VERSION 5.8 ;
BUSBITCHARS "[]" ;
DIVIDERCHAR "/" ;
UNITS
    DATABASE MICRONS 1000 ;
END UNITS

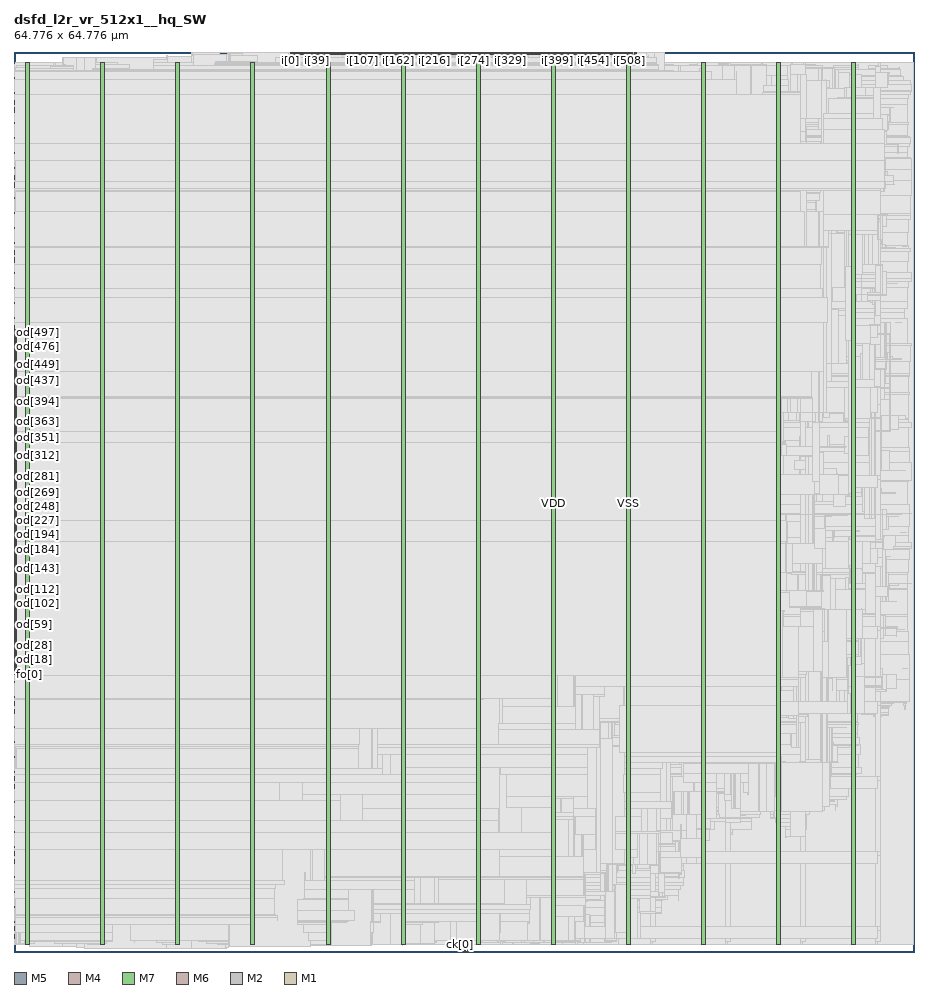
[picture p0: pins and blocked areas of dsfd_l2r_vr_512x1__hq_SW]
MACRO dsfd_l2r_vr_512x1__hq_SW
  FOREIGN dsfd_l2r_vr_512x1__hq_SW 0 0 ;
  CLASS BLOCK ;
  SIZE 64.776 BY 64.776 ;
  PIN ck[0]
    DIRECTION INPUT ;
    USE SIGNAL ;
    PORT
      LAYER M5 ;
        RECT  32.064 0 32.088 0.192 ;
    END
  END ck[0]
  PIN cks[0]
    DIRECTION INPUT ;
    USE SIGNAL ;
    PORT
      LAYER M5 ;
        RECT  32.256 0 32.28 0.192 ;
    END
  END cks[0]
  PIN fo[0]
    DIRECTION OUTPUT ;
    USE SIGNAL ;
    PORT
      LAYER M4 ;
        RECT  0 19.968 0.192 19.992 ;
    END
  END fo[0]
  PIN i[0]
    DIRECTION INPUT ;
    USE SIGNAL ;
    PORT
      LAYER M5 ;
        RECT  19.92 64.584 19.944 64.776 ;
    END
  END i[0]
  PIN i[100]
    DIRECTION INPUT ;
    USE SIGNAL ;
    PORT
      LAYER M5 ;
        RECT  24.72 64.584 24.744 64.776 ;
    END
  END i[100]
  PIN i[101]
    DIRECTION INPUT ;
    USE SIGNAL ;
    PORT
      LAYER M5 ;
        RECT  24.768 64.584 24.792 64.776 ;
    END
  END i[101]
  PIN i[102]
    DIRECTION INPUT ;
    USE SIGNAL ;
    PORT
      LAYER M5 ;
        RECT  24.816 64.584 24.84 64.776 ;
    END
  END i[102]
  PIN i[103]
    DIRECTION INPUT ;
    USE SIGNAL ;
    PORT
      LAYER M5 ;
        RECT  24.864 64.584 24.888 64.776 ;
    END
  END i[103]
  PIN i[104]
    DIRECTION INPUT ;
    USE SIGNAL ;
    PORT
      LAYER M5 ;
        RECT  24.912 64.584 24.936 64.776 ;
    END
  END i[104]
  PIN i[105]
    DIRECTION INPUT ;
    USE SIGNAL ;
    PORT
      LAYER M5 ;
        RECT  24.96 64.584 24.984 64.776 ;
    END
  END i[105]
  PIN i[106]
    DIRECTION INPUT ;
    USE SIGNAL ;
    PORT
      LAYER M5 ;
        RECT  25.008 64.584 25.032 64.776 ;
    END
  END i[106]
  PIN i[107]
    DIRECTION INPUT ;
    USE SIGNAL ;
    PORT
      LAYER M5 ;
        RECT  25.056 64.584 25.08 64.776 ;
    END
  END i[107]
  PIN i[108]
    DIRECTION INPUT ;
    USE SIGNAL ;
    PORT
      LAYER M5 ;
        RECT  25.104 64.584 25.128 64.776 ;
    END
  END i[108]
  PIN i[109]
    DIRECTION INPUT ;
    USE SIGNAL ;
    PORT
      LAYER M5 ;
        RECT  25.152 64.584 25.176 64.776 ;
    END
  END i[109]
  PIN i[10]
    DIRECTION INPUT ;
    USE SIGNAL ;
    PORT
      LAYER M5 ;
        RECT  20.4 64.584 20.424 64.776 ;
    END
  END i[10]
  PIN i[110]
    DIRECTION INPUT ;
    USE SIGNAL ;
    PORT
      LAYER M5 ;
        RECT  25.2 64.584 25.224 64.776 ;
    END
  END i[110]
  PIN i[111]
    DIRECTION INPUT ;
    USE SIGNAL ;
    PORT
      LAYER M5 ;
        RECT  25.248 64.584 25.272 64.776 ;
    END
  END i[111]
  PIN i[112]
    DIRECTION INPUT ;
    USE SIGNAL ;
    PORT
      LAYER M5 ;
        RECT  25.296 64.584 25.32 64.776 ;
    END
  END i[112]
  PIN i[113]
    DIRECTION INPUT ;
    USE SIGNAL ;
    PORT
      LAYER M5 ;
        RECT  25.344 64.584 25.368 64.776 ;
    END
  END i[113]
  PIN i[114]
    DIRECTION INPUT ;
    USE SIGNAL ;
    PORT
      LAYER M5 ;
        RECT  25.392 64.584 25.416 64.776 ;
    END
  END i[114]
  PIN i[115]
    DIRECTION INPUT ;
    USE SIGNAL ;
    PORT
      LAYER M5 ;
        RECT  25.44 64.584 25.464 64.776 ;
    END
  END i[115]
  PIN i[116]
    DIRECTION INPUT ;
    USE SIGNAL ;
    PORT
      LAYER M5 ;
        RECT  25.488 64.584 25.512 64.776 ;
    END
  END i[116]
  PIN i[117]
    DIRECTION INPUT ;
    USE SIGNAL ;
    PORT
      LAYER M5 ;
        RECT  25.536 64.584 25.56 64.776 ;
    END
  END i[117]
  PIN i[118]
    DIRECTION INPUT ;
    USE SIGNAL ;
    PORT
      LAYER M5 ;
        RECT  25.584 64.584 25.608 64.776 ;
    END
  END i[118]
  PIN i[119]
    DIRECTION INPUT ;
    USE SIGNAL ;
    PORT
      LAYER M5 ;
        RECT  25.632 64.584 25.656 64.776 ;
    END
  END i[119]
  PIN i[11]
    DIRECTION INPUT ;
    USE SIGNAL ;
    PORT
      LAYER M5 ;
        RECT  20.448 64.584 20.472 64.776 ;
    END
  END i[11]
  PIN i[120]
    DIRECTION INPUT ;
    USE SIGNAL ;
    PORT
      LAYER M5 ;
        RECT  25.68 64.584 25.704 64.776 ;
    END
  END i[120]
  PIN i[121]
    DIRECTION INPUT ;
    USE SIGNAL ;
    PORT
      LAYER M5 ;
        RECT  25.728 64.584 25.752 64.776 ;
    END
  END i[121]
  PIN i[122]
    DIRECTION INPUT ;
    USE SIGNAL ;
    PORT
      LAYER M5 ;
        RECT  25.776 64.584 25.8 64.776 ;
    END
  END i[122]
  PIN i[123]
    DIRECTION INPUT ;
    USE SIGNAL ;
    PORT
      LAYER M5 ;
        RECT  25.824 64.584 25.848 64.776 ;
    END
  END i[123]
  PIN i[124]
    DIRECTION INPUT ;
    USE SIGNAL ;
    PORT
      LAYER M5 ;
        RECT  25.872 64.584 25.896 64.776 ;
    END
  END i[124]
  PIN i[125]
    DIRECTION INPUT ;
    USE SIGNAL ;
    PORT
      LAYER M5 ;
        RECT  25.92 64.584 25.944 64.776 ;
    END
  END i[125]
  PIN i[126]
    DIRECTION INPUT ;
    USE SIGNAL ;
    PORT
      LAYER M5 ;
        RECT  25.968 64.584 25.992 64.776 ;
    END
  END i[126]
  PIN i[127]
    DIRECTION INPUT ;
    USE SIGNAL ;
    PORT
      LAYER M5 ;
        RECT  26.016 64.584 26.04 64.776 ;
    END
  END i[127]
  PIN i[128]
    DIRECTION INPUT ;
    USE SIGNAL ;
    PORT
      LAYER M5 ;
        RECT  26.064 64.584 26.088 64.776 ;
    END
  END i[128]
  PIN i[129]
    DIRECTION INPUT ;
    USE SIGNAL ;
    PORT
      LAYER M5 ;
        RECT  26.112 64.584 26.136 64.776 ;
    END
  END i[129]
  PIN i[12]
    DIRECTION INPUT ;
    USE SIGNAL ;
    PORT
      LAYER M5 ;
        RECT  20.496 64.584 20.52 64.776 ;
    END
  END i[12]
  PIN i[130]
    DIRECTION INPUT ;
    USE SIGNAL ;
    PORT
      LAYER M5 ;
        RECT  26.16 64.584 26.184 64.776 ;
    END
  END i[130]
  PIN i[131]
    DIRECTION INPUT ;
    USE SIGNAL ;
    PORT
      LAYER M5 ;
        RECT  26.208 64.584 26.232 64.776 ;
    END
  END i[131]
  PIN i[132]
    DIRECTION INPUT ;
    USE SIGNAL ;
    PORT
      LAYER M5 ;
        RECT  26.256 64.584 26.28 64.776 ;
    END
  END i[132]
  PIN i[133]
    DIRECTION INPUT ;
    USE SIGNAL ;
    PORT
      LAYER M5 ;
        RECT  26.304 64.584 26.328 64.776 ;
    END
  END i[133]
  PIN i[134]
    DIRECTION INPUT ;
    USE SIGNAL ;
    PORT
      LAYER M5 ;
        RECT  26.352 64.584 26.376 64.776 ;
    END
  END i[134]
  PIN i[135]
    DIRECTION INPUT ;
    USE SIGNAL ;
    PORT
      LAYER M5 ;
        RECT  26.4 64.584 26.424 64.776 ;
    END
  END i[135]
  PIN i[136]
    DIRECTION INPUT ;
    USE SIGNAL ;
    PORT
      LAYER M5 ;
        RECT  26.448 64.584 26.472 64.776 ;
    END
  END i[136]
  PIN i[137]
    DIRECTION INPUT ;
    USE SIGNAL ;
    PORT
      LAYER M5 ;
        RECT  26.496 64.584 26.52 64.776 ;
    END
  END i[137]
  PIN i[138]
    DIRECTION INPUT ;
    USE SIGNAL ;
    PORT
      LAYER M5 ;
        RECT  26.544 64.584 26.568 64.776 ;
    END
  END i[138]
  PIN i[139]
    DIRECTION INPUT ;
    USE SIGNAL ;
    PORT
      LAYER M5 ;
        RECT  26.592 64.584 26.616 64.776 ;
    END
  END i[139]
  PIN i[13]
    DIRECTION INPUT ;
    USE SIGNAL ;
    PORT
      LAYER M5 ;
        RECT  20.544 64.584 20.568 64.776 ;
    END
  END i[13]
  PIN i[140]
    DIRECTION INPUT ;
    USE SIGNAL ;
    PORT
      LAYER M5 ;
        RECT  26.64 64.584 26.664 64.776 ;
    END
  END i[140]
  PIN i[141]
    DIRECTION INPUT ;
    USE SIGNAL ;
    PORT
      LAYER M5 ;
        RECT  26.688 64.584 26.712 64.776 ;
    END
  END i[141]
  PIN i[142]
    DIRECTION INPUT ;
    USE SIGNAL ;
    PORT
      LAYER M5 ;
        RECT  26.736 64.584 26.76 64.776 ;
    END
  END i[142]
  PIN i[143]
    DIRECTION INPUT ;
    USE SIGNAL ;
    PORT
      LAYER M5 ;
        RECT  26.784 64.584 26.808 64.776 ;
    END
  END i[143]
  PIN i[144]
    DIRECTION INPUT ;
    USE SIGNAL ;
    PORT
      LAYER M5 ;
        RECT  26.832 64.584 26.856 64.776 ;
    END
  END i[144]
  PIN i[145]
    DIRECTION INPUT ;
    USE SIGNAL ;
    PORT
      LAYER M5 ;
        RECT  26.88 64.584 26.904 64.776 ;
    END
  END i[145]
  PIN i[146]
    DIRECTION INPUT ;
    USE SIGNAL ;
    PORT
      LAYER M5 ;
        RECT  26.928 64.584 26.952 64.776 ;
    END
  END i[146]
  PIN i[147]
    DIRECTION INPUT ;
    USE SIGNAL ;
    PORT
      LAYER M5 ;
        RECT  26.976 64.584 27 64.776 ;
    END
  END i[147]
  PIN i[148]
    DIRECTION INPUT ;
    USE SIGNAL ;
    PORT
      LAYER M5 ;
        RECT  27.024 64.584 27.048 64.776 ;
    END
  END i[148]
  PIN i[149]
    DIRECTION INPUT ;
    USE SIGNAL ;
    PORT
      LAYER M5 ;
        RECT  27.072 64.584 27.096 64.776 ;
    END
  END i[149]
  PIN i[14]
    DIRECTION INPUT ;
    USE SIGNAL ;
    PORT
      LAYER M5 ;
        RECT  20.592 64.584 20.616 64.776 ;
    END
  END i[14]
  PIN i[150]
    DIRECTION INPUT ;
    USE SIGNAL ;
    PORT
      LAYER M5 ;
        RECT  27.12 64.584 27.144 64.776 ;
    END
  END i[150]
  PIN i[151]
    DIRECTION INPUT ;
    USE SIGNAL ;
    PORT
      LAYER M5 ;
        RECT  27.168 64.584 27.192 64.776 ;
    END
  END i[151]
  PIN i[152]
    DIRECTION INPUT ;
    USE SIGNAL ;
    PORT
      LAYER M5 ;
        RECT  27.216 64.584 27.24 64.776 ;
    END
  END i[152]
  PIN i[153]
    DIRECTION INPUT ;
    USE SIGNAL ;
    PORT
      LAYER M5 ;
        RECT  27.264 64.584 27.288 64.776 ;
    END
  END i[153]
  PIN i[154]
    DIRECTION INPUT ;
    USE SIGNAL ;
    PORT
      LAYER M5 ;
        RECT  27.312 64.584 27.336 64.776 ;
    END
  END i[154]
  PIN i[155]
    DIRECTION INPUT ;
    USE SIGNAL ;
    PORT
      LAYER M5 ;
        RECT  27.36 64.584 27.384 64.776 ;
    END
  END i[155]
  PIN i[156]
    DIRECTION INPUT ;
    USE SIGNAL ;
    PORT
      LAYER M5 ;
        RECT  27.408 64.584 27.432 64.776 ;
    END
  END i[156]
  PIN i[157]
    DIRECTION INPUT ;
    USE SIGNAL ;
    PORT
      LAYER M5 ;
        RECT  27.456 64.584 27.48 64.776 ;
    END
  END i[157]
  PIN i[158]
    DIRECTION INPUT ;
    USE SIGNAL ;
    PORT
      LAYER M5 ;
        RECT  27.504 64.584 27.528 64.776 ;
    END
  END i[158]
  PIN i[159]
    DIRECTION INPUT ;
    USE SIGNAL ;
    PORT
      LAYER M5 ;
        RECT  27.552 64.584 27.576 64.776 ;
    END
  END i[159]
  PIN i[15]
    DIRECTION INPUT ;
    USE SIGNAL ;
    PORT
      LAYER M5 ;
        RECT  20.64 64.584 20.664 64.776 ;
    END
  END i[15]
  PIN i[160]
    DIRECTION INPUT ;
    USE SIGNAL ;
    PORT
      LAYER M5 ;
        RECT  27.6 64.584 27.624 64.776 ;
    END
  END i[160]
  PIN i[161]
    DIRECTION INPUT ;
    USE SIGNAL ;
    PORT
      LAYER M5 ;
        RECT  27.648 64.584 27.672 64.776 ;
    END
  END i[161]
  PIN i[162]
    DIRECTION INPUT ;
    USE SIGNAL ;
    PORT
      LAYER M5 ;
        RECT  27.696 64.584 27.72 64.776 ;
    END
  END i[162]
  PIN i[163]
    DIRECTION INPUT ;
    USE SIGNAL ;
    PORT
      LAYER M5 ;
        RECT  27.744 64.584 27.768 64.776 ;
    END
  END i[163]
  PIN i[164]
    DIRECTION INPUT ;
    USE SIGNAL ;
    PORT
      LAYER M5 ;
        RECT  27.792 64.584 27.816 64.776 ;
    END
  END i[164]
  PIN i[165]
    DIRECTION INPUT ;
    USE SIGNAL ;
    PORT
      LAYER M5 ;
        RECT  27.84 64.584 27.864 64.776 ;
    END
  END i[165]
  PIN i[166]
    DIRECTION INPUT ;
    USE SIGNAL ;
    PORT
      LAYER M5 ;
        RECT  27.888 64.584 27.912 64.776 ;
    END
  END i[166]
  PIN i[167]
    DIRECTION INPUT ;
    USE SIGNAL ;
    PORT
      LAYER M5 ;
        RECT  27.936 64.584 27.96 64.776 ;
    END
  END i[167]
  PIN i[168]
    DIRECTION INPUT ;
    USE SIGNAL ;
    PORT
      LAYER M5 ;
        RECT  27.984 64.584 28.008 64.776 ;
    END
  END i[168]
  PIN i[169]
    DIRECTION INPUT ;
    USE SIGNAL ;
    PORT
      LAYER M5 ;
        RECT  28.032 64.584 28.056 64.776 ;
    END
  END i[169]
  PIN i[16]
    DIRECTION INPUT ;
    USE SIGNAL ;
    PORT
      LAYER M5 ;
        RECT  20.688 64.584 20.712 64.776 ;
    END
  END i[16]
  PIN i[170]
    DIRECTION INPUT ;
    USE SIGNAL ;
    PORT
      LAYER M5 ;
        RECT  28.08 64.584 28.104 64.776 ;
    END
  END i[170]
  PIN i[171]
    DIRECTION INPUT ;
    USE SIGNAL ;
    PORT
      LAYER M5 ;
        RECT  28.128 64.584 28.152 64.776 ;
    END
  END i[171]
  PIN i[172]
    DIRECTION INPUT ;
    USE SIGNAL ;
    PORT
      LAYER M5 ;
        RECT  28.176 64.584 28.2 64.776 ;
    END
  END i[172]
  PIN i[173]
    DIRECTION INPUT ;
    USE SIGNAL ;
    PORT
      LAYER M5 ;
        RECT  28.224 64.584 28.248 64.776 ;
    END
  END i[173]
  PIN i[174]
    DIRECTION INPUT ;
    USE SIGNAL ;
    PORT
      LAYER M5 ;
        RECT  28.272 64.584 28.296 64.776 ;
    END
  END i[174]
  PIN i[175]
    DIRECTION INPUT ;
    USE SIGNAL ;
    PORT
      LAYER M5 ;
        RECT  28.32 64.584 28.344 64.776 ;
    END
  END i[175]
  PIN i[176]
    DIRECTION INPUT ;
    USE SIGNAL ;
    PORT
      LAYER M5 ;
        RECT  28.368 64.584 28.392 64.776 ;
    END
  END i[176]
  PIN i[177]
    DIRECTION INPUT ;
    USE SIGNAL ;
    PORT
      LAYER M5 ;
        RECT  28.416 64.584 28.44 64.776 ;
    END
  END i[177]
  PIN i[178]
    DIRECTION INPUT ;
    USE SIGNAL ;
    PORT
      LAYER M5 ;
        RECT  28.464 64.584 28.488 64.776 ;
    END
  END i[178]
  PIN i[179]
    DIRECTION INPUT ;
    USE SIGNAL ;
    PORT
      LAYER M5 ;
        RECT  28.512 64.584 28.536 64.776 ;
    END
  END i[179]
  PIN i[17]
    DIRECTION INPUT ;
    USE SIGNAL ;
    PORT
      LAYER M5 ;
        RECT  20.736 64.584 20.76 64.776 ;
    END
  END i[17]
  PIN i[180]
    DIRECTION INPUT ;
    USE SIGNAL ;
    PORT
      LAYER M5 ;
        RECT  28.56 64.584 28.584 64.776 ;
    END
  END i[180]
  PIN i[181]
    DIRECTION INPUT ;
    USE SIGNAL ;
    PORT
      LAYER M5 ;
        RECT  28.608 64.584 28.632 64.776 ;
    END
  END i[181]
  PIN i[182]
    DIRECTION INPUT ;
    USE SIGNAL ;
    PORT
      LAYER M5 ;
        RECT  28.656 64.584 28.68 64.776 ;
    END
  END i[182]
  PIN i[183]
    DIRECTION INPUT ;
    USE SIGNAL ;
    PORT
      LAYER M5 ;
        RECT  28.704 64.584 28.728 64.776 ;
    END
  END i[183]
  PIN i[184]
    DIRECTION INPUT ;
    USE SIGNAL ;
    PORT
      LAYER M5 ;
        RECT  28.752 64.584 28.776 64.776 ;
    END
  END i[184]
  PIN i[185]
    DIRECTION INPUT ;
    USE SIGNAL ;
    PORT
      LAYER M5 ;
        RECT  28.8 64.584 28.824 64.776 ;
    END
  END i[185]
  PIN i[186]
    DIRECTION INPUT ;
    USE SIGNAL ;
    PORT
      LAYER M5 ;
        RECT  28.848 64.584 28.872 64.776 ;
    END
  END i[186]
  PIN i[187]
    DIRECTION INPUT ;
    USE SIGNAL ;
    PORT
      LAYER M5 ;
        RECT  28.896 64.584 28.92 64.776 ;
    END
  END i[187]
  PIN i[188]
    DIRECTION INPUT ;
    USE SIGNAL ;
    PORT
      LAYER M5 ;
        RECT  28.944 64.584 28.968 64.776 ;
    END
  END i[188]
  PIN i[189]
    DIRECTION INPUT ;
    USE SIGNAL ;
    PORT
      LAYER M5 ;
        RECT  28.992 64.584 29.016 64.776 ;
    END
  END i[189]
  PIN i[18]
    DIRECTION INPUT ;
    USE SIGNAL ;
    PORT
      LAYER M5 ;
        RECT  20.784 64.584 20.808 64.776 ;
    END
  END i[18]
  PIN i[190]
    DIRECTION INPUT ;
    USE SIGNAL ;
    PORT
      LAYER M5 ;
        RECT  29.04 64.584 29.064 64.776 ;
    END
  END i[190]
  PIN i[191]
    DIRECTION INPUT ;
    USE SIGNAL ;
    PORT
      LAYER M5 ;
        RECT  29.088 64.584 29.112 64.776 ;
    END
  END i[191]
  PIN i[192]
    DIRECTION INPUT ;
    USE SIGNAL ;
    PORT
      LAYER M5 ;
        RECT  29.136 64.584 29.16 64.776 ;
    END
  END i[192]
  PIN i[193]
    DIRECTION INPUT ;
    USE SIGNAL ;
    PORT
      LAYER M5 ;
        RECT  29.184 64.584 29.208 64.776 ;
    END
  END i[193]
  PIN i[194]
    DIRECTION INPUT ;
    USE SIGNAL ;
    PORT
      LAYER M5 ;
        RECT  29.232 64.584 29.256 64.776 ;
    END
  END i[194]
  PIN i[195]
    DIRECTION INPUT ;
    USE SIGNAL ;
    PORT
      LAYER M5 ;
        RECT  29.28 64.584 29.304 64.776 ;
    END
  END i[195]
  PIN i[196]
    DIRECTION INPUT ;
    USE SIGNAL ;
    PORT
      LAYER M5 ;
        RECT  29.328 64.584 29.352 64.776 ;
    END
  END i[196]
  PIN i[197]
    DIRECTION INPUT ;
    USE SIGNAL ;
    PORT
      LAYER M5 ;
        RECT  29.376 64.584 29.4 64.776 ;
    END
  END i[197]
  PIN i[198]
    DIRECTION INPUT ;
    USE SIGNAL ;
    PORT
      LAYER M5 ;
        RECT  29.424 64.584 29.448 64.776 ;
    END
  END i[198]
  PIN i[199]
    DIRECTION INPUT ;
    USE SIGNAL ;
    PORT
      LAYER M5 ;
        RECT  29.472 64.584 29.496 64.776 ;
    END
  END i[199]
  PIN i[19]
    DIRECTION INPUT ;
    USE SIGNAL ;
    PORT
      LAYER M5 ;
        RECT  20.832 64.584 20.856 64.776 ;
    END
  END i[19]
  PIN i[1]
    DIRECTION INPUT ;
    USE SIGNAL ;
    PORT
      LAYER M5 ;
        RECT  19.968 64.584 19.992 64.776 ;
    END
  END i[1]
  PIN i[200]
    DIRECTION INPUT ;
    USE SIGNAL ;
    PORT
      LAYER M5 ;
        RECT  29.52 64.584 29.544 64.776 ;
    END
  END i[200]
  PIN i[201]
    DIRECTION INPUT ;
    USE SIGNAL ;
    PORT
      LAYER M5 ;
        RECT  29.568 64.584 29.592 64.776 ;
    END
  END i[201]
  PIN i[202]
    DIRECTION INPUT ;
    USE SIGNAL ;
    PORT
      LAYER M5 ;
        RECT  29.616 64.584 29.64 64.776 ;
    END
  END i[202]
  PIN i[203]
    DIRECTION INPUT ;
    USE SIGNAL ;
    PORT
      LAYER M5 ;
        RECT  29.664 64.584 29.688 64.776 ;
    END
  END i[203]
  PIN i[204]
    DIRECTION INPUT ;
    USE SIGNAL ;
    PORT
      LAYER M5 ;
        RECT  29.712 64.584 29.736 64.776 ;
    END
  END i[204]
  PIN i[205]
    DIRECTION INPUT ;
    USE SIGNAL ;
    PORT
      LAYER M5 ;
        RECT  29.76 64.584 29.784 64.776 ;
    END
  END i[205]
  PIN i[206]
    DIRECTION INPUT ;
    USE SIGNAL ;
    PORT
      LAYER M5 ;
        RECT  29.808 64.584 29.832 64.776 ;
    END
  END i[206]
  PIN i[207]
    DIRECTION INPUT ;
    USE SIGNAL ;
    PORT
      LAYER M5 ;
        RECT  29.856 64.584 29.88 64.776 ;
    END
  END i[207]
  PIN i[208]
    DIRECTION INPUT ;
    USE SIGNAL ;
    PORT
      LAYER M5 ;
        RECT  29.904 64.584 29.928 64.776 ;
    END
  END i[208]
  PIN i[209]
    DIRECTION INPUT ;
    USE SIGNAL ;
    PORT
      LAYER M5 ;
        RECT  29.952 64.584 29.976 64.776 ;
    END
  END i[209]
  PIN i[20]
    DIRECTION INPUT ;
    USE SIGNAL ;
    PORT
      LAYER M5 ;
        RECT  20.88 64.584 20.904 64.776 ;
    END
  END i[20]
  PIN i[210]
    DIRECTION INPUT ;
    USE SIGNAL ;
    PORT
      LAYER M5 ;
        RECT  30 64.584 30.024 64.776 ;
    END
  END i[210]
  PIN i[211]
    DIRECTION INPUT ;
    USE SIGNAL ;
    PORT
      LAYER M5 ;
        RECT  30.048 64.584 30.072 64.776 ;
    END
  END i[211]
  PIN i[212]
    DIRECTION INPUT ;
    USE SIGNAL ;
    PORT
      LAYER M5 ;
        RECT  30.096 64.584 30.12 64.776 ;
    END
  END i[212]
  PIN i[213]
    DIRECTION INPUT ;
    USE SIGNAL ;
    PORT
      LAYER M5 ;
        RECT  30.144 64.584 30.168 64.776 ;
    END
  END i[213]
  PIN i[214]
    DIRECTION INPUT ;
    USE SIGNAL ;
    PORT
      LAYER M5 ;
        RECT  30.192 64.584 30.216 64.776 ;
    END
  END i[214]
  PIN i[215]
    DIRECTION INPUT ;
    USE SIGNAL ;
    PORT
      LAYER M5 ;
        RECT  30.24 64.584 30.264 64.776 ;
    END
  END i[215]
  PIN i[216]
    DIRECTION INPUT ;
    USE SIGNAL ;
    PORT
      LAYER M5 ;
        RECT  30.288 64.584 30.312 64.776 ;
    END
  END i[216]
  PIN i[217]
    DIRECTION INPUT ;
    USE SIGNAL ;
    PORT
      LAYER M5 ;
        RECT  30.336 64.584 30.36 64.776 ;
    END
  END i[217]
  PIN i[218]
    DIRECTION INPUT ;
    USE SIGNAL ;
    PORT
      LAYER M5 ;
        RECT  30.384 64.584 30.408 64.776 ;
    END
  END i[218]
  PIN i[219]
    DIRECTION INPUT ;
    USE SIGNAL ;
    PORT
      LAYER M5 ;
        RECT  30.432 64.584 30.456 64.776 ;
    END
  END i[219]
  PIN i[21]
    DIRECTION INPUT ;
    USE SIGNAL ;
    PORT
      LAYER M5 ;
        RECT  20.928 64.584 20.952 64.776 ;
    END
  END i[21]
  PIN i[220]
    DIRECTION INPUT ;
    USE SIGNAL ;
    PORT
      LAYER M5 ;
        RECT  30.48 64.584 30.504 64.776 ;
    END
  END i[220]
  PIN i[221]
    DIRECTION INPUT ;
    USE SIGNAL ;
    PORT
      LAYER M5 ;
        RECT  30.528 64.584 30.552 64.776 ;
    END
  END i[221]
  PIN i[222]
    DIRECTION INPUT ;
    USE SIGNAL ;
    PORT
      LAYER M5 ;
        RECT  30.576 64.584 30.6 64.776 ;
    END
  END i[222]
  PIN i[223]
    DIRECTION INPUT ;
    USE SIGNAL ;
    PORT
      LAYER M5 ;
        RECT  30.624 64.584 30.648 64.776 ;
    END
  END i[223]
  PIN i[224]
    DIRECTION INPUT ;
    USE SIGNAL ;
    PORT
      LAYER M5 ;
        RECT  30.672 64.584 30.696 64.776 ;
    END
  END i[224]
  PIN i[225]
    DIRECTION INPUT ;
    USE SIGNAL ;
    PORT
      LAYER M5 ;
        RECT  30.72 64.584 30.744 64.776 ;
    END
  END i[225]
  PIN i[226]
    DIRECTION INPUT ;
    USE SIGNAL ;
    PORT
      LAYER M5 ;
        RECT  30.768 64.584 30.792 64.776 ;
    END
  END i[226]
  PIN i[227]
    DIRECTION INPUT ;
    USE SIGNAL ;
    PORT
      LAYER M5 ;
        RECT  30.816 64.584 30.84 64.776 ;
    END
  END i[227]
  PIN i[228]
    DIRECTION INPUT ;
    USE SIGNAL ;
    PORT
      LAYER M5 ;
        RECT  30.864 64.584 30.888 64.776 ;
    END
  END i[228]
  PIN i[229]
    DIRECTION INPUT ;
    USE SIGNAL ;
    PORT
      LAYER M5 ;
        RECT  30.912 64.584 30.936 64.776 ;
    END
  END i[229]
  PIN i[22]
    DIRECTION INPUT ;
    USE SIGNAL ;
    PORT
      LAYER M5 ;
        RECT  20.976 64.584 21 64.776 ;
    END
  END i[22]
  PIN i[230]
    DIRECTION INPUT ;
    USE SIGNAL ;
    PORT
      LAYER M5 ;
        RECT  30.96 64.584 30.984 64.776 ;
    END
  END i[230]
  PIN i[231]
    DIRECTION INPUT ;
    USE SIGNAL ;
    PORT
      LAYER M5 ;
        RECT  31.008 64.584 31.032 64.776 ;
    END
  END i[231]
  PIN i[232]
    DIRECTION INPUT ;
    USE SIGNAL ;
    PORT
      LAYER M5 ;
        RECT  31.056 64.584 31.08 64.776 ;
    END
  END i[232]
  PIN i[233]
    DIRECTION INPUT ;
    USE SIGNAL ;
    PORT
      LAYER M5 ;
        RECT  31.104 64.584 31.128 64.776 ;
    END
  END i[233]
  PIN i[234]
    DIRECTION INPUT ;
    USE SIGNAL ;
    PORT
      LAYER M5 ;
        RECT  31.152 64.584 31.176 64.776 ;
    END
  END i[234]
  PIN i[235]
    DIRECTION INPUT ;
    USE SIGNAL ;
    PORT
      LAYER M5 ;
        RECT  31.2 64.584 31.224 64.776 ;
    END
  END i[235]
  PIN i[236]
    DIRECTION INPUT ;
    USE SIGNAL ;
    PORT
      LAYER M5 ;
        RECT  31.248 64.584 31.272 64.776 ;
    END
  END i[236]
  PIN i[237]
    DIRECTION INPUT ;
    USE SIGNAL ;
    PORT
      LAYER M5 ;
        RECT  31.296 64.584 31.32 64.776 ;
    END
  END i[237]
  PIN i[238]
    DIRECTION INPUT ;
    USE SIGNAL ;
    PORT
      LAYER M5 ;
        RECT  31.344 64.584 31.368 64.776 ;
    END
  END i[238]
  PIN i[239]
    DIRECTION INPUT ;
    USE SIGNAL ;
    PORT
      LAYER M5 ;
        RECT  31.392 64.584 31.416 64.776 ;
    END
  END i[239]
  PIN i[23]
    DIRECTION INPUT ;
    USE SIGNAL ;
    PORT
      LAYER M5 ;
        RECT  21.024 64.584 21.048 64.776 ;
    END
  END i[23]
  PIN i[240]
    DIRECTION INPUT ;
    USE SIGNAL ;
    PORT
      LAYER M5 ;
        RECT  31.44 64.584 31.464 64.776 ;
    END
  END i[240]
  PIN i[241]
    DIRECTION INPUT ;
    USE SIGNAL ;
    PORT
      LAYER M5 ;
        RECT  31.488 64.584 31.512 64.776 ;
    END
  END i[241]
  PIN i[242]
    DIRECTION INPUT ;
    USE SIGNAL ;
    PORT
      LAYER M5 ;
        RECT  31.536 64.584 31.56 64.776 ;
    END
  END i[242]
  PIN i[243]
    DIRECTION INPUT ;
    USE SIGNAL ;
    PORT
      LAYER M5 ;
        RECT  31.584 64.584 31.608 64.776 ;
    END
  END i[243]
  PIN i[244]
    DIRECTION INPUT ;
    USE SIGNAL ;
    PORT
      LAYER M5 ;
        RECT  31.632 64.584 31.656 64.776 ;
    END
  END i[244]
  PIN i[245]
    DIRECTION INPUT ;
    USE SIGNAL ;
    PORT
      LAYER M5 ;
        RECT  31.68 64.584 31.704 64.776 ;
    END
  END i[245]
  PIN i[246]
    DIRECTION INPUT ;
    USE SIGNAL ;
    PORT
      LAYER M5 ;
        RECT  31.728 64.584 31.752 64.776 ;
    END
  END i[246]
  PIN i[247]
    DIRECTION INPUT ;
    USE SIGNAL ;
    PORT
      LAYER M5 ;
        RECT  31.776 64.584 31.8 64.776 ;
    END
  END i[247]
  PIN i[248]
    DIRECTION INPUT ;
    USE SIGNAL ;
    PORT
      LAYER M5 ;
        RECT  31.824 64.584 31.848 64.776 ;
    END
  END i[248]
  PIN i[249]
    DIRECTION INPUT ;
    USE SIGNAL ;
    PORT
      LAYER M5 ;
        RECT  31.872 64.584 31.896 64.776 ;
    END
  END i[249]
  PIN i[24]
    DIRECTION INPUT ;
    USE SIGNAL ;
    PORT
      LAYER M5 ;
        RECT  21.072 64.584 21.096 64.776 ;
    END
  END i[24]
  PIN i[250]
    DIRECTION INPUT ;
    USE SIGNAL ;
    PORT
      LAYER M5 ;
        RECT  31.92 64.584 31.944 64.776 ;
    END
  END i[250]
  PIN i[251]
    DIRECTION INPUT ;
    USE SIGNAL ;
    PORT
      LAYER M5 ;
        RECT  31.968 64.584 31.992 64.776 ;
    END
  END i[251]
  PIN i[252]
    DIRECTION INPUT ;
    USE SIGNAL ;
    PORT
      LAYER M5 ;
        RECT  32.016 64.584 32.04 64.776 ;
    END
  END i[252]
  PIN i[253]
    DIRECTION INPUT ;
    USE SIGNAL ;
    PORT
      LAYER M5 ;
        RECT  32.064 64.584 32.088 64.776 ;
    END
  END i[253]
  PIN i[254]
    DIRECTION INPUT ;
    USE SIGNAL ;
    PORT
      LAYER M5 ;
        RECT  32.112 64.584 32.136 64.776 ;
    END
  END i[254]
  PIN i[255]
    DIRECTION INPUT ;
    USE SIGNAL ;
    PORT
      LAYER M5 ;
        RECT  32.16 64.584 32.184 64.776 ;
    END
  END i[255]
  PIN i[256]
    DIRECTION INPUT ;
    USE SIGNAL ;
    PORT
      LAYER M5 ;
        RECT  32.208 64.584 32.232 64.776 ;
    END
  END i[256]
  PIN i[257]
    DIRECTION INPUT ;
    USE SIGNAL ;
    PORT
      LAYER M5 ;
        RECT  32.256 64.584 32.28 64.776 ;
    END
  END i[257]
  PIN i[258]
    DIRECTION INPUT ;
    USE SIGNAL ;
    PORT
      LAYER M5 ;
        RECT  32.304 64.584 32.328 64.776 ;
    END
  END i[258]
  PIN i[259]
    DIRECTION INPUT ;
    USE SIGNAL ;
    PORT
      LAYER M5 ;
        RECT  32.352 64.584 32.376 64.776 ;
    END
  END i[259]
  PIN i[25]
    DIRECTION INPUT ;
    USE SIGNAL ;
    PORT
      LAYER M5 ;
        RECT  21.12 64.584 21.144 64.776 ;
    END
  END i[25]
  PIN i[260]
    DIRECTION INPUT ;
    USE SIGNAL ;
    PORT
      LAYER M5 ;
        RECT  32.4 64.584 32.424 64.776 ;
    END
  END i[260]
  PIN i[261]
    DIRECTION INPUT ;
    USE SIGNAL ;
    PORT
      LAYER M5 ;
        RECT  32.448 64.584 32.472 64.776 ;
    END
  END i[261]
  PIN i[262]
    DIRECTION INPUT ;
    USE SIGNAL ;
    PORT
      LAYER M5 ;
        RECT  32.496 64.584 32.52 64.776 ;
    END
  END i[262]
  PIN i[263]
    DIRECTION INPUT ;
    USE SIGNAL ;
    PORT
      LAYER M5 ;
        RECT  32.544 64.584 32.568 64.776 ;
    END
  END i[263]
  PIN i[264]
    DIRECTION INPUT ;
    USE SIGNAL ;
    PORT
      LAYER M5 ;
        RECT  32.592 64.584 32.616 64.776 ;
    END
  END i[264]
  PIN i[265]
    DIRECTION INPUT ;
    USE SIGNAL ;
    PORT
      LAYER M5 ;
        RECT  32.64 64.584 32.664 64.776 ;
    END
  END i[265]
  PIN i[266]
    DIRECTION INPUT ;
    USE SIGNAL ;
    PORT
      LAYER M5 ;
        RECT  32.688 64.584 32.712 64.776 ;
    END
  END i[266]
  PIN i[267]
    DIRECTION INPUT ;
    USE SIGNAL ;
    PORT
      LAYER M5 ;
        RECT  32.736 64.584 32.76 64.776 ;
    END
  END i[267]
  PIN i[268]
    DIRECTION INPUT ;
    USE SIGNAL ;
    PORT
      LAYER M5 ;
        RECT  32.784 64.584 32.808 64.776 ;
    END
  END i[268]
  PIN i[269]
    DIRECTION INPUT ;
    USE SIGNAL ;
    PORT
      LAYER M5 ;
        RECT  32.832 64.584 32.856 64.776 ;
    END
  END i[269]
  PIN i[26]
    DIRECTION INPUT ;
    USE SIGNAL ;
    PORT
      LAYER M5 ;
        RECT  21.168 64.584 21.192 64.776 ;
    END
  END i[26]
  PIN i[270]
    DIRECTION INPUT ;
    USE SIGNAL ;
    PORT
      LAYER M5 ;
        RECT  32.88 64.584 32.904 64.776 ;
    END
  END i[270]
  PIN i[271]
    DIRECTION INPUT ;
    USE SIGNAL ;
    PORT
      LAYER M5 ;
        RECT  32.928 64.584 32.952 64.776 ;
    END
  END i[271]
  PIN i[272]
    DIRECTION INPUT ;
    USE SIGNAL ;
    PORT
      LAYER M5 ;
        RECT  32.976 64.584 33 64.776 ;
    END
  END i[272]
  PIN i[273]
    DIRECTION INPUT ;
    USE SIGNAL ;
    PORT
      LAYER M5 ;
        RECT  33.024 64.584 33.048 64.776 ;
    END
  END i[273]
  PIN i[274]
    DIRECTION INPUT ;
    USE SIGNAL ;
    PORT
      LAYER M5 ;
        RECT  33.072 64.584 33.096 64.776 ;
    END
  END i[274]
  PIN i[275]
    DIRECTION INPUT ;
    USE SIGNAL ;
    PORT
      LAYER M5 ;
        RECT  33.12 64.584 33.144 64.776 ;
    END
  END i[275]
  PIN i[276]
    DIRECTION INPUT ;
    USE SIGNAL ;
    PORT
      LAYER M5 ;
        RECT  33.168 64.584 33.192 64.776 ;
    END
  END i[276]
  PIN i[277]
    DIRECTION INPUT ;
    USE SIGNAL ;
    PORT
      LAYER M5 ;
        RECT  33.216 64.584 33.24 64.776 ;
    END
  END i[277]
  PIN i[278]
    DIRECTION INPUT ;
    USE SIGNAL ;
    PORT
      LAYER M5 ;
        RECT  33.264 64.584 33.288 64.776 ;
    END
  END i[278]
  PIN i[279]
    DIRECTION INPUT ;
    USE SIGNAL ;
    PORT
      LAYER M5 ;
        RECT  33.312 64.584 33.336 64.776 ;
    END
  END i[279]
  PIN i[27]
    DIRECTION INPUT ;
    USE SIGNAL ;
    PORT
      LAYER M5 ;
        RECT  21.216 64.584 21.24 64.776 ;
    END
  END i[27]
  PIN i[280]
    DIRECTION INPUT ;
    USE SIGNAL ;
    PORT
      LAYER M5 ;
        RECT  33.36 64.584 33.384 64.776 ;
    END
  END i[280]
  PIN i[281]
    DIRECTION INPUT ;
    USE SIGNAL ;
    PORT
      LAYER M5 ;
        RECT  33.408 64.584 33.432 64.776 ;
    END
  END i[281]
  PIN i[282]
    DIRECTION INPUT ;
    USE SIGNAL ;
    PORT
      LAYER M5 ;
        RECT  33.456 64.584 33.48 64.776 ;
    END
  END i[282]
  PIN i[283]
    DIRECTION INPUT ;
    USE SIGNAL ;
    PORT
      LAYER M5 ;
        RECT  33.504 64.584 33.528 64.776 ;
    END
  END i[283]
  PIN i[284]
    DIRECTION INPUT ;
    USE SIGNAL ;
    PORT
      LAYER M5 ;
        RECT  33.552 64.584 33.576 64.776 ;
    END
  END i[284]
  PIN i[285]
    DIRECTION INPUT ;
    USE SIGNAL ;
    PORT
      LAYER M5 ;
        RECT  33.6 64.584 33.624 64.776 ;
    END
  END i[285]
  PIN i[286]
    DIRECTION INPUT ;
    USE SIGNAL ;
    PORT
      LAYER M5 ;
        RECT  33.648 64.584 33.672 64.776 ;
    END
  END i[286]
  PIN i[287]
    DIRECTION INPUT ;
    USE SIGNAL ;
    PORT
      LAYER M5 ;
        RECT  33.696 64.584 33.72 64.776 ;
    END
  END i[287]
  PIN i[288]
    DIRECTION INPUT ;
    USE SIGNAL ;
    PORT
      LAYER M5 ;
        RECT  33.744 64.584 33.768 64.776 ;
    END
  END i[288]
  PIN i[289]
    DIRECTION INPUT ;
    USE SIGNAL ;
    PORT
      LAYER M5 ;
        RECT  33.792 64.584 33.816 64.776 ;
    END
  END i[289]
  PIN i[28]
    DIRECTION INPUT ;
    USE SIGNAL ;
    PORT
      LAYER M5 ;
        RECT  21.264 64.584 21.288 64.776 ;
    END
  END i[28]
  PIN i[290]
    DIRECTION INPUT ;
    USE SIGNAL ;
    PORT
      LAYER M5 ;
        RECT  33.84 64.584 33.864 64.776 ;
    END
  END i[290]
  PIN i[291]
    DIRECTION INPUT ;
    USE SIGNAL ;
    PORT
      LAYER M5 ;
        RECT  33.888 64.584 33.912 64.776 ;
    END
  END i[291]
  PIN i[292]
    DIRECTION INPUT ;
    USE SIGNAL ;
    PORT
      LAYER M5 ;
        RECT  33.936 64.584 33.96 64.776 ;
    END
  END i[292]
  PIN i[293]
    DIRECTION INPUT ;
    USE SIGNAL ;
    PORT
      LAYER M5 ;
        RECT  33.984 64.584 34.008 64.776 ;
    END
  END i[293]
  PIN i[294]
    DIRECTION INPUT ;
    USE SIGNAL ;
    PORT
      LAYER M5 ;
        RECT  34.032 64.584 34.056 64.776 ;
    END
  END i[294]
  PIN i[295]
    DIRECTION INPUT ;
    USE SIGNAL ;
    PORT
      LAYER M5 ;
        RECT  34.08 64.584 34.104 64.776 ;
    END
  END i[295]
  PIN i[296]
    DIRECTION INPUT ;
    USE SIGNAL ;
    PORT
      LAYER M5 ;
        RECT  34.128 64.584 34.152 64.776 ;
    END
  END i[296]
  PIN i[297]
    DIRECTION INPUT ;
    USE SIGNAL ;
    PORT
      LAYER M5 ;
        RECT  34.176 64.584 34.2 64.776 ;
    END
  END i[297]
  PIN i[298]
    DIRECTION INPUT ;
    USE SIGNAL ;
    PORT
      LAYER M5 ;
        RECT  34.224 64.584 34.248 64.776 ;
    END
  END i[298]
  PIN i[299]
    DIRECTION INPUT ;
    USE SIGNAL ;
    PORT
      LAYER M5 ;
        RECT  34.272 64.584 34.296 64.776 ;
    END
  END i[299]
  PIN i[29]
    DIRECTION INPUT ;
    USE SIGNAL ;
    PORT
      LAYER M5 ;
        RECT  21.312 64.584 21.336 64.776 ;
    END
  END i[29]
  PIN i[2]
    DIRECTION INPUT ;
    USE SIGNAL ;
    PORT
      LAYER M5 ;
        RECT  20.016 64.584 20.04 64.776 ;
    END
  END i[2]
  PIN i[300]
    DIRECTION INPUT ;
    USE SIGNAL ;
    PORT
      LAYER M5 ;
        RECT  34.32 64.584 34.344 64.776 ;
    END
  END i[300]
  PIN i[301]
    DIRECTION INPUT ;
    USE SIGNAL ;
    PORT
      LAYER M5 ;
        RECT  34.368 64.584 34.392 64.776 ;
    END
  END i[301]
  PIN i[302]
    DIRECTION INPUT ;
    USE SIGNAL ;
    PORT
      LAYER M5 ;
        RECT  34.416 64.584 34.44 64.776 ;
    END
  END i[302]
  PIN i[303]
    DIRECTION INPUT ;
    USE SIGNAL ;
    PORT
      LAYER M5 ;
        RECT  34.464 64.584 34.488 64.776 ;
    END
  END i[303]
  PIN i[304]
    DIRECTION INPUT ;
    USE SIGNAL ;
    PORT
      LAYER M5 ;
        RECT  34.512 64.584 34.536 64.776 ;
    END
  END i[304]
  PIN i[305]
    DIRECTION INPUT ;
    USE SIGNAL ;
    PORT
      LAYER M5 ;
        RECT  34.56 64.584 34.584 64.776 ;
    END
  END i[305]
  PIN i[306]
    DIRECTION INPUT ;
    USE SIGNAL ;
    PORT
      LAYER M5 ;
        RECT  34.608 64.584 34.632 64.776 ;
    END
  END i[306]
  PIN i[307]
    DIRECTION INPUT ;
    USE SIGNAL ;
    PORT
      LAYER M5 ;
        RECT  34.656 64.584 34.68 64.776 ;
    END
  END i[307]
  PIN i[308]
    DIRECTION INPUT ;
    USE SIGNAL ;
    PORT
      LAYER M5 ;
        RECT  34.704 64.584 34.728 64.776 ;
    END
  END i[308]
  PIN i[309]
    DIRECTION INPUT ;
    USE SIGNAL ;
    PORT
      LAYER M5 ;
        RECT  34.752 64.584 34.776 64.776 ;
    END
  END i[309]
  PIN i[30]
    DIRECTION INPUT ;
    USE SIGNAL ;
    PORT
      LAYER M5 ;
        RECT  21.36 64.584 21.384 64.776 ;
    END
  END i[30]
  PIN i[310]
    DIRECTION INPUT ;
    USE SIGNAL ;
    PORT
      LAYER M5 ;
        RECT  34.8 64.584 34.824 64.776 ;
    END
  END i[310]
  PIN i[311]
    DIRECTION INPUT ;
    USE SIGNAL ;
    PORT
      LAYER M5 ;
        RECT  34.848 64.584 34.872 64.776 ;
    END
  END i[311]
  PIN i[312]
    DIRECTION INPUT ;
    USE SIGNAL ;
    PORT
      LAYER M5 ;
        RECT  34.896 64.584 34.92 64.776 ;
    END
  END i[312]
  PIN i[313]
    DIRECTION INPUT ;
    USE SIGNAL ;
    PORT
      LAYER M5 ;
        RECT  34.944 64.584 34.968 64.776 ;
    END
  END i[313]
  PIN i[314]
    DIRECTION INPUT ;
    USE SIGNAL ;
    PORT
      LAYER M5 ;
        RECT  34.992 64.584 35.016 64.776 ;
    END
  END i[314]
  PIN i[315]
    DIRECTION INPUT ;
    USE SIGNAL ;
    PORT
      LAYER M5 ;
        RECT  35.04 64.584 35.064 64.776 ;
    END
  END i[315]
  PIN i[316]
    DIRECTION INPUT ;
    USE SIGNAL ;
    PORT
      LAYER M5 ;
        RECT  35.088 64.584 35.112 64.776 ;
    END
  END i[316]
  PIN i[317]
    DIRECTION INPUT ;
    USE SIGNAL ;
    PORT
      LAYER M5 ;
        RECT  35.136 64.584 35.16 64.776 ;
    END
  END i[317]
  PIN i[318]
    DIRECTION INPUT ;
    USE SIGNAL ;
    PORT
      LAYER M5 ;
        RECT  35.184 64.584 35.208 64.776 ;
    END
  END i[318]
  PIN i[319]
    DIRECTION INPUT ;
    USE SIGNAL ;
    PORT
      LAYER M5 ;
        RECT  35.232 64.584 35.256 64.776 ;
    END
  END i[319]
  PIN i[31]
    DIRECTION INPUT ;
    USE SIGNAL ;
    PORT
      LAYER M5 ;
        RECT  21.408 64.584 21.432 64.776 ;
    END
  END i[31]
  PIN i[320]
    DIRECTION INPUT ;
    USE SIGNAL ;
    PORT
      LAYER M5 ;
        RECT  35.28 64.584 35.304 64.776 ;
    END
  END i[320]
  PIN i[321]
    DIRECTION INPUT ;
    USE SIGNAL ;
    PORT
      LAYER M5 ;
        RECT  35.328 64.584 35.352 64.776 ;
    END
  END i[321]
  PIN i[322]
    DIRECTION INPUT ;
    USE SIGNAL ;
    PORT
      LAYER M5 ;
        RECT  35.376 64.584 35.4 64.776 ;
    END
  END i[322]
  PIN i[323]
    DIRECTION INPUT ;
    USE SIGNAL ;
    PORT
      LAYER M5 ;
        RECT  35.424 64.584 35.448 64.776 ;
    END
  END i[323]
  PIN i[324]
    DIRECTION INPUT ;
    USE SIGNAL ;
    PORT
      LAYER M5 ;
        RECT  35.472 64.584 35.496 64.776 ;
    END
  END i[324]
  PIN i[325]
    DIRECTION INPUT ;
    USE SIGNAL ;
    PORT
      LAYER M5 ;
        RECT  35.52 64.584 35.544 64.776 ;
    END
  END i[325]
  PIN i[326]
    DIRECTION INPUT ;
    USE SIGNAL ;
    PORT
      LAYER M5 ;
        RECT  35.568 64.584 35.592 64.776 ;
    END
  END i[326]
  PIN i[327]
    DIRECTION INPUT ;
    USE SIGNAL ;
    PORT
      LAYER M5 ;
        RECT  35.616 64.584 35.64 64.776 ;
    END
  END i[327]
  PIN i[328]
    DIRECTION INPUT ;
    USE SIGNAL ;
    PORT
      LAYER M5 ;
        RECT  35.664 64.584 35.688 64.776 ;
    END
  END i[328]
  PIN i[329]
    DIRECTION INPUT ;
    USE SIGNAL ;
    PORT
      LAYER M5 ;
        RECT  35.712 64.584 35.736 64.776 ;
    END
  END i[329]
  PIN i[32]
    DIRECTION INPUT ;
    USE SIGNAL ;
    PORT
      LAYER M5 ;
        RECT  21.456 64.584 21.48 64.776 ;
    END
  END i[32]
  PIN i[330]
    DIRECTION INPUT ;
    USE SIGNAL ;
    PORT
      LAYER M5 ;
        RECT  35.76 64.584 35.784 64.776 ;
    END
  END i[330]
  PIN i[331]
    DIRECTION INPUT ;
    USE SIGNAL ;
    PORT
      LAYER M5 ;
        RECT  35.808 64.584 35.832 64.776 ;
    END
  END i[331]
  PIN i[332]
    DIRECTION INPUT ;
    USE SIGNAL ;
    PORT
      LAYER M5 ;
        RECT  35.856 64.584 35.88 64.776 ;
    END
  END i[332]
  PIN i[333]
    DIRECTION INPUT ;
    USE SIGNAL ;
    PORT
      LAYER M5 ;
        RECT  35.904 64.584 35.928 64.776 ;
    END
  END i[333]
  PIN i[334]
    DIRECTION INPUT ;
    USE SIGNAL ;
    PORT
      LAYER M5 ;
        RECT  35.952 64.584 35.976 64.776 ;
    END
  END i[334]
  PIN i[335]
    DIRECTION INPUT ;
    USE SIGNAL ;
    PORT
      LAYER M5 ;
        RECT  36 64.584 36.024 64.776 ;
    END
  END i[335]
  PIN i[336]
    DIRECTION INPUT ;
    USE SIGNAL ;
    PORT
      LAYER M5 ;
        RECT  36.048 64.584 36.072 64.776 ;
    END
  END i[336]
  PIN i[337]
    DIRECTION INPUT ;
    USE SIGNAL ;
    PORT
      LAYER M5 ;
        RECT  36.096 64.584 36.12 64.776 ;
    END
  END i[337]
  PIN i[338]
    DIRECTION INPUT ;
    USE SIGNAL ;
    PORT
      LAYER M5 ;
        RECT  36.144 64.584 36.168 64.776 ;
    END
  END i[338]
  PIN i[339]
    DIRECTION INPUT ;
    USE SIGNAL ;
    PORT
      LAYER M5 ;
        RECT  36.192 64.584 36.216 64.776 ;
    END
  END i[339]
  PIN i[33]
    DIRECTION INPUT ;
    USE SIGNAL ;
    PORT
      LAYER M5 ;
        RECT  21.504 64.584 21.528 64.776 ;
    END
  END i[33]
  PIN i[340]
    DIRECTION INPUT ;
    USE SIGNAL ;
    PORT
      LAYER M5 ;
        RECT  36.24 64.584 36.264 64.776 ;
    END
  END i[340]
  PIN i[341]
    DIRECTION INPUT ;
    USE SIGNAL ;
    PORT
      LAYER M5 ;
        RECT  36.288 64.584 36.312 64.776 ;
    END
  END i[341]
  PIN i[342]
    DIRECTION INPUT ;
    USE SIGNAL ;
    PORT
      LAYER M5 ;
        RECT  36.336 64.584 36.36 64.776 ;
    END
  END i[342]
  PIN i[343]
    DIRECTION INPUT ;
    USE SIGNAL ;
    PORT
      LAYER M5 ;
        RECT  36.384 64.584 36.408 64.776 ;
    END
  END i[343]
  PIN i[344]
    DIRECTION INPUT ;
    USE SIGNAL ;
    PORT
      LAYER M5 ;
        RECT  36.432 64.584 36.456 64.776 ;
    END
  END i[344]
  PIN i[345]
    DIRECTION INPUT ;
    USE SIGNAL ;
    PORT
      LAYER M5 ;
        RECT  36.48 64.584 36.504 64.776 ;
    END
  END i[345]
  PIN i[346]
    DIRECTION INPUT ;
    USE SIGNAL ;
    PORT
      LAYER M5 ;
        RECT  36.528 64.584 36.552 64.776 ;
    END
  END i[346]
  PIN i[347]
    DIRECTION INPUT ;
    USE SIGNAL ;
    PORT
      LAYER M5 ;
        RECT  36.576 64.584 36.6 64.776 ;
    END
  END i[347]
  PIN i[348]
    DIRECTION INPUT ;
    USE SIGNAL ;
    PORT
      LAYER M5 ;
        RECT  36.624 64.584 36.648 64.776 ;
    END
  END i[348]
  PIN i[349]
    DIRECTION INPUT ;
    USE SIGNAL ;
    PORT
      LAYER M5 ;
        RECT  36.672 64.584 36.696 64.776 ;
    END
  END i[349]
  PIN i[34]
    DIRECTION INPUT ;
    USE SIGNAL ;
    PORT
      LAYER M5 ;
        RECT  21.552 64.584 21.576 64.776 ;
    END
  END i[34]
  PIN i[350]
    DIRECTION INPUT ;
    USE SIGNAL ;
    PORT
      LAYER M5 ;
        RECT  36.72 64.584 36.744 64.776 ;
    END
  END i[350]
  PIN i[351]
    DIRECTION INPUT ;
    USE SIGNAL ;
    PORT
      LAYER M5 ;
        RECT  36.768 64.584 36.792 64.776 ;
    END
  END i[351]
  PIN i[352]
    DIRECTION INPUT ;
    USE SIGNAL ;
    PORT
      LAYER M5 ;
        RECT  36.816 64.584 36.84 64.776 ;
    END
  END i[352]
  PIN i[353]
    DIRECTION INPUT ;
    USE SIGNAL ;
    PORT
      LAYER M5 ;
        RECT  36.864 64.584 36.888 64.776 ;
    END
  END i[353]
  PIN i[354]
    DIRECTION INPUT ;
    USE SIGNAL ;
    PORT
      LAYER M5 ;
        RECT  36.912 64.584 36.936 64.776 ;
    END
  END i[354]
  PIN i[355]
    DIRECTION INPUT ;
    USE SIGNAL ;
    PORT
      LAYER M5 ;
        RECT  36.96 64.584 36.984 64.776 ;
    END
  END i[355]
  PIN i[356]
    DIRECTION INPUT ;
    USE SIGNAL ;
    PORT
      LAYER M5 ;
        RECT  37.008 64.584 37.032 64.776 ;
    END
  END i[356]
  PIN i[357]
    DIRECTION INPUT ;
    USE SIGNAL ;
    PORT
      LAYER M5 ;
        RECT  37.056 64.584 37.08 64.776 ;
    END
  END i[357]
  PIN i[358]
    DIRECTION INPUT ;
    USE SIGNAL ;
    PORT
      LAYER M5 ;
        RECT  37.104 64.584 37.128 64.776 ;
    END
  END i[358]
  PIN i[359]
    DIRECTION INPUT ;
    USE SIGNAL ;
    PORT
      LAYER M5 ;
        RECT  37.152 64.584 37.176 64.776 ;
    END
  END i[359]
  PIN i[35]
    DIRECTION INPUT ;
    USE SIGNAL ;
    PORT
      LAYER M5 ;
        RECT  21.6 64.584 21.624 64.776 ;
    END
  END i[35]
  PIN i[360]
    DIRECTION INPUT ;
    USE SIGNAL ;
    PORT
      LAYER M5 ;
        RECT  37.2 64.584 37.224 64.776 ;
    END
  END i[360]
  PIN i[361]
    DIRECTION INPUT ;
    USE SIGNAL ;
    PORT
      LAYER M5 ;
        RECT  37.248 64.584 37.272 64.776 ;
    END
  END i[361]
  PIN i[362]
    DIRECTION INPUT ;
    USE SIGNAL ;
    PORT
      LAYER M5 ;
        RECT  37.296 64.584 37.32 64.776 ;
    END
  END i[362]
  PIN i[363]
    DIRECTION INPUT ;
    USE SIGNAL ;
    PORT
      LAYER M5 ;
        RECT  37.344 64.584 37.368 64.776 ;
    END
  END i[363]
  PIN i[364]
    DIRECTION INPUT ;
    USE SIGNAL ;
    PORT
      LAYER M5 ;
        RECT  37.392 64.584 37.416 64.776 ;
    END
  END i[364]
  PIN i[365]
    DIRECTION INPUT ;
    USE SIGNAL ;
    PORT
      LAYER M5 ;
        RECT  37.44 64.584 37.464 64.776 ;
    END
  END i[365]
  PIN i[366]
    DIRECTION INPUT ;
    USE SIGNAL ;
    PORT
      LAYER M5 ;
        RECT  37.488 64.584 37.512 64.776 ;
    END
  END i[366]
  PIN i[367]
    DIRECTION INPUT ;
    USE SIGNAL ;
    PORT
      LAYER M5 ;
        RECT  37.536 64.584 37.56 64.776 ;
    END
  END i[367]
  PIN i[368]
    DIRECTION INPUT ;
    USE SIGNAL ;
    PORT
      LAYER M5 ;
        RECT  37.584 64.584 37.608 64.776 ;
    END
  END i[368]
  PIN i[369]
    DIRECTION INPUT ;
    USE SIGNAL ;
    PORT
      LAYER M5 ;
        RECT  37.632 64.584 37.656 64.776 ;
    END
  END i[369]
  PIN i[36]
    DIRECTION INPUT ;
    USE SIGNAL ;
    PORT
      LAYER M5 ;
        RECT  21.648 64.584 21.672 64.776 ;
    END
  END i[36]
  PIN i[370]
    DIRECTION INPUT ;
    USE SIGNAL ;
    PORT
      LAYER M5 ;
        RECT  37.68 64.584 37.704 64.776 ;
    END
  END i[370]
  PIN i[371]
    DIRECTION INPUT ;
    USE SIGNAL ;
    PORT
      LAYER M5 ;
        RECT  37.728 64.584 37.752 64.776 ;
    END
  END i[371]
  PIN i[372]
    DIRECTION INPUT ;
    USE SIGNAL ;
    PORT
      LAYER M5 ;
        RECT  37.776 64.584 37.8 64.776 ;
    END
  END i[372]
  PIN i[373]
    DIRECTION INPUT ;
    USE SIGNAL ;
    PORT
      LAYER M5 ;
        RECT  37.824 64.584 37.848 64.776 ;
    END
  END i[373]
  PIN i[374]
    DIRECTION INPUT ;
    USE SIGNAL ;
    PORT
      LAYER M5 ;
        RECT  37.872 64.584 37.896 64.776 ;
    END
  END i[374]
  PIN i[375]
    DIRECTION INPUT ;
    USE SIGNAL ;
    PORT
      LAYER M5 ;
        RECT  37.92 64.584 37.944 64.776 ;
    END
  END i[375]
  PIN i[376]
    DIRECTION INPUT ;
    USE SIGNAL ;
    PORT
      LAYER M5 ;
        RECT  37.968 64.584 37.992 64.776 ;
    END
  END i[376]
  PIN i[377]
    DIRECTION INPUT ;
    USE SIGNAL ;
    PORT
      LAYER M5 ;
        RECT  38.016 64.584 38.04 64.776 ;
    END
  END i[377]
  PIN i[378]
    DIRECTION INPUT ;
    USE SIGNAL ;
    PORT
      LAYER M5 ;
        RECT  38.064 64.584 38.088 64.776 ;
    END
  END i[378]
  PIN i[379]
    DIRECTION INPUT ;
    USE SIGNAL ;
    PORT
      LAYER M5 ;
        RECT  38.112 64.584 38.136 64.776 ;
    END
  END i[379]
  PIN i[37]
    DIRECTION INPUT ;
    USE SIGNAL ;
    PORT
      LAYER M5 ;
        RECT  21.696 64.584 21.72 64.776 ;
    END
  END i[37]
  PIN i[380]
    DIRECTION INPUT ;
    USE SIGNAL ;
    PORT
      LAYER M5 ;
        RECT  38.16 64.584 38.184 64.776 ;
    END
  END i[380]
  PIN i[381]
    DIRECTION INPUT ;
    USE SIGNAL ;
    PORT
      LAYER M5 ;
        RECT  38.208 64.584 38.232 64.776 ;
    END
  END i[381]
  PIN i[382]
    DIRECTION INPUT ;
    USE SIGNAL ;
    PORT
      LAYER M5 ;
        RECT  38.256 64.584 38.28 64.776 ;
    END
  END i[382]
  PIN i[383]
    DIRECTION INPUT ;
    USE SIGNAL ;
    PORT
      LAYER M5 ;
        RECT  38.304 64.584 38.328 64.776 ;
    END
  END i[383]
  PIN i[384]
    DIRECTION INPUT ;
    USE SIGNAL ;
    PORT
      LAYER M5 ;
        RECT  38.352 64.584 38.376 64.776 ;
    END
  END i[384]
  PIN i[385]
    DIRECTION INPUT ;
    USE SIGNAL ;
    PORT
      LAYER M5 ;
        RECT  38.4 64.584 38.424 64.776 ;
    END
  END i[385]
  PIN i[386]
    DIRECTION INPUT ;
    USE SIGNAL ;
    PORT
      LAYER M5 ;
        RECT  38.448 64.584 38.472 64.776 ;
    END
  END i[386]
  PIN i[387]
    DIRECTION INPUT ;
    USE SIGNAL ;
    PORT
      LAYER M5 ;
        RECT  38.496 64.584 38.52 64.776 ;
    END
  END i[387]
  PIN i[388]
    DIRECTION INPUT ;
    USE SIGNAL ;
    PORT
      LAYER M5 ;
        RECT  38.544 64.584 38.568 64.776 ;
    END
  END i[388]
  PIN i[389]
    DIRECTION INPUT ;
    USE SIGNAL ;
    PORT
      LAYER M5 ;
        RECT  38.592 64.584 38.616 64.776 ;
    END
  END i[389]
  PIN i[38]
    DIRECTION INPUT ;
    USE SIGNAL ;
    PORT
      LAYER M5 ;
        RECT  21.744 64.584 21.768 64.776 ;
    END
  END i[38]
  PIN i[390]
    DIRECTION INPUT ;
    USE SIGNAL ;
    PORT
      LAYER M5 ;
        RECT  38.64 64.584 38.664 64.776 ;
    END
  END i[390]
  PIN i[391]
    DIRECTION INPUT ;
    USE SIGNAL ;
    PORT
      LAYER M5 ;
        RECT  38.688 64.584 38.712 64.776 ;
    END
  END i[391]
  PIN i[392]
    DIRECTION INPUT ;
    USE SIGNAL ;
    PORT
      LAYER M5 ;
        RECT  38.736 64.584 38.76 64.776 ;
    END
  END i[392]
  PIN i[393]
    DIRECTION INPUT ;
    USE SIGNAL ;
    PORT
      LAYER M5 ;
        RECT  38.784 64.584 38.808 64.776 ;
    END
  END i[393]
  PIN i[394]
    DIRECTION INPUT ;
    USE SIGNAL ;
    PORT
      LAYER M5 ;
        RECT  38.832 64.584 38.856 64.776 ;
    END
  END i[394]
  PIN i[395]
    DIRECTION INPUT ;
    USE SIGNAL ;
    PORT
      LAYER M5 ;
        RECT  38.88 64.584 38.904 64.776 ;
    END
  END i[395]
  PIN i[396]
    DIRECTION INPUT ;
    USE SIGNAL ;
    PORT
      LAYER M5 ;
        RECT  38.928 64.584 38.952 64.776 ;
    END
  END i[396]
  PIN i[397]
    DIRECTION INPUT ;
    USE SIGNAL ;
    PORT
      LAYER M5 ;
        RECT  38.976 64.584 39 64.776 ;
    END
  END i[397]
  PIN i[398]
    DIRECTION INPUT ;
    USE SIGNAL ;
    PORT
      LAYER M5 ;
        RECT  39.024 64.584 39.048 64.776 ;
    END
  END i[398]
  PIN i[399]
    DIRECTION INPUT ;
    USE SIGNAL ;
    PORT
      LAYER M5 ;
        RECT  39.072 64.584 39.096 64.776 ;
    END
  END i[399]
  PIN i[39]
    DIRECTION INPUT ;
    USE SIGNAL ;
    PORT
      LAYER M5 ;
        RECT  21.792 64.584 21.816 64.776 ;
    END
  END i[39]
  PIN i[3]
    DIRECTION INPUT ;
    USE SIGNAL ;
    PORT
      LAYER M5 ;
        RECT  20.064 64.584 20.088 64.776 ;
    END
  END i[3]
  PIN i[400]
    DIRECTION INPUT ;
    USE SIGNAL ;
    PORT
      LAYER M5 ;
        RECT  39.12 64.584 39.144 64.776 ;
    END
  END i[400]
  PIN i[401]
    DIRECTION INPUT ;
    USE SIGNAL ;
    PORT
      LAYER M5 ;
        RECT  39.168 64.584 39.192 64.776 ;
    END
  END i[401]
  PIN i[402]
    DIRECTION INPUT ;
    USE SIGNAL ;
    PORT
      LAYER M5 ;
        RECT  39.216 64.584 39.24 64.776 ;
    END
  END i[402]
  PIN i[403]
    DIRECTION INPUT ;
    USE SIGNAL ;
    PORT
      LAYER M5 ;
        RECT  39.264 64.584 39.288 64.776 ;
    END
  END i[403]
  PIN i[404]
    DIRECTION INPUT ;
    USE SIGNAL ;
    PORT
      LAYER M5 ;
        RECT  39.312 64.584 39.336 64.776 ;
    END
  END i[404]
  PIN i[405]
    DIRECTION INPUT ;
    USE SIGNAL ;
    PORT
      LAYER M5 ;
        RECT  39.36 64.584 39.384 64.776 ;
    END
  END i[405]
  PIN i[406]
    DIRECTION INPUT ;
    USE SIGNAL ;
    PORT
      LAYER M5 ;
        RECT  39.408 64.584 39.432 64.776 ;
    END
  END i[406]
  PIN i[407]
    DIRECTION INPUT ;
    USE SIGNAL ;
    PORT
      LAYER M5 ;
        RECT  39.456 64.584 39.48 64.776 ;
    END
  END i[407]
  PIN i[408]
    DIRECTION INPUT ;
    USE SIGNAL ;
    PORT
      LAYER M5 ;
        RECT  39.504 64.584 39.528 64.776 ;
    END
  END i[408]
  PIN i[409]
    DIRECTION INPUT ;
    USE SIGNAL ;
    PORT
      LAYER M5 ;
        RECT  39.552 64.584 39.576 64.776 ;
    END
  END i[409]
  PIN i[40]
    DIRECTION INPUT ;
    USE SIGNAL ;
    PORT
      LAYER M5 ;
        RECT  21.84 64.584 21.864 64.776 ;
    END
  END i[40]
  PIN i[410]
    DIRECTION INPUT ;
    USE SIGNAL ;
    PORT
      LAYER M5 ;
        RECT  39.6 64.584 39.624 64.776 ;
    END
  END i[410]
  PIN i[411]
    DIRECTION INPUT ;
    USE SIGNAL ;
    PORT
      LAYER M5 ;
        RECT  39.648 64.584 39.672 64.776 ;
    END
  END i[411]
  PIN i[412]
    DIRECTION INPUT ;
    USE SIGNAL ;
    PORT
      LAYER M5 ;
        RECT  39.696 64.584 39.72 64.776 ;
    END
  END i[412]
  PIN i[413]
    DIRECTION INPUT ;
    USE SIGNAL ;
    PORT
      LAYER M5 ;
        RECT  39.744 64.584 39.768 64.776 ;
    END
  END i[413]
  PIN i[414]
    DIRECTION INPUT ;
    USE SIGNAL ;
    PORT
      LAYER M5 ;
        RECT  39.792 64.584 39.816 64.776 ;
    END
  END i[414]
  PIN i[415]
    DIRECTION INPUT ;
    USE SIGNAL ;
    PORT
      LAYER M5 ;
        RECT  39.84 64.584 39.864 64.776 ;
    END
  END i[415]
  PIN i[416]
    DIRECTION INPUT ;
    USE SIGNAL ;
    PORT
      LAYER M5 ;
        RECT  39.888 64.584 39.912 64.776 ;
    END
  END i[416]
  PIN i[417]
    DIRECTION INPUT ;
    USE SIGNAL ;
    PORT
      LAYER M5 ;
        RECT  39.936 64.584 39.96 64.776 ;
    END
  END i[417]
  PIN i[418]
    DIRECTION INPUT ;
    USE SIGNAL ;
    PORT
      LAYER M5 ;
        RECT  39.984 64.584 40.008 64.776 ;
    END
  END i[418]
  PIN i[419]
    DIRECTION INPUT ;
    USE SIGNAL ;
    PORT
      LAYER M5 ;
        RECT  40.032 64.584 40.056 64.776 ;
    END
  END i[419]
  PIN i[41]
    DIRECTION INPUT ;
    USE SIGNAL ;
    PORT
      LAYER M5 ;
        RECT  21.888 64.584 21.912 64.776 ;
    END
  END i[41]
  PIN i[420]
    DIRECTION INPUT ;
    USE SIGNAL ;
    PORT
      LAYER M5 ;
        RECT  40.08 64.584 40.104 64.776 ;
    END
  END i[420]
  PIN i[421]
    DIRECTION INPUT ;
    USE SIGNAL ;
    PORT
      LAYER M5 ;
        RECT  40.128 64.584 40.152 64.776 ;
    END
  END i[421]
  PIN i[422]
    DIRECTION INPUT ;
    USE SIGNAL ;
    PORT
      LAYER M5 ;
        RECT  40.176 64.584 40.2 64.776 ;
    END
  END i[422]
  PIN i[423]
    DIRECTION INPUT ;
    USE SIGNAL ;
    PORT
      LAYER M5 ;
        RECT  40.224 64.584 40.248 64.776 ;
    END
  END i[423]
  PIN i[424]
    DIRECTION INPUT ;
    USE SIGNAL ;
    PORT
      LAYER M5 ;
        RECT  40.272 64.584 40.296 64.776 ;
    END
  END i[424]
  PIN i[425]
    DIRECTION INPUT ;
    USE SIGNAL ;
    PORT
      LAYER M5 ;
        RECT  40.32 64.584 40.344 64.776 ;
    END
  END i[425]
  PIN i[426]
    DIRECTION INPUT ;
    USE SIGNAL ;
    PORT
      LAYER M5 ;
        RECT  40.368 64.584 40.392 64.776 ;
    END
  END i[426]
  PIN i[427]
    DIRECTION INPUT ;
    USE SIGNAL ;
    PORT
      LAYER M5 ;
        RECT  40.416 64.584 40.44 64.776 ;
    END
  END i[427]
  PIN i[428]
    DIRECTION INPUT ;
    USE SIGNAL ;
    PORT
      LAYER M5 ;
        RECT  40.464 64.584 40.488 64.776 ;
    END
  END i[428]
  PIN i[429]
    DIRECTION INPUT ;
    USE SIGNAL ;
    PORT
      LAYER M5 ;
        RECT  40.512 64.584 40.536 64.776 ;
    END
  END i[429]
  PIN i[42]
    DIRECTION INPUT ;
    USE SIGNAL ;
    PORT
      LAYER M5 ;
        RECT  21.936 64.584 21.96 64.776 ;
    END
  END i[42]
  PIN i[430]
    DIRECTION INPUT ;
    USE SIGNAL ;
    PORT
      LAYER M5 ;
        RECT  40.56 64.584 40.584 64.776 ;
    END
  END i[430]
  PIN i[431]
    DIRECTION INPUT ;
    USE SIGNAL ;
    PORT
      LAYER M5 ;
        RECT  40.608 64.584 40.632 64.776 ;
    END
  END i[431]
  PIN i[432]
    DIRECTION INPUT ;
    USE SIGNAL ;
    PORT
      LAYER M5 ;
        RECT  40.656 64.584 40.68 64.776 ;
    END
  END i[432]
  PIN i[433]
    DIRECTION INPUT ;
    USE SIGNAL ;
    PORT
      LAYER M5 ;
        RECT  40.704 64.584 40.728 64.776 ;
    END
  END i[433]
  PIN i[434]
    DIRECTION INPUT ;
    USE SIGNAL ;
    PORT
      LAYER M5 ;
        RECT  40.752 64.584 40.776 64.776 ;
    END
  END i[434]
  PIN i[435]
    DIRECTION INPUT ;
    USE SIGNAL ;
    PORT
      LAYER M5 ;
        RECT  40.8 64.584 40.824 64.776 ;
    END
  END i[435]
  PIN i[436]
    DIRECTION INPUT ;
    USE SIGNAL ;
    PORT
      LAYER M5 ;
        RECT  40.848 64.584 40.872 64.776 ;
    END
  END i[436]
  PIN i[437]
    DIRECTION INPUT ;
    USE SIGNAL ;
    PORT
      LAYER M5 ;
        RECT  40.896 64.584 40.92 64.776 ;
    END
  END i[437]
  PIN i[438]
    DIRECTION INPUT ;
    USE SIGNAL ;
    PORT
      LAYER M5 ;
        RECT  40.944 64.584 40.968 64.776 ;
    END
  END i[438]
  PIN i[439]
    DIRECTION INPUT ;
    USE SIGNAL ;
    PORT
      LAYER M5 ;
        RECT  40.992 64.584 41.016 64.776 ;
    END
  END i[439]
  PIN i[43]
    DIRECTION INPUT ;
    USE SIGNAL ;
    PORT
      LAYER M5 ;
        RECT  21.984 64.584 22.008 64.776 ;
    END
  END i[43]
  PIN i[440]
    DIRECTION INPUT ;
    USE SIGNAL ;
    PORT
      LAYER M5 ;
        RECT  41.04 64.584 41.064 64.776 ;
    END
  END i[440]
  PIN i[441]
    DIRECTION INPUT ;
    USE SIGNAL ;
    PORT
      LAYER M5 ;
        RECT  41.088 64.584 41.112 64.776 ;
    END
  END i[441]
  PIN i[442]
    DIRECTION INPUT ;
    USE SIGNAL ;
    PORT
      LAYER M5 ;
        RECT  41.136 64.584 41.16 64.776 ;
    END
  END i[442]
  PIN i[443]
    DIRECTION INPUT ;
    USE SIGNAL ;
    PORT
      LAYER M5 ;
        RECT  41.184 64.584 41.208 64.776 ;
    END
  END i[443]
  PIN i[444]
    DIRECTION INPUT ;
    USE SIGNAL ;
    PORT
      LAYER M5 ;
        RECT  41.232 64.584 41.256 64.776 ;
    END
  END i[444]
  PIN i[445]
    DIRECTION INPUT ;
    USE SIGNAL ;
    PORT
      LAYER M5 ;
        RECT  41.28 64.584 41.304 64.776 ;
    END
  END i[445]
  PIN i[446]
    DIRECTION INPUT ;
    USE SIGNAL ;
    PORT
      LAYER M5 ;
        RECT  41.328 64.584 41.352 64.776 ;
    END
  END i[446]
  PIN i[447]
    DIRECTION INPUT ;
    USE SIGNAL ;
    PORT
      LAYER M5 ;
        RECT  41.376 64.584 41.4 64.776 ;
    END
  END i[447]
  PIN i[448]
    DIRECTION INPUT ;
    USE SIGNAL ;
    PORT
      LAYER M5 ;
        RECT  41.424 64.584 41.448 64.776 ;
    END
  END i[448]
  PIN i[449]
    DIRECTION INPUT ;
    USE SIGNAL ;
    PORT
      LAYER M5 ;
        RECT  41.472 64.584 41.496 64.776 ;
    END
  END i[449]
  PIN i[44]
    DIRECTION INPUT ;
    USE SIGNAL ;
    PORT
      LAYER M5 ;
        RECT  22.032 64.584 22.056 64.776 ;
    END
  END i[44]
  PIN i[450]
    DIRECTION INPUT ;
    USE SIGNAL ;
    PORT
      LAYER M5 ;
        RECT  41.52 64.584 41.544 64.776 ;
    END
  END i[450]
  PIN i[451]
    DIRECTION INPUT ;
    USE SIGNAL ;
    PORT
      LAYER M5 ;
        RECT  41.568 64.584 41.592 64.776 ;
    END
  END i[451]
  PIN i[452]
    DIRECTION INPUT ;
    USE SIGNAL ;
    PORT
      LAYER M5 ;
        RECT  41.616 64.584 41.64 64.776 ;
    END
  END i[452]
  PIN i[453]
    DIRECTION INPUT ;
    USE SIGNAL ;
    PORT
      LAYER M5 ;
        RECT  41.664 64.584 41.688 64.776 ;
    END
  END i[453]
  PIN i[454]
    DIRECTION INPUT ;
    USE SIGNAL ;
    PORT
      LAYER M5 ;
        RECT  41.712 64.584 41.736 64.776 ;
    END
  END i[454]
  PIN i[455]
    DIRECTION INPUT ;
    USE SIGNAL ;
    PORT
      LAYER M5 ;
        RECT  41.76 64.584 41.784 64.776 ;
    END
  END i[455]
  PIN i[456]
    DIRECTION INPUT ;
    USE SIGNAL ;
    PORT
      LAYER M5 ;
        RECT  41.808 64.584 41.832 64.776 ;
    END
  END i[456]
  PIN i[457]
    DIRECTION INPUT ;
    USE SIGNAL ;
    PORT
      LAYER M5 ;
        RECT  41.856 64.584 41.88 64.776 ;
    END
  END i[457]
  PIN i[458]
    DIRECTION INPUT ;
    USE SIGNAL ;
    PORT
      LAYER M5 ;
        RECT  41.904 64.584 41.928 64.776 ;
    END
  END i[458]
  PIN i[459]
    DIRECTION INPUT ;
    USE SIGNAL ;
    PORT
      LAYER M5 ;
        RECT  41.952 64.584 41.976 64.776 ;
    END
  END i[459]
  PIN i[45]
    DIRECTION INPUT ;
    USE SIGNAL ;
    PORT
      LAYER M5 ;
        RECT  22.08 64.584 22.104 64.776 ;
    END
  END i[45]
  PIN i[460]
    DIRECTION INPUT ;
    USE SIGNAL ;
    PORT
      LAYER M5 ;
        RECT  42 64.584 42.024 64.776 ;
    END
  END i[460]
  PIN i[461]
    DIRECTION INPUT ;
    USE SIGNAL ;
    PORT
      LAYER M5 ;
        RECT  42.048 64.584 42.072 64.776 ;
    END
  END i[461]
  PIN i[462]
    DIRECTION INPUT ;
    USE SIGNAL ;
    PORT
      LAYER M5 ;
        RECT  42.096 64.584 42.12 64.776 ;
    END
  END i[462]
  PIN i[463]
    DIRECTION INPUT ;
    USE SIGNAL ;
    PORT
      LAYER M5 ;
        RECT  42.144 64.584 42.168 64.776 ;
    END
  END i[463]
  PIN i[464]
    DIRECTION INPUT ;
    USE SIGNAL ;
    PORT
      LAYER M5 ;
        RECT  42.192 64.584 42.216 64.776 ;
    END
  END i[464]
  PIN i[465]
    DIRECTION INPUT ;
    USE SIGNAL ;
    PORT
      LAYER M5 ;
        RECT  42.24 64.584 42.264 64.776 ;
    END
  END i[465]
  PIN i[466]
    DIRECTION INPUT ;
    USE SIGNAL ;
    PORT
      LAYER M5 ;
        RECT  42.288 64.584 42.312 64.776 ;
    END
  END i[466]
  PIN i[467]
    DIRECTION INPUT ;
    USE SIGNAL ;
    PORT
      LAYER M5 ;
        RECT  42.336 64.584 42.36 64.776 ;
    END
  END i[467]
  PIN i[468]
    DIRECTION INPUT ;
    USE SIGNAL ;
    PORT
      LAYER M5 ;
        RECT  42.384 64.584 42.408 64.776 ;
    END
  END i[468]
  PIN i[469]
    DIRECTION INPUT ;
    USE SIGNAL ;
    PORT
      LAYER M5 ;
        RECT  42.432 64.584 42.456 64.776 ;
    END
  END i[469]
  PIN i[46]
    DIRECTION INPUT ;
    USE SIGNAL ;
    PORT
      LAYER M5 ;
        RECT  22.128 64.584 22.152 64.776 ;
    END
  END i[46]
  PIN i[470]
    DIRECTION INPUT ;
    USE SIGNAL ;
    PORT
      LAYER M5 ;
        RECT  42.48 64.584 42.504 64.776 ;
    END
  END i[470]
  PIN i[471]
    DIRECTION INPUT ;
    USE SIGNAL ;
    PORT
      LAYER M5 ;
        RECT  42.528 64.584 42.552 64.776 ;
    END
  END i[471]
  PIN i[472]
    DIRECTION INPUT ;
    USE SIGNAL ;
    PORT
      LAYER M5 ;
        RECT  42.576 64.584 42.6 64.776 ;
    END
  END i[472]
  PIN i[473]
    DIRECTION INPUT ;
    USE SIGNAL ;
    PORT
      LAYER M5 ;
        RECT  42.624 64.584 42.648 64.776 ;
    END
  END i[473]
  PIN i[474]
    DIRECTION INPUT ;
    USE SIGNAL ;
    PORT
      LAYER M5 ;
        RECT  42.672 64.584 42.696 64.776 ;
    END
  END i[474]
  PIN i[475]
    DIRECTION INPUT ;
    USE SIGNAL ;
    PORT
      LAYER M5 ;
        RECT  42.72 64.584 42.744 64.776 ;
    END
  END i[475]
  PIN i[476]
    DIRECTION INPUT ;
    USE SIGNAL ;
    PORT
      LAYER M5 ;
        RECT  42.768 64.584 42.792 64.776 ;
    END
  END i[476]
  PIN i[477]
    DIRECTION INPUT ;
    USE SIGNAL ;
    PORT
      LAYER M5 ;
        RECT  42.816 64.584 42.84 64.776 ;
    END
  END i[477]
  PIN i[478]
    DIRECTION INPUT ;
    USE SIGNAL ;
    PORT
      LAYER M5 ;
        RECT  42.864 64.584 42.888 64.776 ;
    END
  END i[478]
  PIN i[479]
    DIRECTION INPUT ;
    USE SIGNAL ;
    PORT
      LAYER M5 ;
        RECT  42.912 64.584 42.936 64.776 ;
    END
  END i[479]
  PIN i[47]
    DIRECTION INPUT ;
    USE SIGNAL ;
    PORT
      LAYER M5 ;
        RECT  22.176 64.584 22.2 64.776 ;
    END
  END i[47]
  PIN i[480]
    DIRECTION INPUT ;
    USE SIGNAL ;
    PORT
      LAYER M5 ;
        RECT  42.96 64.584 42.984 64.776 ;
    END
  END i[480]
  PIN i[481]
    DIRECTION INPUT ;
    USE SIGNAL ;
    PORT
      LAYER M5 ;
        RECT  43.008 64.584 43.032 64.776 ;
    END
  END i[481]
  PIN i[482]
    DIRECTION INPUT ;
    USE SIGNAL ;
    PORT
      LAYER M5 ;
        RECT  43.056 64.584 43.08 64.776 ;
    END
  END i[482]
  PIN i[483]
    DIRECTION INPUT ;
    USE SIGNAL ;
    PORT
      LAYER M5 ;
        RECT  43.104 64.584 43.128 64.776 ;
    END
  END i[483]
  PIN i[484]
    DIRECTION INPUT ;
    USE SIGNAL ;
    PORT
      LAYER M5 ;
        RECT  43.152 64.584 43.176 64.776 ;
    END
  END i[484]
  PIN i[485]
    DIRECTION INPUT ;
    USE SIGNAL ;
    PORT
      LAYER M5 ;
        RECT  43.2 64.584 43.224 64.776 ;
    END
  END i[485]
  PIN i[486]
    DIRECTION INPUT ;
    USE SIGNAL ;
    PORT
      LAYER M5 ;
        RECT  43.248 64.584 43.272 64.776 ;
    END
  END i[486]
  PIN i[487]
    DIRECTION INPUT ;
    USE SIGNAL ;
    PORT
      LAYER M5 ;
        RECT  43.296 64.584 43.32 64.776 ;
    END
  END i[487]
  PIN i[488]
    DIRECTION INPUT ;
    USE SIGNAL ;
    PORT
      LAYER M5 ;
        RECT  43.344 64.584 43.368 64.776 ;
    END
  END i[488]
  PIN i[489]
    DIRECTION INPUT ;
    USE SIGNAL ;
    PORT
      LAYER M5 ;
        RECT  43.392 64.584 43.416 64.776 ;
    END
  END i[489]
  PIN i[48]
    DIRECTION INPUT ;
    USE SIGNAL ;
    PORT
      LAYER M5 ;
        RECT  22.224 64.584 22.248 64.776 ;
    END
  END i[48]
  PIN i[490]
    DIRECTION INPUT ;
    USE SIGNAL ;
    PORT
      LAYER M5 ;
        RECT  43.44 64.584 43.464 64.776 ;
    END
  END i[490]
  PIN i[491]
    DIRECTION INPUT ;
    USE SIGNAL ;
    PORT
      LAYER M5 ;
        RECT  43.488 64.584 43.512 64.776 ;
    END
  END i[491]
  PIN i[492]
    DIRECTION INPUT ;
    USE SIGNAL ;
    PORT
      LAYER M5 ;
        RECT  43.536 64.584 43.56 64.776 ;
    END
  END i[492]
  PIN i[493]
    DIRECTION INPUT ;
    USE SIGNAL ;
    PORT
      LAYER M5 ;
        RECT  43.584 64.584 43.608 64.776 ;
    END
  END i[493]
  PIN i[494]
    DIRECTION INPUT ;
    USE SIGNAL ;
    PORT
      LAYER M5 ;
        RECT  43.632 64.584 43.656 64.776 ;
    END
  END i[494]
  PIN i[495]
    DIRECTION INPUT ;
    USE SIGNAL ;
    PORT
      LAYER M5 ;
        RECT  43.68 64.584 43.704 64.776 ;
    END
  END i[495]
  PIN i[496]
    DIRECTION INPUT ;
    USE SIGNAL ;
    PORT
      LAYER M5 ;
        RECT  43.728 64.584 43.752 64.776 ;
    END
  END i[496]
  PIN i[497]
    DIRECTION INPUT ;
    USE SIGNAL ;
    PORT
      LAYER M5 ;
        RECT  43.776 64.584 43.8 64.776 ;
    END
  END i[497]
  PIN i[498]
    DIRECTION INPUT ;
    USE SIGNAL ;
    PORT
      LAYER M5 ;
        RECT  43.824 64.584 43.848 64.776 ;
    END
  END i[498]
  PIN i[499]
    DIRECTION INPUT ;
    USE SIGNAL ;
    PORT
      LAYER M5 ;
        RECT  43.872 64.584 43.896 64.776 ;
    END
  END i[499]
  PIN i[49]
    DIRECTION INPUT ;
    USE SIGNAL ;
    PORT
      LAYER M5 ;
        RECT  22.272 64.584 22.296 64.776 ;
    END
  END i[49]
  PIN i[4]
    DIRECTION INPUT ;
    USE SIGNAL ;
    PORT
      LAYER M5 ;
        RECT  20.112 64.584 20.136 64.776 ;
    END
  END i[4]
  PIN i[500]
    DIRECTION INPUT ;
    USE SIGNAL ;
    PORT
      LAYER M5 ;
        RECT  43.92 64.584 43.944 64.776 ;
    END
  END i[500]
  PIN i[501]
    DIRECTION INPUT ;
    USE SIGNAL ;
    PORT
      LAYER M5 ;
        RECT  43.968 64.584 43.992 64.776 ;
    END
  END i[501]
  PIN i[502]
    DIRECTION INPUT ;
    USE SIGNAL ;
    PORT
      LAYER M5 ;
        RECT  44.016 64.584 44.04 64.776 ;
    END
  END i[502]
  PIN i[503]
    DIRECTION INPUT ;
    USE SIGNAL ;
    PORT
      LAYER M5 ;
        RECT  44.064 64.584 44.088 64.776 ;
    END
  END i[503]
  PIN i[504]
    DIRECTION INPUT ;
    USE SIGNAL ;
    PORT
      LAYER M5 ;
        RECT  44.112 64.584 44.136 64.776 ;
    END
  END i[504]
  PIN i[505]
    DIRECTION INPUT ;
    USE SIGNAL ;
    PORT
      LAYER M5 ;
        RECT  44.16 64.584 44.184 64.776 ;
    END
  END i[505]
  PIN i[506]
    DIRECTION INPUT ;
    USE SIGNAL ;
    PORT
      LAYER M5 ;
        RECT  44.208 64.584 44.232 64.776 ;
    END
  END i[506]
  PIN i[507]
    DIRECTION INPUT ;
    USE SIGNAL ;
    PORT
      LAYER M5 ;
        RECT  44.256 64.584 44.28 64.776 ;
    END
  END i[507]
  PIN i[508]
    DIRECTION INPUT ;
    USE SIGNAL ;
    PORT
      LAYER M5 ;
        RECT  44.304 64.584 44.328 64.776 ;
    END
  END i[508]
  PIN i[509]
    DIRECTION INPUT ;
    USE SIGNAL ;
    PORT
      LAYER M5 ;
        RECT  44.352 64.584 44.376 64.776 ;
    END
  END i[509]
  PIN i[50]
    DIRECTION INPUT ;
    USE SIGNAL ;
    PORT
      LAYER M5 ;
        RECT  22.32 64.584 22.344 64.776 ;
    END
  END i[50]
  PIN i[510]
    DIRECTION INPUT ;
    USE SIGNAL ;
    PORT
      LAYER M5 ;
        RECT  44.4 64.584 44.424 64.776 ;
    END
  END i[510]
  PIN i[511]
    DIRECTION INPUT ;
    USE SIGNAL ;
    PORT
      LAYER M5 ;
        RECT  44.448 64.584 44.472 64.776 ;
    END
  END i[511]
  PIN i[512]
    DIRECTION INPUT ;
    USE SIGNAL ;
    PORT
      LAYER M5 ;
        RECT  44.496 64.584 44.52 64.776 ;
    END
  END i[512]
  PIN i[51]
    DIRECTION INPUT ;
    USE SIGNAL ;
    PORT
      LAYER M5 ;
        RECT  22.368 64.584 22.392 64.776 ;
    END
  END i[51]
  PIN i[52]
    DIRECTION INPUT ;
    USE SIGNAL ;
    PORT
      LAYER M5 ;
        RECT  22.416 64.584 22.44 64.776 ;
    END
  END i[52]
  PIN i[53]
    DIRECTION INPUT ;
    USE SIGNAL ;
    PORT
      LAYER M5 ;
        RECT  22.464 64.584 22.488 64.776 ;
    END
  END i[53]
  PIN i[54]
    DIRECTION INPUT ;
    USE SIGNAL ;
    PORT
      LAYER M5 ;
        RECT  22.512 64.584 22.536 64.776 ;
    END
  END i[54]
  PIN i[55]
    DIRECTION INPUT ;
    USE SIGNAL ;
    PORT
      LAYER M5 ;
        RECT  22.56 64.584 22.584 64.776 ;
    END
  END i[55]
  PIN i[56]
    DIRECTION INPUT ;
    USE SIGNAL ;
    PORT
      LAYER M5 ;
        RECT  22.608 64.584 22.632 64.776 ;
    END
  END i[56]
  PIN i[57]
    DIRECTION INPUT ;
    USE SIGNAL ;
    PORT
      LAYER M5 ;
        RECT  22.656 64.584 22.68 64.776 ;
    END
  END i[57]
  PIN i[58]
    DIRECTION INPUT ;
    USE SIGNAL ;
    PORT
      LAYER M5 ;
        RECT  22.704 64.584 22.728 64.776 ;
    END
  END i[58]
  PIN i[59]
    DIRECTION INPUT ;
    USE SIGNAL ;
    PORT
      LAYER M5 ;
        RECT  22.752 64.584 22.776 64.776 ;
    END
  END i[59]
  PIN i[5]
    DIRECTION INPUT ;
    USE SIGNAL ;
    PORT
      LAYER M5 ;
        RECT  20.16 64.584 20.184 64.776 ;
    END
  END i[5]
  PIN i[60]
    DIRECTION INPUT ;
    USE SIGNAL ;
    PORT
      LAYER M5 ;
        RECT  22.8 64.584 22.824 64.776 ;
    END
  END i[60]
  PIN i[61]
    DIRECTION INPUT ;
    USE SIGNAL ;
    PORT
      LAYER M5 ;
        RECT  22.848 64.584 22.872 64.776 ;
    END
  END i[61]
  PIN i[62]
    DIRECTION INPUT ;
    USE SIGNAL ;
    PORT
      LAYER M5 ;
        RECT  22.896 64.584 22.92 64.776 ;
    END
  END i[62]
  PIN i[63]
    DIRECTION INPUT ;
    USE SIGNAL ;
    PORT
      LAYER M5 ;
        RECT  22.944 64.584 22.968 64.776 ;
    END
  END i[63]
  PIN i[64]
    DIRECTION INPUT ;
    USE SIGNAL ;
    PORT
      LAYER M5 ;
        RECT  22.992 64.584 23.016 64.776 ;
    END
  END i[64]
  PIN i[65]
    DIRECTION INPUT ;
    USE SIGNAL ;
    PORT
      LAYER M5 ;
        RECT  23.04 64.584 23.064 64.776 ;
    END
  END i[65]
  PIN i[66]
    DIRECTION INPUT ;
    USE SIGNAL ;
    PORT
      LAYER M5 ;
        RECT  23.088 64.584 23.112 64.776 ;
    END
  END i[66]
  PIN i[67]
    DIRECTION INPUT ;
    USE SIGNAL ;
    PORT
      LAYER M5 ;
        RECT  23.136 64.584 23.16 64.776 ;
    END
  END i[67]
  PIN i[68]
    DIRECTION INPUT ;
    USE SIGNAL ;
    PORT
      LAYER M5 ;
        RECT  23.184 64.584 23.208 64.776 ;
    END
  END i[68]
  PIN i[69]
    DIRECTION INPUT ;
    USE SIGNAL ;
    PORT
      LAYER M5 ;
        RECT  23.232 64.584 23.256 64.776 ;
    END
  END i[69]
  PIN i[6]
    DIRECTION INPUT ;
    USE SIGNAL ;
    PORT
      LAYER M5 ;
        RECT  20.208 64.584 20.232 64.776 ;
    END
  END i[6]
  PIN i[70]
    DIRECTION INPUT ;
    USE SIGNAL ;
    PORT
      LAYER M5 ;
        RECT  23.28 64.584 23.304 64.776 ;
    END
  END i[70]
  PIN i[71]
    DIRECTION INPUT ;
    USE SIGNAL ;
    PORT
      LAYER M5 ;
        RECT  23.328 64.584 23.352 64.776 ;
    END
  END i[71]
  PIN i[72]
    DIRECTION INPUT ;
    USE SIGNAL ;
    PORT
      LAYER M5 ;
        RECT  23.376 64.584 23.4 64.776 ;
    END
  END i[72]
  PIN i[73]
    DIRECTION INPUT ;
    USE SIGNAL ;
    PORT
      LAYER M5 ;
        RECT  23.424 64.584 23.448 64.776 ;
    END
  END i[73]
  PIN i[74]
    DIRECTION INPUT ;
    USE SIGNAL ;
    PORT
      LAYER M5 ;
        RECT  23.472 64.584 23.496 64.776 ;
    END
  END i[74]
  PIN i[75]
    DIRECTION INPUT ;
    USE SIGNAL ;
    PORT
      LAYER M5 ;
        RECT  23.52 64.584 23.544 64.776 ;
    END
  END i[75]
  PIN i[76]
    DIRECTION INPUT ;
    USE SIGNAL ;
    PORT
      LAYER M5 ;
        RECT  23.568 64.584 23.592 64.776 ;
    END
  END i[76]
  PIN i[77]
    DIRECTION INPUT ;
    USE SIGNAL ;
    PORT
      LAYER M5 ;
        RECT  23.616 64.584 23.64 64.776 ;
    END
  END i[77]
  PIN i[78]
    DIRECTION INPUT ;
    USE SIGNAL ;
    PORT
      LAYER M5 ;
        RECT  23.664 64.584 23.688 64.776 ;
    END
  END i[78]
  PIN i[79]
    DIRECTION INPUT ;
    USE SIGNAL ;
    PORT
      LAYER M5 ;
        RECT  23.712 64.584 23.736 64.776 ;
    END
  END i[79]
  PIN i[7]
    DIRECTION INPUT ;
    USE SIGNAL ;
    PORT
      LAYER M5 ;
        RECT  20.256 64.584 20.28 64.776 ;
    END
  END i[7]
  PIN i[80]
    DIRECTION INPUT ;
    USE SIGNAL ;
    PORT
      LAYER M5 ;
        RECT  23.76 64.584 23.784 64.776 ;
    END
  END i[80]
  PIN i[81]
    DIRECTION INPUT ;
    USE SIGNAL ;
    PORT
      LAYER M5 ;
        RECT  23.808 64.584 23.832 64.776 ;
    END
  END i[81]
  PIN i[82]
    DIRECTION INPUT ;
    USE SIGNAL ;
    PORT
      LAYER M5 ;
        RECT  23.856 64.584 23.88 64.776 ;
    END
  END i[82]
  PIN i[83]
    DIRECTION INPUT ;
    USE SIGNAL ;
    PORT
      LAYER M5 ;
        RECT  23.904 64.584 23.928 64.776 ;
    END
  END i[83]
  PIN i[84]
    DIRECTION INPUT ;
    USE SIGNAL ;
    PORT
      LAYER M5 ;
        RECT  23.952 64.584 23.976 64.776 ;
    END
  END i[84]
  PIN i[85]
    DIRECTION INPUT ;
    USE SIGNAL ;
    PORT
      LAYER M5 ;
        RECT  24 64.584 24.024 64.776 ;
    END
  END i[85]
  PIN i[86]
    DIRECTION INPUT ;
    USE SIGNAL ;
    PORT
      LAYER M5 ;
        RECT  24.048 64.584 24.072 64.776 ;
    END
  END i[86]
  PIN i[87]
    DIRECTION INPUT ;
    USE SIGNAL ;
    PORT
      LAYER M5 ;
        RECT  24.096 64.584 24.12 64.776 ;
    END
  END i[87]
  PIN i[88]
    DIRECTION INPUT ;
    USE SIGNAL ;
    PORT
      LAYER M5 ;
        RECT  24.144 64.584 24.168 64.776 ;
    END
  END i[88]
  PIN i[89]
    DIRECTION INPUT ;
    USE SIGNAL ;
    PORT
      LAYER M5 ;
        RECT  24.192 64.584 24.216 64.776 ;
    END
  END i[89]
  PIN i[8]
    DIRECTION INPUT ;
    USE SIGNAL ;
    PORT
      LAYER M5 ;
        RECT  20.304 64.584 20.328 64.776 ;
    END
  END i[8]
  PIN i[90]
    DIRECTION INPUT ;
    USE SIGNAL ;
    PORT
      LAYER M5 ;
        RECT  24.24 64.584 24.264 64.776 ;
    END
  END i[90]
  PIN i[91]
    DIRECTION INPUT ;
    USE SIGNAL ;
    PORT
      LAYER M5 ;
        RECT  24.288 64.584 24.312 64.776 ;
    END
  END i[91]
  PIN i[92]
    DIRECTION INPUT ;
    USE SIGNAL ;
    PORT
      LAYER M5 ;
        RECT  24.336 64.584 24.36 64.776 ;
    END
  END i[92]
  PIN i[93]
    DIRECTION INPUT ;
    USE SIGNAL ;
    PORT
      LAYER M5 ;
        RECT  24.384 64.584 24.408 64.776 ;
    END
  END i[93]
  PIN i[94]
    DIRECTION INPUT ;
    USE SIGNAL ;
    PORT
      LAYER M5 ;
        RECT  24.432 64.584 24.456 64.776 ;
    END
  END i[94]
  PIN i[95]
    DIRECTION INPUT ;
    USE SIGNAL ;
    PORT
      LAYER M5 ;
        RECT  24.48 64.584 24.504 64.776 ;
    END
  END i[95]
  PIN i[96]
    DIRECTION INPUT ;
    USE SIGNAL ;
    PORT
      LAYER M5 ;
        RECT  24.528 64.584 24.552 64.776 ;
    END
  END i[96]
  PIN i[97]
    DIRECTION INPUT ;
    USE SIGNAL ;
    PORT
      LAYER M5 ;
        RECT  24.576 64.584 24.6 64.776 ;
    END
  END i[97]
  PIN i[98]
    DIRECTION INPUT ;
    USE SIGNAL ;
    PORT
      LAYER M5 ;
        RECT  24.624 64.584 24.648 64.776 ;
    END
  END i[98]
  PIN i[99]
    DIRECTION INPUT ;
    USE SIGNAL ;
    PORT
      LAYER M5 ;
        RECT  24.672 64.584 24.696 64.776 ;
    END
  END i[99]
  PIN i[9]
    DIRECTION INPUT ;
    USE SIGNAL ;
    PORT
      LAYER M5 ;
        RECT  20.352 64.584 20.376 64.776 ;
    END
  END i[9]
  PIN od[0]
    DIRECTION OUTPUT ;
    USE SIGNAL ;
    PORT
      LAYER M4 ;
        RECT  0 20.16 0.192 20.184 ;
    END
  END od[0]
  PIN od[100]
    DIRECTION OUTPUT ;
    USE SIGNAL ;
    PORT
      LAYER M4 ;
        RECT  0 24.96 0.192 24.984 ;
    END
  END od[100]
  PIN od[101]
    DIRECTION OUTPUT ;
    USE SIGNAL ;
    PORT
      LAYER M4 ;
        RECT  0 25.008 0.192 25.032 ;
    END
  END od[101]
  PIN od[102]
    DIRECTION OUTPUT ;
    USE SIGNAL ;
    PORT
      LAYER M4 ;
        RECT  0 25.056 0.192 25.08 ;
    END
  END od[102]
  PIN od[103]
    DIRECTION OUTPUT ;
    USE SIGNAL ;
    PORT
      LAYER M4 ;
        RECT  0 25.104 0.192 25.128 ;
    END
  END od[103]
  PIN od[104]
    DIRECTION OUTPUT ;
    USE SIGNAL ;
    PORT
      LAYER M4 ;
        RECT  0 25.152 0.192 25.176 ;
    END
  END od[104]
  PIN od[105]
    DIRECTION OUTPUT ;
    USE SIGNAL ;
    PORT
      LAYER M4 ;
        RECT  0 25.2 0.192 25.224 ;
    END
  END od[105]
  PIN od[106]
    DIRECTION OUTPUT ;
    USE SIGNAL ;
    PORT
      LAYER M4 ;
        RECT  0 25.248 0.192 25.272 ;
    END
  END od[106]
  PIN od[107]
    DIRECTION OUTPUT ;
    USE SIGNAL ;
    PORT
      LAYER M4 ;
        RECT  0 25.296 0.192 25.32 ;
    END
  END od[107]
  PIN od[108]
    DIRECTION OUTPUT ;
    USE SIGNAL ;
    PORT
      LAYER M4 ;
        RECT  0 25.344 0.192 25.368 ;
    END
  END od[108]
  PIN od[109]
    DIRECTION OUTPUT ;
    USE SIGNAL ;
    PORT
      LAYER M4 ;
        RECT  0 25.392 0.192 25.416 ;
    END
  END od[109]
  PIN od[10]
    DIRECTION OUTPUT ;
    USE SIGNAL ;
    PORT
      LAYER M4 ;
        RECT  0 20.64 0.192 20.664 ;
    END
  END od[10]
  PIN od[110]
    DIRECTION OUTPUT ;
    USE SIGNAL ;
    PORT
      LAYER M4 ;
        RECT  0 25.44 0.192 25.464 ;
    END
  END od[110]
  PIN od[111]
    DIRECTION OUTPUT ;
    USE SIGNAL ;
    PORT
      LAYER M4 ;
        RECT  0 25.488 0.192 25.512 ;
    END
  END od[111]
  PIN od[112]
    DIRECTION OUTPUT ;
    USE SIGNAL ;
    PORT
      LAYER M4 ;
        RECT  0 25.536 0.192 25.56 ;
    END
  END od[112]
  PIN od[113]
    DIRECTION OUTPUT ;
    USE SIGNAL ;
    PORT
      LAYER M4 ;
        RECT  0 25.584 0.192 25.608 ;
    END
  END od[113]
  PIN od[114]
    DIRECTION OUTPUT ;
    USE SIGNAL ;
    PORT
      LAYER M4 ;
        RECT  0 25.632 0.192 25.656 ;
    END
  END od[114]
  PIN od[115]
    DIRECTION OUTPUT ;
    USE SIGNAL ;
    PORT
      LAYER M4 ;
        RECT  0 25.68 0.192 25.704 ;
    END
  END od[115]
  PIN od[116]
    DIRECTION OUTPUT ;
    USE SIGNAL ;
    PORT
      LAYER M4 ;
        RECT  0 25.728 0.192 25.752 ;
    END
  END od[116]
  PIN od[117]
    DIRECTION OUTPUT ;
    USE SIGNAL ;
    PORT
      LAYER M4 ;
        RECT  0 25.776 0.192 25.8 ;
    END
  END od[117]
  PIN od[118]
    DIRECTION OUTPUT ;
    USE SIGNAL ;
    PORT
      LAYER M4 ;
        RECT  0 25.824 0.192 25.848 ;
    END
  END od[118]
  PIN od[119]
    DIRECTION OUTPUT ;
    USE SIGNAL ;
    PORT
      LAYER M4 ;
        RECT  0 25.872 0.192 25.896 ;
    END
  END od[119]
  PIN od[11]
    DIRECTION OUTPUT ;
    USE SIGNAL ;
    PORT
      LAYER M4 ;
        RECT  0 20.688 0.192 20.712 ;
    END
  END od[11]
  PIN od[120]
    DIRECTION OUTPUT ;
    USE SIGNAL ;
    PORT
      LAYER M4 ;
        RECT  0 25.92 0.192 25.944 ;
    END
  END od[120]
  PIN od[121]
    DIRECTION OUTPUT ;
    USE SIGNAL ;
    PORT
      LAYER M4 ;
        RECT  0 25.968 0.192 25.992 ;
    END
  END od[121]
  PIN od[122]
    DIRECTION OUTPUT ;
    USE SIGNAL ;
    PORT
      LAYER M4 ;
        RECT  0 26.016 0.192 26.04 ;
    END
  END od[122]
  PIN od[123]
    DIRECTION OUTPUT ;
    USE SIGNAL ;
    PORT
      LAYER M4 ;
        RECT  0 26.064 0.192 26.088 ;
    END
  END od[123]
  PIN od[124]
    DIRECTION OUTPUT ;
    USE SIGNAL ;
    PORT
      LAYER M4 ;
        RECT  0 26.112 0.192 26.136 ;
    END
  END od[124]
  PIN od[125]
    DIRECTION OUTPUT ;
    USE SIGNAL ;
    PORT
      LAYER M4 ;
        RECT  0 26.16 0.192 26.184 ;
    END
  END od[125]
  PIN od[126]
    DIRECTION OUTPUT ;
    USE SIGNAL ;
    PORT
      LAYER M4 ;
        RECT  0 26.208 0.192 26.232 ;
    END
  END od[126]
  PIN od[127]
    DIRECTION OUTPUT ;
    USE SIGNAL ;
    PORT
      LAYER M4 ;
        RECT  0 26.256 0.192 26.28 ;
    END
  END od[127]
  PIN od[128]
    DIRECTION OUTPUT ;
    USE SIGNAL ;
    PORT
      LAYER M4 ;
        RECT  0 26.304 0.192 26.328 ;
    END
  END od[128]
  PIN od[129]
    DIRECTION OUTPUT ;
    USE SIGNAL ;
    PORT
      LAYER M4 ;
        RECT  0 26.352 0.192 26.376 ;
    END
  END od[129]
  PIN od[12]
    DIRECTION OUTPUT ;
    USE SIGNAL ;
    PORT
      LAYER M4 ;
        RECT  0 20.736 0.192 20.76 ;
    END
  END od[12]
  PIN od[130]
    DIRECTION OUTPUT ;
    USE SIGNAL ;
    PORT
      LAYER M4 ;
        RECT  0 26.4 0.192 26.424 ;
    END
  END od[130]
  PIN od[131]
    DIRECTION OUTPUT ;
    USE SIGNAL ;
    PORT
      LAYER M4 ;
        RECT  0 26.448 0.192 26.472 ;
    END
  END od[131]
  PIN od[132]
    DIRECTION OUTPUT ;
    USE SIGNAL ;
    PORT
      LAYER M4 ;
        RECT  0 26.496 0.192 26.52 ;
    END
  END od[132]
  PIN od[133]
    DIRECTION OUTPUT ;
    USE SIGNAL ;
    PORT
      LAYER M4 ;
        RECT  0 26.544 0.192 26.568 ;
    END
  END od[133]
  PIN od[134]
    DIRECTION OUTPUT ;
    USE SIGNAL ;
    PORT
      LAYER M4 ;
        RECT  0 26.592 0.192 26.616 ;
    END
  END od[134]
  PIN od[135]
    DIRECTION OUTPUT ;
    USE SIGNAL ;
    PORT
      LAYER M4 ;
        RECT  0 26.64 0.192 26.664 ;
    END
  END od[135]
  PIN od[136]
    DIRECTION OUTPUT ;
    USE SIGNAL ;
    PORT
      LAYER M4 ;
        RECT  0 26.688 0.192 26.712 ;
    END
  END od[136]
  PIN od[137]
    DIRECTION OUTPUT ;
    USE SIGNAL ;
    PORT
      LAYER M4 ;
        RECT  0 26.736 0.192 26.76 ;
    END
  END od[137]
  PIN od[138]
    DIRECTION OUTPUT ;
    USE SIGNAL ;
    PORT
      LAYER M4 ;
        RECT  0 26.784 0.192 26.808 ;
    END
  END od[138]
  PIN od[139]
    DIRECTION OUTPUT ;
    USE SIGNAL ;
    PORT
      LAYER M4 ;
        RECT  0 26.832 0.192 26.856 ;
    END
  END od[139]
  PIN od[13]
    DIRECTION OUTPUT ;
    USE SIGNAL ;
    PORT
      LAYER M4 ;
        RECT  0 20.784 0.192 20.808 ;
    END
  END od[13]
  PIN od[140]
    DIRECTION OUTPUT ;
    USE SIGNAL ;
    PORT
      LAYER M4 ;
        RECT  0 26.88 0.192 26.904 ;
    END
  END od[140]
  PIN od[141]
    DIRECTION OUTPUT ;
    USE SIGNAL ;
    PORT
      LAYER M4 ;
        RECT  0 26.928 0.192 26.952 ;
    END
  END od[141]
  PIN od[142]
    DIRECTION OUTPUT ;
    USE SIGNAL ;
    PORT
      LAYER M4 ;
        RECT  0 26.976 0.192 27 ;
    END
  END od[142]
  PIN od[143]
    DIRECTION OUTPUT ;
    USE SIGNAL ;
    PORT
      LAYER M4 ;
        RECT  0 27.024 0.192 27.048 ;
    END
  END od[143]
  PIN od[144]
    DIRECTION OUTPUT ;
    USE SIGNAL ;
    PORT
      LAYER M4 ;
        RECT  0 27.072 0.192 27.096 ;
    END
  END od[144]
  PIN od[145]
    DIRECTION OUTPUT ;
    USE SIGNAL ;
    PORT
      LAYER M4 ;
        RECT  0 27.12 0.192 27.144 ;
    END
  END od[145]
  PIN od[146]
    DIRECTION OUTPUT ;
    USE SIGNAL ;
    PORT
      LAYER M4 ;
        RECT  0 27.168 0.192 27.192 ;
    END
  END od[146]
  PIN od[147]
    DIRECTION OUTPUT ;
    USE SIGNAL ;
    PORT
      LAYER M4 ;
        RECT  0 27.216 0.192 27.24 ;
    END
  END od[147]
  PIN od[148]
    DIRECTION OUTPUT ;
    USE SIGNAL ;
    PORT
      LAYER M4 ;
        RECT  0 27.264 0.192 27.288 ;
    END
  END od[148]
  PIN od[149]
    DIRECTION OUTPUT ;
    USE SIGNAL ;
    PORT
      LAYER M4 ;
        RECT  0 27.312 0.192 27.336 ;
    END
  END od[149]
  PIN od[14]
    DIRECTION OUTPUT ;
    USE SIGNAL ;
    PORT
      LAYER M4 ;
        RECT  0 20.832 0.192 20.856 ;
    END
  END od[14]
  PIN od[150]
    DIRECTION OUTPUT ;
    USE SIGNAL ;
    PORT
      LAYER M4 ;
        RECT  0 27.36 0.192 27.384 ;
    END
  END od[150]
  PIN od[151]
    DIRECTION OUTPUT ;
    USE SIGNAL ;
    PORT
      LAYER M4 ;
        RECT  0 27.408 0.192 27.432 ;
    END
  END od[151]
  PIN od[152]
    DIRECTION OUTPUT ;
    USE SIGNAL ;
    PORT
      LAYER M4 ;
        RECT  0 27.456 0.192 27.48 ;
    END
  END od[152]
  PIN od[153]
    DIRECTION OUTPUT ;
    USE SIGNAL ;
    PORT
      LAYER M4 ;
        RECT  0 27.504 0.192 27.528 ;
    END
  END od[153]
  PIN od[154]
    DIRECTION OUTPUT ;
    USE SIGNAL ;
    PORT
      LAYER M4 ;
        RECT  0 27.552 0.192 27.576 ;
    END
  END od[154]
  PIN od[155]
    DIRECTION OUTPUT ;
    USE SIGNAL ;
    PORT
      LAYER M4 ;
        RECT  0 27.6 0.192 27.624 ;
    END
  END od[155]
  PIN od[156]
    DIRECTION OUTPUT ;
    USE SIGNAL ;
    PORT
      LAYER M4 ;
        RECT  0 27.648 0.192 27.672 ;
    END
  END od[156]
  PIN od[157]
    DIRECTION OUTPUT ;
    USE SIGNAL ;
    PORT
      LAYER M4 ;
        RECT  0 27.696 0.192 27.72 ;
    END
  END od[157]
  PIN od[158]
    DIRECTION OUTPUT ;
    USE SIGNAL ;
    PORT
      LAYER M4 ;
        RECT  0 27.744 0.192 27.768 ;
    END
  END od[158]
  PIN od[159]
    DIRECTION OUTPUT ;
    USE SIGNAL ;
    PORT
      LAYER M4 ;
        RECT  0 27.792 0.192 27.816 ;
    END
  END od[159]
  PIN od[15]
    DIRECTION OUTPUT ;
    USE SIGNAL ;
    PORT
      LAYER M4 ;
        RECT  0 20.88 0.192 20.904 ;
    END
  END od[15]
  PIN od[160]
    DIRECTION OUTPUT ;
    USE SIGNAL ;
    PORT
      LAYER M4 ;
        RECT  0 27.84 0.192 27.864 ;
    END
  END od[160]
  PIN od[161]
    DIRECTION OUTPUT ;
    USE SIGNAL ;
    PORT
      LAYER M4 ;
        RECT  0 27.888 0.192 27.912 ;
    END
  END od[161]
  PIN od[162]
    DIRECTION OUTPUT ;
    USE SIGNAL ;
    PORT
      LAYER M4 ;
        RECT  0 27.936 0.192 27.96 ;
    END
  END od[162]
  PIN od[163]
    DIRECTION OUTPUT ;
    USE SIGNAL ;
    PORT
      LAYER M4 ;
        RECT  0 27.984 0.192 28.008 ;
    END
  END od[163]
  PIN od[164]
    DIRECTION OUTPUT ;
    USE SIGNAL ;
    PORT
      LAYER M4 ;
        RECT  0 28.032 0.192 28.056 ;
    END
  END od[164]
  PIN od[165]
    DIRECTION OUTPUT ;
    USE SIGNAL ;
    PORT
      LAYER M4 ;
        RECT  0 28.08 0.192 28.104 ;
    END
  END od[165]
  PIN od[166]
    DIRECTION OUTPUT ;
    USE SIGNAL ;
    PORT
      LAYER M4 ;
        RECT  0 28.128 0.192 28.152 ;
    END
  END od[166]
  PIN od[167]
    DIRECTION OUTPUT ;
    USE SIGNAL ;
    PORT
      LAYER M4 ;
        RECT  0 28.176 0.192 28.2 ;
    END
  END od[167]
  PIN od[168]
    DIRECTION OUTPUT ;
    USE SIGNAL ;
    PORT
      LAYER M4 ;
        RECT  0 28.224 0.192 28.248 ;
    END
  END od[168]
  PIN od[169]
    DIRECTION OUTPUT ;
    USE SIGNAL ;
    PORT
      LAYER M4 ;
        RECT  0 28.272 0.192 28.296 ;
    END
  END od[169]
  PIN od[16]
    DIRECTION OUTPUT ;
    USE SIGNAL ;
    PORT
      LAYER M4 ;
        RECT  0 20.928 0.192 20.952 ;
    END
  END od[16]
  PIN od[170]
    DIRECTION OUTPUT ;
    USE SIGNAL ;
    PORT
      LAYER M4 ;
        RECT  0 28.32 0.192 28.344 ;
    END
  END od[170]
  PIN od[171]
    DIRECTION OUTPUT ;
    USE SIGNAL ;
    PORT
      LAYER M4 ;
        RECT  0 28.368 0.192 28.392 ;
    END
  END od[171]
  PIN od[172]
    DIRECTION OUTPUT ;
    USE SIGNAL ;
    PORT
      LAYER M4 ;
        RECT  0 28.416 0.192 28.44 ;
    END
  END od[172]
  PIN od[173]
    DIRECTION OUTPUT ;
    USE SIGNAL ;
    PORT
      LAYER M4 ;
        RECT  0 28.464 0.192 28.488 ;
    END
  END od[173]
  PIN od[174]
    DIRECTION OUTPUT ;
    USE SIGNAL ;
    PORT
      LAYER M4 ;
        RECT  0 28.512 0.192 28.536 ;
    END
  END od[174]
  PIN od[175]
    DIRECTION OUTPUT ;
    USE SIGNAL ;
    PORT
      LAYER M4 ;
        RECT  0 28.56 0.192 28.584 ;
    END
  END od[175]
  PIN od[176]
    DIRECTION OUTPUT ;
    USE SIGNAL ;
    PORT
      LAYER M4 ;
        RECT  0 28.608 0.192 28.632 ;
    END
  END od[176]
  PIN od[177]
    DIRECTION OUTPUT ;
    USE SIGNAL ;
    PORT
      LAYER M4 ;
        RECT  0 28.656 0.192 28.68 ;
    END
  END od[177]
  PIN od[178]
    DIRECTION OUTPUT ;
    USE SIGNAL ;
    PORT
      LAYER M4 ;
        RECT  0 28.704 0.192 28.728 ;
    END
  END od[178]
  PIN od[179]
    DIRECTION OUTPUT ;
    USE SIGNAL ;
    PORT
      LAYER M4 ;
        RECT  0 28.752 0.192 28.776 ;
    END
  END od[179]
  PIN od[17]
    DIRECTION OUTPUT ;
    USE SIGNAL ;
    PORT
      LAYER M4 ;
        RECT  0 20.976 0.192 21 ;
    END
  END od[17]
  PIN od[180]
    DIRECTION OUTPUT ;
    USE SIGNAL ;
    PORT
      LAYER M4 ;
        RECT  0 28.8 0.192 28.824 ;
    END
  END od[180]
  PIN od[181]
    DIRECTION OUTPUT ;
    USE SIGNAL ;
    PORT
      LAYER M4 ;
        RECT  0 28.848 0.192 28.872 ;
    END
  END od[181]
  PIN od[182]
    DIRECTION OUTPUT ;
    USE SIGNAL ;
    PORT
      LAYER M4 ;
        RECT  0 28.896 0.192 28.92 ;
    END
  END od[182]
  PIN od[183]
    DIRECTION OUTPUT ;
    USE SIGNAL ;
    PORT
      LAYER M4 ;
        RECT  0 28.944 0.192 28.968 ;
    END
  END od[183]
  PIN od[184]
    DIRECTION OUTPUT ;
    USE SIGNAL ;
    PORT
      LAYER M4 ;
        RECT  0 28.992 0.192 29.016 ;
    END
  END od[184]
  PIN od[185]
    DIRECTION OUTPUT ;
    USE SIGNAL ;
    PORT
      LAYER M4 ;
        RECT  0 29.04 0.192 29.064 ;
    END
  END od[185]
  PIN od[186]
    DIRECTION OUTPUT ;
    USE SIGNAL ;
    PORT
      LAYER M4 ;
        RECT  0 29.088 0.192 29.112 ;
    END
  END od[186]
  PIN od[187]
    DIRECTION OUTPUT ;
    USE SIGNAL ;
    PORT
      LAYER M4 ;
        RECT  0 29.136 0.192 29.16 ;
    END
  END od[187]
  PIN od[188]
    DIRECTION OUTPUT ;
    USE SIGNAL ;
    PORT
      LAYER M4 ;
        RECT  0 29.184 0.192 29.208 ;
    END
  END od[188]
  PIN od[189]
    DIRECTION OUTPUT ;
    USE SIGNAL ;
    PORT
      LAYER M4 ;
        RECT  0 29.232 0.192 29.256 ;
    END
  END od[189]
  PIN od[18]
    DIRECTION OUTPUT ;
    USE SIGNAL ;
    PORT
      LAYER M4 ;
        RECT  0 21.024 0.192 21.048 ;
    END
  END od[18]
  PIN od[190]
    DIRECTION OUTPUT ;
    USE SIGNAL ;
    PORT
      LAYER M4 ;
        RECT  0 29.28 0.192 29.304 ;
    END
  END od[190]
  PIN od[191]
    DIRECTION OUTPUT ;
    USE SIGNAL ;
    PORT
      LAYER M4 ;
        RECT  0 29.328 0.192 29.352 ;
    END
  END od[191]
  PIN od[192]
    DIRECTION OUTPUT ;
    USE SIGNAL ;
    PORT
      LAYER M4 ;
        RECT  0 29.376 0.192 29.4 ;
    END
  END od[192]
  PIN od[193]
    DIRECTION OUTPUT ;
    USE SIGNAL ;
    PORT
      LAYER M4 ;
        RECT  0 29.424 0.192 29.448 ;
    END
  END od[193]
  PIN od[194]
    DIRECTION OUTPUT ;
    USE SIGNAL ;
    PORT
      LAYER M4 ;
        RECT  0 29.472 0.192 29.496 ;
    END
  END od[194]
  PIN od[195]
    DIRECTION OUTPUT ;
    USE SIGNAL ;
    PORT
      LAYER M4 ;
        RECT  0 29.52 0.192 29.544 ;
    END
  END od[195]
  PIN od[196]
    DIRECTION OUTPUT ;
    USE SIGNAL ;
    PORT
      LAYER M4 ;
        RECT  0 29.568 0.192 29.592 ;
    END
  END od[196]
  PIN od[197]
    DIRECTION OUTPUT ;
    USE SIGNAL ;
    PORT
      LAYER M4 ;
        RECT  0 29.616 0.192 29.64 ;
    END
  END od[197]
  PIN od[198]
    DIRECTION OUTPUT ;
    USE SIGNAL ;
    PORT
      LAYER M4 ;
        RECT  0 29.664 0.192 29.688 ;
    END
  END od[198]
  PIN od[199]
    DIRECTION OUTPUT ;
    USE SIGNAL ;
    PORT
      LAYER M4 ;
        RECT  0 29.712 0.192 29.736 ;
    END
  END od[199]
  PIN od[19]
    DIRECTION OUTPUT ;
    USE SIGNAL ;
    PORT
      LAYER M4 ;
        RECT  0 21.072 0.192 21.096 ;
    END
  END od[19]
  PIN od[1]
    DIRECTION OUTPUT ;
    USE SIGNAL ;
    PORT
      LAYER M4 ;
        RECT  0 20.208 0.192 20.232 ;
    END
  END od[1]
  PIN od[200]
    DIRECTION OUTPUT ;
    USE SIGNAL ;
    PORT
      LAYER M4 ;
        RECT  0 29.76 0.192 29.784 ;
    END
  END od[200]
  PIN od[201]
    DIRECTION OUTPUT ;
    USE SIGNAL ;
    PORT
      LAYER M4 ;
        RECT  0 29.808 0.192 29.832 ;
    END
  END od[201]
  PIN od[202]
    DIRECTION OUTPUT ;
    USE SIGNAL ;
    PORT
      LAYER M4 ;
        RECT  0 29.856 0.192 29.88 ;
    END
  END od[202]
  PIN od[203]
    DIRECTION OUTPUT ;
    USE SIGNAL ;
    PORT
      LAYER M4 ;
        RECT  0 29.904 0.192 29.928 ;
    END
  END od[203]
  PIN od[204]
    DIRECTION OUTPUT ;
    USE SIGNAL ;
    PORT
      LAYER M4 ;
        RECT  0 29.952 0.192 29.976 ;
    END
  END od[204]
  PIN od[205]
    DIRECTION OUTPUT ;
    USE SIGNAL ;
    PORT
      LAYER M4 ;
        RECT  0 30 0.192 30.024 ;
    END
  END od[205]
  PIN od[206]
    DIRECTION OUTPUT ;
    USE SIGNAL ;
    PORT
      LAYER M4 ;
        RECT  0 30.048 0.192 30.072 ;
    END
  END od[206]
  PIN od[207]
    DIRECTION OUTPUT ;
    USE SIGNAL ;
    PORT
      LAYER M4 ;
        RECT  0 30.096 0.192 30.12 ;
    END
  END od[207]
  PIN od[208]
    DIRECTION OUTPUT ;
    USE SIGNAL ;
    PORT
      LAYER M4 ;
        RECT  0 30.144 0.192 30.168 ;
    END
  END od[208]
  PIN od[209]
    DIRECTION OUTPUT ;
    USE SIGNAL ;
    PORT
      LAYER M4 ;
        RECT  0 30.192 0.192 30.216 ;
    END
  END od[209]
  PIN od[20]
    DIRECTION OUTPUT ;
    USE SIGNAL ;
    PORT
      LAYER M4 ;
        RECT  0 21.12 0.192 21.144 ;
    END
  END od[20]
  PIN od[210]
    DIRECTION OUTPUT ;
    USE SIGNAL ;
    PORT
      LAYER M4 ;
        RECT  0 30.24 0.192 30.264 ;
    END
  END od[210]
  PIN od[211]
    DIRECTION OUTPUT ;
    USE SIGNAL ;
    PORT
      LAYER M4 ;
        RECT  0 30.288 0.192 30.312 ;
    END
  END od[211]
  PIN od[212]
    DIRECTION OUTPUT ;
    USE SIGNAL ;
    PORT
      LAYER M4 ;
        RECT  0 30.336 0.192 30.36 ;
    END
  END od[212]
  PIN od[213]
    DIRECTION OUTPUT ;
    USE SIGNAL ;
    PORT
      LAYER M4 ;
        RECT  0 30.384 0.192 30.408 ;
    END
  END od[213]
  PIN od[214]
    DIRECTION OUTPUT ;
    USE SIGNAL ;
    PORT
      LAYER M4 ;
        RECT  0 30.432 0.192 30.456 ;
    END
  END od[214]
  PIN od[215]
    DIRECTION OUTPUT ;
    USE SIGNAL ;
    PORT
      LAYER M4 ;
        RECT  0 30.48 0.192 30.504 ;
    END
  END od[215]
  PIN od[216]
    DIRECTION OUTPUT ;
    USE SIGNAL ;
    PORT
      LAYER M4 ;
        RECT  0 30.528 0.192 30.552 ;
    END
  END od[216]
  PIN od[217]
    DIRECTION OUTPUT ;
    USE SIGNAL ;
    PORT
      LAYER M4 ;
        RECT  0 30.576 0.192 30.6 ;
    END
  END od[217]
  PIN od[218]
    DIRECTION OUTPUT ;
    USE SIGNAL ;
    PORT
      LAYER M4 ;
        RECT  0 30.624 0.192 30.648 ;
    END
  END od[218]
  PIN od[219]
    DIRECTION OUTPUT ;
    USE SIGNAL ;
    PORT
      LAYER M4 ;
        RECT  0 30.672 0.192 30.696 ;
    END
  END od[219]
  PIN od[21]
    DIRECTION OUTPUT ;
    USE SIGNAL ;
    PORT
      LAYER M4 ;
        RECT  0 21.168 0.192 21.192 ;
    END
  END od[21]
  PIN od[220]
    DIRECTION OUTPUT ;
    USE SIGNAL ;
    PORT
      LAYER M4 ;
        RECT  0 30.72 0.192 30.744 ;
    END
  END od[220]
  PIN od[221]
    DIRECTION OUTPUT ;
    USE SIGNAL ;
    PORT
      LAYER M4 ;
        RECT  0 30.768 0.192 30.792 ;
    END
  END od[221]
  PIN od[222]
    DIRECTION OUTPUT ;
    USE SIGNAL ;
    PORT
      LAYER M4 ;
        RECT  0 30.816 0.192 30.84 ;
    END
  END od[222]
  PIN od[223]
    DIRECTION OUTPUT ;
    USE SIGNAL ;
    PORT
      LAYER M4 ;
        RECT  0 30.864 0.192 30.888 ;
    END
  END od[223]
  PIN od[224]
    DIRECTION OUTPUT ;
    USE SIGNAL ;
    PORT
      LAYER M4 ;
        RECT  0 30.912 0.192 30.936 ;
    END
  END od[224]
  PIN od[225]
    DIRECTION OUTPUT ;
    USE SIGNAL ;
    PORT
      LAYER M4 ;
        RECT  0 30.96 0.192 30.984 ;
    END
  END od[225]
  PIN od[226]
    DIRECTION OUTPUT ;
    USE SIGNAL ;
    PORT
      LAYER M4 ;
        RECT  0 31.008 0.192 31.032 ;
    END
  END od[226]
  PIN od[227]
    DIRECTION OUTPUT ;
    USE SIGNAL ;
    PORT
      LAYER M4 ;
        RECT  0 31.056 0.192 31.08 ;
    END
  END od[227]
  PIN od[228]
    DIRECTION OUTPUT ;
    USE SIGNAL ;
    PORT
      LAYER M4 ;
        RECT  0 31.104 0.192 31.128 ;
    END
  END od[228]
  PIN od[229]
    DIRECTION OUTPUT ;
    USE SIGNAL ;
    PORT
      LAYER M4 ;
        RECT  0 31.152 0.192 31.176 ;
    END
  END od[229]
  PIN od[22]
    DIRECTION OUTPUT ;
    USE SIGNAL ;
    PORT
      LAYER M4 ;
        RECT  0 21.216 0.192 21.24 ;
    END
  END od[22]
  PIN od[230]
    DIRECTION OUTPUT ;
    USE SIGNAL ;
    PORT
      LAYER M4 ;
        RECT  0 31.2 0.192 31.224 ;
    END
  END od[230]
  PIN od[231]
    DIRECTION OUTPUT ;
    USE SIGNAL ;
    PORT
      LAYER M4 ;
        RECT  0 31.248 0.192 31.272 ;
    END
  END od[231]
  PIN od[232]
    DIRECTION OUTPUT ;
    USE SIGNAL ;
    PORT
      LAYER M4 ;
        RECT  0 31.296 0.192 31.32 ;
    END
  END od[232]
  PIN od[233]
    DIRECTION OUTPUT ;
    USE SIGNAL ;
    PORT
      LAYER M4 ;
        RECT  0 31.344 0.192 31.368 ;
    END
  END od[233]
  PIN od[234]
    DIRECTION OUTPUT ;
    USE SIGNAL ;
    PORT
      LAYER M4 ;
        RECT  0 31.392 0.192 31.416 ;
    END
  END od[234]
  PIN od[235]
    DIRECTION OUTPUT ;
    USE SIGNAL ;
    PORT
      LAYER M4 ;
        RECT  0 31.44 0.192 31.464 ;
    END
  END od[235]
  PIN od[236]
    DIRECTION OUTPUT ;
    USE SIGNAL ;
    PORT
      LAYER M4 ;
        RECT  0 31.488 0.192 31.512 ;
    END
  END od[236]
  PIN od[237]
    DIRECTION OUTPUT ;
    USE SIGNAL ;
    PORT
      LAYER M4 ;
        RECT  0 31.536 0.192 31.56 ;
    END
  END od[237]
  PIN od[238]
    DIRECTION OUTPUT ;
    USE SIGNAL ;
    PORT
      LAYER M4 ;
        RECT  0 31.584 0.192 31.608 ;
    END
  END od[238]
  PIN od[239]
    DIRECTION OUTPUT ;
    USE SIGNAL ;
    PORT
      LAYER M4 ;
        RECT  0 31.632 0.192 31.656 ;
    END
  END od[239]
  PIN od[23]
    DIRECTION OUTPUT ;
    USE SIGNAL ;
    PORT
      LAYER M4 ;
        RECT  0 21.264 0.192 21.288 ;
    END
  END od[23]
  PIN od[240]
    DIRECTION OUTPUT ;
    USE SIGNAL ;
    PORT
      LAYER M4 ;
        RECT  0 31.68 0.192 31.704 ;
    END
  END od[240]
  PIN od[241]
    DIRECTION OUTPUT ;
    USE SIGNAL ;
    PORT
      LAYER M4 ;
        RECT  0 31.728 0.192 31.752 ;
    END
  END od[241]
  PIN od[242]
    DIRECTION OUTPUT ;
    USE SIGNAL ;
    PORT
      LAYER M4 ;
        RECT  0 31.776 0.192 31.8 ;
    END
  END od[242]
  PIN od[243]
    DIRECTION OUTPUT ;
    USE SIGNAL ;
    PORT
      LAYER M4 ;
        RECT  0 31.824 0.192 31.848 ;
    END
  END od[243]
  PIN od[244]
    DIRECTION OUTPUT ;
    USE SIGNAL ;
    PORT
      LAYER M4 ;
        RECT  0 31.872 0.192 31.896 ;
    END
  END od[244]
  PIN od[245]
    DIRECTION OUTPUT ;
    USE SIGNAL ;
    PORT
      LAYER M4 ;
        RECT  0 31.92 0.192 31.944 ;
    END
  END od[245]
  PIN od[246]
    DIRECTION OUTPUT ;
    USE SIGNAL ;
    PORT
      LAYER M4 ;
        RECT  0 31.968 0.192 31.992 ;
    END
  END od[246]
  PIN od[247]
    DIRECTION OUTPUT ;
    USE SIGNAL ;
    PORT
      LAYER M4 ;
        RECT  0 32.016 0.192 32.04 ;
    END
  END od[247]
  PIN od[248]
    DIRECTION OUTPUT ;
    USE SIGNAL ;
    PORT
      LAYER M4 ;
        RECT  0 32.064 0.192 32.088 ;
    END
  END od[248]
  PIN od[249]
    DIRECTION OUTPUT ;
    USE SIGNAL ;
    PORT
      LAYER M4 ;
        RECT  0 32.112 0.192 32.136 ;
    END
  END od[249]
  PIN od[24]
    DIRECTION OUTPUT ;
    USE SIGNAL ;
    PORT
      LAYER M4 ;
        RECT  0 21.312 0.192 21.336 ;
    END
  END od[24]
  PIN od[250]
    DIRECTION OUTPUT ;
    USE SIGNAL ;
    PORT
      LAYER M4 ;
        RECT  0 32.16 0.192 32.184 ;
    END
  END od[250]
  PIN od[251]
    DIRECTION OUTPUT ;
    USE SIGNAL ;
    PORT
      LAYER M4 ;
        RECT  0 32.208 0.192 32.232 ;
    END
  END od[251]
  PIN od[252]
    DIRECTION OUTPUT ;
    USE SIGNAL ;
    PORT
      LAYER M4 ;
        RECT  0 32.256 0.192 32.28 ;
    END
  END od[252]
  PIN od[253]
    DIRECTION OUTPUT ;
    USE SIGNAL ;
    PORT
      LAYER M4 ;
        RECT  0 32.304 0.192 32.328 ;
    END
  END od[253]
  PIN od[254]
    DIRECTION OUTPUT ;
    USE SIGNAL ;
    PORT
      LAYER M4 ;
        RECT  0 32.352 0.192 32.376 ;
    END
  END od[254]
  PIN od[255]
    DIRECTION OUTPUT ;
    USE SIGNAL ;
    PORT
      LAYER M4 ;
        RECT  0 32.4 0.192 32.424 ;
    END
  END od[255]
  PIN od[256]
    DIRECTION OUTPUT ;
    USE SIGNAL ;
    PORT
      LAYER M4 ;
        RECT  0 32.448 0.192 32.472 ;
    END
  END od[256]
  PIN od[257]
    DIRECTION OUTPUT ;
    USE SIGNAL ;
    PORT
      LAYER M4 ;
        RECT  0 32.496 0.192 32.52 ;
    END
  END od[257]
  PIN od[258]
    DIRECTION OUTPUT ;
    USE SIGNAL ;
    PORT
      LAYER M4 ;
        RECT  0 32.544 0.192 32.568 ;
    END
  END od[258]
  PIN od[259]
    DIRECTION OUTPUT ;
    USE SIGNAL ;
    PORT
      LAYER M4 ;
        RECT  0 32.592 0.192 32.616 ;
    END
  END od[259]
  PIN od[25]
    DIRECTION OUTPUT ;
    USE SIGNAL ;
    PORT
      LAYER M4 ;
        RECT  0 21.36 0.192 21.384 ;
    END
  END od[25]
  PIN od[260]
    DIRECTION OUTPUT ;
    USE SIGNAL ;
    PORT
      LAYER M4 ;
        RECT  0 32.64 0.192 32.664 ;
    END
  END od[260]
  PIN od[261]
    DIRECTION OUTPUT ;
    USE SIGNAL ;
    PORT
      LAYER M4 ;
        RECT  0 32.688 0.192 32.712 ;
    END
  END od[261]
  PIN od[262]
    DIRECTION OUTPUT ;
    USE SIGNAL ;
    PORT
      LAYER M4 ;
        RECT  0 32.736 0.192 32.76 ;
    END
  END od[262]
  PIN od[263]
    DIRECTION OUTPUT ;
    USE SIGNAL ;
    PORT
      LAYER M4 ;
        RECT  0 32.784 0.192 32.808 ;
    END
  END od[263]
  PIN od[264]
    DIRECTION OUTPUT ;
    USE SIGNAL ;
    PORT
      LAYER M4 ;
        RECT  0 32.832 0.192 32.856 ;
    END
  END od[264]
  PIN od[265]
    DIRECTION OUTPUT ;
    USE SIGNAL ;
    PORT
      LAYER M4 ;
        RECT  0 32.88 0.192 32.904 ;
    END
  END od[265]
  PIN od[266]
    DIRECTION OUTPUT ;
    USE SIGNAL ;
    PORT
      LAYER M4 ;
        RECT  0 32.928 0.192 32.952 ;
    END
  END od[266]
  PIN od[267]
    DIRECTION OUTPUT ;
    USE SIGNAL ;
    PORT
      LAYER M4 ;
        RECT  0 32.976 0.192 33 ;
    END
  END od[267]
  PIN od[268]
    DIRECTION OUTPUT ;
    USE SIGNAL ;
    PORT
      LAYER M4 ;
        RECT  0 33.024 0.192 33.048 ;
    END
  END od[268]
  PIN od[269]
    DIRECTION OUTPUT ;
    USE SIGNAL ;
    PORT
      LAYER M4 ;
        RECT  0 33.072 0.192 33.096 ;
    END
  END od[269]
  PIN od[26]
    DIRECTION OUTPUT ;
    USE SIGNAL ;
    PORT
      LAYER M4 ;
        RECT  0 21.408 0.192 21.432 ;
    END
  END od[26]
  PIN od[270]
    DIRECTION OUTPUT ;
    USE SIGNAL ;
    PORT
      LAYER M4 ;
        RECT  0 33.12 0.192 33.144 ;
    END
  END od[270]
  PIN od[271]
    DIRECTION OUTPUT ;
    USE SIGNAL ;
    PORT
      LAYER M4 ;
        RECT  0 33.168 0.192 33.192 ;
    END
  END od[271]
  PIN od[272]
    DIRECTION OUTPUT ;
    USE SIGNAL ;
    PORT
      LAYER M4 ;
        RECT  0 33.216 0.192 33.24 ;
    END
  END od[272]
  PIN od[273]
    DIRECTION OUTPUT ;
    USE SIGNAL ;
    PORT
      LAYER M4 ;
        RECT  0 33.264 0.192 33.288 ;
    END
  END od[273]
  PIN od[274]
    DIRECTION OUTPUT ;
    USE SIGNAL ;
    PORT
      LAYER M4 ;
        RECT  0 33.312 0.192 33.336 ;
    END
  END od[274]
  PIN od[275]
    DIRECTION OUTPUT ;
    USE SIGNAL ;
    PORT
      LAYER M4 ;
        RECT  0 33.36 0.192 33.384 ;
    END
  END od[275]
  PIN od[276]
    DIRECTION OUTPUT ;
    USE SIGNAL ;
    PORT
      LAYER M4 ;
        RECT  0 33.408 0.192 33.432 ;
    END
  END od[276]
  PIN od[277]
    DIRECTION OUTPUT ;
    USE SIGNAL ;
    PORT
      LAYER M4 ;
        RECT  0 33.456 0.192 33.48 ;
    END
  END od[277]
  PIN od[278]
    DIRECTION OUTPUT ;
    USE SIGNAL ;
    PORT
      LAYER M4 ;
        RECT  0 33.504 0.192 33.528 ;
    END
  END od[278]
  PIN od[279]
    DIRECTION OUTPUT ;
    USE SIGNAL ;
    PORT
      LAYER M4 ;
        RECT  0 33.552 0.192 33.576 ;
    END
  END od[279]
  PIN od[27]
    DIRECTION OUTPUT ;
    USE SIGNAL ;
    PORT
      LAYER M4 ;
        RECT  0 21.456 0.192 21.48 ;
    END
  END od[27]
  PIN od[280]
    DIRECTION OUTPUT ;
    USE SIGNAL ;
    PORT
      LAYER M4 ;
        RECT  0 33.6 0.192 33.624 ;
    END
  END od[280]
  PIN od[281]
    DIRECTION OUTPUT ;
    USE SIGNAL ;
    PORT
      LAYER M4 ;
        RECT  0 33.648 0.192 33.672 ;
    END
  END od[281]
  PIN od[282]
    DIRECTION OUTPUT ;
    USE SIGNAL ;
    PORT
      LAYER M4 ;
        RECT  0 33.696 0.192 33.72 ;
    END
  END od[282]
  PIN od[283]
    DIRECTION OUTPUT ;
    USE SIGNAL ;
    PORT
      LAYER M4 ;
        RECT  0 33.744 0.192 33.768 ;
    END
  END od[283]
  PIN od[284]
    DIRECTION OUTPUT ;
    USE SIGNAL ;
    PORT
      LAYER M4 ;
        RECT  0 33.792 0.192 33.816 ;
    END
  END od[284]
  PIN od[285]
    DIRECTION OUTPUT ;
    USE SIGNAL ;
    PORT
      LAYER M4 ;
        RECT  0 33.84 0.192 33.864 ;
    END
  END od[285]
  PIN od[286]
    DIRECTION OUTPUT ;
    USE SIGNAL ;
    PORT
      LAYER M4 ;
        RECT  0 33.888 0.192 33.912 ;
    END
  END od[286]
  PIN od[287]
    DIRECTION OUTPUT ;
    USE SIGNAL ;
    PORT
      LAYER M4 ;
        RECT  0 33.936 0.192 33.96 ;
    END
  END od[287]
  PIN od[288]
    DIRECTION OUTPUT ;
    USE SIGNAL ;
    PORT
      LAYER M4 ;
        RECT  0 33.984 0.192 34.008 ;
    END
  END od[288]
  PIN od[289]
    DIRECTION OUTPUT ;
    USE SIGNAL ;
    PORT
      LAYER M4 ;
        RECT  0 34.032 0.192 34.056 ;
    END
  END od[289]
  PIN od[28]
    DIRECTION OUTPUT ;
    USE SIGNAL ;
    PORT
      LAYER M4 ;
        RECT  0 21.504 0.192 21.528 ;
    END
  END od[28]
  PIN od[290]
    DIRECTION OUTPUT ;
    USE SIGNAL ;
    PORT
      LAYER M4 ;
        RECT  0 34.08 0.192 34.104 ;
    END
  END od[290]
  PIN od[291]
    DIRECTION OUTPUT ;
    USE SIGNAL ;
    PORT
      LAYER M4 ;
        RECT  0 34.128 0.192 34.152 ;
    END
  END od[291]
  PIN od[292]
    DIRECTION OUTPUT ;
    USE SIGNAL ;
    PORT
      LAYER M4 ;
        RECT  0 34.176 0.192 34.2 ;
    END
  END od[292]
  PIN od[293]
    DIRECTION OUTPUT ;
    USE SIGNAL ;
    PORT
      LAYER M4 ;
        RECT  0 34.224 0.192 34.248 ;
    END
  END od[293]
  PIN od[294]
    DIRECTION OUTPUT ;
    USE SIGNAL ;
    PORT
      LAYER M4 ;
        RECT  0 34.272 0.192 34.296 ;
    END
  END od[294]
  PIN od[295]
    DIRECTION OUTPUT ;
    USE SIGNAL ;
    PORT
      LAYER M4 ;
        RECT  0 34.32 0.192 34.344 ;
    END
  END od[295]
  PIN od[296]
    DIRECTION OUTPUT ;
    USE SIGNAL ;
    PORT
      LAYER M4 ;
        RECT  0 34.368 0.192 34.392 ;
    END
  END od[296]
  PIN od[297]
    DIRECTION OUTPUT ;
    USE SIGNAL ;
    PORT
      LAYER M4 ;
        RECT  0 34.416 0.192 34.44 ;
    END
  END od[297]
  PIN od[298]
    DIRECTION OUTPUT ;
    USE SIGNAL ;
    PORT
      LAYER M4 ;
        RECT  0 34.464 0.192 34.488 ;
    END
  END od[298]
  PIN od[299]
    DIRECTION OUTPUT ;
    USE SIGNAL ;
    PORT
      LAYER M4 ;
        RECT  0 34.512 0.192 34.536 ;
    END
  END od[299]
  PIN od[29]
    DIRECTION OUTPUT ;
    USE SIGNAL ;
    PORT
      LAYER M4 ;
        RECT  0 21.552 0.192 21.576 ;
    END
  END od[29]
  PIN od[2]
    DIRECTION OUTPUT ;
    USE SIGNAL ;
    PORT
      LAYER M4 ;
        RECT  0 20.256 0.192 20.28 ;
    END
  END od[2]
  PIN od[300]
    DIRECTION OUTPUT ;
    USE SIGNAL ;
    PORT
      LAYER M4 ;
        RECT  0 34.56 0.192 34.584 ;
    END
  END od[300]
  PIN od[301]
    DIRECTION OUTPUT ;
    USE SIGNAL ;
    PORT
      LAYER M4 ;
        RECT  0 34.608 0.192 34.632 ;
    END
  END od[301]
  PIN od[302]
    DIRECTION OUTPUT ;
    USE SIGNAL ;
    PORT
      LAYER M4 ;
        RECT  0 34.656 0.192 34.68 ;
    END
  END od[302]
  PIN od[303]
    DIRECTION OUTPUT ;
    USE SIGNAL ;
    PORT
      LAYER M4 ;
        RECT  0 34.704 0.192 34.728 ;
    END
  END od[303]
  PIN od[304]
    DIRECTION OUTPUT ;
    USE SIGNAL ;
    PORT
      LAYER M4 ;
        RECT  0 34.752 0.192 34.776 ;
    END
  END od[304]
  PIN od[305]
    DIRECTION OUTPUT ;
    USE SIGNAL ;
    PORT
      LAYER M4 ;
        RECT  0 34.8 0.192 34.824 ;
    END
  END od[305]
  PIN od[306]
    DIRECTION OUTPUT ;
    USE SIGNAL ;
    PORT
      LAYER M4 ;
        RECT  0 34.848 0.192 34.872 ;
    END
  END od[306]
  PIN od[307]
    DIRECTION OUTPUT ;
    USE SIGNAL ;
    PORT
      LAYER M4 ;
        RECT  0 34.896 0.192 34.92 ;
    END
  END od[307]
  PIN od[308]
    DIRECTION OUTPUT ;
    USE SIGNAL ;
    PORT
      LAYER M4 ;
        RECT  0 34.944 0.192 34.968 ;
    END
  END od[308]
  PIN od[309]
    DIRECTION OUTPUT ;
    USE SIGNAL ;
    PORT
      LAYER M4 ;
        RECT  0 34.992 0.192 35.016 ;
    END
  END od[309]
  PIN od[30]
    DIRECTION OUTPUT ;
    USE SIGNAL ;
    PORT
      LAYER M4 ;
        RECT  0 21.6 0.192 21.624 ;
    END
  END od[30]
  PIN od[310]
    DIRECTION OUTPUT ;
    USE SIGNAL ;
    PORT
      LAYER M4 ;
        RECT  0 35.04 0.192 35.064 ;
    END
  END od[310]
  PIN od[311]
    DIRECTION OUTPUT ;
    USE SIGNAL ;
    PORT
      LAYER M4 ;
        RECT  0 35.088 0.192 35.112 ;
    END
  END od[311]
  PIN od[312]
    DIRECTION OUTPUT ;
    USE SIGNAL ;
    PORT
      LAYER M4 ;
        RECT  0 35.136 0.192 35.16 ;
    END
  END od[312]
  PIN od[313]
    DIRECTION OUTPUT ;
    USE SIGNAL ;
    PORT
      LAYER M4 ;
        RECT  0 35.184 0.192 35.208 ;
    END
  END od[313]
  PIN od[314]
    DIRECTION OUTPUT ;
    USE SIGNAL ;
    PORT
      LAYER M4 ;
        RECT  0 35.232 0.192 35.256 ;
    END
  END od[314]
  PIN od[315]
    DIRECTION OUTPUT ;
    USE SIGNAL ;
    PORT
      LAYER M4 ;
        RECT  0 35.28 0.192 35.304 ;
    END
  END od[315]
  PIN od[316]
    DIRECTION OUTPUT ;
    USE SIGNAL ;
    PORT
      LAYER M4 ;
        RECT  0 35.328 0.192 35.352 ;
    END
  END od[316]
  PIN od[317]
    DIRECTION OUTPUT ;
    USE SIGNAL ;
    PORT
      LAYER M4 ;
        RECT  0 35.376 0.192 35.4 ;
    END
  END od[317]
  PIN od[318]
    DIRECTION OUTPUT ;
    USE SIGNAL ;
    PORT
      LAYER M4 ;
        RECT  0 35.424 0.192 35.448 ;
    END
  END od[318]
  PIN od[319]
    DIRECTION OUTPUT ;
    USE SIGNAL ;
    PORT
      LAYER M4 ;
        RECT  0 35.472 0.192 35.496 ;
    END
  END od[319]
  PIN od[31]
    DIRECTION OUTPUT ;
    USE SIGNAL ;
    PORT
      LAYER M4 ;
        RECT  0 21.648 0.192 21.672 ;
    END
  END od[31]
  PIN od[320]
    DIRECTION OUTPUT ;
    USE SIGNAL ;
    PORT
      LAYER M4 ;
        RECT  0 35.52 0.192 35.544 ;
    END
  END od[320]
  PIN od[321]
    DIRECTION OUTPUT ;
    USE SIGNAL ;
    PORT
      LAYER M4 ;
        RECT  0 35.568 0.192 35.592 ;
    END
  END od[321]
  PIN od[322]
    DIRECTION OUTPUT ;
    USE SIGNAL ;
    PORT
      LAYER M4 ;
        RECT  0 35.616 0.192 35.64 ;
    END
  END od[322]
  PIN od[323]
    DIRECTION OUTPUT ;
    USE SIGNAL ;
    PORT
      LAYER M4 ;
        RECT  0 35.664 0.192 35.688 ;
    END
  END od[323]
  PIN od[324]
    DIRECTION OUTPUT ;
    USE SIGNAL ;
    PORT
      LAYER M4 ;
        RECT  0 35.712 0.192 35.736 ;
    END
  END od[324]
  PIN od[325]
    DIRECTION OUTPUT ;
    USE SIGNAL ;
    PORT
      LAYER M4 ;
        RECT  0 35.76 0.192 35.784 ;
    END
  END od[325]
  PIN od[326]
    DIRECTION OUTPUT ;
    USE SIGNAL ;
    PORT
      LAYER M4 ;
        RECT  0 35.808 0.192 35.832 ;
    END
  END od[326]
  PIN od[327]
    DIRECTION OUTPUT ;
    USE SIGNAL ;
    PORT
      LAYER M4 ;
        RECT  0 35.856 0.192 35.88 ;
    END
  END od[327]
  PIN od[328]
    DIRECTION OUTPUT ;
    USE SIGNAL ;
    PORT
      LAYER M4 ;
        RECT  0 35.904 0.192 35.928 ;
    END
  END od[328]
  PIN od[329]
    DIRECTION OUTPUT ;
    USE SIGNAL ;
    PORT
      LAYER M4 ;
        RECT  0 35.952 0.192 35.976 ;
    END
  END od[329]
  PIN od[32]
    DIRECTION OUTPUT ;
    USE SIGNAL ;
    PORT
      LAYER M4 ;
        RECT  0 21.696 0.192 21.72 ;
    END
  END od[32]
  PIN od[330]
    DIRECTION OUTPUT ;
    USE SIGNAL ;
    PORT
      LAYER M4 ;
        RECT  0 36 0.192 36.024 ;
    END
  END od[330]
  PIN od[331]
    DIRECTION OUTPUT ;
    USE SIGNAL ;
    PORT
      LAYER M4 ;
        RECT  0 36.048 0.192 36.072 ;
    END
  END od[331]
  PIN od[332]
    DIRECTION OUTPUT ;
    USE SIGNAL ;
    PORT
      LAYER M4 ;
        RECT  0 36.096 0.192 36.12 ;
    END
  END od[332]
  PIN od[333]
    DIRECTION OUTPUT ;
    USE SIGNAL ;
    PORT
      LAYER M4 ;
        RECT  0 36.144 0.192 36.168 ;
    END
  END od[333]
  PIN od[334]
    DIRECTION OUTPUT ;
    USE SIGNAL ;
    PORT
      LAYER M4 ;
        RECT  0 36.192 0.192 36.216 ;
    END
  END od[334]
  PIN od[335]
    DIRECTION OUTPUT ;
    USE SIGNAL ;
    PORT
      LAYER M4 ;
        RECT  0 36.24 0.192 36.264 ;
    END
  END od[335]
  PIN od[336]
    DIRECTION OUTPUT ;
    USE SIGNAL ;
    PORT
      LAYER M4 ;
        RECT  0 36.288 0.192 36.312 ;
    END
  END od[336]
  PIN od[337]
    DIRECTION OUTPUT ;
    USE SIGNAL ;
    PORT
      LAYER M4 ;
        RECT  0 36.336 0.192 36.36 ;
    END
  END od[337]
  PIN od[338]
    DIRECTION OUTPUT ;
    USE SIGNAL ;
    PORT
      LAYER M4 ;
        RECT  0 36.384 0.192 36.408 ;
    END
  END od[338]
  PIN od[339]
    DIRECTION OUTPUT ;
    USE SIGNAL ;
    PORT
      LAYER M4 ;
        RECT  0 36.432 0.192 36.456 ;
    END
  END od[339]
  PIN od[33]
    DIRECTION OUTPUT ;
    USE SIGNAL ;
    PORT
      LAYER M4 ;
        RECT  0 21.744 0.192 21.768 ;
    END
  END od[33]
  PIN od[340]
    DIRECTION OUTPUT ;
    USE SIGNAL ;
    PORT
      LAYER M4 ;
        RECT  0 36.48 0.192 36.504 ;
    END
  END od[340]
  PIN od[341]
    DIRECTION OUTPUT ;
    USE SIGNAL ;
    PORT
      LAYER M4 ;
        RECT  0 36.528 0.192 36.552 ;
    END
  END od[341]
  PIN od[342]
    DIRECTION OUTPUT ;
    USE SIGNAL ;
    PORT
      LAYER M4 ;
        RECT  0 36.576 0.192 36.6 ;
    END
  END od[342]
  PIN od[343]
    DIRECTION OUTPUT ;
    USE SIGNAL ;
    PORT
      LAYER M4 ;
        RECT  0 36.624 0.192 36.648 ;
    END
  END od[343]
  PIN od[344]
    DIRECTION OUTPUT ;
    USE SIGNAL ;
    PORT
      LAYER M4 ;
        RECT  0 36.672 0.192 36.696 ;
    END
  END od[344]
  PIN od[345]
    DIRECTION OUTPUT ;
    USE SIGNAL ;
    PORT
      LAYER M4 ;
        RECT  0 36.72 0.192 36.744 ;
    END
  END od[345]
  PIN od[346]
    DIRECTION OUTPUT ;
    USE SIGNAL ;
    PORT
      LAYER M4 ;
        RECT  0 36.768 0.192 36.792 ;
    END
  END od[346]
  PIN od[347]
    DIRECTION OUTPUT ;
    USE SIGNAL ;
    PORT
      LAYER M4 ;
        RECT  0 36.816 0.192 36.84 ;
    END
  END od[347]
  PIN od[348]
    DIRECTION OUTPUT ;
    USE SIGNAL ;
    PORT
      LAYER M4 ;
        RECT  0 36.864 0.192 36.888 ;
    END
  END od[348]
  PIN od[349]
    DIRECTION OUTPUT ;
    USE SIGNAL ;
    PORT
      LAYER M4 ;
        RECT  0 36.912 0.192 36.936 ;
    END
  END od[349]
  PIN od[34]
    DIRECTION OUTPUT ;
    USE SIGNAL ;
    PORT
      LAYER M4 ;
        RECT  0 21.792 0.192 21.816 ;
    END
  END od[34]
  PIN od[350]
    DIRECTION OUTPUT ;
    USE SIGNAL ;
    PORT
      LAYER M4 ;
        RECT  0 36.96 0.192 36.984 ;
    END
  END od[350]
  PIN od[351]
    DIRECTION OUTPUT ;
    USE SIGNAL ;
    PORT
      LAYER M4 ;
        RECT  0 37.008 0.192 37.032 ;
    END
  END od[351]
  PIN od[352]
    DIRECTION OUTPUT ;
    USE SIGNAL ;
    PORT
      LAYER M4 ;
        RECT  0 37.056 0.192 37.08 ;
    END
  END od[352]
  PIN od[353]
    DIRECTION OUTPUT ;
    USE SIGNAL ;
    PORT
      LAYER M4 ;
        RECT  0 37.104 0.192 37.128 ;
    END
  END od[353]
  PIN od[354]
    DIRECTION OUTPUT ;
    USE SIGNAL ;
    PORT
      LAYER M4 ;
        RECT  0 37.152 0.192 37.176 ;
    END
  END od[354]
  PIN od[355]
    DIRECTION OUTPUT ;
    USE SIGNAL ;
    PORT
      LAYER M4 ;
        RECT  0 37.2 0.192 37.224 ;
    END
  END od[355]
  PIN od[356]
    DIRECTION OUTPUT ;
    USE SIGNAL ;
    PORT
      LAYER M4 ;
        RECT  0 37.248 0.192 37.272 ;
    END
  END od[356]
  PIN od[357]
    DIRECTION OUTPUT ;
    USE SIGNAL ;
    PORT
      LAYER M4 ;
        RECT  0 37.296 0.192 37.32 ;
    END
  END od[357]
  PIN od[358]
    DIRECTION OUTPUT ;
    USE SIGNAL ;
    PORT
      LAYER M4 ;
        RECT  0 37.344 0.192 37.368 ;
    END
  END od[358]
  PIN od[359]
    DIRECTION OUTPUT ;
    USE SIGNAL ;
    PORT
      LAYER M4 ;
        RECT  0 37.392 0.192 37.416 ;
    END
  END od[359]
  PIN od[35]
    DIRECTION OUTPUT ;
    USE SIGNAL ;
    PORT
      LAYER M4 ;
        RECT  0 21.84 0.192 21.864 ;
    END
  END od[35]
  PIN od[360]
    DIRECTION OUTPUT ;
    USE SIGNAL ;
    PORT
      LAYER M4 ;
        RECT  0 37.44 0.192 37.464 ;
    END
  END od[360]
  PIN od[361]
    DIRECTION OUTPUT ;
    USE SIGNAL ;
    PORT
      LAYER M4 ;
        RECT  0 37.488 0.192 37.512 ;
    END
  END od[361]
  PIN od[362]
    DIRECTION OUTPUT ;
    USE SIGNAL ;
    PORT
      LAYER M4 ;
        RECT  0 37.536 0.192 37.56 ;
    END
  END od[362]
  PIN od[363]
    DIRECTION OUTPUT ;
    USE SIGNAL ;
    PORT
      LAYER M4 ;
        RECT  0 37.584 0.192 37.608 ;
    END
  END od[363]
  PIN od[364]
    DIRECTION OUTPUT ;
    USE SIGNAL ;
    PORT
      LAYER M4 ;
        RECT  0 37.632 0.192 37.656 ;
    END
  END od[364]
  PIN od[365]
    DIRECTION OUTPUT ;
    USE SIGNAL ;
    PORT
      LAYER M4 ;
        RECT  0 37.68 0.192 37.704 ;
    END
  END od[365]
  PIN od[366]
    DIRECTION OUTPUT ;
    USE SIGNAL ;
    PORT
      LAYER M4 ;
        RECT  0 37.728 0.192 37.752 ;
    END
  END od[366]
  PIN od[367]
    DIRECTION OUTPUT ;
    USE SIGNAL ;
    PORT
      LAYER M4 ;
        RECT  0 37.776 0.192 37.8 ;
    END
  END od[367]
  PIN od[368]
    DIRECTION OUTPUT ;
    USE SIGNAL ;
    PORT
      LAYER M4 ;
        RECT  0 37.824 0.192 37.848 ;
    END
  END od[368]
  PIN od[369]
    DIRECTION OUTPUT ;
    USE SIGNAL ;
    PORT
      LAYER M4 ;
        RECT  0 37.872 0.192 37.896 ;
    END
  END od[369]
  PIN od[36]
    DIRECTION OUTPUT ;
    USE SIGNAL ;
    PORT
      LAYER M4 ;
        RECT  0 21.888 0.192 21.912 ;
    END
  END od[36]
  PIN od[370]
    DIRECTION OUTPUT ;
    USE SIGNAL ;
    PORT
      LAYER M4 ;
        RECT  0 37.92 0.192 37.944 ;
    END
  END od[370]
  PIN od[371]
    DIRECTION OUTPUT ;
    USE SIGNAL ;
    PORT
      LAYER M4 ;
        RECT  0 37.968 0.192 37.992 ;
    END
  END od[371]
  PIN od[372]
    DIRECTION OUTPUT ;
    USE SIGNAL ;
    PORT
      LAYER M4 ;
        RECT  0 38.016 0.192 38.04 ;
    END
  END od[372]
  PIN od[373]
    DIRECTION OUTPUT ;
    USE SIGNAL ;
    PORT
      LAYER M4 ;
        RECT  0 38.064 0.192 38.088 ;
    END
  END od[373]
  PIN od[374]
    DIRECTION OUTPUT ;
    USE SIGNAL ;
    PORT
      LAYER M4 ;
        RECT  0 38.112 0.192 38.136 ;
    END
  END od[374]
  PIN od[375]
    DIRECTION OUTPUT ;
    USE SIGNAL ;
    PORT
      LAYER M4 ;
        RECT  0 38.16 0.192 38.184 ;
    END
  END od[375]
  PIN od[376]
    DIRECTION OUTPUT ;
    USE SIGNAL ;
    PORT
      LAYER M4 ;
        RECT  0 38.208 0.192 38.232 ;
    END
  END od[376]
  PIN od[377]
    DIRECTION OUTPUT ;
    USE SIGNAL ;
    PORT
      LAYER M4 ;
        RECT  0 38.256 0.192 38.28 ;
    END
  END od[377]
  PIN od[378]
    DIRECTION OUTPUT ;
    USE SIGNAL ;
    PORT
      LAYER M4 ;
        RECT  0 38.304 0.192 38.328 ;
    END
  END od[378]
  PIN od[379]
    DIRECTION OUTPUT ;
    USE SIGNAL ;
    PORT
      LAYER M4 ;
        RECT  0 38.352 0.192 38.376 ;
    END
  END od[379]
  PIN od[37]
    DIRECTION OUTPUT ;
    USE SIGNAL ;
    PORT
      LAYER M4 ;
        RECT  0 21.936 0.192 21.96 ;
    END
  END od[37]
  PIN od[380]
    DIRECTION OUTPUT ;
    USE SIGNAL ;
    PORT
      LAYER M4 ;
        RECT  0 38.4 0.192 38.424 ;
    END
  END od[380]
  PIN od[381]
    DIRECTION OUTPUT ;
    USE SIGNAL ;
    PORT
      LAYER M4 ;
        RECT  0 38.448 0.192 38.472 ;
    END
  END od[381]
  PIN od[382]
    DIRECTION OUTPUT ;
    USE SIGNAL ;
    PORT
      LAYER M4 ;
        RECT  0 38.496 0.192 38.52 ;
    END
  END od[382]
  PIN od[383]
    DIRECTION OUTPUT ;
    USE SIGNAL ;
    PORT
      LAYER M4 ;
        RECT  0 38.544 0.192 38.568 ;
    END
  END od[383]
  PIN od[384]
    DIRECTION OUTPUT ;
    USE SIGNAL ;
    PORT
      LAYER M4 ;
        RECT  0 38.592 0.192 38.616 ;
    END
  END od[384]
  PIN od[385]
    DIRECTION OUTPUT ;
    USE SIGNAL ;
    PORT
      LAYER M4 ;
        RECT  0 38.64 0.192 38.664 ;
    END
  END od[385]
  PIN od[386]
    DIRECTION OUTPUT ;
    USE SIGNAL ;
    PORT
      LAYER M4 ;
        RECT  0 38.688 0.192 38.712 ;
    END
  END od[386]
  PIN od[387]
    DIRECTION OUTPUT ;
    USE SIGNAL ;
    PORT
      LAYER M4 ;
        RECT  0 38.736 0.192 38.76 ;
    END
  END od[387]
  PIN od[388]
    DIRECTION OUTPUT ;
    USE SIGNAL ;
    PORT
      LAYER M4 ;
        RECT  0 38.784 0.192 38.808 ;
    END
  END od[388]
  PIN od[389]
    DIRECTION OUTPUT ;
    USE SIGNAL ;
    PORT
      LAYER M4 ;
        RECT  0 38.832 0.192 38.856 ;
    END
  END od[389]
  PIN od[38]
    DIRECTION OUTPUT ;
    USE SIGNAL ;
    PORT
      LAYER M4 ;
        RECT  0 21.984 0.192 22.008 ;
    END
  END od[38]
  PIN od[390]
    DIRECTION OUTPUT ;
    USE SIGNAL ;
    PORT
      LAYER M4 ;
        RECT  0 38.88 0.192 38.904 ;
    END
  END od[390]
  PIN od[391]
    DIRECTION OUTPUT ;
    USE SIGNAL ;
    PORT
      LAYER M4 ;
        RECT  0 38.928 0.192 38.952 ;
    END
  END od[391]
  PIN od[392]
    DIRECTION OUTPUT ;
    USE SIGNAL ;
    PORT
      LAYER M4 ;
        RECT  0 38.976 0.192 39 ;
    END
  END od[392]
  PIN od[393]
    DIRECTION OUTPUT ;
    USE SIGNAL ;
    PORT
      LAYER M4 ;
        RECT  0 39.024 0.192 39.048 ;
    END
  END od[393]
  PIN od[394]
    DIRECTION OUTPUT ;
    USE SIGNAL ;
    PORT
      LAYER M4 ;
        RECT  0 39.072 0.192 39.096 ;
    END
  END od[394]
  PIN od[395]
    DIRECTION OUTPUT ;
    USE SIGNAL ;
    PORT
      LAYER M4 ;
        RECT  0 39.12 0.192 39.144 ;
    END
  END od[395]
  PIN od[396]
    DIRECTION OUTPUT ;
    USE SIGNAL ;
    PORT
      LAYER M4 ;
        RECT  0 39.168 0.192 39.192 ;
    END
  END od[396]
  PIN od[397]
    DIRECTION OUTPUT ;
    USE SIGNAL ;
    PORT
      LAYER M4 ;
        RECT  0 39.216 0.192 39.24 ;
    END
  END od[397]
  PIN od[398]
    DIRECTION OUTPUT ;
    USE SIGNAL ;
    PORT
      LAYER M4 ;
        RECT  0 39.264 0.192 39.288 ;
    END
  END od[398]
  PIN od[399]
    DIRECTION OUTPUT ;
    USE SIGNAL ;
    PORT
      LAYER M4 ;
        RECT  0 39.312 0.192 39.336 ;
    END
  END od[399]
  PIN od[39]
    DIRECTION OUTPUT ;
    USE SIGNAL ;
    PORT
      LAYER M4 ;
        RECT  0 22.032 0.192 22.056 ;
    END
  END od[39]
  PIN od[3]
    DIRECTION OUTPUT ;
    USE SIGNAL ;
    PORT
      LAYER M4 ;
        RECT  0 20.304 0.192 20.328 ;
    END
  END od[3]
  PIN od[400]
    DIRECTION OUTPUT ;
    USE SIGNAL ;
    PORT
      LAYER M4 ;
        RECT  0 39.36 0.192 39.384 ;
    END
  END od[400]
  PIN od[401]
    DIRECTION OUTPUT ;
    USE SIGNAL ;
    PORT
      LAYER M4 ;
        RECT  0 39.408 0.192 39.432 ;
    END
  END od[401]
  PIN od[402]
    DIRECTION OUTPUT ;
    USE SIGNAL ;
    PORT
      LAYER M4 ;
        RECT  0 39.456 0.192 39.48 ;
    END
  END od[402]
  PIN od[403]
    DIRECTION OUTPUT ;
    USE SIGNAL ;
    PORT
      LAYER M4 ;
        RECT  0 39.504 0.192 39.528 ;
    END
  END od[403]
  PIN od[404]
    DIRECTION OUTPUT ;
    USE SIGNAL ;
    PORT
      LAYER M4 ;
        RECT  0 39.552 0.192 39.576 ;
    END
  END od[404]
  PIN od[405]
    DIRECTION OUTPUT ;
    USE SIGNAL ;
    PORT
      LAYER M4 ;
        RECT  0 39.6 0.192 39.624 ;
    END
  END od[405]
  PIN od[406]
    DIRECTION OUTPUT ;
    USE SIGNAL ;
    PORT
      LAYER M4 ;
        RECT  0 39.648 0.192 39.672 ;
    END
  END od[406]
  PIN od[407]
    DIRECTION OUTPUT ;
    USE SIGNAL ;
    PORT
      LAYER M4 ;
        RECT  0 39.696 0.192 39.72 ;
    END
  END od[407]
  PIN od[408]
    DIRECTION OUTPUT ;
    USE SIGNAL ;
    PORT
      LAYER M4 ;
        RECT  0 39.744 0.192 39.768 ;
    END
  END od[408]
  PIN od[409]
    DIRECTION OUTPUT ;
    USE SIGNAL ;
    PORT
      LAYER M4 ;
        RECT  0 39.792 0.192 39.816 ;
    END
  END od[409]
  PIN od[40]
    DIRECTION OUTPUT ;
    USE SIGNAL ;
    PORT
      LAYER M4 ;
        RECT  0 22.08 0.192 22.104 ;
    END
  END od[40]
  PIN od[410]
    DIRECTION OUTPUT ;
    USE SIGNAL ;
    PORT
      LAYER M4 ;
        RECT  0 39.84 0.192 39.864 ;
    END
  END od[410]
  PIN od[411]
    DIRECTION OUTPUT ;
    USE SIGNAL ;
    PORT
      LAYER M4 ;
        RECT  0 39.888 0.192 39.912 ;
    END
  END od[411]
  PIN od[412]
    DIRECTION OUTPUT ;
    USE SIGNAL ;
    PORT
      LAYER M4 ;
        RECT  0 39.936 0.192 39.96 ;
    END
  END od[412]
  PIN od[413]
    DIRECTION OUTPUT ;
    USE SIGNAL ;
    PORT
      LAYER M4 ;
        RECT  0 39.984 0.192 40.008 ;
    END
  END od[413]
  PIN od[414]
    DIRECTION OUTPUT ;
    USE SIGNAL ;
    PORT
      LAYER M4 ;
        RECT  0 40.032 0.192 40.056 ;
    END
  END od[414]
  PIN od[415]
    DIRECTION OUTPUT ;
    USE SIGNAL ;
    PORT
      LAYER M4 ;
        RECT  0 40.08 0.192 40.104 ;
    END
  END od[415]
  PIN od[416]
    DIRECTION OUTPUT ;
    USE SIGNAL ;
    PORT
      LAYER M4 ;
        RECT  0 40.128 0.192 40.152 ;
    END
  END od[416]
  PIN od[417]
    DIRECTION OUTPUT ;
    USE SIGNAL ;
    PORT
      LAYER M4 ;
        RECT  0 40.176 0.192 40.2 ;
    END
  END od[417]
  PIN od[418]
    DIRECTION OUTPUT ;
    USE SIGNAL ;
    PORT
      LAYER M4 ;
        RECT  0 40.224 0.192 40.248 ;
    END
  END od[418]
  PIN od[419]
    DIRECTION OUTPUT ;
    USE SIGNAL ;
    PORT
      LAYER M4 ;
        RECT  0 40.272 0.192 40.296 ;
    END
  END od[419]
  PIN od[41]
    DIRECTION OUTPUT ;
    USE SIGNAL ;
    PORT
      LAYER M4 ;
        RECT  0 22.128 0.192 22.152 ;
    END
  END od[41]
  PIN od[420]
    DIRECTION OUTPUT ;
    USE SIGNAL ;
    PORT
      LAYER M4 ;
        RECT  0 40.32 0.192 40.344 ;
    END
  END od[420]
  PIN od[421]
    DIRECTION OUTPUT ;
    USE SIGNAL ;
    PORT
      LAYER M4 ;
        RECT  0 40.368 0.192 40.392 ;
    END
  END od[421]
  PIN od[422]
    DIRECTION OUTPUT ;
    USE SIGNAL ;
    PORT
      LAYER M4 ;
        RECT  0 40.416 0.192 40.44 ;
    END
  END od[422]
  PIN od[423]
    DIRECTION OUTPUT ;
    USE SIGNAL ;
    PORT
      LAYER M4 ;
        RECT  0 40.464 0.192 40.488 ;
    END
  END od[423]
  PIN od[424]
    DIRECTION OUTPUT ;
    USE SIGNAL ;
    PORT
      LAYER M4 ;
        RECT  0 40.512 0.192 40.536 ;
    END
  END od[424]
  PIN od[425]
    DIRECTION OUTPUT ;
    USE SIGNAL ;
    PORT
      LAYER M4 ;
        RECT  0 40.56 0.192 40.584 ;
    END
  END od[425]
  PIN od[426]
    DIRECTION OUTPUT ;
    USE SIGNAL ;
    PORT
      LAYER M4 ;
        RECT  0 40.608 0.192 40.632 ;
    END
  END od[426]
  PIN od[427]
    DIRECTION OUTPUT ;
    USE SIGNAL ;
    PORT
      LAYER M4 ;
        RECT  0 40.656 0.192 40.68 ;
    END
  END od[427]
  PIN od[428]
    DIRECTION OUTPUT ;
    USE SIGNAL ;
    PORT
      LAYER M4 ;
        RECT  0 40.704 0.192 40.728 ;
    END
  END od[428]
  PIN od[429]
    DIRECTION OUTPUT ;
    USE SIGNAL ;
    PORT
      LAYER M4 ;
        RECT  0 40.752 0.192 40.776 ;
    END
  END od[429]
  PIN od[42]
    DIRECTION OUTPUT ;
    USE SIGNAL ;
    PORT
      LAYER M4 ;
        RECT  0 22.176 0.192 22.2 ;
    END
  END od[42]
  PIN od[430]
    DIRECTION OUTPUT ;
    USE SIGNAL ;
    PORT
      LAYER M4 ;
        RECT  0 40.8 0.192 40.824 ;
    END
  END od[430]
  PIN od[431]
    DIRECTION OUTPUT ;
    USE SIGNAL ;
    PORT
      LAYER M4 ;
        RECT  0 40.848 0.192 40.872 ;
    END
  END od[431]
  PIN od[432]
    DIRECTION OUTPUT ;
    USE SIGNAL ;
    PORT
      LAYER M4 ;
        RECT  0 40.896 0.192 40.92 ;
    END
  END od[432]
  PIN od[433]
    DIRECTION OUTPUT ;
    USE SIGNAL ;
    PORT
      LAYER M4 ;
        RECT  0 40.944 0.192 40.968 ;
    END
  END od[433]
  PIN od[434]
    DIRECTION OUTPUT ;
    USE SIGNAL ;
    PORT
      LAYER M4 ;
        RECT  0 40.992 0.192 41.016 ;
    END
  END od[434]
  PIN od[435]
    DIRECTION OUTPUT ;
    USE SIGNAL ;
    PORT
      LAYER M4 ;
        RECT  0 41.04 0.192 41.064 ;
    END
  END od[435]
  PIN od[436]
    DIRECTION OUTPUT ;
    USE SIGNAL ;
    PORT
      LAYER M4 ;
        RECT  0 41.088 0.192 41.112 ;
    END
  END od[436]
  PIN od[437]
    DIRECTION OUTPUT ;
    USE SIGNAL ;
    PORT
      LAYER M4 ;
        RECT  0 41.136 0.192 41.16 ;
    END
  END od[437]
  PIN od[438]
    DIRECTION OUTPUT ;
    USE SIGNAL ;
    PORT
      LAYER M4 ;
        RECT  0 41.184 0.192 41.208 ;
    END
  END od[438]
  PIN od[439]
    DIRECTION OUTPUT ;
    USE SIGNAL ;
    PORT
      LAYER M4 ;
        RECT  0 41.232 0.192 41.256 ;
    END
  END od[439]
  PIN od[43]
    DIRECTION OUTPUT ;
    USE SIGNAL ;
    PORT
      LAYER M4 ;
        RECT  0 22.224 0.192 22.248 ;
    END
  END od[43]
  PIN od[440]
    DIRECTION OUTPUT ;
    USE SIGNAL ;
    PORT
      LAYER M4 ;
        RECT  0 41.28 0.192 41.304 ;
    END
  END od[440]
  PIN od[441]
    DIRECTION OUTPUT ;
    USE SIGNAL ;
    PORT
      LAYER M4 ;
        RECT  0 41.328 0.192 41.352 ;
    END
  END od[441]
  PIN od[442]
    DIRECTION OUTPUT ;
    USE SIGNAL ;
    PORT
      LAYER M4 ;
        RECT  0 41.376 0.192 41.4 ;
    END
  END od[442]
  PIN od[443]
    DIRECTION OUTPUT ;
    USE SIGNAL ;
    PORT
      LAYER M4 ;
        RECT  0 41.424 0.192 41.448 ;
    END
  END od[443]
  PIN od[444]
    DIRECTION OUTPUT ;
    USE SIGNAL ;
    PORT
      LAYER M4 ;
        RECT  0 41.472 0.192 41.496 ;
    END
  END od[444]
  PIN od[445]
    DIRECTION OUTPUT ;
    USE SIGNAL ;
    PORT
      LAYER M4 ;
        RECT  0 41.52 0.192 41.544 ;
    END
  END od[445]
  PIN od[446]
    DIRECTION OUTPUT ;
    USE SIGNAL ;
    PORT
      LAYER M4 ;
        RECT  0 41.568 0.192 41.592 ;
    END
  END od[446]
  PIN od[447]
    DIRECTION OUTPUT ;
    USE SIGNAL ;
    PORT
      LAYER M4 ;
        RECT  0 41.616 0.192 41.64 ;
    END
  END od[447]
  PIN od[448]
    DIRECTION OUTPUT ;
    USE SIGNAL ;
    PORT
      LAYER M4 ;
        RECT  0 41.664 0.192 41.688 ;
    END
  END od[448]
  PIN od[449]
    DIRECTION OUTPUT ;
    USE SIGNAL ;
    PORT
      LAYER M4 ;
        RECT  0 41.712 0.192 41.736 ;
    END
  END od[449]
  PIN od[44]
    DIRECTION OUTPUT ;
    USE SIGNAL ;
    PORT
      LAYER M4 ;
        RECT  0 22.272 0.192 22.296 ;
    END
  END od[44]
  PIN od[450]
    DIRECTION OUTPUT ;
    USE SIGNAL ;
    PORT
      LAYER M4 ;
        RECT  0 41.76 0.192 41.784 ;
    END
  END od[450]
  PIN od[451]
    DIRECTION OUTPUT ;
    USE SIGNAL ;
    PORT
      LAYER M4 ;
        RECT  0 41.808 0.192 41.832 ;
    END
  END od[451]
  PIN od[452]
    DIRECTION OUTPUT ;
    USE SIGNAL ;
    PORT
      LAYER M4 ;
        RECT  0 41.856 0.192 41.88 ;
    END
  END od[452]
  PIN od[453]
    DIRECTION OUTPUT ;
    USE SIGNAL ;
    PORT
      LAYER M4 ;
        RECT  0 41.904 0.192 41.928 ;
    END
  END od[453]
  PIN od[454]
    DIRECTION OUTPUT ;
    USE SIGNAL ;
    PORT
      LAYER M4 ;
        RECT  0 41.952 0.192 41.976 ;
    END
  END od[454]
  PIN od[455]
    DIRECTION OUTPUT ;
    USE SIGNAL ;
    PORT
      LAYER M4 ;
        RECT  0 42 0.192 42.024 ;
    END
  END od[455]
  PIN od[456]
    DIRECTION OUTPUT ;
    USE SIGNAL ;
    PORT
      LAYER M4 ;
        RECT  0 42.048 0.192 42.072 ;
    END
  END od[456]
  PIN od[457]
    DIRECTION OUTPUT ;
    USE SIGNAL ;
    PORT
      LAYER M4 ;
        RECT  0 42.096 0.192 42.12 ;
    END
  END od[457]
  PIN od[458]
    DIRECTION OUTPUT ;
    USE SIGNAL ;
    PORT
      LAYER M4 ;
        RECT  0 42.144 0.192 42.168 ;
    END
  END od[458]
  PIN od[459]
    DIRECTION OUTPUT ;
    USE SIGNAL ;
    PORT
      LAYER M4 ;
        RECT  0 42.192 0.192 42.216 ;
    END
  END od[459]
  PIN od[45]
    DIRECTION OUTPUT ;
    USE SIGNAL ;
    PORT
      LAYER M4 ;
        RECT  0 22.32 0.192 22.344 ;
    END
  END od[45]
  PIN od[460]
    DIRECTION OUTPUT ;
    USE SIGNAL ;
    PORT
      LAYER M4 ;
        RECT  0 42.24 0.192 42.264 ;
    END
  END od[460]
  PIN od[461]
    DIRECTION OUTPUT ;
    USE SIGNAL ;
    PORT
      LAYER M4 ;
        RECT  0 42.288 0.192 42.312 ;
    END
  END od[461]
  PIN od[462]
    DIRECTION OUTPUT ;
    USE SIGNAL ;
    PORT
      LAYER M4 ;
        RECT  0 42.336 0.192 42.36 ;
    END
  END od[462]
  PIN od[463]
    DIRECTION OUTPUT ;
    USE SIGNAL ;
    PORT
      LAYER M4 ;
        RECT  0 42.384 0.192 42.408 ;
    END
  END od[463]
  PIN od[464]
    DIRECTION OUTPUT ;
    USE SIGNAL ;
    PORT
      LAYER M4 ;
        RECT  0 42.432 0.192 42.456 ;
    END
  END od[464]
  PIN od[465]
    DIRECTION OUTPUT ;
    USE SIGNAL ;
    PORT
      LAYER M4 ;
        RECT  0 42.48 0.192 42.504 ;
    END
  END od[465]
  PIN od[466]
    DIRECTION OUTPUT ;
    USE SIGNAL ;
    PORT
      LAYER M4 ;
        RECT  0 42.528 0.192 42.552 ;
    END
  END od[466]
  PIN od[467]
    DIRECTION OUTPUT ;
    USE SIGNAL ;
    PORT
      LAYER M4 ;
        RECT  0 42.576 0.192 42.6 ;
    END
  END od[467]
  PIN od[468]
    DIRECTION OUTPUT ;
    USE SIGNAL ;
    PORT
      LAYER M4 ;
        RECT  0 42.624 0.192 42.648 ;
    END
  END od[468]
  PIN od[469]
    DIRECTION OUTPUT ;
    USE SIGNAL ;
    PORT
      LAYER M4 ;
        RECT  0 42.672 0.192 42.696 ;
    END
  END od[469]
  PIN od[46]
    DIRECTION OUTPUT ;
    USE SIGNAL ;
    PORT
      LAYER M4 ;
        RECT  0 22.368 0.192 22.392 ;
    END
  END od[46]
  PIN od[470]
    DIRECTION OUTPUT ;
    USE SIGNAL ;
    PORT
      LAYER M4 ;
        RECT  0 42.72 0.192 42.744 ;
    END
  END od[470]
  PIN od[471]
    DIRECTION OUTPUT ;
    USE SIGNAL ;
    PORT
      LAYER M4 ;
        RECT  0 42.768 0.192 42.792 ;
    END
  END od[471]
  PIN od[472]
    DIRECTION OUTPUT ;
    USE SIGNAL ;
    PORT
      LAYER M4 ;
        RECT  0 42.816 0.192 42.84 ;
    END
  END od[472]
  PIN od[473]
    DIRECTION OUTPUT ;
    USE SIGNAL ;
    PORT
      LAYER M4 ;
        RECT  0 42.864 0.192 42.888 ;
    END
  END od[473]
  PIN od[474]
    DIRECTION OUTPUT ;
    USE SIGNAL ;
    PORT
      LAYER M4 ;
        RECT  0 42.912 0.192 42.936 ;
    END
  END od[474]
  PIN od[475]
    DIRECTION OUTPUT ;
    USE SIGNAL ;
    PORT
      LAYER M4 ;
        RECT  0 42.96 0.192 42.984 ;
    END
  END od[475]
  PIN od[476]
    DIRECTION OUTPUT ;
    USE SIGNAL ;
    PORT
      LAYER M4 ;
        RECT  0 43.008 0.192 43.032 ;
    END
  END od[476]
  PIN od[477]
    DIRECTION OUTPUT ;
    USE SIGNAL ;
    PORT
      LAYER M4 ;
        RECT  0 43.056 0.192 43.08 ;
    END
  END od[477]
  PIN od[478]
    DIRECTION OUTPUT ;
    USE SIGNAL ;
    PORT
      LAYER M4 ;
        RECT  0 43.104 0.192 43.128 ;
    END
  END od[478]
  PIN od[479]
    DIRECTION OUTPUT ;
    USE SIGNAL ;
    PORT
      LAYER M4 ;
        RECT  0 43.152 0.192 43.176 ;
    END
  END od[479]
  PIN od[47]
    DIRECTION OUTPUT ;
    USE SIGNAL ;
    PORT
      LAYER M4 ;
        RECT  0 22.416 0.192 22.44 ;
    END
  END od[47]
  PIN od[480]
    DIRECTION OUTPUT ;
    USE SIGNAL ;
    PORT
      LAYER M4 ;
        RECT  0 43.2 0.192 43.224 ;
    END
  END od[480]
  PIN od[481]
    DIRECTION OUTPUT ;
    USE SIGNAL ;
    PORT
      LAYER M4 ;
        RECT  0 43.248 0.192 43.272 ;
    END
  END od[481]
  PIN od[482]
    DIRECTION OUTPUT ;
    USE SIGNAL ;
    PORT
      LAYER M4 ;
        RECT  0 43.296 0.192 43.32 ;
    END
  END od[482]
  PIN od[483]
    DIRECTION OUTPUT ;
    USE SIGNAL ;
    PORT
      LAYER M4 ;
        RECT  0 43.344 0.192 43.368 ;
    END
  END od[483]
  PIN od[484]
    DIRECTION OUTPUT ;
    USE SIGNAL ;
    PORT
      LAYER M4 ;
        RECT  0 43.392 0.192 43.416 ;
    END
  END od[484]
  PIN od[485]
    DIRECTION OUTPUT ;
    USE SIGNAL ;
    PORT
      LAYER M4 ;
        RECT  0 43.44 0.192 43.464 ;
    END
  END od[485]
  PIN od[486]
    DIRECTION OUTPUT ;
    USE SIGNAL ;
    PORT
      LAYER M4 ;
        RECT  0 43.488 0.192 43.512 ;
    END
  END od[486]
  PIN od[487]
    DIRECTION OUTPUT ;
    USE SIGNAL ;
    PORT
      LAYER M4 ;
        RECT  0 43.536 0.192 43.56 ;
    END
  END od[487]
  PIN od[488]
    DIRECTION OUTPUT ;
    USE SIGNAL ;
    PORT
      LAYER M4 ;
        RECT  0 43.584 0.192 43.608 ;
    END
  END od[488]
  PIN od[489]
    DIRECTION OUTPUT ;
    USE SIGNAL ;
    PORT
      LAYER M4 ;
        RECT  0 43.632 0.192 43.656 ;
    END
  END od[489]
  PIN od[48]
    DIRECTION OUTPUT ;
    USE SIGNAL ;
    PORT
      LAYER M4 ;
        RECT  0 22.464 0.192 22.488 ;
    END
  END od[48]
  PIN od[490]
    DIRECTION OUTPUT ;
    USE SIGNAL ;
    PORT
      LAYER M4 ;
        RECT  0 43.68 0.192 43.704 ;
    END
  END od[490]
  PIN od[491]
    DIRECTION OUTPUT ;
    USE SIGNAL ;
    PORT
      LAYER M4 ;
        RECT  0 43.728 0.192 43.752 ;
    END
  END od[491]
  PIN od[492]
    DIRECTION OUTPUT ;
    USE SIGNAL ;
    PORT
      LAYER M4 ;
        RECT  0 43.776 0.192 43.8 ;
    END
  END od[492]
  PIN od[493]
    DIRECTION OUTPUT ;
    USE SIGNAL ;
    PORT
      LAYER M4 ;
        RECT  0 43.824 0.192 43.848 ;
    END
  END od[493]
  PIN od[494]
    DIRECTION OUTPUT ;
    USE SIGNAL ;
    PORT
      LAYER M4 ;
        RECT  0 43.872 0.192 43.896 ;
    END
  END od[494]
  PIN od[495]
    DIRECTION OUTPUT ;
    USE SIGNAL ;
    PORT
      LAYER M4 ;
        RECT  0 43.92 0.192 43.944 ;
    END
  END od[495]
  PIN od[496]
    DIRECTION OUTPUT ;
    USE SIGNAL ;
    PORT
      LAYER M4 ;
        RECT  0 43.968 0.192 43.992 ;
    END
  END od[496]
  PIN od[497]
    DIRECTION OUTPUT ;
    USE SIGNAL ;
    PORT
      LAYER M4 ;
        RECT  0 44.016 0.192 44.04 ;
    END
  END od[497]
  PIN od[498]
    DIRECTION OUTPUT ;
    USE SIGNAL ;
    PORT
      LAYER M4 ;
        RECT  0 44.064 0.192 44.088 ;
    END
  END od[498]
  PIN od[499]
    DIRECTION OUTPUT ;
    USE SIGNAL ;
    PORT
      LAYER M4 ;
        RECT  0 44.112 0.192 44.136 ;
    END
  END od[499]
  PIN od[49]
    DIRECTION OUTPUT ;
    USE SIGNAL ;
    PORT
      LAYER M4 ;
        RECT  0 22.512 0.192 22.536 ;
    END
  END od[49]
  PIN od[4]
    DIRECTION OUTPUT ;
    USE SIGNAL ;
    PORT
      LAYER M4 ;
        RECT  0 20.352 0.192 20.376 ;
    END
  END od[4]
  PIN od[500]
    DIRECTION OUTPUT ;
    USE SIGNAL ;
    PORT
      LAYER M4 ;
        RECT  0 44.16 0.192 44.184 ;
    END
  END od[500]
  PIN od[501]
    DIRECTION OUTPUT ;
    USE SIGNAL ;
    PORT
      LAYER M4 ;
        RECT  0 44.208 0.192 44.232 ;
    END
  END od[501]
  PIN od[502]
    DIRECTION OUTPUT ;
    USE SIGNAL ;
    PORT
      LAYER M4 ;
        RECT  0 44.256 0.192 44.28 ;
    END
  END od[502]
  PIN od[503]
    DIRECTION OUTPUT ;
    USE SIGNAL ;
    PORT
      LAYER M4 ;
        RECT  0 44.304 0.192 44.328 ;
    END
  END od[503]
  PIN od[504]
    DIRECTION OUTPUT ;
    USE SIGNAL ;
    PORT
      LAYER M4 ;
        RECT  0 44.352 0.192 44.376 ;
    END
  END od[504]
  PIN od[505]
    DIRECTION OUTPUT ;
    USE SIGNAL ;
    PORT
      LAYER M4 ;
        RECT  0 44.4 0.192 44.424 ;
    END
  END od[505]
  PIN od[506]
    DIRECTION OUTPUT ;
    USE SIGNAL ;
    PORT
      LAYER M4 ;
        RECT  0 44.448 0.192 44.472 ;
    END
  END od[506]
  PIN od[507]
    DIRECTION OUTPUT ;
    USE SIGNAL ;
    PORT
      LAYER M4 ;
        RECT  0 44.496 0.192 44.52 ;
    END
  END od[507]
  PIN od[508]
    DIRECTION OUTPUT ;
    USE SIGNAL ;
    PORT
      LAYER M4 ;
        RECT  0 44.544 0.192 44.568 ;
    END
  END od[508]
  PIN od[509]
    DIRECTION OUTPUT ;
    USE SIGNAL ;
    PORT
      LAYER M4 ;
        RECT  0 44.592 0.192 44.616 ;
    END
  END od[509]
  PIN od[50]
    DIRECTION OUTPUT ;
    USE SIGNAL ;
    PORT
      LAYER M4 ;
        RECT  0 22.56 0.192 22.584 ;
    END
  END od[50]
  PIN od[510]
    DIRECTION OUTPUT ;
    USE SIGNAL ;
    PORT
      LAYER M4 ;
        RECT  0 44.64 0.192 44.664 ;
    END
  END od[510]
  PIN od[511]
    DIRECTION OUTPUT ;
    USE SIGNAL ;
    PORT
      LAYER M4 ;
        RECT  0 44.688 0.192 44.712 ;
    END
  END od[511]
  PIN od[512]
    DIRECTION OUTPUT ;
    USE SIGNAL ;
    PORT
      LAYER M4 ;
        RECT  0 44.736 0.192 44.76 ;
    END
  END od[512]
  PIN od[513]
    DIRECTION OUTPUT ;
    USE SIGNAL ;
    PORT
      LAYER M4 ;
        RECT  0 44.784 0.192 44.808 ;
    END
  END od[513]
  PIN od[51]
    DIRECTION OUTPUT ;
    USE SIGNAL ;
    PORT
      LAYER M4 ;
        RECT  0 22.608 0.192 22.632 ;
    END
  END od[51]
  PIN od[52]
    DIRECTION OUTPUT ;
    USE SIGNAL ;
    PORT
      LAYER M4 ;
        RECT  0 22.656 0.192 22.68 ;
    END
  END od[52]
  PIN od[53]
    DIRECTION OUTPUT ;
    USE SIGNAL ;
    PORT
      LAYER M4 ;
        RECT  0 22.704 0.192 22.728 ;
    END
  END od[53]
  PIN od[54]
    DIRECTION OUTPUT ;
    USE SIGNAL ;
    PORT
      LAYER M4 ;
        RECT  0 22.752 0.192 22.776 ;
    END
  END od[54]
  PIN od[55]
    DIRECTION OUTPUT ;
    USE SIGNAL ;
    PORT
      LAYER M4 ;
        RECT  0 22.8 0.192 22.824 ;
    END
  END od[55]
  PIN od[56]
    DIRECTION OUTPUT ;
    USE SIGNAL ;
    PORT
      LAYER M4 ;
        RECT  0 22.848 0.192 22.872 ;
    END
  END od[56]
  PIN od[57]
    DIRECTION OUTPUT ;
    USE SIGNAL ;
    PORT
      LAYER M4 ;
        RECT  0 22.896 0.192 22.92 ;
    END
  END od[57]
  PIN od[58]
    DIRECTION OUTPUT ;
    USE SIGNAL ;
    PORT
      LAYER M4 ;
        RECT  0 22.944 0.192 22.968 ;
    END
  END od[58]
  PIN od[59]
    DIRECTION OUTPUT ;
    USE SIGNAL ;
    PORT
      LAYER M4 ;
        RECT  0 22.992 0.192 23.016 ;
    END
  END od[59]
  PIN od[5]
    DIRECTION OUTPUT ;
    USE SIGNAL ;
    PORT
      LAYER M4 ;
        RECT  0 20.4 0.192 20.424 ;
    END
  END od[5]
  PIN od[60]
    DIRECTION OUTPUT ;
    USE SIGNAL ;
    PORT
      LAYER M4 ;
        RECT  0 23.04 0.192 23.064 ;
    END
  END od[60]
  PIN od[61]
    DIRECTION OUTPUT ;
    USE SIGNAL ;
    PORT
      LAYER M4 ;
        RECT  0 23.088 0.192 23.112 ;
    END
  END od[61]
  PIN od[62]
    DIRECTION OUTPUT ;
    USE SIGNAL ;
    PORT
      LAYER M4 ;
        RECT  0 23.136 0.192 23.16 ;
    END
  END od[62]
  PIN od[63]
    DIRECTION OUTPUT ;
    USE SIGNAL ;
    PORT
      LAYER M4 ;
        RECT  0 23.184 0.192 23.208 ;
    END
  END od[63]
  PIN od[64]
    DIRECTION OUTPUT ;
    USE SIGNAL ;
    PORT
      LAYER M4 ;
        RECT  0 23.232 0.192 23.256 ;
    END
  END od[64]
  PIN od[65]
    DIRECTION OUTPUT ;
    USE SIGNAL ;
    PORT
      LAYER M4 ;
        RECT  0 23.28 0.192 23.304 ;
    END
  END od[65]
  PIN od[66]
    DIRECTION OUTPUT ;
    USE SIGNAL ;
    PORT
      LAYER M4 ;
        RECT  0 23.328 0.192 23.352 ;
    END
  END od[66]
  PIN od[67]
    DIRECTION OUTPUT ;
    USE SIGNAL ;
    PORT
      LAYER M4 ;
        RECT  0 23.376 0.192 23.4 ;
    END
  END od[67]
  PIN od[68]
    DIRECTION OUTPUT ;
    USE SIGNAL ;
    PORT
      LAYER M4 ;
        RECT  0 23.424 0.192 23.448 ;
    END
  END od[68]
  PIN od[69]
    DIRECTION OUTPUT ;
    USE SIGNAL ;
    PORT
      LAYER M4 ;
        RECT  0 23.472 0.192 23.496 ;
    END
  END od[69]
  PIN od[6]
    DIRECTION OUTPUT ;
    USE SIGNAL ;
    PORT
      LAYER M4 ;
        RECT  0 20.448 0.192 20.472 ;
    END
  END od[6]
  PIN od[70]
    DIRECTION OUTPUT ;
    USE SIGNAL ;
    PORT
      LAYER M4 ;
        RECT  0 23.52 0.192 23.544 ;
    END
  END od[70]
  PIN od[71]
    DIRECTION OUTPUT ;
    USE SIGNAL ;
    PORT
      LAYER M4 ;
        RECT  0 23.568 0.192 23.592 ;
    END
  END od[71]
  PIN od[72]
    DIRECTION OUTPUT ;
    USE SIGNAL ;
    PORT
      LAYER M4 ;
        RECT  0 23.616 0.192 23.64 ;
    END
  END od[72]
  PIN od[73]
    DIRECTION OUTPUT ;
    USE SIGNAL ;
    PORT
      LAYER M4 ;
        RECT  0 23.664 0.192 23.688 ;
    END
  END od[73]
  PIN od[74]
    DIRECTION OUTPUT ;
    USE SIGNAL ;
    PORT
      LAYER M4 ;
        RECT  0 23.712 0.192 23.736 ;
    END
  END od[74]
  PIN od[75]
    DIRECTION OUTPUT ;
    USE SIGNAL ;
    PORT
      LAYER M4 ;
        RECT  0 23.76 0.192 23.784 ;
    END
  END od[75]
  PIN od[76]
    DIRECTION OUTPUT ;
    USE SIGNAL ;
    PORT
      LAYER M4 ;
        RECT  0 23.808 0.192 23.832 ;
    END
  END od[76]
  PIN od[77]
    DIRECTION OUTPUT ;
    USE SIGNAL ;
    PORT
      LAYER M4 ;
        RECT  0 23.856 0.192 23.88 ;
    END
  END od[77]
  PIN od[78]
    DIRECTION OUTPUT ;
    USE SIGNAL ;
    PORT
      LAYER M4 ;
        RECT  0 23.904 0.192 23.928 ;
    END
  END od[78]
  PIN od[79]
    DIRECTION OUTPUT ;
    USE SIGNAL ;
    PORT
      LAYER M4 ;
        RECT  0 23.952 0.192 23.976 ;
    END
  END od[79]
  PIN od[7]
    DIRECTION OUTPUT ;
    USE SIGNAL ;
    PORT
      LAYER M4 ;
        RECT  0 20.496 0.192 20.52 ;
    END
  END od[7]
  PIN od[80]
    DIRECTION OUTPUT ;
    USE SIGNAL ;
    PORT
      LAYER M4 ;
        RECT  0 24 0.192 24.024 ;
    END
  END od[80]
  PIN od[81]
    DIRECTION OUTPUT ;
    USE SIGNAL ;
    PORT
      LAYER M4 ;
        RECT  0 24.048 0.192 24.072 ;
    END
  END od[81]
  PIN od[82]
    DIRECTION OUTPUT ;
    USE SIGNAL ;
    PORT
      LAYER M4 ;
        RECT  0 24.096 0.192 24.12 ;
    END
  END od[82]
  PIN od[83]
    DIRECTION OUTPUT ;
    USE SIGNAL ;
    PORT
      LAYER M4 ;
        RECT  0 24.144 0.192 24.168 ;
    END
  END od[83]
  PIN od[84]
    DIRECTION OUTPUT ;
    USE SIGNAL ;
    PORT
      LAYER M4 ;
        RECT  0 24.192 0.192 24.216 ;
    END
  END od[84]
  PIN od[85]
    DIRECTION OUTPUT ;
    USE SIGNAL ;
    PORT
      LAYER M4 ;
        RECT  0 24.24 0.192 24.264 ;
    END
  END od[85]
  PIN od[86]
    DIRECTION OUTPUT ;
    USE SIGNAL ;
    PORT
      LAYER M4 ;
        RECT  0 24.288 0.192 24.312 ;
    END
  END od[86]
  PIN od[87]
    DIRECTION OUTPUT ;
    USE SIGNAL ;
    PORT
      LAYER M4 ;
        RECT  0 24.336 0.192 24.36 ;
    END
  END od[87]
  PIN od[88]
    DIRECTION OUTPUT ;
    USE SIGNAL ;
    PORT
      LAYER M4 ;
        RECT  0 24.384 0.192 24.408 ;
    END
  END od[88]
  PIN od[89]
    DIRECTION OUTPUT ;
    USE SIGNAL ;
    PORT
      LAYER M4 ;
        RECT  0 24.432 0.192 24.456 ;
    END
  END od[89]
  PIN od[8]
    DIRECTION OUTPUT ;
    USE SIGNAL ;
    PORT
      LAYER M4 ;
        RECT  0 20.544 0.192 20.568 ;
    END
  END od[8]
  PIN od[90]
    DIRECTION OUTPUT ;
    USE SIGNAL ;
    PORT
      LAYER M4 ;
        RECT  0 24.48 0.192 24.504 ;
    END
  END od[90]
  PIN od[91]
    DIRECTION OUTPUT ;
    USE SIGNAL ;
    PORT
      LAYER M4 ;
        RECT  0 24.528 0.192 24.552 ;
    END
  END od[91]
  PIN od[92]
    DIRECTION OUTPUT ;
    USE SIGNAL ;
    PORT
      LAYER M4 ;
        RECT  0 24.576 0.192 24.6 ;
    END
  END od[92]
  PIN od[93]
    DIRECTION OUTPUT ;
    USE SIGNAL ;
    PORT
      LAYER M4 ;
        RECT  0 24.624 0.192 24.648 ;
    END
  END od[93]
  PIN od[94]
    DIRECTION OUTPUT ;
    USE SIGNAL ;
    PORT
      LAYER M4 ;
        RECT  0 24.672 0.192 24.696 ;
    END
  END od[94]
  PIN od[95]
    DIRECTION OUTPUT ;
    USE SIGNAL ;
    PORT
      LAYER M4 ;
        RECT  0 24.72 0.192 24.744 ;
    END
  END od[95]
  PIN od[96]
    DIRECTION OUTPUT ;
    USE SIGNAL ;
    PORT
      LAYER M4 ;
        RECT  0 24.768 0.192 24.792 ;
    END
  END od[96]
  PIN od[97]
    DIRECTION OUTPUT ;
    USE SIGNAL ;
    PORT
      LAYER M4 ;
        RECT  0 24.816 0.192 24.84 ;
    END
  END od[97]
  PIN od[98]
    DIRECTION OUTPUT ;
    USE SIGNAL ;
    PORT
      LAYER M4 ;
        RECT  0 24.864 0.192 24.888 ;
    END
  END od[98]
  PIN od[99]
    DIRECTION OUTPUT ;
    USE SIGNAL ;
    PORT
      LAYER M4 ;
        RECT  0 24.912 0.192 24.936 ;
    END
  END od[99]
  PIN od[9]
    DIRECTION OUTPUT ;
    USE SIGNAL ;
    PORT
      LAYER M4 ;
        RECT  0 20.592 0.192 20.616 ;
    END
  END od[9]
  PIN rs[0]
    DIRECTION INPUT ;
    USE SIGNAL ;
    PORT
      LAYER M5 ;
        RECT  32.448 0 32.472 0.192 ;
    END
  END rs[0]
  PIN rss[0]
    DIRECTION INPUT ;
    USE SIGNAL ;
    PORT
      LAYER M5 ;
        RECT  32.64 0 32.664 0.192 ;
    END
  END rss[0]
  PIN st[0]
    DIRECTION OUTPUT ;
    USE SIGNAL ;
    PORT
      LAYER M5 ;
        RECT  44.688 64.584 44.712 64.776 ;
    END
  END st[0]
  PIN st[1]
    DIRECTION OUTPUT ;
    USE SIGNAL ;
    PORT
      LAYER M5 ;
        RECT  44.736 64.584 44.76 64.776 ;
    END
  END st[1]
  PIN st[2]
    DIRECTION OUTPUT ;
    USE SIGNAL ;
    PORT
      LAYER M5 ;
        RECT  44.784 64.584 44.808 64.776 ;
    END
  END st[2]
  PIN VDD
    DIRECTION INOUT ;
    USE POWER ;
    PORT
      LAYER M7 ;
        RECT  60.256 0.531 60.544 63.999 ;
        RECT  49.456 0.531 49.744 63.999 ;
        RECT  38.656 0.531 38.944 63.999 ;
        RECT  27.856 0.531 28.144 63.999 ;
        RECT  17.056 0.531 17.344 63.999 ;
        RECT  6.256 0.531 6.544 63.999 ;
      LAYER M6 ;
        RECT  0 60.972 0.032 61.26 ;
        RECT  0 55.572 0.032 55.86 ;
        RECT  0 50.172 0.032 50.46 ;
        RECT  0 44.772 0.032 45.06 ;
        RECT  0 39.372 0.032 39.66 ;
        RECT  0 33.972 0.032 34.26 ;
        RECT  0 28.572 0.032 28.86 ;
        RECT  0 23.172 0.032 23.46 ;
        RECT  0 17.772 0.032 18.06 ;
        RECT  0 12.372 0.032 12.66 ;
        RECT  0 6.972 0.032 7.26 ;
        RECT  0 1.572 0.032 1.86 ;
      LAYER M2 ;
        RECT  0 63.981 0.018 63.999 ;
        RECT  0 63.441 0.018 63.459 ;
        RECT  0 62.901 0.018 62.919 ;
        RECT  0 62.361 0.018 62.379 ;
        RECT  0 61.821 0.018 61.839 ;
        RECT  0 61.281 0.018 61.299 ;
        RECT  0 60.741 0.018 60.759 ;
        RECT  0 60.201 0.018 60.219 ;
        RECT  0 59.661 0.018 59.679 ;
        RECT  0 59.121 0.018 59.139 ;
        RECT  0 58.581 0.018 58.599 ;
        RECT  0 58.041 0.018 58.059 ;
        RECT  0 57.501 0.018 57.519 ;
        RECT  0 56.961 0.018 56.979 ;
        RECT  0 56.421 0.018 56.439 ;
        RECT  0 55.881 0.018 55.899 ;
        RECT  0 55.341 0.018 55.359 ;
        RECT  0 54.801 0.018 54.819 ;
        RECT  0 54.261 0.018 54.279 ;
        RECT  0 53.721 0.018 53.739 ;
        RECT  0 53.181 0.018 53.199 ;
        RECT  0 52.641 0.018 52.659 ;
        RECT  0 52.101 0.018 52.119 ;
        RECT  0 51.561 0.018 51.579 ;
        RECT  0 51.021 0.018 51.039 ;
        RECT  0 50.481 0.018 50.499 ;
        RECT  0 49.941 0.018 49.959 ;
        RECT  0 49.401 0.018 49.419 ;
        RECT  0 48.861 0.018 48.879 ;
        RECT  0 48.321 0.018 48.339 ;
        RECT  0 47.781 0.018 47.799 ;
        RECT  0 47.241 0.018 47.259 ;
        RECT  0 46.701 0.018 46.719 ;
        RECT  0 46.161 0.018 46.179 ;
        RECT  0 45.621 0.018 45.639 ;
        RECT  0 45.081 0.018 45.099 ;
        RECT  0 44.541 0.018 44.559 ;
        RECT  0 44.001 0.018 44.019 ;
        RECT  0 43.461 0.018 43.479 ;
        RECT  0 42.921 0.018 42.939 ;
        RECT  0 42.381 0.018 42.399 ;
        RECT  0 41.841 0.018 41.859 ;
        RECT  0 41.301 0.018 41.319 ;
        RECT  0 40.761 0.018 40.779 ;
        RECT  0 40.221 0.018 40.239 ;
        RECT  0 39.681 0.018 39.699 ;
        RECT  0 39.141 0.018 39.159 ;
        RECT  0 38.601 0.018 38.619 ;
        RECT  0 38.061 0.018 38.079 ;
        RECT  0 37.521 0.018 37.539 ;
        RECT  0 36.981 0.018 36.999 ;
        RECT  0 36.441 0.018 36.459 ;
        RECT  0 35.901 0.018 35.919 ;
        RECT  0 35.361 0.018 35.379 ;
        RECT  0 34.821 0.018 34.839 ;
        RECT  0 34.281 0.018 34.299 ;
        RECT  0 33.741 0.018 33.759 ;
        RECT  0 33.201 0.018 33.219 ;
        RECT  0 32.661 0.018 32.679 ;
        RECT  0 32.121 0.018 32.139 ;
        RECT  0 31.581 0.018 31.599 ;
        RECT  0 31.041 0.018 31.059 ;
        RECT  0 30.501 0.018 30.519 ;
        RECT  0 29.961 0.018 29.979 ;
        RECT  0 29.421 0.018 29.439 ;
        RECT  0 28.881 0.018 28.899 ;
        RECT  0 28.341 0.018 28.359 ;
        RECT  0 27.801 0.018 27.819 ;
        RECT  0 27.261 0.018 27.279 ;
        RECT  0 26.721 0.018 26.739 ;
        RECT  0 26.181 0.018 26.199 ;
        RECT  0 25.641 0.018 25.659 ;
        RECT  0 25.101 0.018 25.119 ;
        RECT  0 24.561 0.018 24.579 ;
        RECT  0 24.021 0.018 24.039 ;
        RECT  0 23.481 0.018 23.499 ;
        RECT  0 22.941 0.018 22.959 ;
        RECT  0 22.401 0.018 22.419 ;
        RECT  0 21.861 0.018 21.879 ;
        RECT  0 21.321 0.018 21.339 ;
        RECT  0 20.781 0.018 20.799 ;
        RECT  0 20.241 0.018 20.259 ;
        RECT  0 19.701 0.018 19.719 ;
        RECT  0 19.161 0.018 19.179 ;
        RECT  0 18.621 0.018 18.639 ;
        RECT  0 18.081 0.018 18.099 ;
        RECT  0 17.541 0.018 17.559 ;
        RECT  0 17.001 0.018 17.019 ;
        RECT  0 16.461 0.018 16.479 ;
        RECT  0 15.921 0.018 15.939 ;
        RECT  0 15.381 0.018 15.399 ;
        RECT  0 14.841 0.018 14.859 ;
        RECT  0 14.301 0.018 14.319 ;
        RECT  0 13.761 0.018 13.779 ;
        RECT  0 13.221 0.018 13.239 ;
        RECT  0 12.681 0.018 12.699 ;
        RECT  0 12.141 0.018 12.159 ;
        RECT  0 11.601 0.018 11.619 ;
        RECT  0 11.061 0.018 11.079 ;
        RECT  0 10.521 0.018 10.539 ;
        RECT  0 9.981 0.018 9.999 ;
        RECT  0 9.441 0.018 9.459 ;
        RECT  0 8.901 0.018 8.919 ;
        RECT  0 8.361 0.018 8.379 ;
        RECT  0 7.821 0.018 7.839 ;
        RECT  0 7.281 0.018 7.299 ;
        RECT  0 6.741 0.018 6.759 ;
        RECT  0 6.201 0.018 6.219 ;
        RECT  0 5.661 0.018 5.679 ;
        RECT  0 5.121 0.018 5.139 ;
        RECT  0 4.581 0.018 4.599 ;
        RECT  0 4.041 0.018 4.059 ;
        RECT  0 3.501 0.018 3.519 ;
        RECT  0 2.961 0.018 2.979 ;
        RECT  0 2.421 0.018 2.439 ;
        RECT  0 1.881 0.018 1.899 ;
        RECT  0 1.341 0.018 1.359 ;
        RECT  0 0.801 0.018 0.819 ;
      LAYER M1 ;
        RECT  0 63.981 0.018 63.999 ;
        RECT  0 63.441 0.018 63.459 ;
        RECT  0 62.901 0.018 62.919 ;
        RECT  0 62.361 0.018 62.379 ;
        RECT  0 61.821 0.018 61.839 ;
        RECT  0 61.281 0.018 61.299 ;
        RECT  0 60.741 0.018 60.759 ;
        RECT  0 60.201 0.018 60.219 ;
        RECT  0 59.661 0.018 59.679 ;
        RECT  0 59.121 0.018 59.139 ;
        RECT  0 58.581 0.018 58.599 ;
        RECT  0 58.041 0.018 58.059 ;
        RECT  0 57.501 0.018 57.519 ;
        RECT  0 56.961 0.018 56.979 ;
        RECT  0 56.421 0.018 56.439 ;
        RECT  0 55.881 0.018 55.899 ;
        RECT  0 55.341 0.018 55.359 ;
        RECT  0 54.801 0.018 54.819 ;
        RECT  0 54.261 0.018 54.279 ;
        RECT  0 53.721 0.018 53.739 ;
        RECT  0 53.181 0.018 53.199 ;
        RECT  0 52.641 0.018 52.659 ;
        RECT  0 52.101 0.018 52.119 ;
        RECT  0 51.561 0.018 51.579 ;
        RECT  0 51.021 0.018 51.039 ;
        RECT  0 50.481 0.018 50.499 ;
        RECT  0 49.941 0.018 49.959 ;
        RECT  0 49.401 0.018 49.419 ;
        RECT  0 48.861 0.018 48.879 ;
        RECT  0 48.321 0.018 48.339 ;
        RECT  0 47.781 0.018 47.799 ;
        RECT  0 47.241 0.018 47.259 ;
        RECT  0 46.701 0.018 46.719 ;
        RECT  0 46.161 0.018 46.179 ;
        RECT  0 45.621 0.018 45.639 ;
        RECT  0 45.081 0.018 45.099 ;
        RECT  0 44.541 0.018 44.559 ;
        RECT  0 44.001 0.018 44.019 ;
        RECT  0 43.461 0.018 43.479 ;
        RECT  0 42.921 0.018 42.939 ;
        RECT  0 42.381 0.018 42.399 ;
        RECT  0 41.841 0.018 41.859 ;
        RECT  0 41.301 0.018 41.319 ;
        RECT  0 40.761 0.018 40.779 ;
        RECT  0 40.221 0.018 40.239 ;
        RECT  0 39.681 0.018 39.699 ;
        RECT  0 39.141 0.018 39.159 ;
        RECT  0 38.601 0.018 38.619 ;
        RECT  0 38.061 0.018 38.079 ;
        RECT  0 37.521 0.018 37.539 ;
        RECT  0 36.981 0.018 36.999 ;
        RECT  0 36.441 0.018 36.459 ;
        RECT  0 35.901 0.018 35.919 ;
        RECT  0 35.361 0.018 35.379 ;
        RECT  0 34.821 0.018 34.839 ;
        RECT  0 34.281 0.018 34.299 ;
        RECT  0 33.741 0.018 33.759 ;
        RECT  0 33.201 0.018 33.219 ;
        RECT  0 32.661 0.018 32.679 ;
        RECT  0 32.121 0.018 32.139 ;
        RECT  0 31.581 0.018 31.599 ;
        RECT  0 31.041 0.018 31.059 ;
        RECT  0 30.501 0.018 30.519 ;
        RECT  0 29.961 0.018 29.979 ;
        RECT  0 29.421 0.018 29.439 ;
        RECT  0 28.881 0.018 28.899 ;
        RECT  0 28.341 0.018 28.359 ;
        RECT  0 27.801 0.018 27.819 ;
        RECT  0 27.261 0.018 27.279 ;
        RECT  0 26.721 0.018 26.739 ;
        RECT  0 26.181 0.018 26.199 ;
        RECT  0 25.641 0.018 25.659 ;
        RECT  0 25.101 0.018 25.119 ;
        RECT  0 24.561 0.018 24.579 ;
        RECT  0 24.021 0.018 24.039 ;
        RECT  0 23.481 0.018 23.499 ;
        RECT  0 22.941 0.018 22.959 ;
        RECT  0 22.401 0.018 22.419 ;
        RECT  0 21.861 0.018 21.879 ;
        RECT  0 21.321 0.018 21.339 ;
        RECT  0 20.781 0.018 20.799 ;
        RECT  0 20.241 0.018 20.259 ;
        RECT  0 19.701 0.018 19.719 ;
        RECT  0 19.161 0.018 19.179 ;
        RECT  0 18.621 0.018 18.639 ;
        RECT  0 18.081 0.018 18.099 ;
        RECT  0 17.541 0.018 17.559 ;
        RECT  0 17.001 0.018 17.019 ;
        RECT  0 16.461 0.018 16.479 ;
        RECT  0 15.921 0.018 15.939 ;
        RECT  0 15.381 0.018 15.399 ;
        RECT  0 14.841 0.018 14.859 ;
        RECT  0 14.301 0.018 14.319 ;
        RECT  0 13.761 0.018 13.779 ;
        RECT  0 13.221 0.018 13.239 ;
        RECT  0 12.681 0.018 12.699 ;
        RECT  0 12.141 0.018 12.159 ;
        RECT  0 11.601 0.018 11.619 ;
        RECT  0 11.061 0.018 11.079 ;
        RECT  0 10.521 0.018 10.539 ;
        RECT  0 9.981 0.018 9.999 ;
        RECT  0 9.441 0.018 9.459 ;
        RECT  0 8.901 0.018 8.919 ;
        RECT  0 8.361 0.018 8.379 ;
        RECT  0 7.821 0.018 7.839 ;
        RECT  0 7.281 0.018 7.299 ;
        RECT  0 6.741 0.018 6.759 ;
        RECT  0 6.201 0.018 6.219 ;
        RECT  0 5.661 0.018 5.679 ;
        RECT  0 5.121 0.018 5.139 ;
        RECT  0 4.581 0.018 4.599 ;
        RECT  0 4.041 0.018 4.059 ;
        RECT  0 3.501 0.018 3.519 ;
        RECT  0 2.961 0.018 2.979 ;
        RECT  0 2.421 0.018 2.439 ;
        RECT  0 1.881 0.018 1.899 ;
        RECT  0 1.341 0.018 1.359 ;
        RECT  0 0.801 0.018 0.819 ;
    END
  END VDD
  PIN VSS
    DIRECTION INOUT ;
    USE GROUND ;
    PORT
      LAYER M7 ;
        RECT  54.856 0.531 55.144 63.999 ;
        RECT  44.056 0.531 44.344 63.999 ;
        RECT  33.256 0.531 33.544 63.999 ;
        RECT  22.456 0.531 22.744 63.999 ;
        RECT  11.656 0.531 11.944 63.999 ;
        RECT  0.856 0.531 1.144 63.999 ;
      LAYER M6 ;
        RECT  0 60.396 0.032 60.684 ;
        RECT  0 54.996 0.032 55.284 ;
        RECT  0 49.596 0.032 49.884 ;
        RECT  0 44.196 0.032 44.484 ;
        RECT  0 38.796 0.032 39.084 ;
        RECT  0 33.396 0.032 33.684 ;
        RECT  0 27.996 0.032 28.284 ;
        RECT  0 22.596 0.032 22.884 ;
        RECT  0 17.196 0.032 17.484 ;
        RECT  0 11.796 0.032 12.084 ;
        RECT  0 6.396 0.032 6.684 ;
        RECT  0 0.996 0.032 1.284 ;
      LAYER M2 ;
        RECT  0 63.711 0.018 63.729 ;
        RECT  0 63.171 0.018 63.189 ;
        RECT  0 62.631 0.018 62.649 ;
        RECT  0 62.091 0.018 62.109 ;
        RECT  0 61.551 0.018 61.569 ;
        RECT  0 61.011 0.018 61.029 ;
        RECT  0 60.471 0.018 60.489 ;
        RECT  0 59.931 0.018 59.949 ;
        RECT  0 59.391 0.018 59.409 ;
        RECT  0 58.851 0.018 58.869 ;
        RECT  0 58.311 0.018 58.329 ;
        RECT  0 57.771 0.018 57.789 ;
        RECT  0 57.231 0.018 57.249 ;
        RECT  0 56.691 0.018 56.709 ;
        RECT  0 56.151 0.018 56.169 ;
        RECT  0 55.611 0.018 55.629 ;
        RECT  0 55.071 0.018 55.089 ;
        RECT  0 54.531 0.018 54.549 ;
        RECT  0 53.991 0.018 54.009 ;
        RECT  0 53.451 0.018 53.469 ;
        RECT  0 52.911 0.018 52.929 ;
        RECT  0 52.371 0.018 52.389 ;
        RECT  0 51.831 0.018 51.849 ;
        RECT  0 51.291 0.018 51.309 ;
        RECT  0 50.751 0.018 50.769 ;
        RECT  0 50.211 0.018 50.229 ;
        RECT  0 49.671 0.018 49.689 ;
        RECT  0 49.131 0.018 49.149 ;
        RECT  0 48.591 0.018 48.609 ;
        RECT  0 48.051 0.018 48.069 ;
        RECT  0 47.511 0.018 47.529 ;
        RECT  0 46.971 0.018 46.989 ;
        RECT  0 46.431 0.018 46.449 ;
        RECT  0 45.891 0.018 45.909 ;
        RECT  0 45.351 0.018 45.369 ;
        RECT  0 44.811 0.018 44.829 ;
        RECT  0 44.271 0.018 44.289 ;
        RECT  0 43.731 0.018 43.749 ;
        RECT  0 43.191 0.018 43.209 ;
        RECT  0 42.651 0.018 42.669 ;
        RECT  0 42.111 0.018 42.129 ;
        RECT  0 41.571 0.018 41.589 ;
        RECT  0 41.031 0.018 41.049 ;
        RECT  0 40.491 0.018 40.509 ;
        RECT  0 39.951 0.018 39.969 ;
        RECT  0 39.411 0.018 39.429 ;
        RECT  0 38.871 0.018 38.889 ;
        RECT  0 38.331 0.018 38.349 ;
        RECT  0 37.791 0.018 37.809 ;
        RECT  0 37.251 0.018 37.269 ;
        RECT  0 36.711 0.018 36.729 ;
        RECT  0 36.171 0.018 36.189 ;
        RECT  0 35.631 0.018 35.649 ;
        RECT  0 35.091 0.018 35.109 ;
        RECT  0 34.551 0.018 34.569 ;
        RECT  0 34.011 0.018 34.029 ;
        RECT  0 33.471 0.018 33.489 ;
        RECT  0 32.931 0.018 32.949 ;
        RECT  0 32.391 0.018 32.409 ;
        RECT  0 31.851 0.018 31.869 ;
        RECT  0 31.311 0.018 31.329 ;
        RECT  0 30.771 0.018 30.789 ;
        RECT  0 30.231 0.018 30.249 ;
        RECT  0 29.691 0.018 29.709 ;
        RECT  0 29.151 0.018 29.169 ;
        RECT  0 28.611 0.018 28.629 ;
        RECT  0 28.071 0.018 28.089 ;
        RECT  0 27.531 0.018 27.549 ;
        RECT  0 26.991 0.018 27.009 ;
        RECT  0 26.451 0.018 26.469 ;
        RECT  0 25.911 0.018 25.929 ;
        RECT  0 25.371 0.018 25.389 ;
        RECT  0 24.831 0.018 24.849 ;
        RECT  0 24.291 0.018 24.309 ;
        RECT  0 23.751 0.018 23.769 ;
        RECT  0 23.211 0.018 23.229 ;
        RECT  0 22.671 0.018 22.689 ;
        RECT  0 22.131 0.018 22.149 ;
        RECT  0 21.591 0.018 21.609 ;
        RECT  0 21.051 0.018 21.069 ;
        RECT  0 20.511 0.018 20.529 ;
        RECT  0 19.971 0.018 19.989 ;
        RECT  0 19.431 0.018 19.449 ;
        RECT  0 18.891 0.018 18.909 ;
        RECT  0 18.351 0.018 18.369 ;
        RECT  0 17.811 0.018 17.829 ;
        RECT  0 17.271 0.018 17.289 ;
        RECT  0 16.731 0.018 16.749 ;
        RECT  0 16.191 0.018 16.209 ;
        RECT  0 15.651 0.018 15.669 ;
        RECT  0 15.111 0.018 15.129 ;
        RECT  0 14.571 0.018 14.589 ;
        RECT  0 14.031 0.018 14.049 ;
        RECT  0 13.491 0.018 13.509 ;
        RECT  0 12.951 0.018 12.969 ;
        RECT  0 12.411 0.018 12.429 ;
        RECT  0 11.871 0.018 11.889 ;
        RECT  0 11.331 0.018 11.349 ;
        RECT  0 10.791 0.018 10.809 ;
        RECT  0 10.251 0.018 10.269 ;
        RECT  0 9.711 0.018 9.729 ;
        RECT  0 9.171 0.018 9.189 ;
        RECT  0 8.631 0.018 8.649 ;
        RECT  0 8.091 0.018 8.109 ;
        RECT  0 7.551 0.018 7.569 ;
        RECT  0 7.011 0.018 7.029 ;
        RECT  0 6.471 0.018 6.489 ;
        RECT  0 5.931 0.018 5.949 ;
        RECT  0 5.391 0.018 5.409 ;
        RECT  0 4.851 0.018 4.869 ;
        RECT  0 4.311 0.018 4.329 ;
        RECT  0 3.771 0.018 3.789 ;
        RECT  0 3.231 0.018 3.249 ;
        RECT  0 2.691 0.018 2.709 ;
        RECT  0 2.151 0.018 2.169 ;
        RECT  0 1.611 0.018 1.629 ;
        RECT  0 1.071 0.018 1.089 ;
        RECT  0 0.531 0.018 0.549 ;
      LAYER M1 ;
        RECT  0 63.711 0.018 63.729 ;
        RECT  0 63.171 0.018 63.189 ;
        RECT  0 62.631 0.018 62.649 ;
        RECT  0 62.091 0.018 62.109 ;
        RECT  0 61.551 0.018 61.569 ;
        RECT  0 61.011 0.018 61.029 ;
        RECT  0 60.471 0.018 60.489 ;
        RECT  0 59.931 0.018 59.949 ;
        RECT  0 59.391 0.018 59.409 ;
        RECT  0 58.851 0.018 58.869 ;
        RECT  0 58.311 0.018 58.329 ;
        RECT  0 57.771 0.018 57.789 ;
        RECT  0 57.231 0.018 57.249 ;
        RECT  0 56.691 0.018 56.709 ;
        RECT  0 56.151 0.018 56.169 ;
        RECT  0 55.611 0.018 55.629 ;
        RECT  0 55.071 0.018 55.089 ;
        RECT  0 54.531 0.018 54.549 ;
        RECT  0 53.991 0.018 54.009 ;
        RECT  0 53.451 0.018 53.469 ;
        RECT  0 52.911 0.018 52.929 ;
        RECT  0 52.371 0.018 52.389 ;
        RECT  0 51.831 0.018 51.849 ;
        RECT  0 51.291 0.018 51.309 ;
        RECT  0 50.751 0.018 50.769 ;
        RECT  0 50.211 0.018 50.229 ;
        RECT  0 49.671 0.018 49.689 ;
        RECT  0 49.131 0.018 49.149 ;
        RECT  0 48.591 0.018 48.609 ;
        RECT  0 48.051 0.018 48.069 ;
        RECT  0 47.511 0.018 47.529 ;
        RECT  0 46.971 0.018 46.989 ;
        RECT  0 46.431 0.018 46.449 ;
        RECT  0 45.891 0.018 45.909 ;
        RECT  0 45.351 0.018 45.369 ;
        RECT  0 44.811 0.018 44.829 ;
        RECT  0 44.271 0.018 44.289 ;
        RECT  0 43.731 0.018 43.749 ;
        RECT  0 43.191 0.018 43.209 ;
        RECT  0 42.651 0.018 42.669 ;
        RECT  0 42.111 0.018 42.129 ;
        RECT  0 41.571 0.018 41.589 ;
        RECT  0 41.031 0.018 41.049 ;
        RECT  0 40.491 0.018 40.509 ;
        RECT  0 39.951 0.018 39.969 ;
        RECT  0 39.411 0.018 39.429 ;
        RECT  0 38.871 0.018 38.889 ;
        RECT  0 38.331 0.018 38.349 ;
        RECT  0 37.791 0.018 37.809 ;
        RECT  0 37.251 0.018 37.269 ;
        RECT  0 36.711 0.018 36.729 ;
        RECT  0 36.171 0.018 36.189 ;
        RECT  0 35.631 0.018 35.649 ;
        RECT  0 35.091 0.018 35.109 ;
        RECT  0 34.551 0.018 34.569 ;
        RECT  0 34.011 0.018 34.029 ;
        RECT  0 33.471 0.018 33.489 ;
        RECT  0 32.931 0.018 32.949 ;
        RECT  0 32.391 0.018 32.409 ;
        RECT  0 31.851 0.018 31.869 ;
        RECT  0 31.311 0.018 31.329 ;
        RECT  0 30.771 0.018 30.789 ;
        RECT  0 30.231 0.018 30.249 ;
        RECT  0 29.691 0.018 29.709 ;
        RECT  0 29.151 0.018 29.169 ;
        RECT  0 28.611 0.018 28.629 ;
        RECT  0 28.071 0.018 28.089 ;
        RECT  0 27.531 0.018 27.549 ;
        RECT  0 26.991 0.018 27.009 ;
        RECT  0 26.451 0.018 26.469 ;
        RECT  0 25.911 0.018 25.929 ;
        RECT  0 25.371 0.018 25.389 ;
        RECT  0 24.831 0.018 24.849 ;
        RECT  0 24.291 0.018 24.309 ;
        RECT  0 23.751 0.018 23.769 ;
        RECT  0 23.211 0.018 23.229 ;
        RECT  0 22.671 0.018 22.689 ;
        RECT  0 22.131 0.018 22.149 ;
        RECT  0 21.591 0.018 21.609 ;
        RECT  0 21.051 0.018 21.069 ;
        RECT  0 20.511 0.018 20.529 ;
        RECT  0 19.971 0.018 19.989 ;
        RECT  0 19.431 0.018 19.449 ;
        RECT  0 18.891 0.018 18.909 ;
        RECT  0 18.351 0.018 18.369 ;
        RECT  0 17.811 0.018 17.829 ;
        RECT  0 17.271 0.018 17.289 ;
        RECT  0 16.731 0.018 16.749 ;
        RECT  0 16.191 0.018 16.209 ;
        RECT  0 15.651 0.018 15.669 ;
        RECT  0 15.111 0.018 15.129 ;
        RECT  0 14.571 0.018 14.589 ;
        RECT  0 14.031 0.018 14.049 ;
        RECT  0 13.491 0.018 13.509 ;
        RECT  0 12.951 0.018 12.969 ;
        RECT  0 12.411 0.018 12.429 ;
        RECT  0 11.871 0.018 11.889 ;
        RECT  0 11.331 0.018 11.349 ;
        RECT  0 10.791 0.018 10.809 ;
        RECT  0 10.251 0.018 10.269 ;
        RECT  0 9.711 0.018 9.729 ;
        RECT  0 9.171 0.018 9.189 ;
        RECT  0 8.631 0.018 8.649 ;
        RECT  0 8.091 0.018 8.109 ;
        RECT  0 7.551 0.018 7.569 ;
        RECT  0 7.011 0.018 7.029 ;
        RECT  0 6.471 0.018 6.489 ;
        RECT  0 5.931 0.018 5.949 ;
        RECT  0 5.391 0.018 5.409 ;
        RECT  0 4.851 0.018 4.869 ;
        RECT  0 4.311 0.018 4.329 ;
        RECT  0 3.771 0.018 3.789 ;
        RECT  0 3.231 0.018 3.249 ;
        RECT  0 2.691 0.018 2.709 ;
        RECT  0 2.151 0.018 2.169 ;
        RECT  0 1.611 0.018 1.629 ;
        RECT  0 1.071 0.018 1.089 ;
        RECT  0 0.531 0.018 0.549 ;
    END
  END VSS
  OBS
    LAYER RVTN ;
     RECT  0 0.54 64.746 0.675 ;
     RECT  0 0.945 64.746 1.215 ;
     RECT  0 1.485 64.746 1.755 ;
     RECT  0 2.025 64.746 2.295 ;
     RECT  0 2.565 64.746 2.835 ;
     RECT  0 3.105 64.746 3.375 ;
     RECT  0 3.645 64.746 3.915 ;
     RECT  0 4.185 64.746 4.455 ;
     RECT  0 4.725 64.746 4.995 ;
     RECT  0 5.265 64.746 5.535 ;
     RECT  0 5.805 64.746 6.075 ;
     RECT  0 6.345 64.746 6.615 ;
     RECT  0 6.885 64.746 7.155 ;
     RECT  0 7.425 64.746 7.695 ;
     RECT  0 7.965 64.746 8.235 ;
     RECT  0 8.505 64.746 8.775 ;
     RECT  0 9.045 64.746 9.315 ;
     RECT  0 9.585 64.746 9.855 ;
     RECT  0 10.125 64.746 10.395 ;
     RECT  0 10.665 64.746 10.935 ;
     RECT  0 11.205 64.746 11.475 ;
     RECT  0 11.745 64.746 12.015 ;
     RECT  0 12.285 64.746 12.555 ;
     RECT  0 12.825 64.746 13.095 ;
     RECT  0 13.365 64.746 13.635 ;
     RECT  0 13.905 64.746 14.175 ;
     RECT  0 14.445 64.746 14.715 ;
     RECT  0 14.985 64.746 15.255 ;
     RECT  0 15.525 64.746 15.795 ;
     RECT  0 16.065 64.746 16.335 ;
     RECT  0 16.605 64.746 16.875 ;
     RECT  0 17.145 64.746 17.415 ;
     RECT  0 17.685 64.746 17.955 ;
     RECT  0 18.225 64.746 18.495 ;
     RECT  0 18.765 64.746 19.035 ;
     RECT  0 19.305 64.746 19.575 ;
     RECT  0 19.845 64.746 20.115 ;
     RECT  0 20.385 64.746 20.655 ;
     RECT  0 20.925 64.746 21.195 ;
     RECT  0 21.465 64.746 21.735 ;
     RECT  0 22.005 64.746 22.275 ;
     RECT  0 22.545 64.746 22.815 ;
     RECT  0 23.085 64.746 23.355 ;
     RECT  0 23.625 64.746 23.895 ;
     RECT  0 24.165 64.746 24.435 ;
     RECT  0 24.705 64.746 24.975 ;
     RECT  0 25.245 64.746 25.515 ;
     RECT  0 25.785 64.746 26.055 ;
     RECT  0 26.325 64.746 26.595 ;
     RECT  0 26.865 64.746 27.135 ;
     RECT  0 27.405 64.746 27.675 ;
     RECT  0 27.945 64.746 28.215 ;
     RECT  0 28.485 64.746 28.755 ;
     RECT  0 29.025 64.746 29.295 ;
     RECT  0 29.565 64.746 29.835 ;
     RECT  0 30.105 64.746 30.375 ;
     RECT  0 30.645 64.746 30.915 ;
     RECT  0 31.185 64.746 31.455 ;
     RECT  0 31.725 64.746 31.995 ;
     RECT  0 32.265 64.746 32.535 ;
     RECT  0 32.805 64.746 33.075 ;
     RECT  0 33.345 64.746 33.615 ;
     RECT  0 33.885 64.746 34.155 ;
     RECT  0 34.425 64.746 34.695 ;
     RECT  0 34.965 64.746 35.235 ;
     RECT  0 35.505 64.746 35.775 ;
     RECT  0 36.045 64.746 36.315 ;
     RECT  0 36.585 64.746 36.855 ;
     RECT  0 37.125 64.746 37.395 ;
     RECT  0 37.665 64.746 37.935 ;
     RECT  0 38.205 64.746 38.475 ;
     RECT  0 38.745 64.746 39.015 ;
     RECT  0 39.285 64.746 39.555 ;
     RECT  0 39.825 64.746 40.095 ;
     RECT  0 40.365 64.746 40.635 ;
     RECT  0 40.905 64.746 41.175 ;
     RECT  0 41.445 64.746 41.715 ;
     RECT  0 41.985 64.746 42.255 ;
     RECT  0 42.525 64.746 42.795 ;
     RECT  0 43.065 64.746 43.335 ;
     RECT  0 43.605 64.746 43.875 ;
     RECT  0 44.145 64.746 44.415 ;
     RECT  0 44.685 64.746 44.955 ;
     RECT  0 45.225 64.746 45.495 ;
     RECT  0 45.765 64.746 46.035 ;
     RECT  0 46.305 64.746 46.575 ;
     RECT  0 46.845 64.746 47.115 ;
     RECT  0 47.385 64.746 47.655 ;
     RECT  0 47.925 64.746 48.195 ;
     RECT  0 48.465 64.746 48.735 ;
     RECT  0 49.005 64.746 49.275 ;
     RECT  0 49.545 64.746 49.815 ;
     RECT  0 50.085 64.746 50.355 ;
     RECT  0 50.625 64.746 50.895 ;
     RECT  0 51.165 64.746 51.435 ;
     RECT  0 51.705 64.746 51.975 ;
     RECT  0 52.245 64.746 52.515 ;
     RECT  0 52.785 64.746 53.055 ;
     RECT  0 53.325 64.746 53.595 ;
     RECT  0 53.865 64.746 54.135 ;
     RECT  0 54.405 64.746 54.675 ;
     RECT  0 54.945 64.746 55.215 ;
     RECT  0 55.485 64.746 55.755 ;
     RECT  0 56.025 64.746 56.295 ;
     RECT  0 56.565 64.746 56.835 ;
     RECT  0 57.105 64.746 57.375 ;
     RECT  0 57.645 64.746 57.915 ;
     RECT  0 58.185 64.746 58.455 ;
     RECT  0 58.725 64.746 58.995 ;
     RECT  0 59.265 64.746 59.535 ;
     RECT  0 59.805 64.746 60.075 ;
     RECT  0 60.345 64.746 60.615 ;
     RECT  0 60.885 64.746 61.155 ;
     RECT  0 61.425 64.746 61.695 ;
     RECT  0 61.965 64.746 62.235 ;
     RECT  0 62.505 64.746 62.775 ;
     RECT  0 63.045 64.746 63.315 ;
     RECT  0 63.585 64.746 63.855 ;
    LAYER RVTP ;
     RECT  0 0.675 64.746 0.945 ;
     RECT  0 1.215 64.746 1.485 ;
     RECT  0 1.755 64.746 2.025 ;
     RECT  0 2.295 64.746 2.565 ;
     RECT  0 2.835 64.746 3.105 ;
     RECT  0 3.375 64.746 3.645 ;
     RECT  0 3.915 64.746 4.185 ;
     RECT  0 4.455 64.746 4.725 ;
     RECT  0 4.995 64.746 5.265 ;
     RECT  0 5.535 64.746 5.805 ;
     RECT  0 6.075 64.746 6.345 ;
     RECT  0 6.615 64.746 6.885 ;
     RECT  0 7.155 64.746 7.425 ;
     RECT  0 7.695 64.746 7.965 ;
     RECT  0 8.235 64.746 8.505 ;
     RECT  0 8.775 64.746 9.045 ;
     RECT  0 9.315 64.746 9.585 ;
     RECT  0 9.855 64.746 10.125 ;
     RECT  0 10.395 64.746 10.665 ;
     RECT  0 10.935 64.746 11.205 ;
     RECT  0 11.475 64.746 11.745 ;
     RECT  0 12.015 64.746 12.285 ;
     RECT  0 12.555 64.746 12.825 ;
     RECT  0 13.095 64.746 13.365 ;
     RECT  0 13.635 64.746 13.905 ;
     RECT  0 14.175 64.746 14.445 ;
     RECT  0 14.715 64.746 14.985 ;
     RECT  0 15.255 64.746 15.525 ;
     RECT  0 15.795 64.746 16.065 ;
     RECT  0 16.335 64.746 16.605 ;
     RECT  0 16.875 64.746 17.145 ;
     RECT  0 17.415 64.746 17.685 ;
     RECT  0 17.955 64.746 18.225 ;
     RECT  0 18.495 64.746 18.765 ;
     RECT  0 19.035 64.746 19.305 ;
     RECT  0 19.575 64.746 19.845 ;
     RECT  0 20.115 64.746 20.385 ;
     RECT  0 20.655 64.746 20.925 ;
     RECT  0 21.195 64.746 21.465 ;
     RECT  0 21.735 64.746 22.005 ;
     RECT  0 22.275 64.746 22.545 ;
     RECT  0 22.815 64.746 23.085 ;
     RECT  0 23.355 64.746 23.625 ;
     RECT  0 23.895 64.746 24.165 ;
     RECT  0 24.435 64.746 24.705 ;
     RECT  0 24.975 64.746 25.245 ;
     RECT  0 25.515 64.746 25.785 ;
     RECT  0 26.055 64.746 26.325 ;
     RECT  0 26.595 64.746 26.865 ;
     RECT  0 27.135 64.746 27.405 ;
     RECT  0 27.675 64.746 27.945 ;
     RECT  0 28.215 64.746 28.485 ;
     RECT  0 28.755 64.746 29.025 ;
     RECT  0 29.295 64.746 29.565 ;
     RECT  0 29.835 64.746 30.105 ;
     RECT  0 30.375 64.746 30.645 ;
     RECT  0 30.915 64.746 31.185 ;
     RECT  0 31.455 64.746 31.725 ;
     RECT  0 31.995 64.746 32.265 ;
     RECT  0 32.535 64.746 32.805 ;
     RECT  0 33.075 64.746 33.345 ;
     RECT  0 33.615 64.746 33.885 ;
     RECT  0 34.155 64.746 34.425 ;
     RECT  0 34.695 64.746 34.965 ;
     RECT  0 35.235 64.746 35.505 ;
     RECT  0 35.775 64.746 36.045 ;
     RECT  0 36.315 64.746 36.585 ;
     RECT  0 36.855 64.746 37.125 ;
     RECT  0 37.395 64.746 37.665 ;
     RECT  0 37.935 64.746 38.205 ;
     RECT  0 38.475 64.746 38.745 ;
     RECT  0 39.015 64.746 39.285 ;
     RECT  0 39.555 64.746 39.825 ;
     RECT  0 40.095 64.746 40.365 ;
     RECT  0 40.635 64.746 40.905 ;
     RECT  0 41.175 64.746 41.445 ;
     RECT  0 41.715 64.746 41.985 ;
     RECT  0 42.255 64.746 42.525 ;
     RECT  0 42.795 64.746 43.065 ;
     RECT  0 43.335 64.746 43.605 ;
     RECT  0 43.875 64.746 44.145 ;
     RECT  0 44.415 64.746 44.685 ;
     RECT  0 44.955 64.746 45.225 ;
     RECT  0 45.495 64.746 45.765 ;
     RECT  0 46.035 64.746 46.305 ;
     RECT  0 46.575 64.746 46.845 ;
     RECT  0 47.115 64.746 47.385 ;
     RECT  0 47.655 64.746 47.925 ;
     RECT  0 48.195 64.746 48.465 ;
     RECT  0 48.735 64.746 49.005 ;
     RECT  0 49.275 64.746 49.545 ;
     RECT  0 49.815 64.746 50.085 ;
     RECT  0 50.355 64.746 50.625 ;
     RECT  0 50.895 64.746 51.165 ;
     RECT  0 51.435 64.746 51.705 ;
     RECT  0 51.975 64.746 52.245 ;
     RECT  0 52.515 64.746 52.785 ;
     RECT  0 53.055 64.746 53.325 ;
     RECT  0 53.595 64.746 53.865 ;
     RECT  0 54.135 64.746 54.405 ;
     RECT  0 54.675 64.746 54.945 ;
     RECT  0 55.215 64.746 55.485 ;
     RECT  0 55.755 64.746 56.025 ;
     RECT  0 56.295 64.746 56.565 ;
     RECT  0 56.835 64.746 57.105 ;
     RECT  0 57.375 64.746 57.645 ;
     RECT  0 57.915 64.746 58.185 ;
     RECT  0 58.455 64.746 58.725 ;
     RECT  0 58.995 64.746 59.265 ;
     RECT  0 59.535 64.746 59.805 ;
     RECT  0 60.075 64.746 60.345 ;
     RECT  0 60.615 64.746 60.885 ;
     RECT  0 61.155 64.746 61.425 ;
     RECT  0 61.695 64.746 61.965 ;
     RECT  0 62.235 64.746 62.505 ;
     RECT  0 62.775 64.746 63.045 ;
     RECT  0 63.315 64.746 63.585 ;
     RECT  0 63.855 64.746 63.99 ;
    LAYER M1 ;
     RECT  0 0.531 64.746 63.999 ;
    LAYER M2 ;
     RECT  0 0.531 7.807 63.999 ;
     RECT  7.807 0.531 12.811 64.044 ;
     RECT  12.811 0.531 14.783 64.764 ;
     RECT  14.783 0.531 17.131 63.999 ;
     RECT  14.783 64.746 17.131 64.764 ;
     RECT  17.131 0.531 21.371 64.764 ;
     RECT  21.371 0.531 22.379 64.458 ;
     RECT  22.379 0.531 25.079 64.188 ;
     RECT  25.079 0.531 26.771 64.044 ;
     RECT  26.771 0.531 40.999 63.999 ;
     RECT  40.999 0.531 43.511 64.422 ;
     RECT  43.511 0.531 64.746 63.999 ;
    LAYER M3 ;
     RECT  13.455 0.523 13.545 0.565 ;
     RECT  2.655 0.523 2.745 0.571 ;
     RECT  18.855 0.523 18.945 0.571 ;
     RECT  24.255 0.523 24.345 0.571 ;
     RECT  40.455 0.523 40.545 0.571 ;
     RECT  5.112 0.571 5.13 0.607 ;
     RECT  8.055 0.523 8.145 0.607 ;
     RECT  35.964 0.571 35.982 0.607 ;
     RECT  37.62 0.571 37.638 0.607 ;
     RECT  4.032 0.571 4.05 0.643 ;
     RECT  10.584 0.571 10.602 0.643 ;
     RECT  13.455 0.565 13.734 0.643 ;
     RECT  37.62 0.607 37.854 0.643 ;
     RECT  6.84 0.607 6.858 0.667 ;
     RECT  12.996 0.643 13.734 0.667 ;
     RECT  29.655 0.523 29.745 0.667 ;
     RECT  35.055 0.523 35.145 0.679 ;
     RECT  37.188 0.643 37.854 0.679 ;
     RECT  39.492 0.571 40.545 0.679 ;
     RECT  42.948 0.667 42.966 0.679 ;
     RECT  0.144 0.571 0.774 0.709 ;
     RECT  0.144 0.709 1.494 0.715 ;
     RECT  2.376 0.571 3.186 0.715 ;
     RECT  3.924 0.643 4.05 0.715 ;
     RECT  5.112 0.607 5.778 0.715 ;
     RECT  8.055 0.607 8.694 0.715 ;
     RECT  10.44 0.643 10.602 0.715 ;
     RECT  21.636 0.607 21.654 0.715 ;
     RECT  39.492 0.679 41.274 0.715 ;
     RECT  42.3 0.679 42.966 0.715 ;
     RECT  4.932 0.715 5.778 0.751 ;
     RECT  6.768 0.667 6.858 0.751 ;
     RECT  8.055 0.715 9.306 0.751 ;
     RECT  10.332 0.715 10.746 0.751 ;
     RECT  11.916 0.571 11.934 0.751 ;
     RECT  12.816 0.667 13.734 0.751 ;
     RECT  14.832 0.715 14.85 0.751 ;
     RECT  15.984 0.619 16.002 0.751 ;
     RECT  16.992 0.715 17.01 0.751 ;
     RECT  18.684 0.571 18.945 0.751 ;
     RECT  20.988 0.715 21.654 0.751 ;
     RECT  24.255 0.571 24.678 0.751 ;
     RECT  28.404 0.607 28.422 0.751 ;
     RECT  29.655 0.667 30.366 0.751 ;
     RECT  34.416 0.679 35.145 0.751 ;
     RECT  35.892 0.607 35.982 0.751 ;
     RECT  36.828 0.679 37.854 0.751 ;
     RECT  38.7 0.643 38.718 0.751 ;
     RECT  39.492 0.715 42.966 0.751 ;
     RECT  26.856 0.751 30.366 0.763 ;
     RECT  16.92 0.751 19.026 0.793 ;
     RECT  19.764 0.751 20.034 0.793 ;
     RECT  45.855 0.523 45.945 0.793 ;
     RECT  51.255 0.523 51.345 0.793 ;
     RECT  56.655 0.523 56.745 0.793 ;
     RECT  62.055 0.523 62.145 0.793 ;
     RECT  0.144 0.715 4.05 0.811 ;
     RECT  4.824 0.751 11.934 0.811 ;
     RECT  12.816 0.751 16.146 0.811 ;
     RECT  20.808 0.751 21.906 0.811 ;
     RECT  22.644 0.751 23.058 0.811 ;
     RECT  34.38 0.751 37.854 0.841 ;
     RECT  38.664 0.751 43.362 0.841 ;
     RECT  0.144 0.811 11.934 0.859 ;
     RECT  12.708 0.811 16.146 0.859 ;
     RECT  23.832 0.751 24.678 0.859 ;
     RECT  25.452 0.751 26.082 0.859 ;
     RECT  0.144 0.859 16.146 0.907 ;
     RECT  16.92 0.793 20.034 0.907 ;
     RECT  20.808 0.811 23.058 0.907 ;
     RECT  23.832 0.859 26.082 0.907 ;
     RECT  33.372 0.751 33.534 0.907 ;
     RECT  0.144 0.907 26.082 0.949 ;
     RECT  26.82 0.763 30.366 0.949 ;
     RECT  33.372 0.907 33.606 0.949 ;
     RECT  31.32 0.751 32.022 0.985 ;
     RECT  32.94 0.949 33.606 0.985 ;
     RECT  0.144 0.949 30.366 1.021 ;
     RECT  31.32 0.985 33.606 1.021 ;
     RECT  34.38 0.841 43.362 1.021 ;
     RECT  0.144 1.021 30.546 1.111 ;
     RECT  31.32 1.021 43.362 1.111 ;
     RECT  0.144 1.111 43.902 1.525 ;
     RECT  0.036 1.525 43.902 1.831 ;
     RECT  0.036 1.831 44.01 2.101 ;
     RECT  0.036 2.101 44.19 2.605 ;
     RECT  45.855 0.793 46.137 2.767 ;
     RECT  45.855 2.767 46.638 2.875 ;
     RECT  0.036 2.605 44.658 3.181 ;
     RECT  45.396 2.875 46.638 3.181 ;
     RECT  0.036 3.181 46.638 3.685 ;
     RECT  0.036 3.685 46.674 3.811 ;
     RECT  47.844 3.721 47.862 3.991 ;
     RECT  0.036 3.811 47.034 4.081 ;
     RECT  47.808 3.991 47.862 4.081 ;
     RECT  0.036 4.081 47.862 4.531 ;
     RECT  0.036 4.531 48.006 4.801 ;
     RECT  0.036 4.801 48.186 5.035 ;
     RECT  0.036 5.035 48.222 5.341 ;
     RECT  0.036 5.341 48.294 5.873 ;
     RECT  0.036 5.873 48.186 6.781 ;
     RECT  48.924 6.421 48.942 6.781 ;
     RECT  0.036 6.781 48.942 6.809 ;
     RECT  49.32 7.195 49.338 7.231 ;
     RECT  49.32 7.231 49.446 7.393 ;
     RECT  0.036 6.809 48.402 7.579 ;
     RECT  0.036 7.579 48.51 7.771 ;
     RECT  49.32 7.393 49.554 7.771 ;
     RECT  0.036 7.771 49.554 8.041 ;
     RECT  55.548 8.275 55.566 8.311 ;
     RECT  56.655 0.793 56.937 8.311 ;
     RECT  51.255 0.793 51.537 8.437 ;
     RECT  51.255 8.437 51.678 8.581 ;
     RECT  0.036 8.041 50.022 8.843 ;
     RECT  40.176 8.843 50.022 8.851 ;
     RECT  51.255 8.581 51.714 8.851 ;
     RECT  52.488 8.815 53.046 8.851 ;
     RECT  55.548 8.311 56.937 8.851 ;
     RECT  55.548 8.851 57.006 9.049 ;
     RECT  54.936 9.049 57.006 9.355 ;
     RECT  40.176 8.851 50.382 9.391 ;
     RECT  51.255 8.851 53.046 9.391 ;
     RECT  0.036 8.843 39.438 9.589 ;
     RECT  40.176 9.391 53.046 9.589 ;
     RECT  54.828 9.355 57.006 9.625 ;
     RECT  0.036 9.589 53.046 9.661 ;
     RECT  0.036 9.661 53.658 9.931 ;
     RECT  54.468 9.625 57.006 9.931 ;
     RECT  0.036 9.931 53.694 10.093 ;
     RECT  54.468 9.931 57.222 10.093 ;
     RECT  0.036 10.093 57.222 10.201 ;
     RECT  58.14 10.123 58.158 10.201 ;
     RECT  59.112 10.201 59.13 10.471 ;
     RECT  0.036 10.201 58.302 10.633 ;
     RECT  59.112 10.471 59.238 10.633 ;
     RECT  0.036 10.633 59.238 11.011 ;
     RECT  0.036 11.011 59.922 11.173 ;
     RECT  0.036 11.173 60.066 11.983 ;
     RECT  0.036 11.983 60.426 12.019 ;
     RECT  0.036 12.019 60.534 12.757 ;
     RECT  0.036 12.757 60.642 12.829 ;
     RECT  0.036 12.829 61.002 13.289 ;
     RECT  0.036 13.289 60.786 14.215 ;
     RECT  0.036 14.215 60.894 14.909 ;
     RECT  0.036 14.909 60.858 15.449 ;
     RECT  0.036 15.449 60.678 15.755 ;
     RECT  0.072 15.755 60.678 16.339 ;
     RECT  0.072 16.339 60.75 16.529 ;
     RECT  0.072 16.529 60.678 16.573 ;
     RECT  62.055 0.793 62.337 16.915 ;
     RECT  61.884 16.915 62.337 16.951 ;
     RECT  61.884 16.951 62.442 17.041 ;
     RECT  61.884 17.041 62.946 17.077 ;
     RECT  61.812 17.077 62.946 17.221 ;
     RECT  0.036 16.573 60.678 17.455 ;
     RECT  0.036 17.455 60.966 17.491 ;
     RECT  61.74 17.221 62.946 17.491 ;
     RECT  0.036 17.491 62.946 17.608 ;
     RECT  0.036 17.608 63.018 17.725 ;
     RECT  64.116 17.419 64.134 17.761 ;
     RECT  0.036 17.725 63.162 17.851 ;
     RECT  64.008 17.761 64.134 17.887 ;
     RECT  0.036 17.851 63.27 17.923 ;
     RECT  64.008 17.887 64.242 17.923 ;
     RECT  0.036 17.923 64.242 18.031 ;
     RECT  0.036 18.031 64.458 19.607 ;
     RECT  0.036 19.607 64.422 21.389 ;
     RECT  0.036 21.389 64.386 22.379 ;
     RECT  0.036 22.379 64.35 23.081 ;
     RECT  0.036 23.081 64.278 24.169 ;
     RECT  0.036 24.169 64.314 24.269 ;
     RECT  0.036 24.269 64.278 26.087 ;
     RECT  0.072 26.087 64.278 26.159 ;
     RECT  0.108 26.159 64.278 26.491 ;
     RECT  0.108 26.491 64.602 26.528 ;
     RECT  0.108 26.528 64.314 27.139 ;
     RECT  0.036 27.139 64.314 27.337 ;
     RECT  0.036 27.337 64.35 28.219 ;
     RECT  0.036 28.219 64.422 28.985 ;
     RECT  63.324 28.985 64.422 29.029 ;
     RECT  63.324 29.029 64.602 29.219 ;
     RECT  63.432 29.219 64.602 29.489 ;
     RECT  0.036 28.985 62.586 29.911 ;
     RECT  0.036 29.911 62.622 30.001 ;
     RECT  63.432 29.489 64.35 30.001 ;
     RECT  0.036 30.001 64.35 30.649 ;
     RECT  0.036 30.649 64.422 31.531 ;
     RECT  0.036 31.531 64.602 31.568 ;
     RECT  0.036 31.568 64.458 32.189 ;
     RECT  0.036 32.189 64.314 33.889 ;
     RECT  0.036 33.889 64.35 33.961 ;
     RECT  0.036 33.961 64.566 35.195 ;
     RECT  0.036 35.195 64.458 36.041 ;
     RECT  0.036 36.041 64.422 36.275 ;
     RECT  0.036 36.275 64.386 37.741 ;
     RECT  0.036 37.741 64.602 38.129 ;
     RECT  0.036 38.129 64.386 40.135 ;
     RECT  0.036 40.135 64.422 40.289 ;
     RECT  0.036 40.289 64.35 41.413 ;
     RECT  0.036 41.413 64.422 41.485 ;
     RECT  0.036 41.485 64.458 41.639 ;
     RECT  0.036 41.639 64.422 42.529 ;
     RECT  0.036 42.529 64.494 43.681 ;
     RECT  0.036 43.681 64.602 43.799 ;
     RECT  0.036 43.799 64.278 45.563 ;
     RECT  0.036 45.563 64.062 46.031 ;
     RECT  0.072 46.031 64.062 46.345 ;
     RECT  0.072 46.345 64.314 46.813 ;
     RECT  0.036 46.813 64.314 47.857 ;
     RECT  0.036 47.857 64.35 48.235 ;
     RECT  0.036 48.235 64.566 48.505 ;
     RECT  0.036 48.505 64.602 48.929 ;
     RECT  0.036 48.929 64.314 49.711 ;
     RECT  0.036 49.711 64.35 50.431 ;
     RECT  0.036 50.431 64.494 50.621 ;
     RECT  0.036 50.621 64.35 50.819 ;
     RECT  0.036 50.819 64.314 51.781 ;
     RECT  0.036 51.781 64.386 52.753 ;
     RECT  0.036 52.753 64.53 52.979 ;
     RECT  0.036 52.979 64.494 53.123 ;
     RECT  0.072 53.123 64.494 54.481 ;
     RECT  0.072 54.481 64.602 55.517 ;
     RECT  0.108 55.517 64.602 56.327 ;
     RECT  0.108 56.327 64.566 57.101 ;
     RECT  0.108 57.101 64.494 57.173 ;
     RECT  0.108 57.173 64.278 57.569 ;
     RECT  0.144 57.569 64.278 57.991 ;
     RECT  0.144 57.991 64.458 58.225 ;
     RECT  0.144 58.225 64.53 58.649 ;
     RECT  0.144 58.649 64.422 58.685 ;
     RECT  0.144 58.685 64.314 58.747 ;
     RECT  0.108 58.747 64.314 59.539 ;
     RECT  0.108 59.539 64.35 59.729 ;
     RECT  0.108 59.729 64.278 61.003 ;
     RECT  0.072 61.003 64.278 61.429 ;
     RECT  0.072 61.429 64.386 61.735 ;
     RECT  0.072 61.735 64.494 61.969 ;
     RECT  0.072 61.969 64.566 62.033 ;
     RECT  0.108 62.033 64.566 62.429 ;
     RECT  0.108 62.429 64.494 62.699 ;
     RECT  0.108 62.699 63.99 62.735 ;
     RECT  0.144 62.735 63.99 63.005 ;
     RECT  0.144 63.005 63.846 63.077 ;
     RECT  0.144 63.077 63.774 63.509 ;
     RECT  0.144 63.509 63.702 63.545 ;
     RECT  0.144 63.545 5.454 63.581 ;
     RECT  61.524 63.545 63.702 63.581 ;
     RECT  63.684 63.581 63.702 63.653 ;
     RECT  6.228 63.545 60.75 63.689 ;
     RECT  0.144 63.581 3.978 63.779 ;
     RECT  5.004 63.581 5.454 63.779 ;
     RECT  6.228 63.689 11.106 63.779 ;
     RECT  11.88 63.689 58.194 63.779 ;
     RECT  58.968 63.689 60.75 63.779 ;
     RECT  61.524 63.581 62.874 63.779 ;
     RECT  0.144 63.779 1.386 63.815 ;
     RECT  2.772 63.779 3.978 63.815 ;
     RECT  7.38 63.779 8.802 63.815 ;
     RECT  9.864 63.779 10.962 63.815 ;
     RECT  12.024 63.779 52.722 63.815 ;
     RECT  53.532 63.779 54.162 63.815 ;
     RECT  55.404 63.779 57.942 63.815 ;
     RECT  59.04 63.779 60.75 63.815 ;
     RECT  61.596 63.779 62.337 63.815 ;
     RECT  5.436 63.779 5.454 63.821 ;
     RECT  6.516 63.779 6.642 63.821 ;
     RECT  10.944 63.815 10.962 63.821 ;
     RECT  12.096 63.815 47.466 63.821 ;
     RECT  48.384 63.815 49.194 63.821 ;
     RECT  7.812 63.815 8.802 63.824 ;
     RECT  37.944 63.821 47.466 63.824 ;
     RECT  55.98 63.815 57.654 63.824 ;
     RECT  3.96 63.815 3.978 63.851 ;
     RECT  6.624 63.821 6.642 63.851 ;
     RECT  9.864 63.815 9.882 63.851 ;
     RECT  12.096 63.821 15.426 63.851 ;
     RECT  46.044 63.824 47.466 63.851 ;
     RECT  52.704 63.815 52.722 63.851 ;
     RECT  56.808 63.824 57.654 63.851 ;
     RECT  60.732 63.815 60.75 63.851 ;
     RECT  12.528 63.851 15.426 63.869 ;
     RECT  16.488 63.821 36.99 63.869 ;
     RECT  37.944 63.824 45.054 63.869 ;
     RECT  46.044 63.851 46.818 63.869 ;
     RECT  53.82 63.815 54.162 63.869 ;
     RECT  37.944 63.869 44.838 63.887 ;
     RECT  48.636 63.821 49.194 63.887 ;
     RECT  50.724 63.815 51.786 63.887 ;
     RECT  7.812 63.824 8.37 63.917 ;
     RECT  12.528 63.869 13.806 63.917 ;
     RECT  14.616 63.869 15.426 63.917 ;
     RECT  37.944 63.887 44.766 63.917 ;
     RECT  55.98 63.824 55.998 63.923 ;
     RECT  46.047 63.869 46.818 63.959 ;
     RECT  49.176 63.887 49.194 63.959 ;
     RECT  50.724 63.887 51.537 63.959 ;
     RECT  53.82 63.869 53.838 63.959 ;
     RECT  44.64 63.917 44.766 63.965 ;
     RECT  2.847 63.815 2.937 64.007 ;
     RECT  7.812 63.917 8.337 64.007 ;
     RECT  13.647 63.917 13.806 64.007 ;
     RECT  46.047 63.959 46.137 64.007 ;
     RECT  51.447 63.959 51.537 64.007 ;
     RECT  56.847 63.851 56.937 64.007 ;
     RECT  62.247 63.815 62.337 64.007 ;
     RECT  7.812 64.007 7.83 64.049 ;
     RECT  12.528 63.917 12.834 64.049 ;
     RECT  14.76 63.917 15.426 64.049 ;
     RECT  17.1 63.869 36.99 64.061 ;
     RECT  14.976 64.049 15.426 64.109 ;
     RECT  17.1 64.061 18.342 64.109 ;
     RECT  17.1 64.109 17.478 64.157 ;
     RECT  20.772 64.061 36.99 64.157 ;
     RECT  21.06 64.157 36.99 64.163 ;
     RECT  17.172 64.157 17.478 64.193 ;
     RECT  17.172 64.193 17.334 64.205 ;
     RECT  19.224 64.061 19.962 64.205 ;
     RECT  17.316 64.205 17.334 64.274 ;
     RECT  22.212 64.163 36.99 64.301 ;
     RECT  22.212 64.301 30.222 64.349 ;
     RECT  37.944 63.917 43.794 64.349 ;
     RECT  22.212 64.349 23.886 64.397 ;
     RECT  38.052 64.349 43.794 64.397 ;
     RECT  21.06 64.163 21.438 64.445 ;
     RECT  24.696 64.349 30.222 64.445 ;
     RECT  38.592 64.397 39.978 64.445 ;
     RECT  40.86 64.397 43.794 64.445 ;
     RECT  22.212 64.397 23.706 64.493 ;
     RECT  24.696 64.445 30.078 64.493 ;
     RECT  31.032 64.301 36.99 64.493 ;
     RECT  40.86 64.445 43.686 64.493 ;
     RECT  15.408 64.109 15.426 64.541 ;
     RECT  18.216 64.109 18.342 64.541 ;
     RECT  21.06 64.445 21.366 64.541 ;
     RECT  44.748 63.965 44.766 64.541 ;
     RECT  13.788 64.007 13.806 64.589 ;
     RECT  22.212 64.493 23.346 64.589 ;
     RECT  30.06 64.493 30.078 64.589 ;
     RECT  35.892 64.493 36.522 64.589 ;
     RECT  38.7 64.445 39.978 64.589 ;
     RECT  43.164 64.493 43.182 64.589 ;
     RECT  19.26 64.205 19.962 64.637 ;
     RECT  22.824 64.589 23.346 64.637 ;
     RECT  38.7 64.589 38.718 64.637 ;
     RECT  41.076 64.493 41.094 64.637 ;
     RECT  26.316 64.493 26.334 64.685 ;
     RECT  28.512 64.493 28.53 64.685 ;
     RECT  34.452 64.493 34.47 64.685 ;
     RECT  36.468 64.589 36.486 64.685 ;
     RECT  19.944 64.637 19.962 64.733 ;
     RECT  22.824 64.637 22.842 64.733 ;
     RECT  27.36 64.493 27.378 64.733 ;
     RECT  12.816 64.049 12.834 64.769 ;
     RECT  21.348 64.541 21.366 64.769 ;
    LAYER M4 ;
     RECT  0.025 20.064 0.037 20.088 ;
     RECT  0.017 50.16 0.037 50.184 ;
     RECT  0.037 47.664 0.061 47.784 ;
     RECT  0.037 50.16 0.061 50.28 ;
     RECT  0.037 18.192 0.085 18.312 ;
     RECT  0.037 19.728 0.085 20.088 ;
     RECT  0.025 44.976 0.085 45.72 ;
     RECT  0.061 46.896 0.085 47.784 ;
     RECT  0.061 50.16 0.085 50.76 ;
     RECT  0.037 53.184 0.085 53.352 ;
     RECT  0.037 57.168 0.085 57.624 ;
     RECT  0.061 7.2 0.092 7.224 ;
     RECT  0.037 13.68 0.092 13.704 ;
     RECT  0.085 50.16 0.092 50.856 ;
     RECT  0.037 52.08 0.092 52.104 ;
     RECT  0.085 57.168 0.092 58.824 ;
     RECT  0.085 18.096 0.097 18.312 ;
     RECT  0.085 19.728 0.097 20.136 ;
     RECT  0.085 44.832 0.097 48.36 ;
     RECT  0.092 50.16 0.097 52.104 ;
     RECT  0.085 53.184 0.097 53.976 ;
     RECT  0.017 61.008 0.1 61.032 ;
     RECT  0.092 13.44 0.125 13.704 ;
     RECT  0.037 14.784 0.125 14.808 ;
     RECT  0.085 3.168 0.133 3.192 ;
     RECT  0.092 7.2 0.133 7.32 ;
     RECT  0.092 8.304 0.133 8.328 ;
     RECT  0.085 10.272 0.133 10.44 ;
     RECT  0.125 13.44 0.133 14.808 ;
     RECT  0.097 44.832 0.133 49.176 ;
     RECT  0.097 50.16 0.133 53.976 ;
     RECT  0.037 55.296 0.133 55.32 ;
     RECT  0.092 57.168 0.133 59.64 ;
     RECT  0.1 61.008 0.133 61.08 ;
     RECT  0.097 18.096 0.156 20.136 ;
     RECT  0.133 44.832 0.156 55.32 ;
     RECT  0.133 1.584 0.181 3.432 ;
     RECT  0.133 4.416 0.181 16.872 ;
     RECT  0.156 18.096 0.205 55.32 ;
     RECT  0.133 56.592 0.205 61.08 ;
     RECT  0.085 62.688 0.205 63.624 ;
     RECT  0.092 0.576 0.229 0.6 ;
     RECT  0.181 1.584 0.229 16.872 ;
     RECT  0.205 18.096 0.229 63.624 ;
     RECT  0.229 0.576 0.889 63.624 ;
     RECT  0.889 0.576 1.091 63.72 ;
     RECT  1.091 0.576 1.139 63.624 ;
     RECT  1.139 0.72 2.293 63.624 ;
     RECT  2.293 0.576 2.648 63.624 ;
     RECT  2.648 0.528 2.752 63.732 ;
     RECT  2.752 0.576 2.84 63.732 ;
     RECT  2.84 0.576 2.944 64.002 ;
     RECT  2.944 0.576 3.443 63.624 ;
     RECT  3.443 0.576 5.132 63.576 ;
     RECT  5.132 0.576 5.141 63.72 ;
     RECT  5.141 0.72 5.425 63.72 ;
     RECT  5.425 0.72 6.757 63.816 ;
     RECT  6.757 0.672 6.851 63.816 ;
     RECT  6.851 0.672 8.048 63.624 ;
     RECT  8.048 0.528 8.053 63.732 ;
     RECT  8.053 0.528 8.152 63.816 ;
     RECT  8.152 0.798 8.24 63.816 ;
     RECT  8.24 0.798 8.344 64.002 ;
     RECT  8.344 0.816 8.483 63.912 ;
     RECT  8.483 0.816 10.357 63.816 ;
     RECT  10.357 0.672 10.573 63.816 ;
     RECT  10.573 0.576 10.883 63.816 ;
     RECT  10.883 0.672 10.973 63.816 ;
     RECT  10.973 0.672 11.9 63.672 ;
     RECT  11.9 0.576 11.987 63.672 ;
     RECT  11.987 0.672 12.877 63.672 ;
     RECT  12.877 0.672 12.977 63.864 ;
     RECT  12.977 0.672 13.448 63.912 ;
     RECT  13.448 0.528 13.552 63.912 ;
     RECT  13.552 0.576 13.64 63.912 ;
     RECT  13.64 0.576 13.763 64.002 ;
     RECT  13.763 0.864 13.777 64.002 ;
     RECT  13.777 0.864 14.483 64.584 ;
     RECT  14.483 0.912 14.933 64.584 ;
     RECT  14.933 0.912 14.956 2.808 ;
     RECT  14.933 3.888 15.397 64.584 ;
     RECT  15.397 3.888 15.443 64.728 ;
     RECT  15.443 3.888 15.964 4.296 ;
     RECT  14.956 0.912 15.973 2.376 ;
     RECT  15.964 3.888 15.973 3.912 ;
     RECT  15.973 0.624 16.057 2.376 ;
     RECT  16.057 0.912 16.213 2.376 ;
     RECT  15.973 3.6 16.213 3.912 ;
     RECT  15.443 5.328 16.441 64.728 ;
     RECT  16.213 0.912 16.595 3.912 ;
     RECT  16.441 5.088 17.075 64.728 ;
     RECT  17.075 5.088 17.093 5.592 ;
     RECT  16.595 1.152 17.125 3.912 ;
     RECT  17.093 5.088 17.125 5.496 ;
     RECT  17.125 1.152 17.212 5.496 ;
     RECT  17.212 5.136 17.309 5.496 ;
     RECT  17.212 1.152 18.229 3.816 ;
     RECT  17.309 5.184 18.229 5.496 ;
     RECT  17.075 6.576 18.229 64.728 ;
     RECT  18.229 5.184 18.277 64.728 ;
     RECT  18.229 0.912 18.493 3.816 ;
     RECT  18.493 0.912 18.661 3.96 ;
     RECT  18.277 5.04 18.661 64.728 ;
     RECT  18.661 0.912 18.848 64.728 ;
     RECT  18.848 0.528 18.952 64.728 ;
     RECT  18.952 0.798 19.144 64.728 ;
     RECT  19.144 1.152 19.297 64.728 ;
     RECT  19.297 5.04 19.955 64.728 ;
     RECT  19.955 11.136 19.973 64.728 ;
     RECT  19.973 11.136 20.051 64.632 ;
     RECT  19.955 5.28 20.099 10.152 ;
     RECT  20.099 5.28 20.195 10.104 ;
     RECT  19.297 1.152 20.204 3.72 ;
     RECT  20.204 0.912 20.291 3.72 ;
     RECT  20.195 5.28 20.369 10.008 ;
     RECT  20.369 5.28 20.549 9.864 ;
     RECT  20.291 1.152 20.876 3.72 ;
     RECT  20.549 5.28 21.107 9.816 ;
     RECT  20.051 11.136 21.164 19.56 ;
     RECT  20.051 20.544 21.164 64.632 ;
     RECT  20.876 1.152 21.241 3.96 ;
     RECT  21.164 11.136 21.253 64.632 ;
     RECT  21.107 6.24 21.305 9.816 ;
     RECT  21.253 11.04 21.437 64.632 ;
     RECT  21.109 5.088 21.481 5.16 ;
     RECT  21.305 6.336 21.625 9.816 ;
     RECT  21.437 10.8 21.625 64.632 ;
     RECT  21.625 6.336 21.881 64.632 ;
     RECT  21.241 1.152 22.213 3.432 ;
     RECT  21.481 4.464 22.213 5.16 ;
     RECT  22.213 1.152 22.345 5.304 ;
     RECT  22.345 0.816 22.381 5.304 ;
     RECT  21.881 6.336 22.381 13.608 ;
     RECT  21.881 14.592 22.813 64.632 ;
     RECT  22.381 0.816 22.844 13.608 ;
     RECT  22.813 14.592 22.844 64.728 ;
     RECT  22.844 0.816 22.861 64.728 ;
     RECT  22.861 0.816 22.931 5.112 ;
     RECT  22.861 6.096 22.979 64.728 ;
     RECT  22.979 12.528 22.997 64.728 ;
     RECT  22.997 12.624 23.285 64.728 ;
     RECT  22.931 0.912 23.941 5.112 ;
     RECT  22.979 6.096 23.941 11.4 ;
     RECT  23.941 0.912 24.037 11.64 ;
     RECT  23.285 12.624 24.037 13.128 ;
     RECT  24.037 0.912 24.248 13.128 ;
     RECT  23.285 14.112 24.248 64.728 ;
     RECT  24.248 0.528 24.352 64.728 ;
     RECT  24.352 0.798 24.544 64.728 ;
     RECT  24.544 0.864 25.228 9.528 ;
     RECT  25.228 0.912 25.58 9.528 ;
     RECT  25.58 0.912 25.667 9.672 ;
     RECT  24.544 10.752 25.669 64.728 ;
     RECT  25.667 0.912 26.345 9.096 ;
     RECT  26.345 8.928 26.636 9.096 ;
     RECT  25.669 10.08 26.636 64.728 ;
     RECT  26.345 0.912 26.669 7.944 ;
     RECT  26.636 8.928 26.777 64.728 ;
     RECT  26.669 0.912 26.809 2.52 ;
     RECT  26.777 8.928 26.832 13.704 ;
     RECT  26.669 3.984 26.849 7.944 ;
     RECT  26.849 3.984 27.029 4.008 ;
     RECT  26.809 0.768 27.155 2.52 ;
     RECT  26.832 8.928 27.173 13.464 ;
     RECT  26.777 14.688 27.245 64.728 ;
     RECT  27.245 14.784 27.347 64.728 ;
     RECT  26.849 5.088 27.349 7.944 ;
     RECT  27.173 8.928 27.349 10.824 ;
     RECT  27.347 14.88 27.389 64.728 ;
     RECT  27.173 12 27.425 13.464 ;
     RECT  27.155 0.864 27.644 2.52 ;
     RECT  27.425 12.48 27.677 13.464 ;
     RECT  27.677 12.48 27.821 12.552 ;
     RECT  27.349 5.088 27.887 10.824 ;
     RECT  28.124 13.632 28.211 13.656 ;
     RECT  27.887 4.56 28.213 10.824 ;
     RECT  27.644 0.864 28.261 3.336 ;
     RECT  28.213 4.56 28.261 11.016 ;
     RECT  28.261 0.864 28.357 11.016 ;
     RECT  28.357 0.864 28.499 11.448 ;
     RECT  28.499 0.864 28.54 9.096 ;
     RECT  27.389 14.88 28.541 64.68 ;
     RECT  28.54 3.408 28.577 9.096 ;
     RECT  28.499 10.608 28.604 11.448 ;
     RECT  27.821 12.48 28.604 12.504 ;
     RECT  28.577 4.848 28.613 9.096 ;
     RECT  28.541 14.88 28.645 64.488 ;
     RECT  28.54 0.864 29.077 1.704 ;
     RECT  28.604 10.608 29.077 12.504 ;
     RECT  29.077 0.768 29.581 1.704 ;
     RECT  29.077 10.608 29.581 12.792 ;
     RECT  29.581 0.768 29.648 1.992 ;
     RECT  28.577 3.408 29.648 3.864 ;
     RECT  28.613 4.848 29.648 7.944 ;
     RECT  28.613 9.024 29.648 9.096 ;
     RECT  29.581 10.128 29.648 12.792 ;
     RECT  28.645 13.776 29.648 64.488 ;
     RECT  29.648 0.528 29.752 64.488 ;
     RECT  29.752 0.672 29.944 64.488 ;
     RECT  29.944 12.48 30.005 64.488 ;
     RECT  29.944 0.672 30.089 11.448 ;
     RECT  30.005 12.48 30.089 64.584 ;
     RECT  30.089 12.48 30.125 64.488 ;
     RECT  30.089 0.672 30.313 11.4 ;
     RECT  30.313 0.672 30.377 8.904 ;
     RECT  30.377 1.152 30.853 8.904 ;
     RECT  30.125 12.528 31.061 64.488 ;
     RECT  30.313 9.936 31.1 11.4 ;
     RECT  31.061 12.528 31.1 14.568 ;
     RECT  31.061 15.552 31.169 64.488 ;
     RECT  31.1 9.936 31.187 14.568 ;
     RECT  31.187 9.936 31.277 11.4 ;
     RECT  31.187 12.48 31.283 14.568 ;
     RECT  30.853 1.152 31.34 8.52 ;
     RECT  31.34 0.912 31.42 8.52 ;
     RECT  31.42 0.912 31.427 4.776 ;
     RECT  31.427 1.2 31.475 4.776 ;
     RECT  31.475 1.296 31.673 4.776 ;
     RECT  31.42 6.192 31.753 8.52 ;
     RECT  31.283 12.768 32.101 14.568 ;
     RECT  32.101 12.768 32.317 14.808 ;
     RECT  32.317 12.528 32.389 14.808 ;
     RECT  31.673 1.968 32.425 4.776 ;
     RECT  32.425 1.968 32.485 5.112 ;
     RECT  31.753 6.192 32.485 7.992 ;
     RECT  31.277 10.8 32.485 11.4 ;
     RECT  32.389 12.528 32.492 14.952 ;
     RECT  31.169 16.08 32.492 64.488 ;
     RECT  32.485 10.272 32.569 11.4 ;
     RECT  32.492 12.528 32.605 64.488 ;
     RECT  32.569 10.272 32.677 11.448 ;
     RECT  32.677 9.504 32.773 11.448 ;
     RECT  32.605 12.432 32.773 64.488 ;
     RECT  32.485 1.968 33.061 7.992 ;
     RECT  32.773 9.504 33.061 64.488 ;
     RECT  33.061 1.872 33.109 7.992 ;
     RECT  33.061 8.976 33.109 64.488 ;
     RECT  33.109 1.872 33.149 64.488 ;
     RECT  33.149 7.68 33.196 64.488 ;
     RECT  33.196 8.976 33.329 64.488 ;
     RECT  32.629 0.672 33.361 0.696 ;
     RECT  33.361 0.672 33.452 0.792 ;
     RECT  33.149 1.872 33.452 6.696 ;
     RECT  33.452 0.672 33.532 6.696 ;
     RECT  33.329 9.072 33.587 64.488 ;
     RECT  33.532 4.512 33.653 6.696 ;
     RECT  33.653 6.192 34.189 6.696 ;
     RECT  33.196 7.68 34.189 7.992 ;
     RECT  33.587 12.528 34.441 64.488 ;
     RECT  34.441 12.528 34.585 64.68 ;
     RECT  34.189 6.192 34.645 7.992 ;
     RECT  33.653 4.512 34.693 5.016 ;
     RECT  34.645 6.048 34.693 7.992 ;
     RECT  33.587 9.072 34.729 11.448 ;
     RECT  34.585 12.48 34.729 64.68 ;
     RECT  33.532 0.672 34.789 3.432 ;
     RECT  34.693 4.512 34.789 7.992 ;
     RECT  34.789 0.672 34.885 7.992 ;
     RECT  34.729 9.072 34.885 64.68 ;
     RECT  34.885 0.672 35.048 64.68 ;
     RECT  35.048 0.528 35.152 64.68 ;
     RECT  35.152 0.672 35.344 64.68 ;
     RECT  35.344 4.512 35.345 64.68 ;
     RECT  35.345 4.512 35.669 28.008 ;
     RECT  35.669 4.512 35.705 11.688 ;
     RECT  35.669 13.056 35.741 28.008 ;
     RECT  35.705 5.232 35.891 11.688 ;
     RECT  35.741 13.056 35.993 27.912 ;
     RECT  35.993 15.36 36.028 27.912 ;
     RECT  35.993 13.056 36.173 14.328 ;
     RECT  35.891 5.232 36.209 11.4 ;
     RECT  36.209 6.24 36.467 11.4 ;
     RECT  35.344 0.672 36.493 3.432 ;
     RECT  35.345 29.04 36.497 64.68 ;
     RECT  36.467 6.24 36.515 8.136 ;
     RECT  36.515 6.672 36.533 8.136 ;
     RECT  36.497 29.04 36.533 64.584 ;
     RECT  36.493 0.672 36.757 4.2 ;
     RECT  36.467 9.12 36.997 11.4 ;
     RECT  36.173 14.016 36.997 14.328 ;
     RECT  36.028 15.36 36.997 17.064 ;
     RECT  36.533 29.04 36.997 64.488 ;
     RECT  36.997 14.016 37.001 17.064 ;
     RECT  36.028 18.144 37.069 27.912 ;
     RECT  36.997 28.896 37.069 64.488 ;
     RECT  37.001 14.88 37.1 17.064 ;
     RECT  37.069 18.144 37.1 64.488 ;
     RECT  36.757 0.672 37.357 5.16 ;
     RECT  36.997 9.12 37.388 12.024 ;
     RECT  37.388 9.12 37.429 12.168 ;
     RECT  37.196 13.632 37.429 13.656 ;
     RECT  36.533 6.672 37.532 7.416 ;
     RECT  37.429 9.12 37.541 13.656 ;
     RECT  37.532 6.672 37.58 7.896 ;
     RECT  37.541 9.12 37.58 13.176 ;
     RECT  37.1 14.88 38.053 64.488 ;
     RECT  37.357 0.672 38.108 5.544 ;
     RECT  37.58 6.672 38.108 13.176 ;
     RECT  38.053 14.88 38.149 64.584 ;
     RECT  38.108 0.672 38.195 13.176 ;
     RECT  38.149 14.784 38.204 64.584 ;
     RECT  38.204 14.64 38.291 64.584 ;
     RECT  38.291 14.784 38.441 64.584 ;
     RECT  38.441 23.04 38.689 64.584 ;
     RECT  38.195 0.672 38.729 5.736 ;
     RECT  38.195 6.816 38.735 13.176 ;
     RECT  38.441 14.784 38.981 22.056 ;
     RECT  38.981 14.784 39.017 15.624 ;
     RECT  38.729 1.68 39.161 5.736 ;
     RECT  39.161 1.728 39.301 5.736 ;
     RECT  39.301 1.728 39.349 5.784 ;
     RECT  38.735 6.816 39.349 13.512 ;
     RECT  38.981 16.848 39.449 22.056 ;
     RECT  39.017 14.784 39.805 15.384 ;
     RECT  39.349 1.728 39.877 13.512 ;
     RECT  39.805 14.688 39.877 15.384 ;
     RECT  39.449 16.896 39.877 22.056 ;
     RECT  38.689 23.04 39.877 64.632 ;
     RECT  39.877 1.728 39.985 15.384 ;
     RECT  38.729 0.672 40.309 0.696 ;
     RECT  39.985 1.728 40.309 15.48 ;
     RECT  40.309 0.672 40.448 15.48 ;
     RECT  39.877 16.896 40.448 64.632 ;
     RECT  40.448 0.528 40.552 64.632 ;
     RECT  40.552 0.672 40.744 64.632 ;
     RECT  40.744 16.896 40.924 17.064 ;
     RECT  40.744 18.192 40.979 19.848 ;
     RECT  40.744 20.88 41.033 64.632 ;
     RECT  41.033 25.776 41.068 64.632 ;
     RECT  40.744 0.672 41.069 5.784 ;
     RECT  41.069 0.672 41.097 5.592 ;
     RECT  41.068 28.896 41.105 64.632 ;
     RECT  41.097 0.672 41.116 3.96 ;
     RECT  41.116 0.672 41.164 3.672 ;
     RECT  41.164 3.648 41.285 3.672 ;
     RECT  41.164 0.672 41.393 2.664 ;
     RECT  41.393 0.672 41.465 2.568 ;
     RECT  40.744 6.816 41.465 15.576 ;
     RECT  41.465 7.2 41.664 15.576 ;
     RECT  40.924 16.896 41.713 16.92 ;
     RECT  41.664 7.968 41.813 15.576 ;
     RECT  41.713 16.656 41.813 16.92 ;
     RECT  41.813 7.968 41.893 16.92 ;
     RECT  40.979 18.528 42.001 19.848 ;
     RECT  41.068 25.776 42.085 27.864 ;
     RECT  41.105 28.896 42.085 64.584 ;
     RECT  42.109 3.696 42.181 3.72 ;
     RECT  41.097 5.376 42.181 5.592 ;
     RECT  42.001 17.952 42.181 19.848 ;
     RECT  41.033 20.88 42.181 24.696 ;
     RECT  41.893 7.968 42.185 16.968 ;
     RECT  42.181 17.952 42.421 24.696 ;
     RECT  42.085 25.776 42.421 64.584 ;
     RECT  41.465 0.672 42.524 2.088 ;
     RECT  42.181 3.696 42.524 5.736 ;
     RECT  42.524 0.672 42.545 5.736 ;
     RECT  42.545 2.064 42.613 5.736 ;
     RECT  42.613 2.064 42.725 6.36 ;
     RECT  42.725 2.064 42.761 6.264 ;
     RECT  42.185 8.976 42.793 16.968 ;
     RECT  42.421 17.952 42.793 64.584 ;
     RECT  42.761 3.024 42.797 6.264 ;
     RECT  42.545 0.672 42.977 0.696 ;
     RECT  42.793 8.976 42.977 64.584 ;
     RECT  42.977 9.024 43.043 64.584 ;
     RECT  42.797 4.08 43.085 6.264 ;
     RECT  43.043 15.408 43.085 64.584 ;
     RECT  43.085 15.552 43.193 64.584 ;
     RECT  43.081 7.344 43.333 7.368 ;
     RECT  43.085 4.848 43.372 6.264 ;
     RECT  43.372 5.712 43.409 6.264 ;
     RECT  43.043 9.024 43.409 14.232 ;
     RECT  42.797 3.024 43.42 3.048 ;
     RECT  43.409 5.856 43.481 6.264 ;
     RECT  43.333 7.344 43.717 7.8 ;
     RECT  43.717 7.344 43.805 7.944 ;
     RECT  43.409 9.024 43.841 11.448 ;
     RECT  43.772 2.832 43.859 2.856 ;
     RECT  43.409 12.72 43.859 14.232 ;
     RECT  43.481 6.24 43.868 6.264 ;
     RECT  43.805 7.344 43.868 7.8 ;
     RECT  43.841 9.072 43.907 11.448 ;
     RECT  43.193 15.552 44.389 64.488 ;
     RECT  44.389 15.552 44.413 64.584 ;
     RECT  43.868 6.24 44.485 7.8 ;
     RECT  44.413 15.216 44.633 64.584 ;
     RECT  43.859 13.008 44.636 14.232 ;
     RECT  44.633 15.216 44.636 17.112 ;
     RECT  44.485 5.616 44.705 7.8 ;
     RECT  44.705 6 44.869 7.8 ;
     RECT  44.636 13.008 44.869 17.112 ;
     RECT  43.907 9.504 44.876 11.448 ;
     RECT  44.869 12.48 44.876 17.112 ;
     RECT  44.633 18.192 44.915 64.584 ;
     RECT  44.915 18.192 45.011 64.44 ;
     RECT  44.821 3.84 45.013 3.864 ;
     RECT  44.869 6 45.733 7.944 ;
     RECT  45.733 6 45.781 7.992 ;
     RECT  44.876 9.504 45.781 17.112 ;
     RECT  45.013 2.88 45.848 3.864 ;
     RECT  45.781 6 45.848 17.112 ;
     RECT  45.011 18.192 45.848 63.864 ;
     RECT  45.848 0.528 45.952 63.864 ;
     RECT  45.952 0.798 46.04 63.864 ;
     RECT  46.04 0.798 46.144 64.002 ;
     RECT  46.144 18.528 46.289 30.168 ;
     RECT  46.144 5.328 46.397 8.568 ;
     RECT  46.144 31.2 46.397 63.816 ;
     RECT  46.144 11.52 46.441 17.112 ;
     RECT  46.289 18.528 46.444 30.072 ;
     RECT  46.144 3.936 46.739 4.296 ;
     RECT  46.441 13.104 46.793 17.112 ;
     RECT  46.397 5.328 46.828 6.264 ;
     RECT  46.739 3.936 46.865 3.96 ;
     RECT  46.397 31.968 46.876 63.816 ;
     RECT  46.793 13.104 46.901 17.016 ;
     RECT  46.876 31.968 47.081 63.72 ;
     RECT  46.444 18.528 47.153 22.776 ;
     RECT  47.153 18.528 47.221 19.32 ;
     RECT  46.144 9.648 47.257 10.488 ;
     RECT  46.441 11.52 47.257 11.976 ;
     RECT  46.444 23.904 47.257 30.072 ;
     RECT  47.257 9.648 47.365 11.976 ;
     RECT  46.397 7.776 47.369 8.568 ;
     RECT  47.257 23.904 47.401 30.792 ;
     RECT  47.081 31.968 47.401 33.432 ;
     RECT  47.401 23.904 47.405 33.432 ;
     RECT  47.365 9.6 47.452 11.976 ;
     RECT  47.452 9.648 47.516 11.976 ;
     RECT  47.405 23.904 47.549 27.768 ;
     RECT  47.369 7.776 47.581 7.944 ;
     RECT  47.081 34.416 47.621 63.72 ;
     RECT  46.828 5.328 47.845 5.448 ;
     RECT  47.581 6.864 47.845 7.944 ;
     RECT  47.549 25.056 47.873 27.768 ;
     RECT  47.845 5.328 47.891 7.944 ;
     RECT  46.901 13.488 47.893 17.016 ;
     RECT  47.221 18.192 47.893 19.32 ;
     RECT  47.549 23.904 47.939 23.976 ;
     RECT  47.516 9.648 48.013 12.216 ;
     RECT  47.893 13.488 48.013 19.32 ;
     RECT  47.891 5.616 48.028 7.944 ;
     RECT  48.028 5.616 48.061 6.216 ;
     RECT  47.873 25.152 48.086 27.768 ;
     RECT  48.061 6.192 48.125 6.216 ;
     RECT  48.013 9.648 48.157 19.32 ;
     RECT  47.153 20.304 48.157 22.776 ;
     RECT  47.405 28.992 48.373 33.432 ;
     RECT  47.621 34.416 48.373 38.856 ;
     RECT  47.621 39.888 48.373 63.72 ;
     RECT  48.157 9.648 48.467 22.776 ;
     RECT  48.028 7.584 48.517 7.944 ;
     RECT  48.467 9.648 48.517 13.848 ;
     RECT  48.517 7.584 48.521 13.848 ;
     RECT  48.467 15.024 48.565 22.776 ;
     RECT  47.939 23.904 48.565 23.928 ;
     RECT  48.521 7.92 48.604 13.848 ;
     RECT  48.373 28.992 48.625 38.856 ;
     RECT  48.373 39.888 48.625 63.816 ;
     RECT  48.604 7.92 48.665 8.184 ;
     RECT  48.565 15.024 48.701 23.928 ;
     RECT  48.086 25.44 48.716 27.768 ;
     RECT  48.625 28.992 48.716 63.816 ;
     RECT  48.701 19.68 48.737 23.928 ;
     RECT  48.737 19.728 48.947 23.928 ;
     RECT  48.947 19.728 49.097 23.112 ;
     RECT  48.665 8.16 49.132 8.184 ;
     RECT  48.997 24.192 49.165 24.216 ;
     RECT  48.716 25.44 49.165 63.816 ;
     RECT  49.165 24.192 49.457 63.816 ;
     RECT  48.604 9.216 49.484 13.848 ;
     RECT  48.701 15.024 49.484 18.504 ;
     RECT  49.097 19.776 49.493 23.112 ;
     RECT  49.484 9.216 49.571 18.504 ;
     RECT  49.493 19.776 49.571 21.576 ;
     RECT  49.457 24.72 49.571 63.816 ;
     RECT  49.571 14.784 49.637 18.504 ;
     RECT  49.571 9.216 49.708 13.128 ;
     RECT  49.571 29.712 49.715 63.816 ;
     RECT  49.708 10.032 49.745 13.128 ;
     RECT  49.637 14.784 49.859 17.928 ;
     RECT  49.571 19.776 50.065 19.896 ;
     RECT  50.06 8.88 50.147 8.904 ;
     RECT  49.715 29.712 50.147 39.24 ;
     RECT  50.147 29.712 50.284 38.808 ;
     RECT  49.493 22.848 50.497 23.112 ;
     RECT  50.065 19.344 50.677 19.896 ;
     RECT  49.571 20.976 50.677 21.576 ;
     RECT  49.571 24.72 50.677 28.2 ;
     RECT  49.745 10.416 50.725 13.128 ;
     RECT  49.715 40.416 50.749 63.816 ;
     RECT  50.677 19.344 50.785 21.576 ;
     RECT  50.497 22.8 50.785 23.112 ;
     RECT  50.677 24.384 50.813 28.2 ;
     RECT  49.859 15.024 50.821 17.928 ;
     RECT  50.813 24.384 50.821 28.488 ;
     RECT  50.284 29.712 50.821 36.504 ;
     RECT  50.821 15.024 50.929 18.264 ;
     RECT  50.749 40.416 50.972 63.864 ;
     RECT  50.284 37.632 51.109 38.808 ;
     RECT  50.972 40.032 51.109 63.864 ;
     RECT  50.725 9.6 51.181 13.128 ;
     RECT  50.929 14.688 51.181 18.264 ;
     RECT  50.785 19.344 51.181 23.112 ;
     RECT  51.181 9.6 51.248 18.264 ;
     RECT  51.181 19.248 51.248 23.112 ;
     RECT  50.821 24.384 51.248 36.504 ;
     RECT  51.109 37.632 51.248 63.864 ;
     RECT  51.248 0.528 51.352 63.864 ;
     RECT  51.352 0.798 51.44 63.864 ;
     RECT  51.44 0.798 51.544 64.002 ;
     RECT  51.544 9.36 51.683 19.8 ;
     RECT  51.544 29.904 51.683 63.864 ;
     RECT  51.683 9.36 51.725 17.976 ;
     RECT  51.683 35.28 51.725 63.864 ;
     RECT  51.725 36.912 51.923 63.864 ;
     RECT  51.725 9.36 52.121 13.224 ;
     RECT  51.683 19.056 52.157 19.8 ;
     RECT  51.725 14.448 52.229 17.976 ;
     RECT  51.725 35.28 52.265 35.592 ;
     RECT  52.121 9.36 52.307 9.816 ;
     RECT  52.121 10.848 52.337 13.224 ;
     RECT  51.923 36.912 52.403 55.608 ;
     RECT  52.229 16.08 52.481 17.976 ;
     RECT  51.923 56.736 52.517 63.864 ;
     RECT  52.403 36.912 52.553 51.96 ;
     RECT  52.337 11.376 52.589 13.224 ;
     RECT  52.157 19.2 52.621 19.8 ;
     RECT  51.544 20.784 52.621 28.872 ;
     RECT  51.683 29.904 52.643 34.056 ;
     RECT  52.621 19.2 52.657 28.872 ;
     RECT  52.307 9.792 52.661 9.816 ;
     RECT  52.553 51.744 52.661 51.96 ;
     RECT  52.481 16.608 52.693 17.976 ;
     RECT  52.403 52.944 52.705 55.608 ;
     RECT  52.657 19.2 52.765 28.92 ;
     RECT  52.643 29.904 52.765 33.576 ;
     RECT  52.765 19.2 52.78 33.576 ;
     RECT  52.553 36.912 52.837 50.712 ;
     RECT  52.589 11.568 52.844 13.224 ;
     RECT  52.229 14.448 52.844 14.904 ;
     RECT  52.837 36.384 52.883 50.712 ;
     RECT  52.693 16.608 52.933 18.024 ;
     RECT  52.883 36.384 52.949 50.136 ;
     RECT  52.949 40.8 52.957 42.792 ;
     RECT  52.517 56.736 52.993 57 ;
     RECT  52.933 16.608 53.021 18.072 ;
     RECT  52.949 36.384 53.027 39.816 ;
     RECT  52.78 19.296 53.075 33.576 ;
     RECT  53.027 37.728 53.093 39.816 ;
     RECT  53.075 19.296 53.309 32.472 ;
     RECT  52.265 35.28 53.341 35.304 ;
     RECT  53.309 19.296 53.345 27.96 ;
     RECT  52.661 51.936 53.372 51.96 ;
     RECT  52.705 52.944 53.372 54.504 ;
     RECT  52.949 43.824 53.381 50.136 ;
     RECT  53.381 43.92 53.417 50.136 ;
     RECT  52.517 58.128 53.529 63.864 ;
     RECT  53.372 51.936 53.603 54.504 ;
     RECT  53.341 34.656 53.629 35.304 ;
     RECT  53.027 36.384 53.629 36.504 ;
     RECT  53.345 19.344 53.633 27.96 ;
     RECT  53.309 28.992 53.633 32.472 ;
     RECT  53.417 47.76 53.651 50.136 ;
     RECT  53.651 47.856 53.669 50.136 ;
     RECT  53.629 34.656 53.777 36.504 ;
     RECT  53.021 16.608 53.917 17.352 ;
     RECT  53.603 51.936 53.957 52.488 ;
     RECT  53.603 53.568 53.989 54.504 ;
     RECT  52.705 55.536 53.989 55.608 ;
     RECT  52.844 11.568 53.996 14.904 ;
     RECT  53.417 43.92 54.028 46.776 ;
     RECT  54.028 43.92 54.029 46.632 ;
     RECT  53.996 10.992 54.061 14.904 ;
     RECT  53.529 57.072 54.061 63.864 ;
     RECT  53.633 19.776 54.065 27.96 ;
     RECT  53.989 53.568 54.097 55.608 ;
     RECT  54.061 56.976 54.097 63.864 ;
     RECT  53.075 33.552 54.133 33.576 ;
     RECT  54.029 43.92 54.137 46.584 ;
     RECT  53.633 28.992 54.173 32.04 ;
     RECT  54.097 53.568 54.173 63.864 ;
     RECT  53.669 48.384 54.188 50.136 ;
     RECT  54.133 51.408 54.188 51.528 ;
     RECT  53.093 38.16 54.229 39.816 ;
     RECT  52.957 40.8 54.229 42.6 ;
     RECT  53.917 15.936 54.317 17.352 ;
     RECT  54.229 38.16 54.317 42.6 ;
     RECT  54.061 10.656 54.421 14.904 ;
     RECT  54.421 10.656 54.493 14.952 ;
     RECT  54.317 15.936 54.493 17.16 ;
     RECT  54.065 25.632 54.493 27.96 ;
     RECT  54.173 28.992 54.493 30.216 ;
     RECT  54.317 41.136 54.497 42.6 ;
     RECT  54.497 41.184 54.529 42.6 ;
     RECT  54.173 53.568 54.533 63.72 ;
     RECT  54.317 38.16 54.577 40.008 ;
     RECT  54.493 25.632 54.604 30.216 ;
     RECT  54.065 19.776 54.611 24.552 ;
     RECT  54.457 9.648 54.637 9.672 ;
     RECT  54.493 10.656 54.637 17.16 ;
     RECT  54.529 41.184 54.661 42.744 ;
     RECT  54.137 43.92 54.661 46.152 ;
     RECT  53.777 34.752 54.673 36.504 ;
     RECT  54.673 34.752 54.701 36.6 ;
     RECT  54.637 9.648 54.705 17.16 ;
     RECT  54.173 31.776 54.749 32.04 ;
     RECT  54.705 9.648 54.785 15.72 ;
     RECT  54.701 34.752 54.817 36.648 ;
     RECT  54.577 38.16 54.817 39.336 ;
     RECT  54.785 9.648 54.857 12.312 ;
     RECT  54.785 13.296 54.892 15.72 ;
     RECT  54.188 48.384 54.893 51.528 ;
     RECT  54.893 51.36 54.961 51.528 ;
     RECT  54.901 18.144 54.988 18.168 ;
     RECT  54.133 33.024 54.997 33.576 ;
     RECT  54.817 34.752 54.997 39.336 ;
     RECT  54.749 31.776 55.037 31.8 ;
     RECT  54.604 25.872 55.141 30.216 ;
     RECT  54.893 48.384 55.285 50.184 ;
     RECT  55.285 47.76 55.333 50.184 ;
     RECT  54.611 20.736 55.361 24.552 ;
     RECT  55.361 24.096 55.372 24.552 ;
     RECT  54.661 41.184 55.381 46.152 ;
     RECT  55.333 47.328 55.381 50.184 ;
     RECT  54.997 33.024 55.397 39.336 ;
     RECT  55.381 41.184 55.468 50.184 ;
     RECT  55.372 24.528 55.469 24.552 ;
     RECT  54.892 13.296 55.541 13.704 ;
     RECT  55.141 25.872 55.571 31.08 ;
     RECT  54.705 16.848 55.573 17.16 ;
     RECT  55.571 25.872 55.577 30.984 ;
     RECT  55.468 41.184 55.613 45.816 ;
     RECT  55.613 41.184 55.667 42.984 ;
     RECT  55.577 28.464 55.685 30.984 ;
     RECT  55.397 38.256 55.717 39.336 ;
     RECT  54.857 10.32 55.753 12.312 ;
     RECT  55.541 13.296 55.753 13.464 ;
     RECT  55.573 16.848 55.753 17.736 ;
     RECT  55.753 10.32 55.82 13.464 ;
     RECT  55.537 8.304 55.861 8.328 ;
     RECT  54.961 51.36 55.861 52.44 ;
     RECT  54.533 53.568 55.861 63.624 ;
     RECT  54.892 14.928 55.897 15.72 ;
     RECT  55.897 14.832 55.969 15.72 ;
     RECT  55.753 16.8 56.077 17.736 ;
     RECT  55.249 18.816 56.077 19.08 ;
     RECT  55.969 14.736 56.293 15.72 ;
     RECT  56.077 16.8 56.293 19.08 ;
     RECT  55.717 38.256 56.293 40.056 ;
     RECT  55.781 24.864 56.396 24.888 ;
     RECT  55.577 25.872 56.396 27.24 ;
     RECT  56.293 14.736 56.437 19.08 ;
     RECT  55.361 20.736 56.437 23.016 ;
     RECT  55.82 10.176 56.473 13.464 ;
     RECT  55.397 33.024 56.509 36.792 ;
     RECT  56.473 9.936 56.533 13.464 ;
     RECT  55.468 46.8 56.533 50.184 ;
     RECT  55.861 51.36 56.533 63.816 ;
     RECT  56.293 38.256 56.545 40.152 ;
     RECT  55.861 8.304 56.648 8.856 ;
     RECT  56.533 9.936 56.648 13.608 ;
     RECT  56.437 14.736 56.648 23.016 ;
     RECT  56.396 24.864 56.648 27.24 ;
     RECT  55.685 28.464 56.648 28.824 ;
     RECT  55.685 29.808 56.648 30.984 ;
     RECT  56.509 33.024 56.648 37.128 ;
     RECT  56.545 38.16 56.648 40.152 ;
     RECT  55.667 41.184 56.648 41.976 ;
     RECT  55.667 42.96 56.648 42.984 ;
     RECT  55.613 44.16 56.648 45.816 ;
     RECT  56.533 46.8 56.648 63.816 ;
     RECT  56.648 0.528 56.752 63.816 ;
     RECT  56.752 0.798 56.84 63.816 ;
     RECT  56.84 0.798 56.944 64.002 ;
     RECT  56.944 10.464 57.053 12.552 ;
     RECT  56.944 52.176 57.053 59.448 ;
     RECT  56.944 37.776 57.089 50.808 ;
     RECT  57.089 37.776 57.196 44.52 ;
     RECT  56.944 13.872 57.197 36.024 ;
     RECT  57.053 52.176 57.197 58.152 ;
     RECT  57.089 45.648 57.305 50.808 ;
     RECT  57.197 22.272 57.449 36.024 ;
     RECT  57.449 22.272 57.521 35.976 ;
     RECT  57.521 29.856 57.593 35.976 ;
     RECT  57.521 22.272 57.601 28.824 ;
     RECT  57.601 24.432 57.635 28.824 ;
     RECT  57.305 47.472 57.683 50.808 ;
     RECT  57.635 24.432 57.737 28.728 ;
     RECT  57.683 47.472 57.737 49.608 ;
     RECT  57.593 32.448 57.772 35.976 ;
     RECT  57.197 52.416 57.772 58.152 ;
     RECT  57.737 24.432 57.773 27.192 ;
     RECT  57.053 59.184 57.913 59.448 ;
     RECT  56.944 60.528 57.913 63.624 ;
     RECT  57.601 22.272 57.917 23.208 ;
     RECT  57.196 37.776 57.971 42.216 ;
     RECT  57.197 13.872 58.021 21.288 ;
     RECT  57.773 24.672 58.025 27.192 ;
     RECT  58.021 13.056 58.061 21.288 ;
     RECT  57.305 45.648 58.067 46.248 ;
     RECT  57.053 10.464 58.085 11.88 ;
     RECT  58.025 24.672 58.097 27.144 ;
     RECT  57.772 58.128 58.117 58.152 ;
     RECT  57.913 59.184 58.117 63.624 ;
     RECT  58.085 10.128 58.129 11.88 ;
     RECT  58.061 13.056 58.129 21 ;
     RECT  58.129 10.128 58.133 21 ;
     RECT  58.117 58.128 58.163 63.624 ;
     RECT  58.133 10.128 58.169 20.76 ;
     RECT  57.772 32.448 58.169 33.096 ;
     RECT  57.971 38.208 58.169 42.216 ;
     RECT  57.737 28.704 58.205 28.728 ;
     RECT  58.163 58.128 58.205 60.552 ;
     RECT  58.169 38.448 58.237 42.216 ;
     RECT  57.196 43.344 58.237 44.52 ;
     RECT  57.683 50.688 58.237 50.808 ;
     RECT  57.772 34.368 58.241 35.976 ;
     RECT  58.241 35.952 58.277 35.976 ;
     RECT  58.237 38.448 58.277 44.52 ;
     RECT  58.277 41.04 58.309 44.52 ;
     RECT  58.309 41.04 58.381 44.616 ;
     RECT  58.067 45.648 58.381 45.768 ;
     RECT  57.593 29.856 58.403 31.368 ;
     RECT  58.205 60.192 58.457 60.552 ;
     RECT  58.237 50.688 58.489 51.288 ;
     RECT  57.772 52.416 58.489 57.048 ;
     RECT  58.169 10.848 58.493 20.76 ;
     RECT  58.493 10.848 58.529 20.712 ;
     RECT  58.417 36.288 58.561 36.312 ;
     RECT  58.489 50.688 58.565 57.048 ;
     RECT  58.565 51.264 58.601 57.048 ;
     RECT  58.529 17.424 58.637 20.712 ;
     RECT  58.637 17.424 58.643 20.088 ;
     RECT  57.917 22.752 58.705 23.208 ;
     RECT  58.529 10.848 58.709 16.152 ;
     RECT  58.561 36.288 58.709 37.176 ;
     RECT  58.277 38.448 58.709 39.96 ;
     RECT  58.457 60.192 58.709 60.408 ;
     RECT  58.705 22.752 58.741 23.64 ;
     RECT  58.097 24.672 58.741 27.096 ;
     RECT  58.741 22.752 58.781 27.096 ;
     RECT  57.737 47.472 58.789 49.416 ;
     RECT  58.709 12.24 58.817 16.152 ;
     RECT  58.403 31.344 58.817 31.368 ;
     RECT  58.381 41.04 58.817 45.768 ;
     RECT  58.817 41.04 58.853 42.744 ;
     RECT  58.601 51.504 58.853 57.048 ;
     RECT  58.789 46.896 58.876 49.416 ;
     RECT  58.403 29.856 58.877 30.312 ;
     RECT  58.817 12.24 58.925 12.552 ;
     RECT  58.163 61.872 58.925 63.624 ;
     RECT  58.817 13.632 58.933 16.152 ;
     RECT  58.877 29.616 58.961 30.312 ;
     RECT  58.709 38.784 58.961 39.96 ;
     RECT  58.169 32.448 58.993 32.904 ;
     RECT  58.933 13.632 58.997 15.096 ;
     RECT  58.709 10.848 59.033 10.872 ;
     RECT  58.961 29.856 59.033 30.312 ;
     RECT  58.853 42.576 59.033 42.744 ;
     RECT  58.876 47.856 59.033 49.416 ;
     RECT  58.997 13.632 59.069 14.856 ;
     RECT  58.925 61.872 59.069 63.576 ;
     RECT  59.069 61.872 59.132 63.528 ;
     RECT  58.925 12.528 59.141 12.552 ;
     RECT  58.781 22.752 59.141 26.856 ;
     RECT  58.643 17.424 59.177 19.848 ;
     RECT  58.241 34.368 59.177 34.824 ;
     RECT  58.853 51.696 59.177 57.048 ;
     RECT  59.033 48.96 59.209 49.416 ;
     RECT  59.177 51.696 59.213 55.752 ;
     RECT  58.205 58.128 59.221 58.728 ;
     RECT  59.141 22.752 59.269 24.504 ;
     RECT  59.177 34.368 59.269 34.392 ;
     RECT  58.817 44.304 59.269 45.768 ;
     RECT  59.213 51.696 59.293 52.008 ;
     RECT  59.069 13.632 59.315 13.656 ;
     RECT  59.132 61.44 59.321 63.528 ;
     RECT  59.221 58.08 59.365 58.728 ;
     RECT  59.177 17.424 59.429 18.84 ;
     RECT  59.269 33.888 59.501 34.392 ;
     RECT  59.033 47.856 59.501 47.88 ;
     RECT  59.365 58.08 59.533 58.968 ;
     RECT  58.709 60.192 59.533 60.216 ;
     RECT  59.501 34.032 59.555 34.392 ;
     RECT  59.177 57.024 59.557 57.048 ;
     RECT  59.533 58.08 59.557 60.216 ;
     RECT  58.741 28.272 59.609 28.296 ;
     RECT  59.557 57.024 59.645 60.216 ;
     RECT  59.209 48.96 59.651 50.184 ;
     RECT  59.645 57.024 59.699 58.104 ;
     RECT  58.961 38.784 59.713 39.672 ;
     RECT  59.713 38.208 59.747 39.672 ;
     RECT  58.709 36.288 59.749 36.504 ;
     RECT  59.749 36.288 59.785 37.08 ;
     RECT  59.429 17.76 59.789 18.84 ;
     RECT  59.269 22.32 59.789 24.504 ;
     RECT  59.213 53.232 59.789 55.752 ;
     RECT  59.141 26.064 59.821 26.856 ;
     RECT  58.993 32.064 59.825 32.904 ;
     RECT  59.555 34.32 59.825 34.392 ;
     RECT  59.645 59.28 59.843 60.216 ;
     RECT  59.033 42.576 59.845 42.6 ;
     RECT  59.651 49.248 59.857 50.184 ;
     RECT  59.747 38.208 59.861 39.144 ;
     RECT  59.845 20.064 59.893 20.088 ;
     RECT  59.269 44.304 59.893 46.152 ;
     RECT  58.933 16.128 59.897 16.152 ;
     RECT  59.789 53.232 59.933 55.464 ;
     RECT  59.825 32.784 59.965 32.904 ;
     RECT  59.893 44.112 59.98 46.152 ;
     RECT  59.845 31.392 60.005 31.416 ;
     RECT  59.845 42.384 60.037 42.6 ;
     RECT  59.821 26.064 60.041 26.952 ;
     RECT  59.98 44.208 60.041 46.152 ;
     RECT  60.037 42.384 60.073 42.888 ;
     RECT  60.041 26.208 60.077 26.952 ;
     RECT  59.861 38.208 60.077 38.232 ;
     RECT  59.893 20.064 60.101 20.184 ;
     RECT  59.069 14.736 60.113 14.856 ;
     RECT  60.077 26.496 60.133 26.952 ;
     RECT  59.321 61.44 60.133 63.288 ;
     RECT  60.133 61.2 60.149 63.288 ;
     RECT  58.853 41.04 60.181 41.064 ;
     RECT  60.101 20.064 60.185 20.568 ;
     RECT  60.133 26.496 60.22 27.864 ;
     RECT  59.293 51.936 60.227 52.008 ;
     RECT  59.789 17.952 60.253 18.84 ;
     RECT  59.825 34.368 60.257 34.392 ;
     RECT  60.181 40.992 60.284 41.064 ;
     RECT  59.033 29.904 60.293 30.312 ;
     RECT  59.785 35.856 60.293 37.08 ;
     RECT  60.284 40.56 60.371 41.064 ;
     RECT  59.843 60.048 60.373 60.216 ;
     RECT  60.149 61.2 60.373 63.144 ;
     RECT  60.371 40.992 60.419 41.064 ;
     RECT  60.293 35.856 60.469 37.032 ;
     RECT  60.041 46.128 60.473 46.152 ;
     RECT  59.699 57.024 60.508 57.864 ;
     RECT  60.227 51.984 60.545 52.008 ;
     RECT  60.073 42.144 60.577 42.888 ;
     RECT  60.037 47.328 60.613 47.352 ;
     RECT  59.857 49.248 60.653 50.76 ;
     RECT  59.933 53.232 60.653 53.544 ;
     RECT  60.113 14.832 60.761 14.856 ;
     RECT  60.421 20.736 60.793 21.24 ;
     RECT  59.789 22.416 60.793 24.504 ;
     RECT  60.293 30.288 60.869 30.312 ;
     RECT  60.577 41.184 60.901 42.888 ;
     RECT  60.793 20.736 60.905 24.504 ;
     RECT  60.653 49.968 60.905 50.76 ;
     RECT  60.253 17.952 60.937 19.608 ;
     RECT  60.901 39.216 60.973 39.24 ;
     RECT  60.905 50.736 60.977 50.76 ;
     RECT  60.937 17.472 60.997 19.608 ;
     RECT  60.905 24.336 60.997 24.504 ;
     RECT  59.965 32.784 60.997 33.048 ;
     RECT  60.613 46.8 60.997 47.352 ;
     RECT  60.373 60.048 61.013 63.144 ;
     RECT  60.901 41.184 61.045 43.08 ;
     RECT  60.041 44.208 61.045 44.76 ;
     RECT  60.997 32.784 61.081 34.248 ;
     RECT  60.22 26.496 61.085 27.624 ;
     RECT  60.508 57.024 61.141 57.72 ;
     RECT  60.997 17.088 61.189 19.608 ;
     RECT  60.905 20.736 61.189 23.304 ;
     RECT  61.081 31.68 61.189 34.248 ;
     RECT  59.933 54.624 61.196 55.464 ;
     RECT  61.225 59.04 61.237 59.064 ;
     RECT  61.013 60.048 61.237 62.184 ;
     RECT  60.997 24.336 61.297 24.648 ;
     RECT  61.085 26.496 61.297 27.24 ;
     RECT  61.237 59.04 61.333 62.184 ;
     RECT  61.196 53.904 61.405 55.464 ;
     RECT  61.141 56.784 61.405 57.72 ;
     RECT  60.469 35.712 61.477 37.032 ;
     RECT  61.477 35.712 61.573 37.656 ;
     RECT  60.973 39.216 61.573 39.384 ;
     RECT  61.045 41.184 61.573 44.76 ;
     RECT  61.189 31.2 61.585 34.248 ;
     RECT  61.573 35.712 61.585 39.384 ;
     RECT  60.997 46.8 61.657 47.736 ;
     RECT  60.997 52.752 61.657 52.776 ;
     RECT  61.585 31.2 61.693 39.384 ;
     RECT  61.657 46.752 61.765 47.736 ;
     RECT  61.657 52.56 61.765 52.776 ;
     RECT  61.405 53.904 61.765 57.72 ;
     RECT  61.693 31.2 61.909 39.768 ;
     RECT  61.573 41.184 61.909 45.144 ;
     RECT  61.765 46.608 61.909 47.736 ;
     RECT  61.189 17.088 62.017 23.304 ;
     RECT  61.297 24.336 62.017 27.24 ;
     RECT  62.017 17.088 62.048 27.24 ;
     RECT  61.436 28.416 62.048 28.44 ;
     RECT  61.573 29.52 62.048 29.544 ;
     RECT  61.909 31.2 62.048 47.736 ;
     RECT  60.997 48.768 62.048 48.792 ;
     RECT  61.441 50.784 62.048 51.384 ;
     RECT  61.765 52.56 62.048 57.72 ;
     RECT  61.333 58.8 62.048 62.184 ;
     RECT  62.048 0.528 62.152 63.732 ;
     RECT  62.152 0.798 62.24 63.732 ;
     RECT  62.24 0.798 62.344 64.002 ;
     RECT  62.344 33.024 62.453 33.336 ;
     RECT  62.344 34.656 62.453 38.616 ;
     RECT  62.344 18.768 62.489 20.424 ;
     RECT  62.344 50.688 62.489 53.064 ;
     RECT  62.344 47.28 62.497 49.464 ;
     RECT  62.344 25.2 62.533 31.848 ;
     RECT  62.344 22.56 62.597 24.216 ;
     RECT  62.344 54.72 62.597 60.792 ;
     RECT  62.344 39.744 62.669 45.288 ;
     RECT  62.597 54.72 62.669 57.096 ;
     RECT  62.489 50.688 62.705 50.904 ;
     RECT  62.669 55.248 62.723 57.096 ;
     RECT  62.597 22.752 62.741 24.216 ;
     RECT  62.533 25.2 62.741 28.968 ;
     RECT  62.669 40.896 62.741 45.288 ;
     RECT  62.741 41.904 62.764 45.288 ;
     RECT  62.764 41.904 62.771 43.128 ;
     RECT  62.497 47.28 62.777 48.984 ;
     RECT  62.705 50.688 62.777 50.856 ;
     RECT  62.489 52.224 62.777 53.064 ;
     RECT  62.489 18.768 62.813 19.944 ;
     RECT  62.741 25.2 62.813 28.488 ;
     RECT  62.533 30.432 62.813 31.848 ;
     RECT  62.777 47.28 62.813 48.12 ;
     RECT  62.597 58.128 62.813 60.792 ;
     RECT  62.771 42.528 62.819 43.128 ;
     RECT  62.819 42.624 62.857 43.128 ;
     RECT  62.777 53.04 62.885 53.064 ;
     RECT  62.723 55.248 62.885 56.184 ;
     RECT  62.813 25.2 62.908 27.336 ;
     RECT  62.813 59.232 62.908 60.792 ;
     RECT  62.344 62.496 62.908 63.288 ;
     RECT  62.908 26.256 62.921 27.336 ;
     RECT  62.813 30.432 62.921 31.368 ;
     RECT  62.453 34.656 62.993 36.12 ;
     RECT  62.908 63.264 62.993 63.288 ;
     RECT  62.344 17.616 63.029 17.64 ;
     RECT  62.921 26.256 63.029 26.52 ;
     RECT  62.993 34.656 63.029 35.208 ;
     RECT  62.813 28.464 63.065 28.488 ;
     RECT  62.669 39.744 63.065 39.768 ;
     RECT  62.857 42.672 63.065 43.128 ;
     RECT  62.764 44.496 63.073 45.288 ;
     RECT  62.453 37.488 63.1 38.616 ;
     RECT  62.908 59.808 63.1 60.792 ;
     RECT  62.741 40.896 63.101 40.92 ;
     RECT  62.453 33.024 63.137 33.096 ;
     RECT  63.065 42.672 63.209 42.84 ;
     RECT  63.1 60.768 63.281 60.792 ;
     RECT  62.885 55.248 63.325 55.896 ;
     RECT  63.325 55.248 63.389 55.272 ;
     RECT  63.137 33.024 63.425 33.048 ;
     RECT  62.777 50.688 63.425 50.712 ;
     RECT  62.813 18.96 63.497 19.944 ;
     RECT  62.908 25.2 63.533 25.224 ;
     RECT  62.741 22.752 63.539 23.4 ;
     RECT  63.539 23.184 63.569 23.4 ;
     RECT  62.813 48.096 63.569 48.12 ;
     RECT  62.813 58.128 63.589 58.152 ;
     RECT  63.589 57.456 63.641 58.152 ;
     RECT  63.641 57.456 63.676 57.48 ;
     RECT  63.029 26.4 63.677 26.52 ;
     RECT  62.921 31.344 63.677 31.368 ;
     RECT  63.1 37.584 63.677 38.616 ;
     RECT  63.209 42.672 63.893 42.696 ;
     RECT  63.421 45.312 63.893 45.336 ;
     RECT  63.569 23.184 64.109 23.208 ;
     RECT  63.029 34.656 64.181 34.68 ;
     RECT  63.677 38.352 64.181 38.616 ;
     RECT  63.781 30.192 64.217 30.216 ;
     RECT  63.925 50.784 64.217 50.808 ;
     RECT  64.181 38.352 64.289 38.376 ;
     RECT  63.961 20.4 64.325 20.424 ;
     RECT  63.677 26.496 64.613 26.52 ;
     RECT  63.829 31.536 64.613 31.56 ;
    LAYER M5 ;
     RECT  5.088 0.245 5.112 0.309 ;
     RECT  32.064 0.144 32.664 0.363 ;
     RECT  1.104 0.373 1.128 0.501 ;
     RECT  1.104 0.501 1.704 0.517 ;
     RECT  3.408 0.437 3.432 0.517 ;
     RECT  1.104 0.517 3.432 0.531 ;
     RECT  13.44 0.517 13.56 0.531 ;
     RECT  10.848 0.565 10.872 0.623 ;
     RECT  29.64 0.517 29.76 0.623 ;
     RECT  4.512 0.309 5.112 0.629 ;
     RECT  6.864 0.565 6.888 0.629 ;
     RECT  8.04 0.517 8.16 0.629 ;
     RECT  11.952 0.531 11.976 0.629 ;
     RECT  13.44 0.531 13.752 0.629 ;
     RECT  27.936 0.501 27.96 0.629 ;
     RECT  15.984 0.565 16.008 0.659 ;
     RECT  10.656 0.623 10.872 0.661 ;
     RECT  10.368 0.661 10.872 0.682 ;
     RECT  10.368 0.682 10.92 0.693 ;
     RECT  11.952 0.629 13.752 0.693 ;
     RECT  24.24 0.517 24.36 0.693 ;
     RECT  29.64 0.623 30.264 0.707 ;
     RECT  32.448 0.363 32.664 0.707 ;
     RECT  4.512 0.629 5.544 0.723 ;
     RECT  27.84 0.629 27.96 0.723 ;
     RECT  0.144 0.531 3.432 0.757 ;
     RECT  4.512 0.723 5.88 0.757 ;
     RECT  11.952 0.693 13.992 0.757 ;
     RECT  24.24 0.693 25.128 0.757 ;
     RECT  29.64 0.707 29.952 0.757 ;
     RECT  6.864 0.629 8.16 0.787 ;
     RECT  10.32 0.693 10.92 0.787 ;
     RECT  18.84 0.517 18.96 0.787 ;
     RECT  35.04 0.517 35.16 0.787 ;
     RECT  40.44 0.517 40.56 0.787 ;
     RECT  45.84 0.517 45.96 0.787 ;
     RECT  51.24 0.517 51.36 0.787 ;
     RECT  56.64 0.517 56.76 0.787 ;
     RECT  62.04 0.517 62.16 0.787 ;
     RECT  6.864 0.787 8.352 0.805 ;
     RECT  27.12 0.723 27.96 0.811 ;
     RECT  10.176 0.787 10.92 0.815 ;
     RECT  11.952 0.757 15.144 0.815 ;
     RECT  0.144 0.757 5.88 0.821 ;
     RECT  6.864 0.805 9.192 0.821 ;
     RECT  10.176 0.815 15.144 0.821 ;
     RECT  18.84 0.787 19.152 0.821 ;
     RECT  22.896 0.757 22.92 0.821 ;
     RECT  24.24 0.757 25.176 0.821 ;
     RECT  35.04 0.787 35.352 0.821 ;
     RECT  40.44 0.787 40.752 0.821 ;
     RECT  22.896 0.821 25.704 0.851 ;
     RECT  0.144 0.821 15.144 0.947 ;
     RECT  16.368 0.821 16.584 0.947 ;
     RECT  38.016 0.821 38.04 0.997 ;
     RECT  18.24 0.821 19.152 1.141 ;
     RECT  20.256 0.821 20.28 1.141 ;
     RECT  31.392 0.821 31.464 1.141 ;
     RECT  27.84 0.811 27.96 1.237 ;
     RECT  29.088 0.757 29.952 1.237 ;
     RECT  23.136 0.851 25.704 1.285 ;
     RECT  18.144 1.141 20.28 1.391 ;
     RECT  38.016 0.997 38.712 1.397 ;
     RECT  40.32 0.821 40.752 1.397 ;
     RECT  42.192 1.285 42.216 1.451 ;
     RECT  17.664 1.391 20.28 1.477 ;
     RECT  40.32 1.397 40.872 1.485 ;
     RECT  31.344 1.141 31.464 1.621 ;
     RECT  27.84 1.237 29.952 1.667 ;
     RECT  35.04 0.821 35.832 1.669 ;
     RECT  37.872 1.397 38.712 1.715 ;
     RECT  32.448 0.707 32.472 1.861 ;
     RECT  33.504 0.757 33.624 1.861 ;
     RECT  29.64 1.667 29.952 1.939 ;
     RECT  31.248 1.621 31.464 1.939 ;
     RECT  32.448 1.861 33.768 1.939 ;
     RECT  16.368 0.947 16.488 1.967 ;
     RECT  0.144 0.947 14.856 1.973 ;
     RECT  16.368 1.967 16.632 1.973 ;
     RECT  17.664 1.477 20.616 1.973 ;
     RECT  21.648 1.669 21.672 1.973 ;
     RECT  37.872 1.715 38.472 2.037 ;
     RECT  17.664 1.973 21.672 2.053 ;
     RECT  23.136 1.285 25.944 2.053 ;
     RECT  29.64 1.939 30.072 2.053 ;
     RECT  31.248 1.939 33.768 2.053 ;
     RECT  40.32 1.485 40.752 2.053 ;
     RECT  17.664 2.053 25.944 2.101 ;
     RECT  37.68 2.037 38.472 2.291 ;
     RECT  29.64 2.053 33.816 2.341 ;
     RECT  0.144 1.973 16.632 2.357 ;
     RECT  17.664 2.101 26.52 2.357 ;
     RECT  0.144 2.357 26.52 2.485 ;
     RECT  27.84 1.667 28.488 2.515 ;
     RECT  40.128 2.053 40.752 2.515 ;
     RECT  35.04 1.669 36.504 2.581 ;
     RECT  0.144 2.485 26.76 2.667 ;
     RECT  23.904 2.667 26.76 2.723 ;
     RECT  29.64 2.341 33.96 2.748 ;
     RECT  35.04 2.581 37.368 2.748 ;
     RECT  29.64 2.748 37.368 2.771 ;
     RECT  32.496 2.771 37.368 2.795 ;
     RECT  45.84 0.787 46.152 2.805 ;
     RECT  39.792 2.515 40.752 2.859 ;
     RECT  43.824 2.805 43.848 2.893 ;
     RECT  45.024 2.805 46.152 2.915 ;
     RECT  38.448 2.291 38.472 2.927 ;
     RECT  40.32 2.859 40.752 2.987 ;
     RECT  42.576 2.805 42.6 2.997 ;
     RECT  38.448 2.927 39.336 3.011 ;
     RECT  42.576 2.997 43.368 3.011 ;
     RECT  40.44 2.987 40.752 3.027 ;
     RECT  0.144 2.667 22.92 3.059 ;
     RECT  27.744 2.515 28.488 3.061 ;
     RECT  29.64 2.771 31.368 3.061 ;
     RECT  43.344 3.011 43.368 3.085 ;
     RECT  22.224 3.059 22.92 3.108 ;
     RECT  0.144 3.059 21.192 3.115 ;
     RECT  0.144 3.115 14.808 3.157 ;
     RECT  33.552 2.795 37.368 3.179 ;
     RECT  25.872 2.723 26.76 3.189 ;
     RECT  27.744 3.061 31.368 3.189 ;
     RECT  25.872 3.189 31.368 3.337 ;
     RECT  40.44 3.027 41.016 3.349 ;
     RECT  25.872 3.337 31.32 3.371 ;
     RECT  33.552 3.179 37.128 3.371 ;
     RECT  33.552 3.371 35.88 3.395 ;
     RECT  28.272 3.371 31.32 3.435 ;
     RECT  34.608 3.395 35.88 3.435 ;
     RECT  40.44 3.349 41.112 3.435 ;
     RECT  32.496 2.795 32.52 3.443 ;
     RECT  33.552 3.395 33.624 3.443 ;
     RECT  15.984 3.115 21.192 3.587 ;
     RECT  37.104 3.371 37.128 3.587 ;
     RECT  18.624 3.587 21.192 3.755 ;
     RECT  18.624 3.755 19.8 3.819 ;
     RECT  22.32 3.108 22.92 3.859 ;
     RECT  23.904 2.723 24.552 3.859 ;
     RECT  28.272 3.435 30.888 3.875 ;
     RECT  44.832 3.795 44.856 3.883 ;
     RECT  38.448 3.011 38.808 3.925 ;
     RECT  45.84 2.915 46.152 3.925 ;
     RECT  20.928 3.755 21.192 3.947 ;
     RECT  33.456 3.859 33.48 3.947 ;
     RECT  20.928 3.947 20.952 4.011 ;
     RECT  38.208 3.925 38.808 4.011 ;
     RECT  45.84 3.925 46.776 4.011 ;
     RECT  0.096 3.157 14.808 4.085 ;
     RECT  15.984 3.587 17.304 4.085 ;
     RECT  42.768 4.021 42.792 4.115 ;
     RECT  22.32 3.859 24.552 4.117 ;
     RECT  25.872 3.371 26.808 4.261 ;
     RECT  38.784 4.011 38.808 4.261 ;
     RECT  40.44 3.435 41.064 4.261 ;
     RECT  0.096 4.085 17.304 4.331 ;
     RECT  45.84 4.011 46.728 4.331 ;
     RECT  36.768 4.341 36.792 4.429 ;
     RECT  29.64 3.875 30.888 4.435 ;
     RECT  28.272 3.875 28.536 4.469 ;
     RECT  34.608 3.435 35.352 4.501 ;
     RECT  22.224 4.117 24.552 4.511 ;
     RECT  25.824 4.261 26.808 4.511 ;
     RECT  29.64 4.435 31.512 4.523 ;
     RECT  38.784 4.261 41.064 4.523 ;
     RECT  0.096 4.331 15.432 4.533 ;
     RECT  34.08 4.501 35.448 4.533 ;
     RECT  42.192 4.165 42.216 4.547 ;
     RECT  27.984 4.469 28.536 4.597 ;
     RECT  22.224 4.511 26.808 4.681 ;
     RECT  34.08 4.533 35.592 4.739 ;
     RECT  38.784 4.523 38.808 4.739 ;
     RECT  39.888 4.523 41.064 4.739 ;
     RECT  43.296 4.789 43.32 4.883 ;
     RECT  25.632 4.681 26.808 4.917 ;
     RECT  27.936 4.597 28.536 4.917 ;
     RECT  18.624 3.819 19.272 5.029 ;
     RECT  22.224 4.681 24.552 5.065 ;
     RECT  25.632 4.917 28.536 5.075 ;
     RECT  22.224 5.065 22.92 5.099 ;
     RECT  34.608 4.739 35.592 5.099 ;
     RECT  16.416 4.331 17.304 5.109 ;
     RECT  18.624 5.029 19.944 5.109 ;
     RECT  21.12 5.077 21.144 5.109 ;
     RECT  22.224 5.099 22.824 5.109 ;
     RECT  39.888 4.739 40.752 5.133 ;
     RECT  37.008 4.789 37.176 5.139 ;
     RECT  37.008 5.139 37.416 5.171 ;
     RECT  18.624 5.109 22.824 5.197 ;
     RECT  34.656 5.099 35.592 5.203 ;
     RECT  16.416 5.109 17.496 5.219 ;
     RECT  37.392 5.171 37.416 5.227 ;
     RECT  34.656 5.203 35.976 5.291 ;
     RECT  0.048 4.533 15.432 5.317 ;
     RECT  16.416 5.219 17.208 5.317 ;
     RECT  26.928 5.075 28.536 5.317 ;
     RECT  29.64 4.523 31.368 5.317 ;
     RECT  18.624 5.197 21.192 5.429 ;
     RECT  33.408 5.365 33.432 5.459 ;
     RECT  0.048 5.317 17.208 5.547 ;
     RECT  47.856 5.317 47.88 5.605 ;
     RECT  18.48 5.429 21.192 5.663 ;
     RECT  42.624 5.605 42.648 5.663 ;
     RECT  45.84 4.331 46.152 5.663 ;
     RECT  23.904 5.065 24.552 5.685 ;
     RECT  25.632 5.075 25.848 5.685 ;
     RECT  47.856 5.605 48.024 5.689 ;
     RECT  0.048 5.547 17.16 5.739 ;
     RECT  22.224 5.197 22.824 5.747 ;
     RECT  42.192 5.663 42.648 5.747 ;
     RECT  38.688 5.029 38.712 5.807 ;
     RECT  32.496 5.663 32.856 5.941 ;
     RECT  38.688 5.807 39.384 5.941 ;
     RECT  26.928 5.317 31.368 5.995 ;
     RECT  38.16 5.941 39.384 6.035 ;
     RECT  23.904 5.685 25.848 6.037 ;
     RECT  26.928 5.995 27.24 6.037 ;
     RECT  22.752 5.747 22.824 6.131 ;
     RECT  18.384 5.663 21.192 6.181 ;
     RECT  28.224 5.995 31.368 6.181 ;
     RECT  32.448 5.941 32.856 6.181 ;
     RECT  22.8 6.131 22.824 6.197 ;
     RECT  23.904 6.037 27.24 6.197 ;
     RECT  45.84 5.663 46.392 6.197 ;
     RECT  38.736 6.035 39.384 6.239 ;
     RECT  40.44 5.133 40.752 6.239 ;
     RECT  38.736 6.239 40.752 6.251 ;
     RECT  18.24 6.181 21.192 6.261 ;
     RECT  34.656 5.291 35.448 6.261 ;
     RECT  36.48 6.229 36.504 6.261 ;
     RECT  45.84 6.197 46.776 6.285 ;
     RECT  39.648 6.251 40.752 6.323 ;
     RECT  42.624 5.747 42.648 6.371 ;
     RECT  28.224 6.181 32.856 6.563 ;
     RECT  45.84 6.285 46.152 6.613 ;
     RECT  43.92 6.204 43.944 6.661 ;
     RECT  0.048 5.739 15.624 6.739 ;
     RECT  16.656 5.739 17.16 6.739 ;
     RECT  29.472 6.563 32.856 6.767 ;
     RECT  47.856 5.689 47.88 6.773 ;
     RECT  29.472 6.767 33.048 6.803 ;
     RECT  0.048 6.739 17.16 6.805 ;
     RECT  18.24 6.261 21.528 6.805 ;
     RECT  47.856 6.773 47.976 6.861 ;
     RECT  22.8 6.197 27.24 6.891 ;
     RECT  34.656 6.261 36.504 6.899 ;
     RECT  47.856 6.861 47.88 6.899 ;
     RECT  40.176 6.323 40.752 7.189 ;
     RECT  43.92 6.661 44.664 7.237 ;
     RECT  45.744 6.613 46.152 7.237 ;
     RECT  40.176 7.189 41.592 7.331 ;
     RECT  34.656 6.899 35.976 7.333 ;
     RECT  43.92 7.237 46.152 7.333 ;
     RECT  26.592 6.891 27.24 7.349 ;
     RECT  28.224 6.563 28.344 7.349 ;
     RECT  40.44 7.331 41.592 7.349 ;
     RECT  0.048 6.805 21.528 7.403 ;
     RECT  22.8 6.891 25.56 7.413 ;
     RECT  34.224 7.333 35.976 7.417 ;
     RECT  43.248 7.333 46.152 7.417 ;
     RECT  26.592 7.349 28.344 7.765 ;
     RECT  29.52 6.803 33.048 7.765 ;
     RECT  26.592 7.765 33.048 7.775 ;
     RECT  43.728 7.417 46.152 7.811 ;
     RECT  37.776 7.699 37.8 7.827 ;
     RECT  26.592 7.775 33.096 7.851 ;
     RECT  0.048 7.403 21.144 7.907 ;
     RECT  29.64 7.851 33.096 7.909 ;
     RECT  37.584 7.827 37.8 7.915 ;
     RECT  40.44 7.349 41.64 7.919 ;
     RECT  37.632 7.915 37.8 7.957 ;
     RECT  39.408 7.861 39.432 7.957 ;
     RECT  34.416 7.417 35.976 7.979 ;
     RECT  43.728 7.811 43.752 7.979 ;
     RECT  44.88 7.811 46.152 7.979 ;
     RECT  40.44 7.919 42.168 8.003 ;
     RECT  34.896 7.979 35.976 8.101 ;
     RECT  34.896 8.101 36.504 8.185 ;
     RECT  56.64 0.787 56.952 8.293 ;
     RECT  22.176 7.413 25.56 8.373 ;
     RECT  26.592 7.851 28.344 8.373 ;
     RECT  37.632 7.957 39.432 8.461 ;
     RECT  45.216 7.979 46.152 8.485 ;
     RECT  38.688 8.461 39.432 8.533 ;
     RECT  40.44 8.003 41.592 8.533 ;
     RECT  45.216 8.485 46.248 8.569 ;
     RECT  20.736 7.907 21.144 8.693 ;
     RECT  22.176 8.373 28.344 8.693 ;
     RECT  20.736 8.693 28.344 8.747 ;
     RECT  50.112 8.851 50.136 8.939 ;
     RECT  20.736 8.747 25.656 8.949 ;
     RECT  0.048 7.907 19.416 9.043 ;
     RECT  20.448 8.949 25.656 9.043 ;
     RECT  26.736 8.747 28.344 9.043 ;
     RECT  29.64 7.909 33.192 9.043 ;
     RECT  43.248 9.013 43.272 9.043 ;
     RECT  26.736 9.043 33.192 9.061 ;
     RECT  38.688 8.533 41.592 9.067 ;
     RECT  26.736 9.061 33.672 9.131 ;
     RECT  43.248 9.043 43.896 9.131 ;
     RECT  48.48 8.117 49.08 9.141 ;
     RECT  38.88 9.067 41.592 9.205 ;
     RECT  34.896 8.185 36.456 9.229 ;
     RECT  48.48 9.141 49.656 9.251 ;
     RECT  29.64 9.131 33.672 9.269 ;
     RECT  34.896 9.229 36.072 9.269 ;
     RECT  51.24 0.787 51.552 9.349 ;
     RECT  26.736 9.131 28.488 9.451 ;
     RECT  37.632 8.461 37.656 9.493 ;
     RECT  37.632 9.493 37.848 9.503 ;
     RECT  51.24 9.349 52.296 9.589 ;
     RECT  37.584 9.503 37.848 9.643 ;
     RECT  47.376 9.555 47.4 9.643 ;
     RECT  50.736 9.589 52.296 9.673 ;
     RECT  45.216 8.569 46.152 9.695 ;
     RECT  38.88 9.205 41.928 9.717 ;
     RECT  0.048 9.043 25.656 9.721 ;
     RECT  38.88 9.717 42.216 9.771 ;
     RECT  37.584 9.643 37.656 9.779 ;
     RECT  0.048 9.721 20.376 9.805 ;
     RECT  21.456 9.721 25.656 9.827 ;
     RECT  26.736 9.451 26.904 9.845 ;
     RECT  49.632 9.251 49.656 9.899 ;
     RECT  45.216 9.695 46.248 9.909 ;
     RECT  27.888 9.451 28.488 10.019 ;
     RECT  29.64 9.269 36.072 10.019 ;
     RECT  38.88 9.771 41.016 10.019 ;
     RECT  21.648 9.827 25.656 10.037 ;
     RECT  26.688 9.845 26.904 10.037 ;
     RECT  29.64 10.019 35.928 10.091 ;
     RECT  27.936 10.019 28.488 10.101 ;
     RECT  42.192 9.771 42.216 10.115 ;
     RECT  0.048 9.805 20.184 10.125 ;
     RECT  58.128 10.079 58.152 10.163 ;
     RECT  0.048 10.125 20.088 10.189 ;
     RECT  43.92 10.069 43.944 10.293 ;
     RECT  45.12 9.909 46.248 10.293 ;
     RECT  54.72 9.619 54.744 10.453 ;
     RECT  55.872 8.293 56.952 10.453 ;
     RECT  42.768 10.293 42.792 10.475 ;
     RECT  54.72 10.453 57.144 10.539 ;
     RECT  27.936 10.101 28.536 10.597 ;
     RECT  29.64 10.091 32.52 10.597 ;
     RECT  27.936 10.597 32.52 10.603 ;
     RECT  43.92 10.293 46.248 10.731 ;
     RECT  21.648 10.037 26.904 10.789 ;
     RECT  33.6 10.091 35.928 10.883 ;
     RECT  21.456 10.789 26.904 10.931 ;
     RECT  51.24 9.673 52.296 10.933 ;
     RECT  54.72 10.539 56.952 10.981 ;
     RECT  21.456 10.931 22.344 11.029 ;
     RECT  39.408 10.019 41.016 11.029 ;
     RECT  37.248 10.387 37.272 11.061 ;
     RECT  28.368 10.603 32.52 11.125 ;
     RECT  54.048 10.981 56.952 11.179 ;
     RECT  37.248 11.061 38.184 11.221 ;
     RECT  34.176 10.883 35.928 11.257 ;
     RECT  34.752 11.257 35.928 11.317 ;
     RECT  37.008 11.221 38.184 11.317 ;
     RECT  0.048 10.189 19.944 11.381 ;
     RECT  21.264 11.029 22.344 11.381 ;
     RECT  34.752 11.317 38.184 11.411 ;
     RECT  51.12 10.933 52.296 11.413 ;
     RECT  23.472 10.931 26.904 11.445 ;
     RECT  34.752 11.411 35.88 11.459 ;
     RECT  37.008 11.411 38.184 11.459 ;
     RECT  50.496 11.413 52.296 11.475 ;
     RECT  50.496 11.475 52.536 11.563 ;
     RECT  39.36 11.029 41.016 11.637 ;
     RECT  38.544 11.637 41.016 11.651 ;
     RECT  0.048 11.381 22.344 11.661 ;
     RECT  21.072 11.661 22.344 11.699 ;
     RECT  37.008 11.459 37.464 11.699 ;
     RECT  58.656 10.485 58.68 11.699 ;
     RECT  40.44 11.651 41.016 11.701 ;
     RECT  23.472 11.445 27.384 11.725 ;
     RECT  35.04 11.459 35.88 11.725 ;
     RECT  37.296 11.699 37.464 11.725 ;
     RECT  38.544 11.651 39.432 11.747 ;
     RECT  43.92 10.731 46.152 11.941 ;
     RECT  47.328 11.125 47.352 11.941 ;
     RECT  54.72 11.179 56.952 11.987 ;
     RECT  28.368 11.125 32.616 11.989 ;
     RECT  26.208 11.725 27.384 12.035 ;
     RECT  21.216 11.699 22.344 12.085 ;
     RECT  23.472 11.725 24.984 12.085 ;
     RECT  28.368 11.989 32.856 12.149 ;
     RECT  43.92 11.941 47.352 12.149 ;
     RECT  48.48 9.251 48.504 12.149 ;
     RECT  28.128 12.149 33.048 12.191 ;
     RECT  43.92 12.149 48.504 12.237 ;
     RECT  50.496 11.563 52.392 12.267 ;
     RECT  48.192 12.237 48.504 12.275 ;
     RECT  54.72 11.987 54.744 12.275 ;
     RECT  58.704 12.191 58.728 12.275 ;
     RECT  48.432 12.275 48.504 12.517 ;
     RECT  39.408 11.747 39.432 12.691 ;
     RECT  40.44 11.701 41.976 12.691 ;
     RECT  43.92 12.237 46.776 12.709 ;
     RECT  21.216 12.085 24.984 12.719 ;
     RECT  0.048 11.661 19.944 12.725 ;
     RECT  35.04 11.725 35.448 12.757 ;
     RECT  43.824 12.709 46.776 12.793 ;
     RECT  55.872 11.987 56.952 12.793 ;
     RECT  21.216 12.719 25.128 12.853 ;
     RECT  50.496 12.267 51.552 12.907 ;
     RECT  28.128 12.191 33.576 12.959 ;
     RECT  34.56 12.757 35.448 12.959 ;
     RECT  48.432 12.517 48.984 12.971 ;
     RECT  39.408 12.691 41.976 12.997 ;
     RECT  0.048 12.725 20.04 13.011 ;
     RECT  21.072 12.853 25.128 13.011 ;
     RECT  28.128 12.959 35.448 13.011 ;
     RECT  28.128 13.011 36.12 13.043 ;
     RECT  56.448 12.793 56.952 13.043 ;
     RECT  43.92 12.793 46.776 13.069 ;
     RECT  38.736 12.997 41.976 13.091 ;
     RECT  0.048 13.011 25.128 13.099 ;
     RECT  0.048 13.099 19.464 13.139 ;
     RECT  38.736 13.091 40.872 13.156 ;
     RECT  20.496 13.099 25.128 13.173 ;
     RECT  26.208 12.035 26.904 13.173 ;
     RECT  28.128 13.043 33.624 13.173 ;
     RECT  41.904 13.091 41.976 13.267 ;
     RECT  38.784 13.156 40.872 13.355 ;
     RECT  41.904 13.267 42.792 13.355 ;
     RECT  20.496 13.173 33.624 13.369 ;
     RECT  20.496 13.369 33.384 13.483 ;
     RECT  37.44 11.725 37.464 13.493 ;
     RECT  38.784 13.355 40.752 13.561 ;
     RECT  45.12 13.069 46.776 13.573 ;
     RECT  37.44 13.493 37.512 13.581 ;
     RECT  54 13.525 54.024 13.587 ;
     RECT  45.12 13.573 47.256 13.611 ;
     RECT  20.496 13.483 26.904 13.619 ;
     RECT  45.168 13.611 47.256 13.645 ;
     RECT  53.808 13.587 54.024 13.669 ;
     RECT  28.08 13.483 33.384 13.675 ;
     RECT  37.248 13.587 37.272 13.675 ;
     RECT  43.92 13.069 43.944 13.675 ;
     RECT  45.168 13.645 46.248 13.675 ;
     RECT  47.232 13.645 47.256 13.675 ;
     RECT  56.544 13.043 56.952 13.675 ;
     RECT  58.704 13.621 59.304 13.705 ;
     RECT  0.048 13.139 19.416 13.715 ;
     RECT  34.8 13.043 36.12 14.005 ;
     RECT  42.768 13.355 42.792 14.005 ;
     RECT  53.376 13.669 54.024 14.005 ;
     RECT  48.432 12.971 48.456 14.053 ;
     RECT  20.496 13.619 21.24 14.099 ;
     RECT  49.536 13.685 49.56 14.099 ;
     RECT  52.896 14.005 54.84 14.099 ;
     RECT  22.512 13.619 26.904 14.187 ;
     RECT  0.096 13.715 19.416 14.197 ;
     RECT  26.736 14.187 26.904 14.251 ;
     RECT  52.896 14.099 54.648 14.251 ;
     RECT  34.8 14.005 36.984 14.339 ;
     RECT  53.184 14.251 54.648 14.339 ;
     RECT  22.512 14.187 25.656 14.379 ;
     RECT  39.408 13.561 40.752 14.495 ;
     RECT  20.832 14.099 21.24 14.581 ;
     RECT  22.512 14.379 25.272 14.581 ;
     RECT  34.8 14.339 36.456 14.581 ;
     RECT  47.904 14.053 48.456 14.675 ;
     RECT  39.408 14.495 41.592 14.709 ;
     RECT  42.768 14.005 43.752 14.709 ;
     RECT  47.904 14.675 47.928 14.713 ;
     RECT  26.88 14.251 26.904 14.739 ;
     RECT  28.8 13.675 33.384 14.739 ;
     RECT  51.24 12.907 51.552 14.739 ;
     RECT  0.096 14.197 19.8 14.773 ;
     RECT  38.256 14.581 38.28 14.773 ;
     RECT  39.408 14.709 43.752 14.773 ;
     RECT  45.216 13.675 46.248 14.773 ;
     RECT  39.408 14.773 46.488 14.797 ;
     RECT  49.824 14.739 49.848 14.827 ;
     RECT  53.184 14.339 53.64 14.827 ;
     RECT  28.8 14.739 33.72 14.831 ;
     RECT  43.008 14.797 46.488 14.837 ;
     RECT  51.024 14.739 51.552 14.837 ;
     RECT  28.512 14.831 33.72 14.856 ;
     RECT  34.704 14.581 36.456 14.856 ;
     RECT  58.896 13.705 59.304 14.867 ;
     RECT  26.88 14.739 27.336 14.869 ;
     RECT  28.512 14.856 36.456 14.869 ;
     RECT  38.16 14.773 38.28 14.901 ;
     RECT  39.408 14.797 41.64 14.901 ;
     RECT  20.832 14.581 25.272 14.915 ;
     RECT  53.616 14.827 53.64 14.915 ;
     RECT  26.88 14.869 36.456 14.955 ;
     RECT  34.128 14.955 36.456 14.963 ;
     RECT  21.264 14.915 25.272 15.019 ;
     RECT  38.16 14.901 41.64 15.083 ;
     RECT  26.88 14.955 33.096 15.339 ;
     RECT  34.176 14.963 36.456 15.349 ;
     RECT  51.024 14.837 51.912 15.349 ;
     RECT  38.16 15.083 40.872 15.403 ;
     RECT  21.456 15.019 25.272 15.407 ;
     RECT  26.88 15.339 27.72 15.407 ;
     RECT  43.008 14.837 47.832 15.443 ;
     RECT  0.048 14.773 19.8 15.477 ;
     RECT  38.16 15.403 40.752 15.491 ;
     RECT  28.848 15.339 33.096 15.787 ;
     RECT  43.632 15.443 47.832 15.851 ;
     RECT  50.256 15.349 51.912 15.925 ;
     RECT  54.624 14.339 54.648 15.971 ;
     RECT  49.824 15.925 51.912 15.983 ;
     RECT  58.896 14.867 58.92 16.019 ;
     RECT  29.64 15.787 33.096 16.021 ;
     RECT  34.176 15.349 37.08 16.021 ;
     RECT  41.856 15.955 41.88 16.043 ;
     RECT  21.456 15.407 27.72 16.117 ;
     RECT  29.64 16.021 37.08 16.213 ;
     RECT  48.96 15.983 51.912 16.269 ;
     RECT  29.64 16.213 37.272 16.299 ;
     RECT  43.632 15.851 46.632 16.405 ;
     RECT  47.616 15.851 47.832 16.405 ;
     RECT  21.312 16.117 27.72 16.491 ;
     RECT  47.616 16.405 48.744 16.491 ;
     RECT  43.296 16.405 46.632 16.501 ;
     RECT  56.64 13.675 56.952 16.501 ;
     RECT  21.312 16.491 25.272 16.555 ;
     RECT  41.904 16.501 46.632 16.595 ;
     RECT  49.824 16.269 51.912 16.619 ;
     RECT  50.688 16.619 51.912 16.645 ;
     RECT  0.048 15.477 20.184 16.693 ;
     RECT  21.312 16.555 24.984 16.693 ;
     RECT  26.496 16.491 27.72 16.693 ;
     RECT  41.904 16.595 43.752 16.787 ;
     RECT  26.496 16.693 28.536 16.835 ;
     RECT  45.072 16.595 46.632 16.931 ;
     RECT  56.448 16.501 56.952 16.933 ;
     RECT  47.616 16.491 47.64 16.981 ;
     RECT  40.44 15.491 40.752 16.991 ;
     RECT  50.688 16.645 52.536 16.991 ;
     RECT  54.096 16.501 54.12 16.991 ;
     RECT  41.904 16.787 42.12 17.003 ;
     RECT  29.64 16.299 37.128 17.043 ;
     RECT  47.52 16.981 47.64 17.067 ;
     RECT  56.448 16.933 57.096 17.067 ;
     RECT  38.784 15.491 39.432 17.075 ;
     RECT  40.44 16.991 40.872 17.075 ;
     RECT  50.688 16.991 53.064 17.075 ;
     RECT  54.096 16.991 54.696 17.075 ;
     RECT  58.128 16.165 58.152 17.123 ;
     RECT  29.28 17.043 37.128 17.131 ;
     RECT  47.616 17.067 47.64 17.131 ;
     RECT  50.688 17.075 51.552 17.171 ;
     RECT  54.096 17.075 54.12 17.171 ;
     RECT  29.52 17.131 37.128 17.413 ;
     RECT  48.72 16.491 48.744 17.459 ;
     RECT  29.52 17.413 37.176 17.557 ;
     RECT  43.584 16.787 43.752 17.557 ;
     RECT  45.072 16.931 46.152 17.557 ;
     RECT  0.048 16.693 24.984 17.589 ;
     RECT  29.52 17.557 37.608 17.643 ;
     RECT  50.736 17.171 51.552 17.643 ;
     RECT  56.64 17.067 57.096 17.651 ;
     RECT  0.048 17.589 25.128 17.677 ;
     RECT  29.52 17.643 36.408 17.677 ;
     RECT  52.704 17.075 52.728 18.037 ;
     RECT  26.496 16.835 28.296 18.133 ;
     RECT  47.904 17.557 48.504 18.165 ;
     RECT  40.44 17.075 40.752 18.181 ;
     RECT  51.12 17.643 51.552 18.181 ;
     RECT  47.616 18.165 48.504 18.219 ;
     RECT  52.704 18.037 52.968 18.219 ;
     RECT  54.912 18.133 54.936 18.219 ;
     RECT  21.12 17.677 25.128 18.229 ;
     RECT  26.304 18.133 28.296 18.229 ;
     RECT  42.096 17.003 42.12 18.236 ;
     RECT  43.584 17.557 46.152 18.236 ;
     RECT  47.616 18.219 47.928 18.253 ;
     RECT  51.12 18.181 51.672 18.275 ;
     RECT  40.44 18.181 40.968 18.517 ;
     RECT  42.096 18.236 46.152 18.517 ;
     RECT  40.44 18.517 46.152 18.603 ;
     RECT  21.12 18.229 28.296 18.611 ;
     RECT  41.952 18.603 46.152 18.613 ;
     RECT  28.272 18.611 28.296 18.643 ;
     RECT  29.64 17.677 36.408 18.643 ;
     RECT  47.808 18.253 47.928 18.667 ;
     RECT  60 18.565 60.024 18.667 ;
     RECT  62.04 0.787 62.352 18.757 ;
     RECT  28.272 18.643 36.408 18.795 ;
     RECT  28.272 18.795 35.832 18.803 ;
     RECT  38.208 18.757 38.232 18.805 ;
     RECT  41.952 18.613 46.776 18.851 ;
     RECT  61.008 17.077 61.032 18.851 ;
     RECT  41.952 18.851 44.232 18.859 ;
     RECT  21.12 18.611 27.192 18.869 ;
     RECT  62.04 18.757 62.712 18.899 ;
     RECT  21.024 18.869 27.192 18.933 ;
     RECT  28.272 18.803 33.672 18.995 ;
     RECT  20.928 18.933 27.192 19.021 ;
     RECT  37.392 18.805 38.232 19.027 ;
     RECT  51.24 18.275 51.672 19.027 ;
     RECT  52.704 18.219 52.728 19.027 ;
     RECT  62.04 18.899 62.472 19.055 ;
     RECT  42 18.859 44.232 19.081 ;
     RECT  47.808 18.667 47.832 19.091 ;
     RECT  51.24 19.027 52.728 19.115 ;
     RECT  61.056 19.055 62.472 19.139 ;
     RECT  37.152 19.027 38.232 19.155 ;
     RECT  39.408 17.075 39.432 19.155 ;
     RECT  61.152 19.139 62.472 19.179 ;
     RECT  43.632 19.081 44.232 19.235 ;
     RECT  52.704 19.115 52.728 19.235 ;
     RECT  37.152 19.155 39.432 19.317 ;
     RECT  40.44 18.603 40.968 19.317 ;
     RECT  51.24 19.115 51.552 19.333 ;
     RECT  42 19.081 42.024 19.371 ;
     RECT  53.232 19.295 53.592 19.379 ;
     RECT  37.152 19.317 40.968 19.523 ;
     RECT  21.216 19.021 27.192 19.533 ;
     RECT  26.784 19.533 27.192 19.573 ;
     RECT  28.272 18.995 33.096 19.573 ;
     RECT  58.896 18.805 58.92 19.669 ;
     RECT  45.216 18.851 46.776 19.701 ;
     RECT  0.048 17.677 19.944 19.731 ;
     RECT  26.784 19.573 33.096 19.755 ;
     RECT  28.368 19.755 33.096 19.763 ;
     RECT  56.64 17.651 56.952 19.765 ;
     RECT  28.368 19.763 32.616 19.811 ;
     RECT  54.576 19.731 54.6 19.819 ;
     RECT  62.04 19.179 62.472 19.849 ;
     RECT  45.216 19.701 46.824 19.861 ;
     RECT  26.784 19.755 27.288 19.947 ;
     RECT  56.448 19.765 56.952 19.957 ;
     RECT  29.472 19.811 32.616 20.011 ;
     RECT  37.152 19.523 38.232 20.021 ;
     RECT  58.56 19.669 58.92 20.021 ;
     RECT  58.56 20.021 59.88 20.075 ;
     RECT  48.432 19.701 48.552 20.101 ;
     RECT  58.56 20.075 58.632 20.109 ;
     RECT  59.856 20.075 59.88 20.109 ;
     RECT  0.048 19.731 19.992 20.115 ;
     RECT  34.944 18.803 35.832 20.115 ;
     RECT  36.912 20.021 38.232 20.115 ;
     RECT  44.976 19.861 46.824 20.149 ;
     RECT  59.904 20.149 59.928 20.233 ;
     RECT  48.288 20.101 48.552 20.267 ;
     RECT  48.432 20.267 48.552 20.277 ;
     RECT  49.536 19.957 49.56 20.277 ;
     RECT  34.944 20.115 38.232 20.341 ;
     RECT  44.976 20.149 47.304 20.365 ;
     RECT  43.632 19.235 43.848 20.469 ;
     RECT  44.976 20.365 47.256 20.469 ;
     RECT  0.048 20.115 20.04 20.533 ;
     RECT  21.216 19.533 25.752 20.533 ;
     RECT  26.784 19.947 27.24 20.533 ;
     RECT  56.448 19.957 57.048 20.533 ;
     RECT  43.632 20.469 47.256 20.557 ;
     RECT  58.176 20.469 58.2 20.557 ;
     RECT  56.4 20.533 57.048 20.587 ;
     RECT  60.144 20.533 60.168 20.617 ;
     RECT  45.12 20.557 47.256 20.627 ;
     RECT  42.192 20.085 42.504 20.639 ;
     RECT  43.632 20.557 43.848 20.639 ;
     RECT  33.648 20.389 33.672 20.715 ;
     RECT  34.752 20.341 38.232 20.725 ;
     RECT  56.4 20.587 56.952 20.771 ;
     RECT  50.736 19.333 51.552 20.773 ;
     RECT  53.232 19.379 53.256 20.773 ;
     RECT  50.736 20.773 53.256 20.809 ;
     RECT  51.24 20.809 53.256 20.857 ;
     RECT  48.432 20.277 49.56 20.907 ;
     RECT  0.048 20.533 27.24 20.915 ;
     RECT  28.368 19.811 28.488 20.947 ;
     RECT  49.008 20.907 49.56 20.965 ;
     RECT  56.448 20.771 56.952 21.001 ;
     RECT  49.008 20.965 50.136 21.049 ;
     RECT  28.08 20.947 28.488 21.109 ;
     RECT  29.52 20.011 32.616 21.109 ;
     RECT  33.792 20.725 38.232 21.155 ;
     RECT  47.184 20.627 47.256 21.227 ;
     RECT  39.408 19.523 40.968 21.237 ;
     RECT  42.192 20.639 43.848 21.237 ;
     RECT  60.432 20.725 61.032 21.251 ;
     RECT  34.176 21.155 38.232 21.299 ;
     RECT  49.008 21.049 49.992 21.453 ;
     RECT  37.344 21.299 38.232 21.539 ;
     RECT  49.008 21.453 49.032 21.675 ;
     RECT  54.336 21.397 54.36 21.675 ;
     RECT  28.08 21.109 32.616 21.685 ;
     RECT  37.584 21.539 38.232 21.685 ;
     RECT  39.408 21.237 43.848 21.685 ;
     RECT  45.12 20.627 46.152 21.685 ;
     RECT  39.408 21.685 46.152 21.739 ;
     RECT  37.584 21.685 38.424 21.779 ;
     RECT  37.584 21.779 38.184 21.803 ;
     RECT  51.24 20.857 51.552 21.907 ;
     RECT  0.048 20.915 27.048 21.925 ;
     RECT  28.08 21.685 33.096 21.925 ;
     RECT  0.048 21.925 33.096 21.971 ;
     RECT  51.12 21.907 51.552 21.995 ;
     RECT  26.736 21.971 33.096 22.165 ;
     RECT  34.176 21.299 36.36 22.165 ;
     RECT  47.28 21.493 47.352 22.227 ;
     RECT  48.48 22.069 48.504 22.251 ;
     RECT  43.344 21.739 46.152 22.259 ;
     RECT  47.28 22.227 47.448 22.259 ;
     RECT  47.424 22.259 47.448 22.315 ;
     RECT  43.344 22.259 43.848 22.355 ;
     RECT  59.28 22.261 59.304 22.355 ;
     RECT  26.736 22.165 36.36 22.443 ;
     RECT  43.488 22.355 43.848 22.443 ;
     RECT  59.856 22.367 59.88 22.451 ;
     RECT  37.632 21.803 38.184 22.499 ;
     RECT  0.048 21.971 25.464 22.507 ;
     RECT  0.096 22.507 25.464 22.547 ;
     RECT  47.616 22.453 47.928 22.739 ;
     RECT  61.008 21.251 61.032 22.787 ;
     RECT  26.88 22.443 36.36 22.835 ;
     RECT  51.24 21.995 51.552 22.933 ;
     RECT  52.608 20.857 53.256 22.933 ;
     RECT  28.176 22.835 36.36 22.943 ;
     RECT  56.64 21.001 56.952 22.943 ;
     RECT  39.408 21.739 42.36 22.965 ;
     RECT  21.264 22.547 25.464 23.027 ;
     RECT  56.64 22.943 57.624 23.027 ;
     RECT  21.648 23.027 25.464 23.125 ;
     RECT  62.04 19.849 62.352 23.269 ;
     RECT  63.504 22.741 63.528 23.269 ;
     RECT  38.592 22.965 42.36 23.315 ;
     RECT  44.976 22.259 46.152 23.317 ;
     RECT  51.24 22.933 53.256 23.317 ;
     RECT  54.24 23.125 54.264 23.317 ;
     RECT  62.04 23.269 63.528 23.353 ;
     RECT  63.504 23.353 63.528 23.411 ;
     RECT  38.592 23.315 41.64 23.459 ;
     RECT  21.648 23.125 25.896 23.541 ;
     RECT  26.88 22.835 27.048 23.541 ;
     RECT  28.176 22.943 37.032 23.541 ;
     RECT  43.632 22.443 43.848 23.541 ;
     RECT  47.904 22.739 47.928 23.557 ;
     RECT  44.976 23.317 46.392 23.603 ;
     RECT  28.176 23.541 37.176 23.629 ;
     RECT  38.304 23.541 38.328 23.629 ;
     RECT  47.904 23.557 48.6 23.659 ;
     RECT  51.24 23.317 54.264 23.659 ;
     RECT  42.72 23.541 43.848 23.701 ;
     RECT  44.976 23.603 46.152 23.701 ;
     RECT  0.096 22.547 20.184 23.797 ;
     RECT  28.176 23.629 36.456 23.843 ;
     RECT  52.896 23.659 54.264 23.843 ;
     RECT  34.704 23.843 36.456 23.851 ;
     RECT  0.096 23.797 20.568 23.861 ;
     RECT  21.648 23.541 27.048 23.915 ;
     RECT  48.912 23.827 48.936 23.915 ;
     RECT  53.232 23.843 54.264 23.915 ;
     RECT  59.328 23.827 59.352 23.915 ;
     RECT  47.904 23.659 47.928 23.987 ;
     RECT  26.736 23.915 27.048 23.989 ;
     RECT  28.176 23.843 33.624 23.989 ;
     RECT  0.048 23.861 20.568 24.053 ;
     RECT  21.648 23.915 25.704 24.053 ;
     RECT  26.736 23.989 33.624 24.073 ;
     RECT  55.296 24.053 55.32 24.141 ;
     RECT  47.232 24.133 47.256 24.235 ;
     RECT  49.008 24.147 49.032 24.235 ;
     RECT  39.408 23.459 41.64 24.299 ;
     RECT  53.568 23.915 54.264 24.427 ;
     RECT  53.568 24.427 53.592 24.457 ;
     RECT  56.64 23.027 57.576 24.517 ;
     RECT  54.72 24.517 54.744 24.619 ;
     RECT  56.64 24.517 57.624 24.629 ;
     RECT  61.008 24.613 61.032 24.697 ;
     RECT  56.64 24.629 58.344 24.717 ;
     RECT  42.72 23.701 46.152 24.757 ;
     RECT  56.64 24.717 58.152 24.815 ;
     RECT  34.704 23.851 36.264 24.821 ;
     RECT  28.608 24.073 33.624 24.885 ;
     RECT  34.704 24.821 37.176 24.885 ;
     RECT  39.408 24.299 41.064 24.885 ;
     RECT  55.824 24.815 58.152 24.899 ;
     RECT  28.608 24.885 33.672 24.973 ;
     RECT  34.704 24.885 37.272 24.973 ;
     RECT  38.736 24.885 41.064 24.973 ;
     RECT  50.16 24.901 50.184 24.979 ;
     RECT  51.24 23.659 51.552 25.013 ;
     RECT  47.328 24.979 47.352 25.067 ;
     RECT  49.392 24.979 50.184 25.067 ;
     RECT  42.432 24.757 46.152 25.091 ;
     RECT  34.704 24.973 37.176 25.139 ;
     RECT  51.24 25.013 51.864 25.171 ;
     RECT  26.736 24.073 27.624 25.237 ;
     RECT  38.832 24.973 41.064 25.293 ;
     RECT  0.048 24.053 25.704 25.331 ;
     RECT  26.688 25.237 27.624 25.333 ;
     RECT  28.608 24.973 33.624 25.333 ;
     RECT  48.816 25.269 49.08 25.397 ;
     RECT  26.688 25.333 33.624 25.417 ;
     RECT  50.16 25.067 50.184 25.451 ;
     RECT  48.384 25.397 49.08 25.485 ;
     RECT  62.04 23.353 62.352 25.621 ;
     RECT  38.88 25.293 41.064 25.653 ;
     RECT  42.432 25.091 43.848 25.653 ;
     RECT  51.24 25.171 51.96 25.707 ;
     RECT  34.8 25.139 37.176 25.728 ;
     RECT  53.04 25.653 53.064 25.741 ;
     RECT  45.024 25.091 46.152 25.747 ;
     RECT  26.688 25.417 33.192 25.813 ;
     RECT  45.024 25.747 46.968 25.835 ;
     RECT  48.384 25.485 48.84 25.859 ;
     RECT  56.448 24.899 58.152 25.957 ;
     RECT  45.024 25.835 46.728 25.963 ;
     RECT  56.448 25.957 58.248 26.041 ;
     RECT  38.88 25.653 43.848 26.155 ;
     RECT  37.296 26.037 37.32 26.207 ;
     RECT  47.904 26.149 47.928 26.233 ;
     RECT  62.04 25.621 62.856 26.291 ;
     RECT  0.048 25.331 25.416 26.293 ;
     RECT  26.496 25.813 33.192 26.293 ;
     RECT  34.8 25.728 36.312 26.357 ;
     RECT  0.048 26.293 33.192 26.377 ;
     RECT  43.632 26.155 43.848 26.389 ;
     RECT  45.024 25.963 46.152 26.389 ;
     RECT  51.24 25.707 51.864 26.437 ;
     RECT  0.048 26.377 25.224 26.475 ;
     RECT  37.296 26.207 37.608 26.485 ;
     RECT  38.88 26.155 42.648 26.579 ;
     RECT  37.296 26.485 37.656 26.581 ;
     RECT  38.88 26.579 42.504 26.581 ;
     RECT  52.848 26.067 52.872 26.725 ;
     RECT  34.224 26.357 36.312 26.773 ;
     RECT  37.296 26.581 42.504 26.773 ;
     RECT  50.304 26.437 51.864 26.805 ;
     RECT  52.848 26.725 53.016 26.805 ;
     RECT  47.856 26.805 47.88 26.835 ;
     RECT  50.304 26.805 53.016 26.835 ;
     RECT  34.224 26.773 42.504 26.867 ;
     RECT  36.432 26.867 42.504 26.893 ;
     RECT  50.208 26.835 53.016 26.893 ;
     RECT  54.528 25.621 54.552 26.923 ;
     RECT  48.912 26.869 48.936 26.952 ;
     RECT  48.864 26.952 48.936 26.953 ;
     RECT  50.208 26.893 51.912 26.965 ;
     RECT  26.208 26.377 33.192 26.975 ;
     RECT  34.224 26.867 35.448 26.975 ;
     RECT  0.048 26.475 25.176 27.051 ;
     RECT  48.864 26.953 48.888 27.051 ;
     RECT  50.16 26.965 51.912 27.051 ;
     RECT  47.712 26.835 47.88 27.091 ;
     RECT  36.432 26.893 41.688 27.115 ;
     RECT  47.328 27.091 47.88 27.157 ;
     RECT  56.448 26.041 56.952 27.205 ;
     RECT  26.208 26.975 35.448 27.243 ;
     RECT  47.232 27.157 47.88 27.253 ;
     RECT  47.232 27.253 48.792 27.307 ;
     RECT  43.632 26.389 46.152 27.311 ;
     RECT  55.968 27.205 56.952 27.317 ;
     RECT  47.904 27.307 48.792 27.347 ;
     RECT  50.304 27.051 51.912 27.347 ;
     RECT  26.208 27.243 35.352 27.371 ;
     RECT  36.432 27.115 41.64 27.371 ;
     RECT  55.344 27.317 56.952 27.371 ;
     RECT  36.432 27.371 40.968 27.443 ;
     RECT  0.096 27.051 25.176 27.445 ;
     RECT  26.208 27.371 33.768 27.445 ;
     RECT  55.344 27.371 55.368 27.635 ;
     RECT  61.008 27.551 61.032 27.635 ;
     RECT  43.632 27.311 46.248 27.637 ;
     RECT  0.096 27.445 33.768 27.755 ;
     RECT  62.04 26.291 62.352 27.781 ;
     RECT  60.144 27.795 60.168 27.883 ;
     RECT  0.096 27.755 33.72 27.913 ;
     RECT  51.24 27.347 51.912 27.913 ;
     RECT  36.432 27.443 39.432 27.923 ;
     RECT  54.096 27.301 54.168 27.923 ;
     RECT  0.096 27.913 33.48 27.971 ;
     RECT  52.992 26.893 53.016 28.165 ;
     RECT  43.488 27.637 46.248 28.261 ;
     RECT  52.608 28.165 53.016 28.261 ;
     RECT  62.04 27.781 62.52 28.371 ;
     RECT  40.44 27.443 40.968 28.405 ;
     RECT  42.768 28.261 46.248 28.405 ;
     RECT  56.64 27.371 56.952 28.405 ;
     RECT  51.24 27.913 51.552 28.453 ;
     RECT  58.752 28.261 58.776 28.459 ;
     RECT  61.488 28.371 62.52 28.459 ;
     RECT  42.768 28.405 47.352 28.489 ;
     RECT  56.448 28.405 56.952 28.499 ;
     RECT  37.104 27.923 39.432 28.547 ;
     RECT  48.768 27.347 48.792 28.645 ;
     RECT  42.768 28.489 46.248 28.789 ;
     RECT  56.64 28.499 56.952 28.789 ;
     RECT  52.608 28.261 53.208 28.883 ;
     RECT  38.448 28.547 39.432 28.933 ;
     RECT  40.44 28.405 41.016 28.933 ;
     RECT  42.096 28.789 46.248 28.933 ;
     RECT  0.096 27.971 27.144 28.981 ;
     RECT  47.232 28.489 47.352 28.981 ;
     RECT  48.768 28.645 48.984 28.981 ;
     RECT  34.848 27.371 35.352 29.029 ;
     RECT  0.048 28.981 27.144 29.035 ;
     RECT  34.848 29.029 36.12 29.039 ;
     RECT  37.104 28.547 37.464 29.039 ;
     RECT  0.048 29.035 27.048 29.059 ;
     RECT  47.232 28.981 49.56 29.065 ;
     RECT  52.944 28.883 53.208 29.075 ;
     RECT  53.184 29.075 53.208 29.099 ;
     RECT  56.64 28.789 57.624 29.099 ;
     RECT  34.848 29.039 37.464 29.163 ;
     RECT  56.64 29.099 57.048 29.267 ;
     RECT  47.232 29.065 49.176 29.291 ;
     RECT  28.416 27.971 33.48 29.317 ;
     RECT  28.128 29.317 33.48 29.365 ;
     RECT  34.848 29.163 37.08 29.365 ;
     RECT  50.832 28.453 51.552 29.411 ;
     RECT  51.024 29.411 51.552 29.419 ;
     RECT  53.952 29.365 53.976 29.459 ;
     RECT  62.04 28.459 62.52 29.471 ;
     RECT  38.448 28.933 46.248 29.523 ;
     RECT  47.232 29.291 47.496 29.523 ;
     RECT  61.584 29.471 62.52 29.555 ;
     RECT  38.448 29.523 47.496 29.611 ;
     RECT  47.472 29.611 47.496 29.641 ;
     RECT  55.584 29.557 55.608 29.641 ;
     RECT  62.04 29.555 62.52 29.699 ;
     RECT  60.096 29.621 60.12 29.939 ;
     RECT  38.448 29.611 46.248 30.037 ;
     RECT  0.048 29.059 27 30.047 ;
     RECT  28.128 29.365 37.08 30.047 ;
     RECT  54 29.971 54.024 30.059 ;
     RECT  51.12 29.419 51.552 30.133 ;
     RECT  38.208 30.037 46.248 30.179 ;
     RECT  51.12 30.133 51.72 30.181 ;
     RECT  58.896 29.605 58.92 30.323 ;
     RECT  48.48 29.291 49.176 30.383 ;
     RECT  47.856 30.383 49.176 30.389 ;
     RECT  47.856 30.389 49.608 30.483 ;
     RECT  51.12 30.181 51.864 30.483 ;
     RECT  58.368 30.453 58.392 30.563 ;
     RECT  47.856 30.483 51.864 30.803 ;
     RECT  0.048 30.047 37.08 30.805 ;
     RECT  38.208 30.179 46.152 30.805 ;
     RECT  47.856 30.803 51.72 30.867 ;
     RECT  0.048 30.805 46.152 30.955 ;
     RECT  55.536 31.029 55.56 31.117 ;
     RECT  47.76 30.867 51.72 31.177 ;
     RECT  0.048 30.955 41.304 31.309 ;
     RECT  47.76 31.177 49.32 31.349 ;
     RECT  0.048 31.309 37.08 31.379 ;
     RECT  53.232 31.343 53.256 31.427 ;
     RECT  58.656 31.333 58.68 31.467 ;
     RECT  59.856 31.381 59.88 31.467 ;
     RECT  63.84 31.477 63.864 31.571 ;
     RECT  42.624 30.955 46.152 31.915 ;
     RECT  38.16 31.309 41.304 31.919 ;
     RECT  43.584 31.915 46.152 31.919 ;
     RECT  47.616 31.349 49.32 31.919 ;
     RECT  50.496 31.177 51.72 32.275 ;
     RECT  50.448 32.275 51.72 32.363 ;
     RECT  38.16 31.919 42.504 32.373 ;
     RECT  52.848 32.245 52.872 32.437 ;
     RECT  43.584 31.919 49.32 32.461 ;
     RECT  51.12 32.363 51.72 32.495 ;
     RECT  51.12 32.495 51.768 32.501 ;
     RECT  52.848 32.437 53.112 32.555 ;
     RECT  0.048 31.379 36.936 32.629 ;
     RECT  0.048 32.629 37.128 32.735 ;
     RECT  38.112 32.373 42.504 32.735 ;
     RECT  52.848 32.555 53.064 32.811 ;
     RECT  51.12 32.501 51.864 32.821 ;
     RECT  56.64 29.267 56.952 32.917 ;
     RECT  60.096 32.851 60.12 32.965 ;
     RECT  0.048 32.735 42.504 32.979 ;
     RECT  43.584 32.461 47.016 32.979 ;
     RECT  56.64 32.917 57.624 32.979 ;
     RECT  48.144 32.461 49.32 33.013 ;
     RECT  0.048 32.979 47.016 33.059 ;
     RECT  0.048 33.059 46.872 33.067 ;
     RECT  60.096 32.965 60.168 33.067 ;
     RECT  37.008 33.067 42.552 33.097 ;
     RECT  54.144 33.013 54.168 33.097 ;
     RECT  37.008 33.097 42.408 33.107 ;
     RECT  48.144 33.013 49.896 33.145 ;
     RECT  0.048 33.067 36.024 33.165 ;
     RECT  51.12 32.821 52.776 33.195 ;
     RECT  0.048 33.165 35.928 33.203 ;
     RECT  37.008 33.107 42.312 33.323 ;
     RECT  38.448 33.323 42.312 33.347 ;
     RECT  56.64 32.979 57.672 33.397 ;
     RECT  38.736 33.347 42.312 33.587 ;
     RECT  51.12 33.195 52.632 33.781 ;
     RECT  48.384 33.145 49.896 33.829 ;
     RECT  38.736 33.587 42.024 33.835 ;
     RECT  43.632 33.067 46.872 33.913 ;
     RECT  61.008 33.839 61.032 33.923 ;
     RECT  51.072 33.781 52.632 34.067 ;
     RECT  59.28 33.839 59.544 34.067 ;
     RECT  43.632 33.913 46.488 34.213 ;
     RECT  37.008 33.323 37.128 34.323 ;
     RECT  0.048 33.203 35.736 34.357 ;
     RECT  37.008 34.323 37.32 34.357 ;
     RECT  43.584 34.213 46.488 34.357 ;
     RECT  56.64 33.397 57.72 34.403 ;
     RECT  59.28 34.067 59.304 34.411 ;
     RECT  38.736 33.835 41.88 34.501 ;
     RECT  0.048 34.357 37.32 34.597 ;
     RECT  38.544 34.501 41.88 34.597 ;
     RECT  48.384 33.829 50.088 34.707 ;
     RECT  56.64 34.403 56.952 34.741 ;
     RECT  48 34.707 50.088 34.869 ;
     RECT  51.072 34.067 51.864 34.869 ;
     RECT  53.568 34.847 53.592 34.931 ;
     RECT  0.048 34.597 41.88 34.933 ;
     RECT  43.344 34.357 46.488 34.933 ;
     RECT  0.048 34.933 46.488 35.123 ;
     RECT  48 34.869 51.864 35.221 ;
     RECT  0.048 35.123 42.216 35.363 ;
     RECT  56.208 34.741 56.952 35.363 ;
     RECT  47.904 35.221 51.864 35.539 ;
     RECT  54 35.445 54.504 35.563 ;
     RECT  47.904 35.539 52.104 35.627 ;
     RECT  56.64 35.363 56.952 35.637 ;
     RECT  43.2 35.123 46.488 35.667 ;
     RECT  56.64 35.637 57.624 35.765 ;
     RECT  43.2 35.667 46.68 35.797 ;
     RECT  47.904 35.627 51.864 35.797 ;
     RECT  56.64 35.765 57.672 35.853 ;
     RECT  59.856 36.325 59.88 36.409 ;
     RECT  0.048 35.363 42.024 36.469 ;
     RECT  43.2 35.797 51.864 36.469 ;
     RECT  0.048 36.469 51.864 36.515 ;
     RECT  54.144 35.563 54.504 36.575 ;
     RECT  55.536 36.469 55.56 36.575 ;
     RECT  54.144 36.575 55.56 36.576 ;
     RECT  54.72 36.576 55.56 36.659 ;
     RECT  55.2 36.659 55.56 36.715 ;
     RECT  55.536 36.715 55.56 36.803 ;
     RECT  52.992 37.045 53.016 37.129 ;
     RECT  0.048 36.515 50.232 37.163 ;
     RECT  62.04 29.699 62.352 37.459 ;
     RECT  62.04 37.459 63.048 37.547 ;
     RECT  0.096 37.163 50.184 37.763 ;
     RECT  51.24 36.515 51.864 37.813 ;
     RECT  51.24 37.813 51.96 37.91 ;
     RECT  51.24 37.91 51.912 37.995 ;
     RECT  47.328 37.763 50.184 38.099 ;
     RECT  47.52 38.099 50.184 38.149 ;
     RECT  51.24 37.995 51.864 38.149 ;
     RECT  54.528 38.111 54.552 38.149 ;
     RECT  57.936 38.069 57.96 38.157 ;
     RECT  54.528 38.149 55.272 38.195 ;
     RECT  56.64 35.853 56.952 38.197 ;
     RECT  62.04 37.547 62.352 38.389 ;
     RECT  47.52 38.149 51.864 38.435 ;
     RECT  59.808 38.355 59.832 38.443 ;
     RECT  53.04 38.149 53.064 38.453 ;
     RECT  61.584 38.389 62.352 38.473 ;
     RECT  48.912 38.435 51.864 38.483 ;
     RECT  47.52 38.435 47.88 38.579 ;
     RECT  53.04 38.453 53.112 38.645 ;
     RECT  48.912 38.483 50.136 38.699 ;
     RECT  55.008 38.195 55.272 38.723 ;
     RECT  52.896 38.645 53.112 38.773 ;
     RECT  55.104 38.723 55.272 38.819 ;
     RECT  47.52 38.579 47.832 38.867 ;
     RECT  0.096 37.763 46.344 39.157 ;
     RECT  47.52 38.867 47.544 39.157 ;
     RECT  55.104 38.819 55.128 39.275 ;
     RECT  56.64 38.197 57.72 39.275 ;
     RECT  59.568 39.109 59.592 39.275 ;
     RECT  56.64 39.275 57.528 39.347 ;
     RECT  61.008 39.157 61.032 39.395 ;
     RECT  52.896 38.773 53.208 39.637 ;
     RECT  49.152 38.699 50.136 39.733 ;
     RECT  51.12 38.483 51.864 39.733 ;
     RECT  59.712 39.637 59.736 39.787 ;
     RECT  56.64 39.347 57.432 39.829 ;
     RECT  56.304 39.829 57.432 39.915 ;
     RECT  0.096 39.157 47.544 39.925 ;
     RECT  49.152 39.733 51.864 39.925 ;
     RECT  56.64 39.915 57.432 39.949 ;
     RECT  54.528 39.925 54.552 40.019 ;
     RECT  52.896 39.637 53.544 40.053 ;
     RECT  52.848 40.053 53.544 40.147 ;
     RECT  52.848 40.147 54.264 40.235 ;
     RECT  0.096 39.925 51.864 40.245 ;
     RECT  0.048 40.245 51.864 40.259 ;
     RECT  60.336 40.531 60.36 40.619 ;
     RECT  62.04 38.473 62.352 40.693 ;
     RECT  50.544 40.259 51.864 40.741 ;
     RECT  53.616 40.235 54.216 40.845 ;
     RECT  50.544 40.741 52.536 41.003 ;
     RECT  0.048 40.259 49.416 41.221 ;
     RECT  51.24 41.003 52.536 41.269 ;
     RECT  51.24 41.269 52.968 41.363 ;
     RECT  56.64 39.949 56.952 41.509 ;
     RECT  51.24 41.363 52.92 41.515 ;
     RECT  53.952 40.845 54.216 41.557 ;
     RECT  58.128 41.413 58.152 41.749 ;
     RECT  55.872 41.509 56.952 41.891 ;
     RECT  61.92 40.693 62.352 41.893 ;
     RECT  53.952 41.557 54.744 41.939 ;
     RECT  61.92 41.893 62.76 41.987 ;
     RECT  0.048 41.221 49.656 42.003 ;
     RECT  56.64 41.891 56.952 42.095 ;
     RECT  56.64 42.095 57.048 42.143 ;
     RECT  58.128 41.749 58.44 42.143 ;
     RECT  60.384 40.981 60.408 42.179 ;
     RECT  54.576 41.939 54.744 42.195 ;
     RECT  56.64 42.143 58.44 42.227 ;
     RECT  54.576 42.195 55.656 42.283 ;
     RECT  59.856 42.335 60.072 42.419 ;
     RECT  0.048 42.003 50.04 42.485 ;
     RECT  51.24 41.515 52.824 42.485 ;
     RECT  62.04 41.987 62.76 42.517 ;
     RECT  58.272 42.227 58.44 42.573 ;
     RECT  62.04 42.517 62.808 42.659 ;
     RECT  54.576 42.283 55.56 42.707 ;
     RECT  0.048 42.485 52.824 42.741 ;
     RECT  62.04 42.659 62.76 42.755 ;
     RECT  60.048 42.419 60.072 42.923 ;
     RECT  56.64 42.227 57.144 43.295 ;
     RECT  54.624 42.707 55.56 43.597 ;
     RECT  56.64 43.295 57.624 43.603 ;
     RECT  58.656 42.709 58.728 43.603 ;
     RECT  56.64 43.603 58.728 43.691 ;
     RECT  62.04 42.755 62.352 43.731 ;
     RECT  0.048 42.741 52.92 43.765 ;
     RECT  56.64 43.691 57.624 43.955 ;
     RECT  0.048 43.765 53.112 44.051 ;
     RECT  50.304 44.051 53.112 44.147 ;
     RECT  59.904 44.021 59.928 44.147 ;
     RECT  58.704 43.691 58.728 44.437 ;
     RECT  61.584 43.731 62.352 44.447 ;
     RECT  54.624 43.597 54.984 44.483 ;
     RECT  58.704 44.437 59.832 44.483 ;
     RECT  61.584 44.447 63.048 44.531 ;
     RECT  50.688 44.147 53.112 44.563 ;
     RECT  56.64 43.955 56.952 44.597 ;
     RECT  59.568 44.483 59.832 44.651 ;
     RECT  59.808 44.651 59.832 44.675 ;
     RECT  55.296 44.597 55.32 44.867 ;
     RECT  56.544 44.597 56.952 45.139 ;
     RECT  61.584 44.531 62.352 45.155 ;
     RECT  0.048 44.051 49.08 45.167 ;
     RECT  50.688 44.563 53.688 45.167 ;
     RECT  56.544 45.139 57.048 45.227 ;
     RECT  58.512 45.253 58.536 45.355 ;
     RECT  0.048 45.167 53.688 45.541 ;
     RECT  56.544 45.227 56.952 45.547 ;
     RECT  0.048 45.541 54.168 45.625 ;
     RECT  53.904 45.625 54.168 45.715 ;
     RECT  59.664 45.715 59.688 45.803 ;
     RECT  61.92 45.155 62.352 45.827 ;
     RECT  58.128 45.599 58.296 45.867 ;
     RECT  53.904 45.715 54.792 46.197 ;
     RECT  53.904 46.197 55.416 46.251 ;
     RECT  59.28 46.117 59.304 46.251 ;
     RECT  57.984 46.035 58.056 46.285 ;
     RECT  56.64 45.547 56.952 46.549 ;
     RECT  55.392 46.251 55.416 46.751 ;
     RECT  56.64 46.549 57.096 46.751 ;
     RECT  53.904 46.251 53.976 46.787 ;
     RECT  0.048 45.625 52.68 46.837 ;
     RECT  62.04 45.827 62.352 46.885 ;
     RECT  0.048 46.837 53.64 46.931 ;
     RECT  58.8 46.885 58.824 47.083 ;
     RECT  61.44 46.885 62.352 47.221 ;
     RECT  61.44 47.221 62.76 47.315 ;
     RECT  55.392 46.751 57.096 47.317 ;
     RECT  60.384 47.279 60.408 47.363 ;
     RECT  61.44 47.315 62.352 47.459 ;
     RECT  55.344 47.317 57.096 47.605 ;
     RECT  58.128 47.413 58.2 47.605 ;
     RECT  55.344 47.605 58.2 47.699 ;
     RECT  55.344 47.699 56.952 47.711 ;
     RECT  0.048 46.931 52.152 47.737 ;
     RECT  55.296 47.711 56.952 47.757 ;
     RECT  55.296 47.757 55.368 47.795 ;
     RECT  58.128 47.699 58.2 47.891 ;
     RECT  59.28 47.797 59.304 47.891 ;
     RECT  53.616 46.931 53.64 48.117 ;
     RECT  49.008 47.737 52.152 48.265 ;
     RECT  49.296 48.265 52.152 48.339 ;
     RECT  49.296 48.339 52.344 48.373 ;
     RECT  53.376 48.117 53.64 48.373 ;
     RECT  49.296 48.373 54.168 48.427 ;
     RECT  53.04 48.427 54.168 48.467 ;
     RECT  53.088 48.467 54.168 48.515 ;
     RECT  61.008 47.701 61.032 48.811 ;
     RECT  56.448 47.757 56.952 48.853 ;
     RECT  58.128 47.891 58.152 48.885 ;
     RECT  58.032 48.885 58.152 48.973 ;
     RECT  56.448 48.853 57.048 48.995 ;
     RECT  59.616 48.757 59.64 48.995 ;
     RECT  56.64 48.995 57.048 48.997 ;
     RECT  55.344 47.795 55.368 49.013 ;
     RECT  53.088 48.515 53.592 49.067 ;
     RECT  58.128 48.973 58.152 49.101 ;
     RECT  54.72 49.013 55.368 49.139 ;
     RECT  56.64 48.997 57.144 49.139 ;
     RECT  53.088 49.067 53.544 49.259 ;
     RECT  60.24 49.237 60.264 49.323 ;
     RECT  49.296 48.427 51.96 49.429 ;
     RECT  62.04 47.459 62.352 49.429 ;
     RECT  53.088 49.259 53.352 49.515 ;
     RECT  62.04 49.429 62.472 49.515 ;
     RECT  0.048 47.737 48.024 49.525 ;
     RECT  49.2 49.429 51.96 49.525 ;
     RECT  55.008 49.139 55.368 50.051 ;
     RECT  55.008 50.051 55.32 50.091 ;
     RECT  59.28 50.015 59.304 50.099 ;
     RECT  56.64 49.139 56.952 50.149 ;
     RECT  56.64 50.149 57.624 50.293 ;
     RECT  56.64 50.293 57.672 50.549 ;
     RECT  60.096 50.389 60.12 50.603 ;
     RECT  0.048 49.525 52.776 50.613 ;
     RECT  0.048 50.613 52.872 50.723 ;
     RECT  56.64 50.549 58.104 50.731 ;
     RECT  62.04 49.515 62.352 50.735 ;
     RECT  60.432 50.629 60.552 50.761 ;
     RECT  0.048 50.723 52.776 50.795 ;
     RECT  60.528 50.761 60.552 50.795 ;
     RECT  61.584 50.735 62.352 50.819 ;
     RECT  56.64 50.731 57.672 50.829 ;
     RECT  55.008 50.091 55.032 50.869 ;
     RECT  62.04 50.819 62.352 50.917 ;
     RECT  56.64 50.829 56.952 51.061 ;
     RECT  54.24 50.869 55.032 51.288 ;
     RECT  56.544 51.061 56.952 51.288 ;
     RECT  62.04 50.917 62.472 51.307 ;
     RECT  54.24 51.288 56.952 51.359 ;
     RECT  0.048 50.795 52.536 51.395 ;
     RECT  54.144 51.359 56.952 51.443 ;
     RECT  0.048 51.395 52.44 51.635 ;
     RECT  59.232 51.637 59.256 51.731 ;
     RECT  54.624 51.443 56.952 51.755 ;
     RECT  55.296 51.755 56.952 51.923 ;
     RECT  60.192 51.893 60.216 51.981 ;
     RECT  56.064 51.923 56.952 52.267 ;
     RECT  56.352 52.267 56.952 52.501 ;
     RECT  62.04 51.307 62.352 52.563 ;
     RECT  56.352 52.501 57.624 52.655 ;
     RECT  61.728 52.563 62.352 52.725 ;
     RECT  56.352 52.655 58.152 52.739 ;
     RECT  61.008 52.725 62.352 52.813 ;
     RECT  56.352 52.739 57.96 52.843 ;
     RECT  0.048 51.635 52.392 52.947 ;
     RECT  53.424 52.469 53.448 52.947 ;
     RECT  0.048 52.947 53.448 52.968 ;
     RECT  61.776 52.813 62.352 53.029 ;
     RECT  0.048 52.968 53.592 53.075 ;
     RECT  61.776 53.029 62.856 53.163 ;
     RECT  59.472 53.221 59.496 53.237 ;
     RECT  59.28 53.237 59.496 53.365 ;
     RECT  55.008 52.981 55.032 53.471 ;
     RECT  56.352 52.843 57.72 53.471 ;
     RECT  59.28 53.365 59.784 53.493 ;
     RECT  59.28 53.493 60.264 53.581 ;
     RECT  59.28 53.581 59.832 53.795 ;
     RECT  61.776 53.163 62.352 53.877 ;
     RECT  59.472 53.795 59.832 53.939 ;
     RECT  55.008 53.471 57.72 53.941 ;
     RECT  54.816 53.941 57.72 54.085 ;
     RECT  61.248 53.877 62.352 54.157 ;
     RECT  0.048 53.075 53.112 54.261 ;
     RECT  59.472 53.939 59.496 54.371 ;
     RECT  0.048 54.261 53.16 54.383 ;
     RECT  0.048 54.383 53.592 54.467 ;
     RECT  0.048 54.467 53.064 54.541 ;
     RECT  54.816 54.085 58.008 54.581 ;
     RECT  60.672 54.581 60.696 54.669 ;
     RECT  0.048 54.541 52.68 54.699 ;
     RECT  54.144 54.581 58.008 54.755 ;
     RECT  56.64 54.755 58.008 54.837 ;
     RECT  62.04 54.157 62.352 54.931 ;
     RECT  62.04 54.931 62.472 55.237 ;
     RECT  56.64 54.837 58.824 55.381 ;
     RECT  60.528 55.381 60.552 55.391 ;
     RECT  54.144 54.755 55.656 55.467 ;
     RECT  60.432 55.391 60.552 55.467 ;
     RECT  60.432 55.467 60.456 55.475 ;
     RECT  0.048 54.699 52.248 55.501 ;
     RECT  54.432 55.467 55.656 55.523 ;
     RECT  62.04 55.237 63.288 55.907 ;
     RECT  62.04 55.907 62.352 55.925 ;
     RECT  56.64 55.381 59.304 56.149 ;
     RECT  56.4 56.149 59.304 56.435 ;
     RECT  0.048 55.501 51.912 56.501 ;
     RECT  0.048 56.501 52.344 56.725 ;
     RECT  56.448 56.435 59.304 56.757 ;
     RECT  61.632 55.925 62.352 56.757 ;
     RECT  54.432 55.523 55.272 56.821 ;
     RECT  61.152 56.757 62.352 56.845 ;
     RECT  56.448 56.757 59.688 57.013 ;
     RECT  62.04 56.845 62.352 57.013 ;
     RECT  56.448 57.013 59.88 57.097 ;
     RECT  62.04 57.013 62.712 57.107 ;
     RECT  0.048 56.725 52.968 57.541 ;
     RECT  54.048 56.821 55.272 57.541 ;
     RECT  56.448 57.097 57.72 57.541 ;
     RECT  59.568 57.097 59.88 57.653 ;
     RECT  0.048 57.541 57.72 57.707 ;
     RECT  0.048 57.707 57.048 57.865 ;
     RECT  59.568 57.653 60.456 57.963 ;
     RECT  0.048 57.865 56.952 58.027 ;
     RECT  52.944 58.027 56.952 58.067 ;
     RECT  59.568 57.963 59.88 58.069 ;
     RECT  59.232 58.069 59.88 58.091 ;
     RECT  59.232 58.091 59.688 58.125 ;
     RECT  54.144 58.067 56.952 58.155 ;
     RECT  63.6 57.445 63.624 58.163 ;
     RECT  58.128 58.261 58.152 58.347 ;
     RECT  54.144 58.155 54.168 58.667 ;
     RECT  59.232 58.125 59.592 58.739 ;
     RECT  62.04 57.107 62.352 58.741 ;
     RECT  59.376 58.739 59.592 58.979 ;
     RECT  55.344 58.155 56.952 59.027 ;
     RECT  61.344 58.741 62.352 59.029 ;
     RECT  0.048 58.027 51.912 59.125 ;
     RECT  52.944 58.067 53.16 59.125 ;
     RECT  61.344 59.029 62.76 59.125 ;
     RECT  61.344 59.125 62.856 59.253 ;
     RECT  59.808 59.231 59.832 59.315 ;
     RECT  61.248 59.253 62.856 59.341 ;
     RECT  58.128 59.475 58.152 59.563 ;
     RECT  0.048 59.125 53.16 59.653 ;
     RECT  0.048 59.653 53.592 59.667 ;
     RECT  61.92 59.341 62.856 59.797 ;
     RECT  0.048 59.667 54.264 60.133 ;
     RECT  55.536 59.027 56.952 60.133 ;
     RECT  0.048 60.133 56.952 60.419 ;
     RECT  58.224 60.277 58.248 60.419 ;
     RECT  61.92 59.797 63.048 60.803 ;
     RECT  54.288 60.419 56.952 60.853 ;
     RECT  60.384 60.133 60.408 60.853 ;
     RECT  61.92 60.803 62.352 60.853 ;
     RECT  60.384 60.853 62.352 60.937 ;
     RECT  0.048 60.419 52.824 61.043 ;
     RECT  54.288 60.853 57.624 61.139 ;
     RECT  55.536 61.139 57.624 61.381 ;
     RECT  60.144 61.189 60.168 61.395 ;
     RECT  0.096 61.043 52.824 61.419 ;
     RECT  55.536 61.381 58.152 61.483 ;
     RECT  59.184 61.395 60.168 61.483 ;
     RECT  55.824 61.483 58.152 61.749 ;
     RECT  52.896 61.429 54.168 61.955 ;
     RECT  52.896 61.955 53.064 61.995 ;
     RECT  61.392 60.937 62.352 62.005 ;
     RECT  59.712 61.483 60.168 62.059 ;
     RECT  55.824 61.749 58.68 62.195 ;
     RECT  61.344 62.005 62.352 62.195 ;
     RECT  62.04 62.195 62.352 62.197 ;
     RECT  59.76 62.059 60.168 62.221 ;
     RECT  59.76 62.221 59.784 62.251 ;
     RECT  52.896 61.995 52.968 62.435 ;
     RECT  52.896 62.435 52.92 62.579 ;
     RECT  55.824 62.195 57.048 62.709 ;
     RECT  58.416 62.195 58.68 62.723 ;
     RECT  54.144 61.955 54.168 62.771 ;
     RECT  55.68 62.709 57.048 62.797 ;
     RECT  58.416 62.723 58.44 62.797 ;
     RECT  0.096 61.419 51.912 62.963 ;
     RECT  50.736 62.963 51.912 62.965 ;
     RECT  54.72 63.061 54.744 63.147 ;
     RECT  50.736 62.965 52.824 63.155 ;
     RECT  55.872 62.797 57.048 63.155 ;
     RECT  62.04 62.197 62.856 63.299 ;
     RECT  0.096 62.963 49.656 63.443 ;
     RECT  6.672 63.443 49.656 63.491 ;
     RECT  6.672 63.491 12.024 63.539 ;
     RECT  50.736 63.155 52.488 63.539 ;
     RECT  4.512 63.443 5.688 63.625 ;
     RECT  6.672 63.539 11.4 63.625 ;
     RECT  0.096 63.443 3.432 63.635 ;
     RECT  13.008 63.491 49.656 63.635 ;
     RECT  50.736 63.539 51.552 63.635 ;
     RECT  6.672 63.625 10.44 63.659 ;
     RECT  48.288 63.635 49.656 63.659 ;
     RECT  48.624 63.659 49.656 63.683 ;
     RECT  1.008 63.635 2.952 63.723 ;
     RECT  6.672 63.659 9.096 63.723 ;
     RECT  13.008 63.635 46.872 63.731 ;
     RECT  2.64 63.723 2.952 63.743 ;
     RECT  8.04 63.723 9.096 63.743 ;
     RECT  51.24 63.635 51.552 63.743 ;
     RECT  62.04 63.299 62.352 63.743 ;
     RECT  5.184 63.625 5.688 63.757 ;
     RECT  1.008 63.723 1.08 63.787 ;
     RECT  10.32 63.659 10.44 63.787 ;
     RECT  48.624 63.683 49.512 63.787 ;
     RECT  13.008 63.731 46.824 63.827 ;
     RECT  1.008 63.787 1.032 63.851 ;
     RECT  48.624 63.787 49.032 63.851 ;
     RECT  6.672 63.723 6.84 63.865 ;
     RECT  55.872 63.155 56.952 63.865 ;
     RECT  13.008 63.827 13.752 63.923 ;
     RECT  6.672 63.865 6.696 63.979 ;
     RECT  13.152 63.923 13.752 63.979 ;
     RECT  2.832 63.743 2.952 64.013 ;
     RECT  8.232 63.743 9.096 64.013 ;
     RECT  13.632 63.979 13.752 64.013 ;
     RECT  51.432 63.743 51.552 64.013 ;
     RECT  56.832 63.865 56.952 64.013 ;
     RECT  62.232 63.743 62.352 64.013 ;
     RECT  5.664 63.757 5.688 64.107 ;
     RECT  15.408 63.827 46.824 64.107 ;
     RECT  9.072 64.013 9.096 64.171 ;
     RECT  15.408 64.107 45 64.363 ;
     RECT  17.184 64.363 45 64.451 ;
     RECT  17.184 64.451 44.952 64.555 ;
     RECT  17.52 64.555 44.952 64.595 ;
     RECT  17.52 64.595 17.544 64.619 ;
     RECT  18.624 64.595 44.952 64.619 ;
     RECT  46.224 64.107 46.824 64.619 ;
     RECT  18.624 64.619 44.808 64.683 ;
     RECT  19.44 64.683 44.808 64.72 ;
     RECT  15.408 64.363 15.432 64.739 ;
     RECT  19.44 64.72 19.464 64.747 ;
     RECT  20.448 64.72 20.472 64.747 ;
     RECT  22.848 64.72 22.872 64.747 ;
     RECT  25.776 64.72 25.8 64.747 ;
     RECT  31.92 64.72 31.944 64.747 ;
     RECT  40.848 64.72 40.872 64.747 ;
     RECT  44.592 64.72 44.616 64.747 ;
     RECT  46.8 64.619 46.824 64.747 ;
    LAYER M6 ;
     RECT  0 22.596 0.037 23.46 ;
     RECT  0 27.996 0.037 28.86 ;
     RECT  0 33.396 0.037 34.26 ;
     RECT  0 38.796 0.037 39.66 ;
     RECT  0 44.196 0.037 45.06 ;
     RECT  0.037 4.544 0.053 4.576 ;
     RECT  0 11.796 0.053 12.66 ;
     RECT  0.037 22.464 0.053 23.904 ;
     RECT  0.037 27.008 0.053 29.024 ;
     RECT  0.037 31.808 0.053 32.096 ;
     RECT  0.037 33.396 0.053 35.552 ;
     RECT  0.037 37.12 0.053 37.152 ;
     RECT  0.037 38.796 0.053 40.8 ;
     RECT  0.037 42.56 0.053 42.848 ;
     RECT  0.037 44.196 0.053 45.28 ;
     RECT  0.037 52.352 0.053 52.384 ;
     RECT  0 54.996 0.053 55.86 ;
     RECT  0 17.196 0.085 18.06 ;
     RECT  0.053 22.016 0.085 24.032 ;
     RECT  0.053 25.6 0.085 30.304 ;
     RECT  0.053 31.808 0.085 37.472 ;
     RECT  0.053 38.796 0.085 45.28 ;
     RECT  0 49.596 0.085 50.46 ;
     RECT  0.053 52.352 0.085 53.28 ;
     RECT  0 60.396 0.085 61.26 ;
     RECT  0.053 3.84 0.11 4.576 ;
     RECT  0.053 14.784 0.11 14.816 ;
     RECT  0.085 20.224 0.117 20.256 ;
     RECT  0.085 22.016 0.117 45.28 ;
     RECT  0.085 49.596 0.117 53.28 ;
     RECT  0.053 54.72 0.117 56.992 ;
     RECT  0 0.996 0.133 1.86 ;
     RECT  0 6.396 0.133 7.26 ;
     RECT  0.053 11.796 0.133 13.216 ;
     RECT  0.11 14.656 0.133 14.816 ;
     RECT  0.117 20.224 0.133 20.64 ;
     RECT  0.117 22.016 0.133 46.752 ;
     RECT  0.117 48.192 0.133 57.888 ;
     RECT  0.133 0.576 0.181 1.86 ;
     RECT  0.133 20.224 0.181 20.704 ;
     RECT  0.133 22.016 0.181 57.888 ;
     RECT  0.085 59.712 0.181 61.26 ;
     RECT  0.053 63.296 0.181 63.328 ;
     RECT  0.133 6.396 0.229 7.52 ;
     RECT  0.133 10.304 0.229 14.816 ;
     RECT  0.085 16.448 0.229 18.06 ;
     RECT  0.181 20.224 0.229 57.888 ;
     RECT  0.11 3.84 0.245 4.704 ;
     RECT  0.229 6.396 0.245 8.8 ;
     RECT  0.229 20.224 0.245 58.08 ;
     RECT  0.229 10.304 0.277 18.06 ;
     RECT  0.245 19.968 0.277 58.08 ;
     RECT  0.181 0.576 0.309 2.016 ;
     RECT  0.277 10.304 0.309 58.08 ;
     RECT  0.245 3.84 0.325 8.8 ;
     RECT  0.309 10.304 0.325 58.208 ;
     RECT  0.181 59.712 0.325 63.328 ;
     RECT  0.309 0.576 0.373 2.272 ;
     RECT  0.325 3.84 0.373 63.328 ;
     RECT  0.373 0.576 0.469 63.328 ;
     RECT  0.469 0.576 0.757 63.392 ;
     RECT  0.757 0.576 0.997 63.456 ;
     RECT  0.997 0.576 1.093 63.84 ;
     RECT  1.093 0.384 3.509 63.84 ;
     RECT  3.509 0.384 4.501 64.352 ;
     RECT  4.501 0.32 5.077 64.352 ;
     RECT  5.077 0.256 10.997 64.352 ;
     RECT  10.997 0.256 12.789 64.48 ;
     RECT  12.789 0.256 15.275 64.608 ;
     RECT  15.275 0.32 15.467 64.608 ;
     RECT  15.467 0.384 15.541 64.608 ;
     RECT  15.541 0.384 21.355 64.736 ;
     RECT  21.355 0.448 21.483 64.736 ;
     RECT  21.483 0.448 22.837 64.608 ;
     RECT  22.837 0.448 25.707 64.736 ;
     RECT  25.707 0.512 25.811 64.736 ;
     RECT  25.811 0.512 27.125 64.672 ;
     RECT  27.125 0.512 27.971 64.736 ;
     RECT  27.971 0.64 29.227 64.736 ;
     RECT  29.227 0.64 30.275 64.608 ;
     RECT  30.275 0.832 31.413 64.608 ;
     RECT  31.413 0.832 31.955 64.736 ;
     RECT  31.955 0.832 32.053 64.48 ;
     RECT  32.053 0.192 32.747 64.48 ;
     RECT  32.747 0.832 33.107 64.48 ;
     RECT  33.107 0.832 34.933 18.976 ;
     RECT  33.107 20.288 34.933 64.48 ;
     RECT  34.933 0.832 36.981 64.48 ;
     RECT  36.981 0.832 37.803 64.736 ;
     RECT  37.803 0.832 37.859 9.632 ;
     RECT  37.803 11.072 38.819 64.736 ;
     RECT  38.819 16 39.083 64.736 ;
     RECT  37.859 0.832 39.934 9.568 ;
     RECT  39.934 5.696 40.245 9.568 ;
     RECT  38.819 11.072 40.261 14.624 ;
     RECT  39.083 16 40.261 64.608 ;
     RECT  40.245 5.696 40.309 9.76 ;
     RECT  40.261 11.072 40.309 64.608 ;
     RECT  39.934 0.832 40.401 4.384 ;
     RECT  40.309 5.696 40.814 64.608 ;
     RECT  40.814 5.696 40.883 64.736 ;
     RECT  40.883 5.696 40.939 64.608 ;
     RECT  40.401 0.996 41.027 4.384 ;
     RECT  41.027 3.392 41.131 4.384 ;
     RECT  40.939 5.696 41.891 64.48 ;
     RECT  41.891 16.768 42.155 64.48 ;
     RECT  41.891 5.696 42.227 15.392 ;
     RECT  41.027 0.996 42.565 1.86 ;
     RECT  41.131 4.032 42.565 4.384 ;
     RECT  42.227 6.396 43.043 15.392 ;
     RECT  42.565 0.996 43.253 4.384 ;
     RECT  43.253 0.996 43.331 4.832 ;
     RECT  42.155 16.832 43.861 64.48 ;
     RECT  43.043 6.396 43.909 14.816 ;
     RECT  43.861 16.512 44.483 64.48 ;
     RECT  43.909 6.272 44.581 14.816 ;
     RECT  44.483 16.512 44.581 29.152 ;
     RECT  44.483 30.464 44.581 64.48 ;
     RECT  43.331 0.996 44.867 3.872 ;
     RECT  44.581 6.272 45.035 29.152 ;
     RECT  44.867 0.996 45.059 2.848 ;
     RECT  44.581 30.464 45.547 64.736 ;
     RECT  45.035 6.272 45.611 28.86 ;
     RECT  45.547 30.784 46.123 64.736 ;
     RECT  45.611 6.272 46.259 15.712 ;
     RECT  46.259 6.272 46.357 7.26 ;
     RECT  46.357 5.696 46.443 7.26 ;
     RECT  45.611 17.024 46.581 28.86 ;
     RECT  46.389 3.968 46.693 4 ;
     RECT  46.693 3.968 46.787 4.32 ;
     RECT  46.787 4.288 46.827 4.32 ;
     RECT  46.123 30.912 46.835 64.736 ;
     RECT  46.581 17.024 46.933 29.472 ;
     RECT  46.259 8.768 46.965 15.712 ;
     RECT  46.933 17.024 46.965 29.6 ;
     RECT  46.965 8.768 47.275 29.6 ;
     RECT  47.275 8.768 47.363 12.66 ;
     RECT  47.275 14.08 47.797 29.6 ;
     RECT  46.835 30.912 47.797 63.84 ;
     RECT  47.797 14.08 47.939 63.84 ;
     RECT  46.443 6.208 47.989 7.26 ;
     RECT  47.989 5.632 48.058 7.26 ;
     RECT  48.058 6.396 48.373 7.26 ;
     RECT  47.363 8.768 48.373 9.888 ;
     RECT  47.939 15.488 48.555 18.208 ;
     RECT  47.939 19.712 48.563 25.44 ;
     RECT  47.363 11.584 48.93 12.66 ;
     RECT  48.93 11.584 49.003 12.96 ;
     RECT  48.373 6.396 49.091 9.888 ;
     RECT  49.003 11.796 49.525 12.96 ;
     RECT  47.939 26.816 49.619 63.84 ;
     RECT  49.525 11.796 49.813 13.728 ;
     RECT  48.555 15.488 49.813 18.06 ;
     RECT  49.091 8.896 50.155 9.888 ;
     RECT  48.563 19.968 50.195 25.44 ;
     RECT  50.155 9.6 50.771 9.888 ;
     RECT  49.619 26.816 51.013 29.216 ;
     RECT  49.619 30.528 51.013 63.84 ;
     RECT  49.813 11.796 51.109 18.06 ;
     RECT  51.109 11.328 51.573 18.208 ;
     RECT  50.195 19.968 51.573 24.416 ;
     RECT  51.573 11.328 51.637 24.416 ;
     RECT  51.637 10.304 51.81 24.416 ;
     RECT  51.81 10.304 51.829 25.056 ;
     RECT  51.013 26.816 51.875 63.84 ;
     RECT  51.829 10.304 51.923 25.248 ;
     RECT  51.923 16.576 51.925 25.248 ;
     RECT  51.875 26.816 51.925 30.048 ;
     RECT  51.923 10.304 51.947 14.88 ;
     RECT  51.947 10.304 52.261 14.816 ;
     RECT  51.925 16.576 52.651 30.048 ;
     RECT  52.651 16.896 53.035 30.048 ;
     RECT  51.875 31.488 53.035 63.84 ;
     RECT  53.035 17.024 53.075 30.048 ;
     RECT  53.035 38.208 53.075 63.84 ;
     RECT  53.035 31.488 53.123 36.64 ;
     RECT  53.123 31.488 53.173 31.52 ;
     RECT  53.173 31.36 53.267 31.52 ;
     RECT  52.261 10.112 53.605 14.816 ;
     RECT  53.075 17.196 53.626 24.608 ;
     RECT  53.605 10.112 53.675 14.88 ;
     RECT  53.075 25.984 54.035 30.048 ;
     RECT  53.675 10.112 54.179 14.24 ;
     RECT  53.075 38.336 54.179 63.84 ;
     RECT  53.123 32.896 54.515 36.64 ;
     RECT  54.179 38.336 54.517 61.6 ;
     RECT  54.035 25.984 54.563 29.408 ;
     RECT  54.517 38.144 54.586 61.6 ;
     RECT  53.626 17.196 54.661 18.208 ;
     RECT  54.179 10.112 54.709 14.048 ;
     RECT  54.709 9.664 54.778 14.048 ;
     RECT  54.661 17.024 54.947 18.208 ;
     RECT  54.586 38.336 55.043 61.6 ;
     RECT  54.515 35.712 55.189 36.64 ;
     RECT  54.778 10.112 55.275 14.048 ;
     RECT  55.189 35.712 55.275 36.704 ;
     RECT  53.626 19.776 55.331 24.608 ;
     RECT  53.267 31.488 55.525 31.52 ;
     RECT  54.563 27.328 55.541 29.408 ;
     RECT  55.275 35.712 55.571 36.512 ;
     RECT  55.525 31.04 55.595 31.52 ;
     RECT  55.541 27.328 55.619 29.6 ;
     RECT  55.043 38.796 55.669 61.6 ;
     RECT  54.179 63.104 55.669 63.84 ;
     RECT  54.563 25.984 55.813 26.016 ;
     RECT  55.669 38.796 55.907 63.84 ;
     RECT  55.619 27.328 56.003 29.408 ;
     RECT  55.907 38.796 56.427 63.136 ;
     RECT  54.947 17.024 56.483 18.06 ;
     RECT  55.331 19.776 56.483 23.46 ;
     RECT  56.427 38.796 56.579 58.336 ;
     RECT  56.427 59.712 56.579 63.136 ;
     RECT  55.813 24.832 57.059 26.016 ;
     RECT  56.579 49.596 57.059 58.336 ;
     RECT  56.579 59.968 57.059 63.136 ;
     RECT  56.483 20.16 57.541 23.46 ;
     RECT  54.515 32.896 57.589 34.4 ;
     RECT  55.571 35.712 57.589 36.384 ;
     RECT  57.589 32.896 57.658 36.384 ;
     RECT  56.579 38.796 57.909 47.84 ;
     RECT  57.059 49.596 57.909 53.28 ;
     RECT  57.658 35.776 57.963 36.384 ;
     RECT  57.909 38.08 57.982 53.28 ;
     RECT  57.059 54.656 58.019 58.336 ;
     RECT  58.019 54.848 58.117 58.336 ;
     RECT  57.059 59.968 58.117 62.752 ;
     RECT  55.275 10.112 58.163 13.664 ;
     RECT  57.541 20.16 58.165 24.672 ;
     RECT  56.003 27.996 58.165 29.408 ;
     RECT  57.059 25.984 58.259 26.016 ;
     RECT  57.982 38.796 58.283 53.28 ;
     RECT  58.165 27.996 58.338 29.536 ;
     RECT  55.595 31.488 58.338 31.52 ;
     RECT  58.338 27.996 58.357 31.52 ;
     RECT  58.357 27.584 58.411 31.52 ;
     RECT  58.283 38.796 58.451 51.68 ;
     RECT  58.117 54.848 58.451 62.752 ;
     RECT  58.165 19.776 58.53 24.672 ;
     RECT  58.53 19.712 58.603 24.672 ;
     RECT  58.163 10.496 58.691 13.664 ;
     RECT  58.691 11.796 58.739 13.664 ;
     RECT  58.451 42.368 58.835 51.68 ;
     RECT  57.658 32.896 59.315 34.4 ;
     RECT  58.835 42.368 59.315 46.24 ;
     RECT  58.283 53.12 59.749 53.28 ;
     RECT  58.451 54.848 59.749 62.176 ;
     RECT  58.835 47.808 59.765 51.68 ;
     RECT  59.749 53.12 59.765 53.408 ;
     RECT  58.451 38.796 59.797 40.608 ;
     RECT  59.765 47.808 59.797 53.408 ;
     RECT  59.749 54.848 59.797 62.24 ;
     RECT  59.315 42.368 59.883 45.792 ;
     RECT  59.797 47.808 59.883 62.24 ;
     RECT  58.603 19.776 59.891 24.672 ;
     RECT  58.411 31.424 59.891 31.52 ;
     RECT  57.963 36.352 59.891 36.384 ;
     RECT  59.883 42.368 59.891 45.664 ;
     RECT  59.883 48.768 59.891 62.24 ;
     RECT  56.483 17.196 59.989 18.06 ;
     RECT  59.891 19.776 59.989 21.216 ;
     RECT  59.891 42.88 60.083 45.664 ;
     RECT  58.411 27.584 60.085 29.536 ;
     RECT  59.315 32.896 60.131 34.26 ;
     RECT  60.083 43.776 60.139 45.664 ;
     RECT  60.085 27.584 60.154 29.664 ;
     RECT  59.989 17.196 60.179 21.216 ;
     RECT  60.131 33.024 60.179 34.26 ;
     RECT  60.179 21.184 60.467 21.216 ;
     RECT  59.891 22.596 61.043 24.672 ;
     RECT  60.154 27.584 61.043 29.536 ;
     RECT  59.891 48.768 61.043 57.952 ;
     RECT  60.179 17.196 61.187 19.808 ;
     RECT  61.043 49.472 61.227 57.952 ;
     RECT  61.227 57.792 61.301 57.952 ;
     RECT  59.891 59.264 61.301 62.24 ;
     RECT  60.373 47.296 61.475 47.328 ;
     RECT  61.227 49.472 61.483 56.224 ;
     RECT  61.043 27.996 61.619 29.536 ;
     RECT  59.797 38.4 61.619 40.608 ;
     RECT  60.139 43.776 61.619 45.06 ;
     RECT  61.483 49.472 61.811 53.536 ;
     RECT  61.301 57.792 61.867 62.24 ;
     RECT  45.059 0.996 62.16 1.86 ;
     RECT  49.091 6.396 62.16 7.26 ;
     RECT  58.739 11.796 62.16 12.66 ;
     RECT  61.187 17.196 62.16 18.06 ;
     RECT  61.043 22.596 62.16 23.46 ;
     RECT  61.619 27.996 62.16 29.024 ;
     RECT  60.179 33.396 62.16 34.26 ;
     RECT  61.619 38.796 62.16 40.608 ;
     RECT  61.619 44.196 62.16 45.06 ;
     RECT  61.811 49.472 62.187 53.152 ;
     RECT  62.16 1.572 62.352 1.86 ;
     RECT  62.16 6.972 62.352 7.26 ;
     RECT  62.16 12.372 62.352 12.66 ;
     RECT  62.16 17.772 62.352 18.06 ;
     RECT  62.16 23.172 62.352 23.46 ;
     RECT  62.16 33.972 62.352 34.26 ;
     RECT  62.16 39.372 62.352 40.608 ;
     RECT  62.16 44.48 62.352 45.06 ;
     RECT  62.187 49.472 62.352 51.296 ;
     RECT  61.483 54.976 62.352 56.224 ;
     RECT  61.867 59.136 62.352 62.24 ;
     RECT  61.187 19.776 62.483 19.808 ;
     RECT  62.16 28.416 62.483 29.024 ;
     RECT  62.352 49.472 62.483 49.504 ;
     RECT  62.352 51.264 62.483 51.296 ;
     RECT  62.483 28.416 62.531 28.448 ;
     RECT  62.352 54.976 62.699 55.456 ;
     RECT  62.645 57.024 62.723 57.056 ;
     RECT  61.525 47.232 62.771 47.264 ;
     RECT  62.187 53.056 62.771 53.152 ;
     RECT  62.771 53.12 62.867 53.152 ;
     RECT  62.352 59.136 62.867 60.256 ;
     RECT  62.352 62.208 62.867 62.24 ;
     RECT  62.867 60.224 63.059 60.256 ;
     RECT  63.013 37.504 63.083 37.536 ;
     RECT  62.352 40.576 63.083 40.608 ;
     RECT  62.352 44.48 63.083 44.512 ;
     RECT  62.699 55.424 63.299 55.456 ;
     RECT  62.352 23.296 63.539 23.328 ;
     RECT  59.891 31.488 63.875 31.52 ;
    LAYER M7 ;
     RECT  15.232 0.245 15.264 0.309 ;
     RECT  32.704 0.181 32.736 0.309 ;
     RECT  21.312 0.373 21.344 0.531 ;
     RECT  32.256 0.309 32.736 0.531 ;
     RECT  6.256 0.531 6.544 0.565 ;
     RECT  11.656 0.531 11.944 0.565 ;
     RECT  15.232 0.309 15.456 0.565 ;
     RECT  0.856 0.531 1.144 0.629 ;
     RECT  5.312 0.565 6.544 0.629 ;
     RECT  14.656 0.565 15.456 0.629 ;
     RECT  10.688 0.565 11.944 0.693 ;
     RECT  0.856 0.629 1.504 0.757 ;
     RECT  2.88 0.629 6.688 0.757 ;
     RECT  13.824 0.629 15.456 0.757 ;
     RECT  0.856 0.757 7.072 0.821 ;
     RECT  8.64 0.693 8.672 0.821 ;
     RECT  10.24 0.693 11.944 0.821 ;
     RECT  13.312 0.757 15.456 0.821 ;
     RECT  21.312 0.531 22.744 0.821 ;
     RECT  32.256 0.531 33.544 0.821 ;
     RECT  0.448 0.821 7.072 1.397 ;
     RECT  21.184 0.821 22.744 1.397 ;
     RECT  25.664 0.437 25.696 1.397 ;
     RECT  44.056 0.531 44.344 1.397 ;
     RECT  0.128 1.397 7.072 1.973 ;
     RECT  8.384 0.821 15.456 1.973 ;
     RECT  17.056 0.531 17.344 1.973 ;
     RECT  20.864 1.397 22.744 1.973 ;
     RECT  27.856 0.531 28.144 1.973 ;
     RECT  20.416 1.973 22.744 2.101 ;
     RECT  25.664 1.397 25.888 2.101 ;
     RECT  27.856 1.973 29.408 2.101 ;
     RECT  20.416 2.101 23.904 2.165 ;
     RECT  27.856 2.101 30.56 2.165 ;
     RECT  31.872 0.821 33.544 2.165 ;
     RECT  35.008 1.397 35.04 2.165 ;
     RECT  37.056 2.037 37.088 2.165 ;
     RECT  25.664 2.101 26.4 2.219 ;
     RECT  40.32 0.821 40.352 2.229 ;
     RECT  20.416 2.165 24.096 2.293 ;
     RECT  0.128 1.973 17.344 2.485 ;
     RECT  18.944 2.293 18.976 2.485 ;
     RECT  38.656 0.531 38.944 2.549 ;
     RECT  40.32 2.229 40.992 2.549 ;
     RECT  0.128 2.485 18.976 2.603 ;
     RECT  0.128 2.603 18.848 2.731 ;
     RECT  27.856 2.165 33.544 2.741 ;
     RECT  35.008 2.165 37.088 2.741 ;
     RECT  25.856 2.219 26.4 2.805 ;
     RECT  27.856 2.741 37.088 2.805 ;
     RECT  20.416 2.293 24.48 2.987 ;
     RECT  25.856 2.805 37.088 3.061 ;
     RECT  38.656 2.549 40.992 3.381 ;
     RECT  25.856 3.061 37.152 3.435 ;
     RECT  25.856 3.435 35.296 3.499 ;
     RECT  20.416 2.987 24.096 3.755 ;
     RECT  0.128 2.731 18.72 3.829 ;
     RECT  20.864 3.755 24.096 3.883 ;
     RECT  36.864 3.435 37.152 3.957 ;
     RECT  38.656 3.381 41.12 3.957 ;
     RECT  36.864 3.957 41.12 4.075 ;
     RECT  46.4 3.957 46.432 4.277 ;
     RECT  20.928 3.883 24.096 4.533 ;
     RECT  25.856 3.499 28.832 4.533 ;
     RECT  0.064 3.829 18.72 4.597 ;
     RECT  43.264 1.397 44.344 4.843 ;
     RECT  0.064 4.597 18.848 4.853 ;
     RECT  0.064 4.853 19.488 5.163 ;
     RECT  20.928 4.533 28.832 5.163 ;
     RECT  30.528 3.499 35.296 5.237 ;
     RECT  36.864 4.075 40.992 5.237 ;
     RECT  22.336 5.163 28.832 5.365 ;
     RECT  30.528 5.237 40.992 5.365 ;
     RECT  22.336 5.365 40.992 5.419 ;
     RECT  46.4 4.277 46.816 5.621 ;
     RECT  20.928 5.163 20.96 5.739 ;
     RECT  46.4 5.621 48.032 5.739 ;
     RECT  44.056 4.843 44.344 6.773 ;
     RECT  46.528 5.739 48.032 6.773 ;
     RECT  49.456 0.531 49.744 6.773 ;
     RECT  46.528 6.773 49.744 6.827 ;
     RECT  34.944 5.419 40.992 6.891 ;
     RECT  0.064 5.163 19.36 7.349 ;
     RECT  22.336 5.419 33.544 7.349 ;
     RECT  34.944 6.891 38.944 7.349 ;
     RECT  40.96 6.891 40.992 7.349 ;
     RECT  44.056 6.773 44.896 7.349 ;
     RECT  48 6.827 49.744 8.171 ;
     RECT  40.96 7.349 41.888 8.437 ;
     RECT  43.264 7.349 44.896 8.501 ;
     RECT  46.528 6.827 46.56 8.501 ;
     RECT  0.064 7.349 38.944 8.619 ;
     RECT  43.264 8.501 46.56 8.683 ;
     RECT  49.456 8.171 49.744 8.885 ;
     RECT  48 8.171 48.032 9.195 ;
     RECT  0.064 8.619 34.848 9.451 ;
     RECT  46.528 8.683 46.56 9.589 ;
     RECT  49.456 8.885 50.144 9.589 ;
     RECT  54.856 0.531 55.144 9.653 ;
     RECT  40.448 8.437 41.888 9.717 ;
     RECT  43.264 8.683 45.152 9.771 ;
     RECT  54.72 9.653 55.144 10.165 ;
     RECT  43.904 9.771 45.152 10.293 ;
     RECT  46.528 9.589 47.328 10.293 ;
     RECT  25.088 9.451 34.848 10.347 ;
     RECT  40.256 9.717 41.888 10.347 ;
     RECT  36.544 8.619 38.944 10.421 ;
     RECT  43.904 10.293 47.328 10.859 ;
     RECT  0.064 9.451 23.52 10.923 ;
     RECT  54.72 10.165 55.264 11.179 ;
     RECT  35.456 10.421 38.944 11.189 ;
     RECT  40.256 10.347 41.248 11.189 ;
     RECT  20.736 10.923 23.52 11.317 ;
     RECT  25.088 10.347 33.544 11.317 ;
     RECT  43.904 10.859 46.56 11.509 ;
     RECT  52.8 11.317 52.832 11.509 ;
     RECT  49.456 9.589 50.592 11.573 ;
     RECT  0.064 10.923 19.104 12.213 ;
     RECT  20.736 11.317 33.544 12.213 ;
     RECT  48.96 11.573 50.592 12.213 ;
     RECT  52.48 11.509 52.832 12.213 ;
     RECT  0.064 12.213 33.544 12.779 ;
     RECT  43.84 11.509 46.56 12.779 ;
     RECT  35.456 11.189 41.248 12.789 ;
     RECT  48.192 12.213 50.592 12.853 ;
     RECT  52.288 12.213 52.832 12.853 ;
     RECT  43.904 12.779 46.56 13.173 ;
     RECT  0.064 12.779 26.528 13.227 ;
     RECT  27.856 12.779 33.544 13.301 ;
     RECT  35.008 12.789 41.248 13.301 ;
     RECT  48.192 12.853 52.832 13.557 ;
     RECT  54.856 11.179 55.264 13.557 ;
     RECT  43.904 13.173 46.688 13.621 ;
     RECT  48.192 13.557 55.264 13.621 ;
     RECT  43.904 13.621 55.264 14.059 ;
     RECT  26.176 13.227 26.528 14.197 ;
     RECT  27.856 13.301 41.248 14.197 ;
     RECT  43.904 14.059 55.144 14.389 ;
     RECT  0.192 13.227 24.8 14.645 ;
     RECT  26.176 14.197 41.248 14.709 ;
     RECT  0.128 14.645 24.8 14.773 ;
     RECT  26.176 14.709 42.144 14.955 ;
     RECT  0.064 14.773 24.8 14.965 ;
     RECT  34.88 14.955 42.144 16.043 ;
     RECT  0.064 14.965 24.864 16.117 ;
     RECT  26.176 14.955 33.544 16.117 ;
     RECT  34.88 16.043 40.416 16.427 ;
     RECT  35.136 16.427 40.416 17.643 ;
     RECT  43.584 14.389 55.144 17.707 ;
     RECT  0.064 16.117 33.544 18.165 ;
     RECT  0.064 18.165 33.824 18.229 ;
     RECT  35.136 17.643 38.944 18.229 ;
     RECT  41.728 16.043 42.144 18.421 ;
     RECT  40.384 17.643 40.416 18.549 ;
     RECT  41.728 18.421 42.528 18.549 ;
     RECT  60.256 0.531 60.544 18.613 ;
     RECT  60.032 18.613 60.544 19.115 ;
     RECT  40.384 18.549 42.528 19.125 ;
     RECT  43.904 17.707 55.144 19.125 ;
     RECT  58.56 19.701 58.592 19.765 ;
     RECT  0.064 18.229 38.944 19.893 ;
     RECT  40.384 19.125 55.144 19.893 ;
     RECT  60.096 19.115 60.544 20.587 ;
     RECT  58.176 19.765 58.592 22.315 ;
     RECT  58.176 22.315 58.336 23.083 ;
     RECT  58.304 23.083 58.336 24.683 ;
     RECT  58.176 25.973 58.208 27.573 ;
     RECT  60.256 20.587 60.544 27.829 ;
     RECT  58.176 27.573 58.4 29.045 ;
     RECT  0.064 19.893 55.144 29.557 ;
     RECT  60.096 27.829 60.544 29.675 ;
     RECT  57.6 29.045 58.4 30.507 ;
     RECT  0.064 29.557 55.584 31.083 ;
     RECT  57.6 30.507 57.632 33.013 ;
     RECT  60.256 29.675 60.544 33.013 ;
     RECT  57.6 33.013 57.952 33.845 ;
     RECT  0.064 31.083 55.144 36.661 ;
     RECT  0.064 36.661 55.264 37.483 ;
     RECT  57.472 33.845 57.952 38.123 ;
     RECT  0.192 37.483 55.264 39.861 ;
     RECT  57.472 38.123 57.504 39.861 ;
     RECT  0.192 39.861 57.504 39.915 ;
     RECT  0.192 39.915 57.376 39.989 ;
     RECT  0.064 39.989 57.376 41.781 ;
     RECT  60.096 33.013 60.544 44.021 ;
     RECT  63.04 37.493 63.072 44.523 ;
     RECT  0.064 41.781 58.272 45.301 ;
     RECT  0.064 45.301 58.528 47.083 ;
     RECT  0.064 47.083 58.208 47.787 ;
     RECT  59.84 44.021 60.544 49.323 ;
     RECT  0.064 47.787 58.08 49.461 ;
     RECT  0.064 49.461 58.144 50.677 ;
     RECT  0.064 50.677 58.656 50.795 ;
     RECT  60.096 49.323 60.544 51.637 ;
     RECT  62.144 51.253 62.176 51.637 ;
     RECT  58.24 50.795 58.656 51.893 ;
     RECT  60.096 51.637 62.176 51.893 ;
     RECT  58.24 51.893 62.176 53.109 ;
     RECT  0.064 50.795 56.928 53.291 ;
     RECT  0.128 53.291 56.608 54.709 ;
     RECT  0.064 54.709 56.608 54.837 ;
     RECT  58.24 53.109 62.368 54.837 ;
     RECT  0.064 54.837 62.368 54.965 ;
     RECT  0.064 54.965 62.688 55.467 ;
     RECT  0.128 55.467 62.688 56.949 ;
     RECT  0.064 56.949 62.688 58.219 ;
     RECT  58.24 58.219 62.688 59.179 ;
     RECT  58.24 59.179 62.496 60.011 ;
     RECT  58.24 60.011 61.856 60.331 ;
     RECT  58.624 60.331 61.856 61.419 ;
     RECT  59.264 61.419 61.856 61.483 ;
     RECT  60.256 61.483 61.856 61.611 ;
     RECT  0.064 58.219 56.608 61.739 ;
     RECT  53.888 61.739 56.608 61.867 ;
     RECT  53.952 61.867 56.608 61.931 ;
     RECT  53.952 61.931 55.776 62.379 ;
     RECT  0.064 61.739 52 62.763 ;
     RECT  54.856 62.379 55.776 62.763 ;
     RECT  0.064 62.763 50.208 63.339 ;
     RECT  51.968 62.763 52 63.339 ;
     RECT  0.512 63.339 49.744 63.403 ;
     RECT  0.856 63.403 47.456 63.467 ;
     RECT  5.632 63.467 46.368 63.531 ;
     RECT  0.856 63.467 4.256 63.595 ;
     RECT  5.632 63.531 8.288 63.595 ;
     RECT  49.344 63.403 49.744 63.595 ;
     RECT  2.624 63.595 4.256 63.723 ;
     RECT  3.52 63.723 4.256 63.787 ;
     RECT  10.048 63.531 46.368 63.787 ;
     RECT  3.52 63.787 3.68 63.851 ;
     RECT  5.888 63.595 8.288 63.851 ;
     RECT  14.4 63.787 46.368 63.851 ;
     RECT  14.4 63.851 46.24 63.915 ;
     RECT  0.856 63.595 1.144 63.999 ;
     RECT  5.888 63.851 7.456 63.999 ;
     RECT  10.048 63.787 12.896 63.999 ;
     RECT  49.456 63.595 49.744 63.999 ;
     RECT  54.856 62.763 55.144 63.999 ;
     RECT  60.256 61.611 60.544 63.999 ;
     RECT  7.424 63.999 7.456 64.043 ;
     RECT  14.528 63.915 46.24 64.043 ;
     RECT  14.528 64.043 17.504 64.107 ;
     RECT  10.048 63.999 11.04 64.235 ;
     RECT  5.888 63.999 5.92 64.299 ;
     RECT  3.52 63.851 3.552 64.363 ;
     RECT  18.816 64.043 46.24 64.363 ;
     RECT  25.344 64.363 37.024 64.427 ;
     RECT  43.072 64.363 45.664 64.427 ;
     RECT  11.008 64.235 11.04 64.491 ;
     RECT  15.552 64.107 17.504 64.491 ;
     RECT  25.472 64.427 37.024 64.491 ;
     RECT  39.04 64.363 41.504 64.491 ;
     RECT  43.072 64.427 43.36 64.491 ;
     RECT  45.632 64.427 45.664 64.491 ;
     RECT  12.8 63.999 12.896 64.555 ;
     RECT  12.8 64.555 12.832 64.619 ;
     RECT  19.776 64.363 23.648 64.619 ;
     RECT  26.368 64.491 27.296 64.619 ;
     RECT  29.184 64.491 31.456 64.619 ;
     RECT  39.04 64.491 40.928 64.619 ;
     RECT  15.552 64.491 16.48 64.683 ;
     RECT  27.136 64.619 27.296 64.683 ;
     RECT  15.552 64.683 15.584 64.747 ;
     RECT  19.776 64.619 21.472 64.747 ;
     RECT  22.848 64.619 23.648 64.747 ;
     RECT  27.136 64.683 27.168 64.747 ;
     RECT  29.184 64.619 29.216 64.747 ;
     RECT  31.424 64.619 31.456 64.747 ;
     RECT  36.992 64.491 37.024 64.747 ;
     RECT  39.04 64.619 39.072 64.747 ;
     RECT  40.832 64.619 40.864 64.747 ;
  END
END dsfd_l2r_vr_512x1__hq_SW
END LIBRARY
